VERSION 5.8 ;
BUSBITCHARS "[]" ;
DIVIDERCHAR "/" ;
UNITS
    DATABASE MICRONS 1000 ;
END UNITS

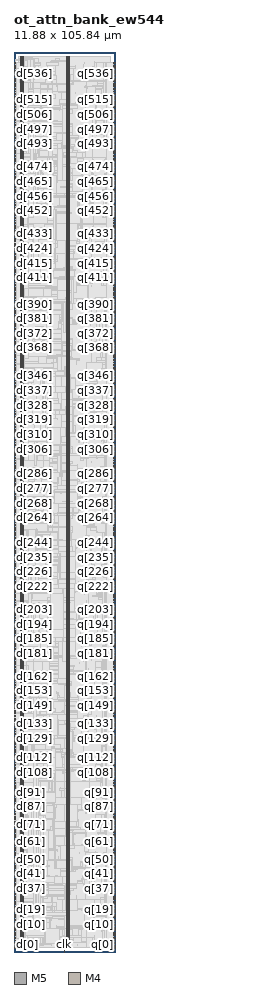
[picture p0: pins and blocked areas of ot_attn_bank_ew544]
MACRO ot_attn_bank_ew544
  FOREIGN ot_attn_bank_ew544 0 0 ;
  CLASS BLOCK ;
  SIZE 11.88 BY 105.84 ;
  PIN clk
    DIRECTION INPUT ;
    USE SIGNAL ;
    PORT
      LAYER M5 ;
        RECT  5.904 0 5.928 0.192 ;
    END
  END clk
  PIN d[0]
    DIRECTION INPUT ;
    USE SIGNAL ;
    PORT
      LAYER M4 ;
        RECT  0 0.384 0.192 0.408 ;
    END
  END d[0]
  PIN d[100]
    DIRECTION INPUT ;
    USE SIGNAL ;
    PORT
      LAYER M4 ;
        RECT  0 19.584 0.192 19.608 ;
    END
  END d[100]
  PIN d[101]
    DIRECTION INPUT ;
    USE SIGNAL ;
    PORT
      LAYER M4 ;
        RECT  0 19.776 0.192 19.8 ;
    END
  END d[101]
  PIN d[102]
    DIRECTION INPUT ;
    USE SIGNAL ;
    PORT
      LAYER M4 ;
        RECT  0 19.968 0.192 19.992 ;
    END
  END d[102]
  PIN d[103]
    DIRECTION INPUT ;
    USE SIGNAL ;
    PORT
      LAYER M4 ;
        RECT  0 20.16 0.192 20.184 ;
    END
  END d[103]
  PIN d[104]
    DIRECTION INPUT ;
    USE SIGNAL ;
    PORT
      LAYER M4 ;
        RECT  0 20.352 0.192 20.376 ;
    END
  END d[104]
  PIN d[105]
    DIRECTION INPUT ;
    USE SIGNAL ;
    PORT
      LAYER M4 ;
        RECT  0 20.544 0.192 20.568 ;
    END
  END d[105]
  PIN d[106]
    DIRECTION INPUT ;
    USE SIGNAL ;
    PORT
      LAYER M4 ;
        RECT  0 20.736 0.192 20.76 ;
    END
  END d[106]
  PIN d[107]
    DIRECTION INPUT ;
    USE SIGNAL ;
    PORT
      LAYER M4 ;
        RECT  0 20.928 0.192 20.952 ;
    END
  END d[107]
  PIN d[108]
    DIRECTION INPUT ;
    USE SIGNAL ;
    PORT
      LAYER M4 ;
        RECT  0 21.12 0.192 21.144 ;
    END
  END d[108]
  PIN d[109]
    DIRECTION INPUT ;
    USE SIGNAL ;
    PORT
      LAYER M4 ;
        RECT  0 21.312 0.192 21.336 ;
    END
  END d[109]
  PIN d[10]
    DIRECTION INPUT ;
    USE SIGNAL ;
    PORT
      LAYER M4 ;
        RECT  0 2.304 0.192 2.328 ;
    END
  END d[10]
  PIN d[110]
    DIRECTION INPUT ;
    USE SIGNAL ;
    PORT
      LAYER M4 ;
        RECT  0 21.504 0.192 21.528 ;
    END
  END d[110]
  PIN d[111]
    DIRECTION INPUT ;
    USE SIGNAL ;
    PORT
      LAYER M4 ;
        RECT  0 21.696 0.192 21.72 ;
    END
  END d[111]
  PIN d[112]
    DIRECTION INPUT ;
    USE SIGNAL ;
    PORT
      LAYER M4 ;
        RECT  0 21.888 0.192 21.912 ;
    END
  END d[112]
  PIN d[113]
    DIRECTION INPUT ;
    USE SIGNAL ;
    PORT
      LAYER M4 ;
        RECT  0 22.08 0.192 22.104 ;
    END
  END d[113]
  PIN d[114]
    DIRECTION INPUT ;
    USE SIGNAL ;
    PORT
      LAYER M4 ;
        RECT  0 22.272 0.192 22.296 ;
    END
  END d[114]
  PIN d[115]
    DIRECTION INPUT ;
    USE SIGNAL ;
    PORT
      LAYER M4 ;
        RECT  0 22.464 0.192 22.488 ;
    END
  END d[115]
  PIN d[116]
    DIRECTION INPUT ;
    USE SIGNAL ;
    PORT
      LAYER M4 ;
        RECT  0 22.656 0.192 22.68 ;
    END
  END d[116]
  PIN d[117]
    DIRECTION INPUT ;
    USE SIGNAL ;
    PORT
      LAYER M4 ;
        RECT  0 22.848 0.192 22.872 ;
    END
  END d[117]
  PIN d[118]
    DIRECTION INPUT ;
    USE SIGNAL ;
    PORT
      LAYER M4 ;
        RECT  0 23.04 0.192 23.064 ;
    END
  END d[118]
  PIN d[119]
    DIRECTION INPUT ;
    USE SIGNAL ;
    PORT
      LAYER M4 ;
        RECT  0 23.232 0.192 23.256 ;
    END
  END d[119]
  PIN d[11]
    DIRECTION INPUT ;
    USE SIGNAL ;
    PORT
      LAYER M4 ;
        RECT  0 2.496 0.192 2.52 ;
    END
  END d[11]
  PIN d[120]
    DIRECTION INPUT ;
    USE SIGNAL ;
    PORT
      LAYER M4 ;
        RECT  0 23.424 0.192 23.448 ;
    END
  END d[120]
  PIN d[121]
    DIRECTION INPUT ;
    USE SIGNAL ;
    PORT
      LAYER M4 ;
        RECT  0 23.616 0.192 23.64 ;
    END
  END d[121]
  PIN d[122]
    DIRECTION INPUT ;
    USE SIGNAL ;
    PORT
      LAYER M4 ;
        RECT  0 23.808 0.192 23.832 ;
    END
  END d[122]
  PIN d[123]
    DIRECTION INPUT ;
    USE SIGNAL ;
    PORT
      LAYER M4 ;
        RECT  0 24 0.192 24.024 ;
    END
  END d[123]
  PIN d[124]
    DIRECTION INPUT ;
    USE SIGNAL ;
    PORT
      LAYER M4 ;
        RECT  0 24.192 0.192 24.216 ;
    END
  END d[124]
  PIN d[125]
    DIRECTION INPUT ;
    USE SIGNAL ;
    PORT
      LAYER M4 ;
        RECT  0 24.384 0.192 24.408 ;
    END
  END d[125]
  PIN d[126]
    DIRECTION INPUT ;
    USE SIGNAL ;
    PORT
      LAYER M4 ;
        RECT  0 24.576 0.192 24.6 ;
    END
  END d[126]
  PIN d[127]
    DIRECTION INPUT ;
    USE SIGNAL ;
    PORT
      LAYER M4 ;
        RECT  0 24.768 0.192 24.792 ;
    END
  END d[127]
  PIN d[128]
    DIRECTION INPUT ;
    USE SIGNAL ;
    PORT
      LAYER M4 ;
        RECT  0 24.96 0.192 24.984 ;
    END
  END d[128]
  PIN d[129]
    DIRECTION INPUT ;
    USE SIGNAL ;
    PORT
      LAYER M4 ;
        RECT  0 25.152 0.192 25.176 ;
    END
  END d[129]
  PIN d[12]
    DIRECTION INPUT ;
    USE SIGNAL ;
    PORT
      LAYER M4 ;
        RECT  0 2.688 0.192 2.712 ;
    END
  END d[12]
  PIN d[130]
    DIRECTION INPUT ;
    USE SIGNAL ;
    PORT
      LAYER M4 ;
        RECT  0 25.344 0.192 25.368 ;
    END
  END d[130]
  PIN d[131]
    DIRECTION INPUT ;
    USE SIGNAL ;
    PORT
      LAYER M4 ;
        RECT  0 25.536 0.192 25.56 ;
    END
  END d[131]
  PIN d[132]
    DIRECTION INPUT ;
    USE SIGNAL ;
    PORT
      LAYER M4 ;
        RECT  0 25.728 0.192 25.752 ;
    END
  END d[132]
  PIN d[133]
    DIRECTION INPUT ;
    USE SIGNAL ;
    PORT
      LAYER M4 ;
        RECT  0 25.92 0.192 25.944 ;
    END
  END d[133]
  PIN d[134]
    DIRECTION INPUT ;
    USE SIGNAL ;
    PORT
      LAYER M4 ;
        RECT  0 26.112 0.192 26.136 ;
    END
  END d[134]
  PIN d[135]
    DIRECTION INPUT ;
    USE SIGNAL ;
    PORT
      LAYER M4 ;
        RECT  0 26.304 0.192 26.328 ;
    END
  END d[135]
  PIN d[136]
    DIRECTION INPUT ;
    USE SIGNAL ;
    PORT
      LAYER M4 ;
        RECT  0 26.496 0.192 26.52 ;
    END
  END d[136]
  PIN d[137]
    DIRECTION INPUT ;
    USE SIGNAL ;
    PORT
      LAYER M4 ;
        RECT  0 26.688 0.192 26.712 ;
    END
  END d[137]
  PIN d[138]
    DIRECTION INPUT ;
    USE SIGNAL ;
    PORT
      LAYER M4 ;
        RECT  0 26.88 0.192 26.904 ;
    END
  END d[138]
  PIN d[139]
    DIRECTION INPUT ;
    USE SIGNAL ;
    PORT
      LAYER M4 ;
        RECT  0 27.072 0.192 27.096 ;
    END
  END d[139]
  PIN d[13]
    DIRECTION INPUT ;
    USE SIGNAL ;
    PORT
      LAYER M4 ;
        RECT  0 2.88 0.192 2.904 ;
    END
  END d[13]
  PIN d[140]
    DIRECTION INPUT ;
    USE SIGNAL ;
    PORT
      LAYER M4 ;
        RECT  0 27.264 0.192 27.288 ;
    END
  END d[140]
  PIN d[141]
    DIRECTION INPUT ;
    USE SIGNAL ;
    PORT
      LAYER M4 ;
        RECT  0 27.456 0.192 27.48 ;
    END
  END d[141]
  PIN d[142]
    DIRECTION INPUT ;
    USE SIGNAL ;
    PORT
      LAYER M4 ;
        RECT  0 27.648 0.192 27.672 ;
    END
  END d[142]
  PIN d[143]
    DIRECTION INPUT ;
    USE SIGNAL ;
    PORT
      LAYER M4 ;
        RECT  0 27.84 0.192 27.864 ;
    END
  END d[143]
  PIN d[144]
    DIRECTION INPUT ;
    USE SIGNAL ;
    PORT
      LAYER M4 ;
        RECT  0 28.032 0.192 28.056 ;
    END
  END d[144]
  PIN d[145]
    DIRECTION INPUT ;
    USE SIGNAL ;
    PORT
      LAYER M4 ;
        RECT  0 28.224 0.192 28.248 ;
    END
  END d[145]
  PIN d[146]
    DIRECTION INPUT ;
    USE SIGNAL ;
    PORT
      LAYER M4 ;
        RECT  0 28.416 0.192 28.44 ;
    END
  END d[146]
  PIN d[147]
    DIRECTION INPUT ;
    USE SIGNAL ;
    PORT
      LAYER M4 ;
        RECT  0 28.608 0.192 28.632 ;
    END
  END d[147]
  PIN d[148]
    DIRECTION INPUT ;
    USE SIGNAL ;
    PORT
      LAYER M4 ;
        RECT  0 28.8 0.192 28.824 ;
    END
  END d[148]
  PIN d[149]
    DIRECTION INPUT ;
    USE SIGNAL ;
    PORT
      LAYER M4 ;
        RECT  0 28.992 0.192 29.016 ;
    END
  END d[149]
  PIN d[14]
    DIRECTION INPUT ;
    USE SIGNAL ;
    PORT
      LAYER M4 ;
        RECT  0 3.072 0.192 3.096 ;
    END
  END d[14]
  PIN d[150]
    DIRECTION INPUT ;
    USE SIGNAL ;
    PORT
      LAYER M4 ;
        RECT  0 29.184 0.192 29.208 ;
    END
  END d[150]
  PIN d[151]
    DIRECTION INPUT ;
    USE SIGNAL ;
    PORT
      LAYER M4 ;
        RECT  0 29.376 0.192 29.4 ;
    END
  END d[151]
  PIN d[152]
    DIRECTION INPUT ;
    USE SIGNAL ;
    PORT
      LAYER M4 ;
        RECT  0 29.568 0.192 29.592 ;
    END
  END d[152]
  PIN d[153]
    DIRECTION INPUT ;
    USE SIGNAL ;
    PORT
      LAYER M4 ;
        RECT  0 29.76 0.192 29.784 ;
    END
  END d[153]
  PIN d[154]
    DIRECTION INPUT ;
    USE SIGNAL ;
    PORT
      LAYER M4 ;
        RECT  0 29.952 0.192 29.976 ;
    END
  END d[154]
  PIN d[155]
    DIRECTION INPUT ;
    USE SIGNAL ;
    PORT
      LAYER M4 ;
        RECT  0 30.144 0.192 30.168 ;
    END
  END d[155]
  PIN d[156]
    DIRECTION INPUT ;
    USE SIGNAL ;
    PORT
      LAYER M4 ;
        RECT  0 30.336 0.192 30.36 ;
    END
  END d[156]
  PIN d[157]
    DIRECTION INPUT ;
    USE SIGNAL ;
    PORT
      LAYER M4 ;
        RECT  0 30.528 0.192 30.552 ;
    END
  END d[157]
  PIN d[158]
    DIRECTION INPUT ;
    USE SIGNAL ;
    PORT
      LAYER M4 ;
        RECT  0 30.72 0.192 30.744 ;
    END
  END d[158]
  PIN d[159]
    DIRECTION INPUT ;
    USE SIGNAL ;
    PORT
      LAYER M4 ;
        RECT  0 30.912 0.192 30.936 ;
    END
  END d[159]
  PIN d[15]
    DIRECTION INPUT ;
    USE SIGNAL ;
    PORT
      LAYER M4 ;
        RECT  0 3.264 0.192 3.288 ;
    END
  END d[15]
  PIN d[160]
    DIRECTION INPUT ;
    USE SIGNAL ;
    PORT
      LAYER M4 ;
        RECT  0 31.104 0.192 31.128 ;
    END
  END d[160]
  PIN d[161]
    DIRECTION INPUT ;
    USE SIGNAL ;
    PORT
      LAYER M4 ;
        RECT  0 31.296 0.192 31.32 ;
    END
  END d[161]
  PIN d[162]
    DIRECTION INPUT ;
    USE SIGNAL ;
    PORT
      LAYER M4 ;
        RECT  0 31.488 0.192 31.512 ;
    END
  END d[162]
  PIN d[163]
    DIRECTION INPUT ;
    USE SIGNAL ;
    PORT
      LAYER M4 ;
        RECT  0 31.68 0.192 31.704 ;
    END
  END d[163]
  PIN d[164]
    DIRECTION INPUT ;
    USE SIGNAL ;
    PORT
      LAYER M4 ;
        RECT  0 31.872 0.192 31.896 ;
    END
  END d[164]
  PIN d[165]
    DIRECTION INPUT ;
    USE SIGNAL ;
    PORT
      LAYER M4 ;
        RECT  0 32.064 0.192 32.088 ;
    END
  END d[165]
  PIN d[166]
    DIRECTION INPUT ;
    USE SIGNAL ;
    PORT
      LAYER M4 ;
        RECT  0 32.256 0.192 32.28 ;
    END
  END d[166]
  PIN d[167]
    DIRECTION INPUT ;
    USE SIGNAL ;
    PORT
      LAYER M4 ;
        RECT  0 32.448 0.192 32.472 ;
    END
  END d[167]
  PIN d[168]
    DIRECTION INPUT ;
    USE SIGNAL ;
    PORT
      LAYER M4 ;
        RECT  0 32.64 0.192 32.664 ;
    END
  END d[168]
  PIN d[169]
    DIRECTION INPUT ;
    USE SIGNAL ;
    PORT
      LAYER M4 ;
        RECT  0 32.832 0.192 32.856 ;
    END
  END d[169]
  PIN d[16]
    DIRECTION INPUT ;
    USE SIGNAL ;
    PORT
      LAYER M4 ;
        RECT  0 3.456 0.192 3.48 ;
    END
  END d[16]
  PIN d[170]
    DIRECTION INPUT ;
    USE SIGNAL ;
    PORT
      LAYER M4 ;
        RECT  0 33.024 0.192 33.048 ;
    END
  END d[170]
  PIN d[171]
    DIRECTION INPUT ;
    USE SIGNAL ;
    PORT
      LAYER M4 ;
        RECT  0 33.216 0.192 33.24 ;
    END
  END d[171]
  PIN d[172]
    DIRECTION INPUT ;
    USE SIGNAL ;
    PORT
      LAYER M4 ;
        RECT  0 33.408 0.192 33.432 ;
    END
  END d[172]
  PIN d[173]
    DIRECTION INPUT ;
    USE SIGNAL ;
    PORT
      LAYER M4 ;
        RECT  0 33.6 0.192 33.624 ;
    END
  END d[173]
  PIN d[174]
    DIRECTION INPUT ;
    USE SIGNAL ;
    PORT
      LAYER M4 ;
        RECT  0 33.792 0.192 33.816 ;
    END
  END d[174]
  PIN d[175]
    DIRECTION INPUT ;
    USE SIGNAL ;
    PORT
      LAYER M4 ;
        RECT  0 33.984 0.192 34.008 ;
    END
  END d[175]
  PIN d[176]
    DIRECTION INPUT ;
    USE SIGNAL ;
    PORT
      LAYER M4 ;
        RECT  0 34.176 0.192 34.2 ;
    END
  END d[176]
  PIN d[177]
    DIRECTION INPUT ;
    USE SIGNAL ;
    PORT
      LAYER M4 ;
        RECT  0 34.368 0.192 34.392 ;
    END
  END d[177]
  PIN d[178]
    DIRECTION INPUT ;
    USE SIGNAL ;
    PORT
      LAYER M4 ;
        RECT  0 34.56 0.192 34.584 ;
    END
  END d[178]
  PIN d[179]
    DIRECTION INPUT ;
    USE SIGNAL ;
    PORT
      LAYER M4 ;
        RECT  0 34.752 0.192 34.776 ;
    END
  END d[179]
  PIN d[17]
    DIRECTION INPUT ;
    USE SIGNAL ;
    PORT
      LAYER M4 ;
        RECT  0 3.648 0.192 3.672 ;
    END
  END d[17]
  PIN d[180]
    DIRECTION INPUT ;
    USE SIGNAL ;
    PORT
      LAYER M4 ;
        RECT  0 34.944 0.192 34.968 ;
    END
  END d[180]
  PIN d[181]
    DIRECTION INPUT ;
    USE SIGNAL ;
    PORT
      LAYER M4 ;
        RECT  0 35.136 0.192 35.16 ;
    END
  END d[181]
  PIN d[182]
    DIRECTION INPUT ;
    USE SIGNAL ;
    PORT
      LAYER M4 ;
        RECT  0 35.328 0.192 35.352 ;
    END
  END d[182]
  PIN d[183]
    DIRECTION INPUT ;
    USE SIGNAL ;
    PORT
      LAYER M4 ;
        RECT  0 35.52 0.192 35.544 ;
    END
  END d[183]
  PIN d[184]
    DIRECTION INPUT ;
    USE SIGNAL ;
    PORT
      LAYER M4 ;
        RECT  0 35.712 0.192 35.736 ;
    END
  END d[184]
  PIN d[185]
    DIRECTION INPUT ;
    USE SIGNAL ;
    PORT
      LAYER M4 ;
        RECT  0 35.904 0.192 35.928 ;
    END
  END d[185]
  PIN d[186]
    DIRECTION INPUT ;
    USE SIGNAL ;
    PORT
      LAYER M4 ;
        RECT  0 36.096 0.192 36.12 ;
    END
  END d[186]
  PIN d[187]
    DIRECTION INPUT ;
    USE SIGNAL ;
    PORT
      LAYER M4 ;
        RECT  0 36.288 0.192 36.312 ;
    END
  END d[187]
  PIN d[188]
    DIRECTION INPUT ;
    USE SIGNAL ;
    PORT
      LAYER M4 ;
        RECT  0 36.48 0.192 36.504 ;
    END
  END d[188]
  PIN d[189]
    DIRECTION INPUT ;
    USE SIGNAL ;
    PORT
      LAYER M4 ;
        RECT  0 36.672 0.192 36.696 ;
    END
  END d[189]
  PIN d[18]
    DIRECTION INPUT ;
    USE SIGNAL ;
    PORT
      LAYER M4 ;
        RECT  0 3.84 0.192 3.864 ;
    END
  END d[18]
  PIN d[190]
    DIRECTION INPUT ;
    USE SIGNAL ;
    PORT
      LAYER M4 ;
        RECT  0 36.864 0.192 36.888 ;
    END
  END d[190]
  PIN d[191]
    DIRECTION INPUT ;
    USE SIGNAL ;
    PORT
      LAYER M4 ;
        RECT  0 37.056 0.192 37.08 ;
    END
  END d[191]
  PIN d[192]
    DIRECTION INPUT ;
    USE SIGNAL ;
    PORT
      LAYER M4 ;
        RECT  0 37.248 0.192 37.272 ;
    END
  END d[192]
  PIN d[193]
    DIRECTION INPUT ;
    USE SIGNAL ;
    PORT
      LAYER M4 ;
        RECT  0 37.44 0.192 37.464 ;
    END
  END d[193]
  PIN d[194]
    DIRECTION INPUT ;
    USE SIGNAL ;
    PORT
      LAYER M4 ;
        RECT  0 37.632 0.192 37.656 ;
    END
  END d[194]
  PIN d[195]
    DIRECTION INPUT ;
    USE SIGNAL ;
    PORT
      LAYER M4 ;
        RECT  0 37.824 0.192 37.848 ;
    END
  END d[195]
  PIN d[196]
    DIRECTION INPUT ;
    USE SIGNAL ;
    PORT
      LAYER M4 ;
        RECT  0 38.016 0.192 38.04 ;
    END
  END d[196]
  PIN d[197]
    DIRECTION INPUT ;
    USE SIGNAL ;
    PORT
      LAYER M4 ;
        RECT  0 38.208 0.192 38.232 ;
    END
  END d[197]
  PIN d[198]
    DIRECTION INPUT ;
    USE SIGNAL ;
    PORT
      LAYER M4 ;
        RECT  0 38.4 0.192 38.424 ;
    END
  END d[198]
  PIN d[199]
    DIRECTION INPUT ;
    USE SIGNAL ;
    PORT
      LAYER M4 ;
        RECT  0 38.592 0.192 38.616 ;
    END
  END d[199]
  PIN d[19]
    DIRECTION INPUT ;
    USE SIGNAL ;
    PORT
      LAYER M4 ;
        RECT  0 4.032 0.192 4.056 ;
    END
  END d[19]
  PIN d[1]
    DIRECTION INPUT ;
    USE SIGNAL ;
    PORT
      LAYER M4 ;
        RECT  0 0.576 0.192 0.6 ;
    END
  END d[1]
  PIN d[200]
    DIRECTION INPUT ;
    USE SIGNAL ;
    PORT
      LAYER M4 ;
        RECT  0 38.784 0.192 38.808 ;
    END
  END d[200]
  PIN d[201]
    DIRECTION INPUT ;
    USE SIGNAL ;
    PORT
      LAYER M4 ;
        RECT  0 38.976 0.192 39 ;
    END
  END d[201]
  PIN d[202]
    DIRECTION INPUT ;
    USE SIGNAL ;
    PORT
      LAYER M4 ;
        RECT  0 39.168 0.192 39.192 ;
    END
  END d[202]
  PIN d[203]
    DIRECTION INPUT ;
    USE SIGNAL ;
    PORT
      LAYER M4 ;
        RECT  0 39.36 0.192 39.384 ;
    END
  END d[203]
  PIN d[204]
    DIRECTION INPUT ;
    USE SIGNAL ;
    PORT
      LAYER M4 ;
        RECT  0 39.552 0.192 39.576 ;
    END
  END d[204]
  PIN d[205]
    DIRECTION INPUT ;
    USE SIGNAL ;
    PORT
      LAYER M4 ;
        RECT  0 39.744 0.192 39.768 ;
    END
  END d[205]
  PIN d[206]
    DIRECTION INPUT ;
    USE SIGNAL ;
    PORT
      LAYER M4 ;
        RECT  0 39.936 0.192 39.96 ;
    END
  END d[206]
  PIN d[207]
    DIRECTION INPUT ;
    USE SIGNAL ;
    PORT
      LAYER M4 ;
        RECT  0 40.128 0.192 40.152 ;
    END
  END d[207]
  PIN d[208]
    DIRECTION INPUT ;
    USE SIGNAL ;
    PORT
      LAYER M4 ;
        RECT  0 40.32 0.192 40.344 ;
    END
  END d[208]
  PIN d[209]
    DIRECTION INPUT ;
    USE SIGNAL ;
    PORT
      LAYER M4 ;
        RECT  0 40.512 0.192 40.536 ;
    END
  END d[209]
  PIN d[20]
    DIRECTION INPUT ;
    USE SIGNAL ;
    PORT
      LAYER M4 ;
        RECT  0 4.224 0.192 4.248 ;
    END
  END d[20]
  PIN d[210]
    DIRECTION INPUT ;
    USE SIGNAL ;
    PORT
      LAYER M4 ;
        RECT  0 40.704 0.192 40.728 ;
    END
  END d[210]
  PIN d[211]
    DIRECTION INPUT ;
    USE SIGNAL ;
    PORT
      LAYER M4 ;
        RECT  0 40.896 0.192 40.92 ;
    END
  END d[211]
  PIN d[212]
    DIRECTION INPUT ;
    USE SIGNAL ;
    PORT
      LAYER M4 ;
        RECT  0 41.088 0.192 41.112 ;
    END
  END d[212]
  PIN d[213]
    DIRECTION INPUT ;
    USE SIGNAL ;
    PORT
      LAYER M4 ;
        RECT  0 41.28 0.192 41.304 ;
    END
  END d[213]
  PIN d[214]
    DIRECTION INPUT ;
    USE SIGNAL ;
    PORT
      LAYER M4 ;
        RECT  0 41.472 0.192 41.496 ;
    END
  END d[214]
  PIN d[215]
    DIRECTION INPUT ;
    USE SIGNAL ;
    PORT
      LAYER M4 ;
        RECT  0 41.664 0.192 41.688 ;
    END
  END d[215]
  PIN d[216]
    DIRECTION INPUT ;
    USE SIGNAL ;
    PORT
      LAYER M4 ;
        RECT  0 41.856 0.192 41.88 ;
    END
  END d[216]
  PIN d[217]
    DIRECTION INPUT ;
    USE SIGNAL ;
    PORT
      LAYER M4 ;
        RECT  0 42.048 0.192 42.072 ;
    END
  END d[217]
  PIN d[218]
    DIRECTION INPUT ;
    USE SIGNAL ;
    PORT
      LAYER M4 ;
        RECT  0 42.24 0.192 42.264 ;
    END
  END d[218]
  PIN d[219]
    DIRECTION INPUT ;
    USE SIGNAL ;
    PORT
      LAYER M4 ;
        RECT  0 42.432 0.192 42.456 ;
    END
  END d[219]
  PIN d[21]
    DIRECTION INPUT ;
    USE SIGNAL ;
    PORT
      LAYER M4 ;
        RECT  0 4.416 0.192 4.44 ;
    END
  END d[21]
  PIN d[220]
    DIRECTION INPUT ;
    USE SIGNAL ;
    PORT
      LAYER M4 ;
        RECT  0 42.624 0.192 42.648 ;
    END
  END d[220]
  PIN d[221]
    DIRECTION INPUT ;
    USE SIGNAL ;
    PORT
      LAYER M4 ;
        RECT  0 42.816 0.192 42.84 ;
    END
  END d[221]
  PIN d[222]
    DIRECTION INPUT ;
    USE SIGNAL ;
    PORT
      LAYER M4 ;
        RECT  0 43.008 0.192 43.032 ;
    END
  END d[222]
  PIN d[223]
    DIRECTION INPUT ;
    USE SIGNAL ;
    PORT
      LAYER M4 ;
        RECT  0 43.2 0.192 43.224 ;
    END
  END d[223]
  PIN d[224]
    DIRECTION INPUT ;
    USE SIGNAL ;
    PORT
      LAYER M4 ;
        RECT  0 43.392 0.192 43.416 ;
    END
  END d[224]
  PIN d[225]
    DIRECTION INPUT ;
    USE SIGNAL ;
    PORT
      LAYER M4 ;
        RECT  0 43.584 0.192 43.608 ;
    END
  END d[225]
  PIN d[226]
    DIRECTION INPUT ;
    USE SIGNAL ;
    PORT
      LAYER M4 ;
        RECT  0 43.776 0.192 43.8 ;
    END
  END d[226]
  PIN d[227]
    DIRECTION INPUT ;
    USE SIGNAL ;
    PORT
      LAYER M4 ;
        RECT  0 43.968 0.192 43.992 ;
    END
  END d[227]
  PIN d[228]
    DIRECTION INPUT ;
    USE SIGNAL ;
    PORT
      LAYER M4 ;
        RECT  0 44.16 0.192 44.184 ;
    END
  END d[228]
  PIN d[229]
    DIRECTION INPUT ;
    USE SIGNAL ;
    PORT
      LAYER M4 ;
        RECT  0 44.352 0.192 44.376 ;
    END
  END d[229]
  PIN d[22]
    DIRECTION INPUT ;
    USE SIGNAL ;
    PORT
      LAYER M4 ;
        RECT  0 4.608 0.192 4.632 ;
    END
  END d[22]
  PIN d[230]
    DIRECTION INPUT ;
    USE SIGNAL ;
    PORT
      LAYER M4 ;
        RECT  0 44.544 0.192 44.568 ;
    END
  END d[230]
  PIN d[231]
    DIRECTION INPUT ;
    USE SIGNAL ;
    PORT
      LAYER M4 ;
        RECT  0 44.736 0.192 44.76 ;
    END
  END d[231]
  PIN d[232]
    DIRECTION INPUT ;
    USE SIGNAL ;
    PORT
      LAYER M4 ;
        RECT  0 44.928 0.192 44.952 ;
    END
  END d[232]
  PIN d[233]
    DIRECTION INPUT ;
    USE SIGNAL ;
    PORT
      LAYER M4 ;
        RECT  0 45.12 0.192 45.144 ;
    END
  END d[233]
  PIN d[234]
    DIRECTION INPUT ;
    USE SIGNAL ;
    PORT
      LAYER M4 ;
        RECT  0 45.312 0.192 45.336 ;
    END
  END d[234]
  PIN d[235]
    DIRECTION INPUT ;
    USE SIGNAL ;
    PORT
      LAYER M4 ;
        RECT  0 45.504 0.192 45.528 ;
    END
  END d[235]
  PIN d[236]
    DIRECTION INPUT ;
    USE SIGNAL ;
    PORT
      LAYER M4 ;
        RECT  0 45.696 0.192 45.72 ;
    END
  END d[236]
  PIN d[237]
    DIRECTION INPUT ;
    USE SIGNAL ;
    PORT
      LAYER M4 ;
        RECT  0 45.888 0.192 45.912 ;
    END
  END d[237]
  PIN d[238]
    DIRECTION INPUT ;
    USE SIGNAL ;
    PORT
      LAYER M4 ;
        RECT  0 46.08 0.192 46.104 ;
    END
  END d[238]
  PIN d[239]
    DIRECTION INPUT ;
    USE SIGNAL ;
    PORT
      LAYER M4 ;
        RECT  0 46.272 0.192 46.296 ;
    END
  END d[239]
  PIN d[23]
    DIRECTION INPUT ;
    USE SIGNAL ;
    PORT
      LAYER M4 ;
        RECT  0 4.8 0.192 4.824 ;
    END
  END d[23]
  PIN d[240]
    DIRECTION INPUT ;
    USE SIGNAL ;
    PORT
      LAYER M4 ;
        RECT  0 46.464 0.192 46.488 ;
    END
  END d[240]
  PIN d[241]
    DIRECTION INPUT ;
    USE SIGNAL ;
    PORT
      LAYER M4 ;
        RECT  0 46.656 0.192 46.68 ;
    END
  END d[241]
  PIN d[242]
    DIRECTION INPUT ;
    USE SIGNAL ;
    PORT
      LAYER M4 ;
        RECT  0 46.848 0.192 46.872 ;
    END
  END d[242]
  PIN d[243]
    DIRECTION INPUT ;
    USE SIGNAL ;
    PORT
      LAYER M4 ;
        RECT  0 47.04 0.192 47.064 ;
    END
  END d[243]
  PIN d[244]
    DIRECTION INPUT ;
    USE SIGNAL ;
    PORT
      LAYER M4 ;
        RECT  0 47.232 0.192 47.256 ;
    END
  END d[244]
  PIN d[245]
    DIRECTION INPUT ;
    USE SIGNAL ;
    PORT
      LAYER M4 ;
        RECT  0 47.424 0.192 47.448 ;
    END
  END d[245]
  PIN d[246]
    DIRECTION INPUT ;
    USE SIGNAL ;
    PORT
      LAYER M4 ;
        RECT  0 47.616 0.192 47.64 ;
    END
  END d[246]
  PIN d[247]
    DIRECTION INPUT ;
    USE SIGNAL ;
    PORT
      LAYER M4 ;
        RECT  0 47.808 0.192 47.832 ;
    END
  END d[247]
  PIN d[248]
    DIRECTION INPUT ;
    USE SIGNAL ;
    PORT
      LAYER M4 ;
        RECT  0 48 0.192 48.024 ;
    END
  END d[248]
  PIN d[249]
    DIRECTION INPUT ;
    USE SIGNAL ;
    PORT
      LAYER M4 ;
        RECT  0 48.192 0.192 48.216 ;
    END
  END d[249]
  PIN d[24]
    DIRECTION INPUT ;
    USE SIGNAL ;
    PORT
      LAYER M4 ;
        RECT  0 4.992 0.192 5.016 ;
    END
  END d[24]
  PIN d[250]
    DIRECTION INPUT ;
    USE SIGNAL ;
    PORT
      LAYER M4 ;
        RECT  0 48.384 0.192 48.408 ;
    END
  END d[250]
  PIN d[251]
    DIRECTION INPUT ;
    USE SIGNAL ;
    PORT
      LAYER M4 ;
        RECT  0 48.576 0.192 48.6 ;
    END
  END d[251]
  PIN d[252]
    DIRECTION INPUT ;
    USE SIGNAL ;
    PORT
      LAYER M4 ;
        RECT  0 48.768 0.192 48.792 ;
    END
  END d[252]
  PIN d[253]
    DIRECTION INPUT ;
    USE SIGNAL ;
    PORT
      LAYER M4 ;
        RECT  0 48.96 0.192 48.984 ;
    END
  END d[253]
  PIN d[254]
    DIRECTION INPUT ;
    USE SIGNAL ;
    PORT
      LAYER M4 ;
        RECT  0 49.152 0.192 49.176 ;
    END
  END d[254]
  PIN d[255]
    DIRECTION INPUT ;
    USE SIGNAL ;
    PORT
      LAYER M4 ;
        RECT  0 49.344 0.192 49.368 ;
    END
  END d[255]
  PIN d[256]
    DIRECTION INPUT ;
    USE SIGNAL ;
    PORT
      LAYER M4 ;
        RECT  0 49.536 0.192 49.56 ;
    END
  END d[256]
  PIN d[257]
    DIRECTION INPUT ;
    USE SIGNAL ;
    PORT
      LAYER M4 ;
        RECT  0 49.728 0.192 49.752 ;
    END
  END d[257]
  PIN d[258]
    DIRECTION INPUT ;
    USE SIGNAL ;
    PORT
      LAYER M4 ;
        RECT  0 49.92 0.192 49.944 ;
    END
  END d[258]
  PIN d[259]
    DIRECTION INPUT ;
    USE SIGNAL ;
    PORT
      LAYER M4 ;
        RECT  0 50.112 0.192 50.136 ;
    END
  END d[259]
  PIN d[25]
    DIRECTION INPUT ;
    USE SIGNAL ;
    PORT
      LAYER M4 ;
        RECT  0 5.184 0.192 5.208 ;
    END
  END d[25]
  PIN d[260]
    DIRECTION INPUT ;
    USE SIGNAL ;
    PORT
      LAYER M4 ;
        RECT  0 50.304 0.192 50.328 ;
    END
  END d[260]
  PIN d[261]
    DIRECTION INPUT ;
    USE SIGNAL ;
    PORT
      LAYER M4 ;
        RECT  0 50.496 0.192 50.52 ;
    END
  END d[261]
  PIN d[262]
    DIRECTION INPUT ;
    USE SIGNAL ;
    PORT
      LAYER M4 ;
        RECT  0 50.688 0.192 50.712 ;
    END
  END d[262]
  PIN d[263]
    DIRECTION INPUT ;
    USE SIGNAL ;
    PORT
      LAYER M4 ;
        RECT  0 50.88 0.192 50.904 ;
    END
  END d[263]
  PIN d[264]
    DIRECTION INPUT ;
    USE SIGNAL ;
    PORT
      LAYER M4 ;
        RECT  0 51.072 0.192 51.096 ;
    END
  END d[264]
  PIN d[265]
    DIRECTION INPUT ;
    USE SIGNAL ;
    PORT
      LAYER M4 ;
        RECT  0 51.264 0.192 51.288 ;
    END
  END d[265]
  PIN d[266]
    DIRECTION INPUT ;
    USE SIGNAL ;
    PORT
      LAYER M4 ;
        RECT  0 51.456 0.192 51.48 ;
    END
  END d[266]
  PIN d[267]
    DIRECTION INPUT ;
    USE SIGNAL ;
    PORT
      LAYER M4 ;
        RECT  0 51.648 0.192 51.672 ;
    END
  END d[267]
  PIN d[268]
    DIRECTION INPUT ;
    USE SIGNAL ;
    PORT
      LAYER M4 ;
        RECT  0 51.84 0.192 51.864 ;
    END
  END d[268]
  PIN d[269]
    DIRECTION INPUT ;
    USE SIGNAL ;
    PORT
      LAYER M4 ;
        RECT  0 52.032 0.192 52.056 ;
    END
  END d[269]
  PIN d[26]
    DIRECTION INPUT ;
    USE SIGNAL ;
    PORT
      LAYER M4 ;
        RECT  0 5.376 0.192 5.4 ;
    END
  END d[26]
  PIN d[270]
    DIRECTION INPUT ;
    USE SIGNAL ;
    PORT
      LAYER M4 ;
        RECT  0 52.224 0.192 52.248 ;
    END
  END d[270]
  PIN d[271]
    DIRECTION INPUT ;
    USE SIGNAL ;
    PORT
      LAYER M4 ;
        RECT  0 52.416 0.192 52.44 ;
    END
  END d[271]
  PIN d[272]
    DIRECTION INPUT ;
    USE SIGNAL ;
    PORT
      LAYER M4 ;
        RECT  0 52.608 0.192 52.632 ;
    END
  END d[272]
  PIN d[273]
    DIRECTION INPUT ;
    USE SIGNAL ;
    PORT
      LAYER M4 ;
        RECT  0 52.8 0.192 52.824 ;
    END
  END d[273]
  PIN d[274]
    DIRECTION INPUT ;
    USE SIGNAL ;
    PORT
      LAYER M4 ;
        RECT  0 52.992 0.192 53.016 ;
    END
  END d[274]
  PIN d[275]
    DIRECTION INPUT ;
    USE SIGNAL ;
    PORT
      LAYER M4 ;
        RECT  0 53.184 0.192 53.208 ;
    END
  END d[275]
  PIN d[276]
    DIRECTION INPUT ;
    USE SIGNAL ;
    PORT
      LAYER M4 ;
        RECT  0 53.376 0.192 53.4 ;
    END
  END d[276]
  PIN d[277]
    DIRECTION INPUT ;
    USE SIGNAL ;
    PORT
      LAYER M4 ;
        RECT  0 53.568 0.192 53.592 ;
    END
  END d[277]
  PIN d[278]
    DIRECTION INPUT ;
    USE SIGNAL ;
    PORT
      LAYER M4 ;
        RECT  0 53.76 0.192 53.784 ;
    END
  END d[278]
  PIN d[279]
    DIRECTION INPUT ;
    USE SIGNAL ;
    PORT
      LAYER M4 ;
        RECT  0 53.952 0.192 53.976 ;
    END
  END d[279]
  PIN d[27]
    DIRECTION INPUT ;
    USE SIGNAL ;
    PORT
      LAYER M4 ;
        RECT  0 5.568 0.192 5.592 ;
    END
  END d[27]
  PIN d[280]
    DIRECTION INPUT ;
    USE SIGNAL ;
    PORT
      LAYER M4 ;
        RECT  0 54.144 0.192 54.168 ;
    END
  END d[280]
  PIN d[281]
    DIRECTION INPUT ;
    USE SIGNAL ;
    PORT
      LAYER M4 ;
        RECT  0 54.336 0.192 54.36 ;
    END
  END d[281]
  PIN d[282]
    DIRECTION INPUT ;
    USE SIGNAL ;
    PORT
      LAYER M4 ;
        RECT  0 54.528 0.192 54.552 ;
    END
  END d[282]
  PIN d[283]
    DIRECTION INPUT ;
    USE SIGNAL ;
    PORT
      LAYER M4 ;
        RECT  0 54.72 0.192 54.744 ;
    END
  END d[283]
  PIN d[284]
    DIRECTION INPUT ;
    USE SIGNAL ;
    PORT
      LAYER M4 ;
        RECT  0 54.912 0.192 54.936 ;
    END
  END d[284]
  PIN d[285]
    DIRECTION INPUT ;
    USE SIGNAL ;
    PORT
      LAYER M4 ;
        RECT  0 55.104 0.192 55.128 ;
    END
  END d[285]
  PIN d[286]
    DIRECTION INPUT ;
    USE SIGNAL ;
    PORT
      LAYER M4 ;
        RECT  0 55.296 0.192 55.32 ;
    END
  END d[286]
  PIN d[287]
    DIRECTION INPUT ;
    USE SIGNAL ;
    PORT
      LAYER M4 ;
        RECT  0 55.488 0.192 55.512 ;
    END
  END d[287]
  PIN d[288]
    DIRECTION INPUT ;
    USE SIGNAL ;
    PORT
      LAYER M4 ;
        RECT  0 55.68 0.192 55.704 ;
    END
  END d[288]
  PIN d[289]
    DIRECTION INPUT ;
    USE SIGNAL ;
    PORT
      LAYER M4 ;
        RECT  0 55.872 0.192 55.896 ;
    END
  END d[289]
  PIN d[28]
    DIRECTION INPUT ;
    USE SIGNAL ;
    PORT
      LAYER M4 ;
        RECT  0 5.76 0.192 5.784 ;
    END
  END d[28]
  PIN d[290]
    DIRECTION INPUT ;
    USE SIGNAL ;
    PORT
      LAYER M4 ;
        RECT  0 56.064 0.192 56.088 ;
    END
  END d[290]
  PIN d[291]
    DIRECTION INPUT ;
    USE SIGNAL ;
    PORT
      LAYER M4 ;
        RECT  0 56.256 0.192 56.28 ;
    END
  END d[291]
  PIN d[292]
    DIRECTION INPUT ;
    USE SIGNAL ;
    PORT
      LAYER M4 ;
        RECT  0 56.448 0.192 56.472 ;
    END
  END d[292]
  PIN d[293]
    DIRECTION INPUT ;
    USE SIGNAL ;
    PORT
      LAYER M4 ;
        RECT  0 56.64 0.192 56.664 ;
    END
  END d[293]
  PIN d[294]
    DIRECTION INPUT ;
    USE SIGNAL ;
    PORT
      LAYER M4 ;
        RECT  0 56.832 0.192 56.856 ;
    END
  END d[294]
  PIN d[295]
    DIRECTION INPUT ;
    USE SIGNAL ;
    PORT
      LAYER M4 ;
        RECT  0 57.024 0.192 57.048 ;
    END
  END d[295]
  PIN d[296]
    DIRECTION INPUT ;
    USE SIGNAL ;
    PORT
      LAYER M4 ;
        RECT  0 57.216 0.192 57.24 ;
    END
  END d[296]
  PIN d[297]
    DIRECTION INPUT ;
    USE SIGNAL ;
    PORT
      LAYER M4 ;
        RECT  0 57.408 0.192 57.432 ;
    END
  END d[297]
  PIN d[298]
    DIRECTION INPUT ;
    USE SIGNAL ;
    PORT
      LAYER M4 ;
        RECT  0 57.6 0.192 57.624 ;
    END
  END d[298]
  PIN d[299]
    DIRECTION INPUT ;
    USE SIGNAL ;
    PORT
      LAYER M4 ;
        RECT  0 57.792 0.192 57.816 ;
    END
  END d[299]
  PIN d[29]
    DIRECTION INPUT ;
    USE SIGNAL ;
    PORT
      LAYER M4 ;
        RECT  0 5.952 0.192 5.976 ;
    END
  END d[29]
  PIN d[2]
    DIRECTION INPUT ;
    USE SIGNAL ;
    PORT
      LAYER M4 ;
        RECT  0 0.768 0.192 0.792 ;
    END
  END d[2]
  PIN d[300]
    DIRECTION INPUT ;
    USE SIGNAL ;
    PORT
      LAYER M4 ;
        RECT  0 57.984 0.192 58.008 ;
    END
  END d[300]
  PIN d[301]
    DIRECTION INPUT ;
    USE SIGNAL ;
    PORT
      LAYER M4 ;
        RECT  0 58.176 0.192 58.2 ;
    END
  END d[301]
  PIN d[302]
    DIRECTION INPUT ;
    USE SIGNAL ;
    PORT
      LAYER M4 ;
        RECT  0 58.368 0.192 58.392 ;
    END
  END d[302]
  PIN d[303]
    DIRECTION INPUT ;
    USE SIGNAL ;
    PORT
      LAYER M4 ;
        RECT  0 58.56 0.192 58.584 ;
    END
  END d[303]
  PIN d[304]
    DIRECTION INPUT ;
    USE SIGNAL ;
    PORT
      LAYER M4 ;
        RECT  0 58.752 0.192 58.776 ;
    END
  END d[304]
  PIN d[305]
    DIRECTION INPUT ;
    USE SIGNAL ;
    PORT
      LAYER M4 ;
        RECT  0 58.944 0.192 58.968 ;
    END
  END d[305]
  PIN d[306]
    DIRECTION INPUT ;
    USE SIGNAL ;
    PORT
      LAYER M4 ;
        RECT  0 59.136 0.192 59.16 ;
    END
  END d[306]
  PIN d[307]
    DIRECTION INPUT ;
    USE SIGNAL ;
    PORT
      LAYER M4 ;
        RECT  0 59.328 0.192 59.352 ;
    END
  END d[307]
  PIN d[308]
    DIRECTION INPUT ;
    USE SIGNAL ;
    PORT
      LAYER M4 ;
        RECT  0 59.52 0.192 59.544 ;
    END
  END d[308]
  PIN d[309]
    DIRECTION INPUT ;
    USE SIGNAL ;
    PORT
      LAYER M4 ;
        RECT  0 59.712 0.192 59.736 ;
    END
  END d[309]
  PIN d[30]
    DIRECTION INPUT ;
    USE SIGNAL ;
    PORT
      LAYER M4 ;
        RECT  0 6.144 0.192 6.168 ;
    END
  END d[30]
  PIN d[310]
    DIRECTION INPUT ;
    USE SIGNAL ;
    PORT
      LAYER M4 ;
        RECT  0 59.904 0.192 59.928 ;
    END
  END d[310]
  PIN d[311]
    DIRECTION INPUT ;
    USE SIGNAL ;
    PORT
      LAYER M4 ;
        RECT  0 60.096 0.192 60.12 ;
    END
  END d[311]
  PIN d[312]
    DIRECTION INPUT ;
    USE SIGNAL ;
    PORT
      LAYER M4 ;
        RECT  0 60.288 0.192 60.312 ;
    END
  END d[312]
  PIN d[313]
    DIRECTION INPUT ;
    USE SIGNAL ;
    PORT
      LAYER M4 ;
        RECT  0 60.48 0.192 60.504 ;
    END
  END d[313]
  PIN d[314]
    DIRECTION INPUT ;
    USE SIGNAL ;
    PORT
      LAYER M4 ;
        RECT  0 60.672 0.192 60.696 ;
    END
  END d[314]
  PIN d[315]
    DIRECTION INPUT ;
    USE SIGNAL ;
    PORT
      LAYER M4 ;
        RECT  0 60.864 0.192 60.888 ;
    END
  END d[315]
  PIN d[316]
    DIRECTION INPUT ;
    USE SIGNAL ;
    PORT
      LAYER M4 ;
        RECT  0 61.056 0.192 61.08 ;
    END
  END d[316]
  PIN d[317]
    DIRECTION INPUT ;
    USE SIGNAL ;
    PORT
      LAYER M4 ;
        RECT  0 61.248 0.192 61.272 ;
    END
  END d[317]
  PIN d[318]
    DIRECTION INPUT ;
    USE SIGNAL ;
    PORT
      LAYER M4 ;
        RECT  0 61.44 0.192 61.464 ;
    END
  END d[318]
  PIN d[319]
    DIRECTION INPUT ;
    USE SIGNAL ;
    PORT
      LAYER M4 ;
        RECT  0 61.632 0.192 61.656 ;
    END
  END d[319]
  PIN d[31]
    DIRECTION INPUT ;
    USE SIGNAL ;
    PORT
      LAYER M4 ;
        RECT  0 6.336 0.192 6.36 ;
    END
  END d[31]
  PIN d[320]
    DIRECTION INPUT ;
    USE SIGNAL ;
    PORT
      LAYER M4 ;
        RECT  0 61.824 0.192 61.848 ;
    END
  END d[320]
  PIN d[321]
    DIRECTION INPUT ;
    USE SIGNAL ;
    PORT
      LAYER M4 ;
        RECT  0 62.016 0.192 62.04 ;
    END
  END d[321]
  PIN d[322]
    DIRECTION INPUT ;
    USE SIGNAL ;
    PORT
      LAYER M4 ;
        RECT  0 62.208 0.192 62.232 ;
    END
  END d[322]
  PIN d[323]
    DIRECTION INPUT ;
    USE SIGNAL ;
    PORT
      LAYER M4 ;
        RECT  0 62.4 0.192 62.424 ;
    END
  END d[323]
  PIN d[324]
    DIRECTION INPUT ;
    USE SIGNAL ;
    PORT
      LAYER M4 ;
        RECT  0 62.592 0.192 62.616 ;
    END
  END d[324]
  PIN d[325]
    DIRECTION INPUT ;
    USE SIGNAL ;
    PORT
      LAYER M4 ;
        RECT  0 62.784 0.192 62.808 ;
    END
  END d[325]
  PIN d[326]
    DIRECTION INPUT ;
    USE SIGNAL ;
    PORT
      LAYER M4 ;
        RECT  0 62.976 0.192 63 ;
    END
  END d[326]
  PIN d[327]
    DIRECTION INPUT ;
    USE SIGNAL ;
    PORT
      LAYER M4 ;
        RECT  0 63.168 0.192 63.192 ;
    END
  END d[327]
  PIN d[328]
    DIRECTION INPUT ;
    USE SIGNAL ;
    PORT
      LAYER M4 ;
        RECT  0 63.36 0.192 63.384 ;
    END
  END d[328]
  PIN d[329]
    DIRECTION INPUT ;
    USE SIGNAL ;
    PORT
      LAYER M4 ;
        RECT  0 63.552 0.192 63.576 ;
    END
  END d[329]
  PIN d[32]
    DIRECTION INPUT ;
    USE SIGNAL ;
    PORT
      LAYER M4 ;
        RECT  0 6.528 0.192 6.552 ;
    END
  END d[32]
  PIN d[330]
    DIRECTION INPUT ;
    USE SIGNAL ;
    PORT
      LAYER M4 ;
        RECT  0 63.744 0.192 63.768 ;
    END
  END d[330]
  PIN d[331]
    DIRECTION INPUT ;
    USE SIGNAL ;
    PORT
      LAYER M4 ;
        RECT  0 63.936 0.192 63.96 ;
    END
  END d[331]
  PIN d[332]
    DIRECTION INPUT ;
    USE SIGNAL ;
    PORT
      LAYER M4 ;
        RECT  0 64.128 0.192 64.152 ;
    END
  END d[332]
  PIN d[333]
    DIRECTION INPUT ;
    USE SIGNAL ;
    PORT
      LAYER M4 ;
        RECT  0 64.32 0.192 64.344 ;
    END
  END d[333]
  PIN d[334]
    DIRECTION INPUT ;
    USE SIGNAL ;
    PORT
      LAYER M4 ;
        RECT  0 64.512 0.192 64.536 ;
    END
  END d[334]
  PIN d[335]
    DIRECTION INPUT ;
    USE SIGNAL ;
    PORT
      LAYER M4 ;
        RECT  0 64.704 0.192 64.728 ;
    END
  END d[335]
  PIN d[336]
    DIRECTION INPUT ;
    USE SIGNAL ;
    PORT
      LAYER M4 ;
        RECT  0 64.896 0.192 64.92 ;
    END
  END d[336]
  PIN d[337]
    DIRECTION INPUT ;
    USE SIGNAL ;
    PORT
      LAYER M4 ;
        RECT  0 65.088 0.192 65.112 ;
    END
  END d[337]
  PIN d[338]
    DIRECTION INPUT ;
    USE SIGNAL ;
    PORT
      LAYER M4 ;
        RECT  0 65.28 0.192 65.304 ;
    END
  END d[338]
  PIN d[339]
    DIRECTION INPUT ;
    USE SIGNAL ;
    PORT
      LAYER M4 ;
        RECT  0 65.472 0.192 65.496 ;
    END
  END d[339]
  PIN d[33]
    DIRECTION INPUT ;
    USE SIGNAL ;
    PORT
      LAYER M4 ;
        RECT  0 6.72 0.192 6.744 ;
    END
  END d[33]
  PIN d[340]
    DIRECTION INPUT ;
    USE SIGNAL ;
    PORT
      LAYER M4 ;
        RECT  0 65.664 0.192 65.688 ;
    END
  END d[340]
  PIN d[341]
    DIRECTION INPUT ;
    USE SIGNAL ;
    PORT
      LAYER M4 ;
        RECT  0 65.856 0.192 65.88 ;
    END
  END d[341]
  PIN d[342]
    DIRECTION INPUT ;
    USE SIGNAL ;
    PORT
      LAYER M4 ;
        RECT  0 66.048 0.192 66.072 ;
    END
  END d[342]
  PIN d[343]
    DIRECTION INPUT ;
    USE SIGNAL ;
    PORT
      LAYER M4 ;
        RECT  0 66.24 0.192 66.264 ;
    END
  END d[343]
  PIN d[344]
    DIRECTION INPUT ;
    USE SIGNAL ;
    PORT
      LAYER M4 ;
        RECT  0 66.432 0.192 66.456 ;
    END
  END d[344]
  PIN d[345]
    DIRECTION INPUT ;
    USE SIGNAL ;
    PORT
      LAYER M4 ;
        RECT  0 66.624 0.192 66.648 ;
    END
  END d[345]
  PIN d[346]
    DIRECTION INPUT ;
    USE SIGNAL ;
    PORT
      LAYER M4 ;
        RECT  0 66.816 0.192 66.84 ;
    END
  END d[346]
  PIN d[347]
    DIRECTION INPUT ;
    USE SIGNAL ;
    PORT
      LAYER M4 ;
        RECT  0 67.008 0.192 67.032 ;
    END
  END d[347]
  PIN d[348]
    DIRECTION INPUT ;
    USE SIGNAL ;
    PORT
      LAYER M4 ;
        RECT  0 67.2 0.192 67.224 ;
    END
  END d[348]
  PIN d[349]
    DIRECTION INPUT ;
    USE SIGNAL ;
    PORT
      LAYER M4 ;
        RECT  0 67.392 0.192 67.416 ;
    END
  END d[349]
  PIN d[34]
    DIRECTION INPUT ;
    USE SIGNAL ;
    PORT
      LAYER M4 ;
        RECT  0 6.912 0.192 6.936 ;
    END
  END d[34]
  PIN d[350]
    DIRECTION INPUT ;
    USE SIGNAL ;
    PORT
      LAYER M4 ;
        RECT  0 67.584 0.192 67.608 ;
    END
  END d[350]
  PIN d[351]
    DIRECTION INPUT ;
    USE SIGNAL ;
    PORT
      LAYER M4 ;
        RECT  0 67.776 0.192 67.8 ;
    END
  END d[351]
  PIN d[352]
    DIRECTION INPUT ;
    USE SIGNAL ;
    PORT
      LAYER M4 ;
        RECT  0 67.968 0.192 67.992 ;
    END
  END d[352]
  PIN d[353]
    DIRECTION INPUT ;
    USE SIGNAL ;
    PORT
      LAYER M4 ;
        RECT  0 68.16 0.192 68.184 ;
    END
  END d[353]
  PIN d[354]
    DIRECTION INPUT ;
    USE SIGNAL ;
    PORT
      LAYER M4 ;
        RECT  0 68.352 0.192 68.376 ;
    END
  END d[354]
  PIN d[355]
    DIRECTION INPUT ;
    USE SIGNAL ;
    PORT
      LAYER M4 ;
        RECT  0 68.544 0.192 68.568 ;
    END
  END d[355]
  PIN d[356]
    DIRECTION INPUT ;
    USE SIGNAL ;
    PORT
      LAYER M4 ;
        RECT  0 68.736 0.192 68.76 ;
    END
  END d[356]
  PIN d[357]
    DIRECTION INPUT ;
    USE SIGNAL ;
    PORT
      LAYER M4 ;
        RECT  0 68.928 0.192 68.952 ;
    END
  END d[357]
  PIN d[358]
    DIRECTION INPUT ;
    USE SIGNAL ;
    PORT
      LAYER M4 ;
        RECT  0 69.12 0.192 69.144 ;
    END
  END d[358]
  PIN d[359]
    DIRECTION INPUT ;
    USE SIGNAL ;
    PORT
      LAYER M4 ;
        RECT  0 69.312 0.192 69.336 ;
    END
  END d[359]
  PIN d[35]
    DIRECTION INPUT ;
    USE SIGNAL ;
    PORT
      LAYER M4 ;
        RECT  0 7.104 0.192 7.128 ;
    END
  END d[35]
  PIN d[360]
    DIRECTION INPUT ;
    USE SIGNAL ;
    PORT
      LAYER M4 ;
        RECT  0 69.504 0.192 69.528 ;
    END
  END d[360]
  PIN d[361]
    DIRECTION INPUT ;
    USE SIGNAL ;
    PORT
      LAYER M4 ;
        RECT  0 69.696 0.192 69.72 ;
    END
  END d[361]
  PIN d[362]
    DIRECTION INPUT ;
    USE SIGNAL ;
    PORT
      LAYER M4 ;
        RECT  0 69.888 0.192 69.912 ;
    END
  END d[362]
  PIN d[363]
    DIRECTION INPUT ;
    USE SIGNAL ;
    PORT
      LAYER M4 ;
        RECT  0 70.08 0.192 70.104 ;
    END
  END d[363]
  PIN d[364]
    DIRECTION INPUT ;
    USE SIGNAL ;
    PORT
      LAYER M4 ;
        RECT  0 70.272 0.192 70.296 ;
    END
  END d[364]
  PIN d[365]
    DIRECTION INPUT ;
    USE SIGNAL ;
    PORT
      LAYER M4 ;
        RECT  0 70.464 0.192 70.488 ;
    END
  END d[365]
  PIN d[366]
    DIRECTION INPUT ;
    USE SIGNAL ;
    PORT
      LAYER M4 ;
        RECT  0 70.656 0.192 70.68 ;
    END
  END d[366]
  PIN d[367]
    DIRECTION INPUT ;
    USE SIGNAL ;
    PORT
      LAYER M4 ;
        RECT  0 70.848 0.192 70.872 ;
    END
  END d[367]
  PIN d[368]
    DIRECTION INPUT ;
    USE SIGNAL ;
    PORT
      LAYER M4 ;
        RECT  0 71.04 0.192 71.064 ;
    END
  END d[368]
  PIN d[369]
    DIRECTION INPUT ;
    USE SIGNAL ;
    PORT
      LAYER M4 ;
        RECT  0 71.232 0.192 71.256 ;
    END
  END d[369]
  PIN d[36]
    DIRECTION INPUT ;
    USE SIGNAL ;
    PORT
      LAYER M4 ;
        RECT  0 7.296 0.192 7.32 ;
    END
  END d[36]
  PIN d[370]
    DIRECTION INPUT ;
    USE SIGNAL ;
    PORT
      LAYER M4 ;
        RECT  0 71.424 0.192 71.448 ;
    END
  END d[370]
  PIN d[371]
    DIRECTION INPUT ;
    USE SIGNAL ;
    PORT
      LAYER M4 ;
        RECT  0 71.616 0.192 71.64 ;
    END
  END d[371]
  PIN d[372]
    DIRECTION INPUT ;
    USE SIGNAL ;
    PORT
      LAYER M4 ;
        RECT  0 71.808 0.192 71.832 ;
    END
  END d[372]
  PIN d[373]
    DIRECTION INPUT ;
    USE SIGNAL ;
    PORT
      LAYER M4 ;
        RECT  0 72 0.192 72.024 ;
    END
  END d[373]
  PIN d[374]
    DIRECTION INPUT ;
    USE SIGNAL ;
    PORT
      LAYER M4 ;
        RECT  0 72.192 0.192 72.216 ;
    END
  END d[374]
  PIN d[375]
    DIRECTION INPUT ;
    USE SIGNAL ;
    PORT
      LAYER M4 ;
        RECT  0 72.384 0.192 72.408 ;
    END
  END d[375]
  PIN d[376]
    DIRECTION INPUT ;
    USE SIGNAL ;
    PORT
      LAYER M4 ;
        RECT  0 72.576 0.192 72.6 ;
    END
  END d[376]
  PIN d[377]
    DIRECTION INPUT ;
    USE SIGNAL ;
    PORT
      LAYER M4 ;
        RECT  0 72.768 0.192 72.792 ;
    END
  END d[377]
  PIN d[378]
    DIRECTION INPUT ;
    USE SIGNAL ;
    PORT
      LAYER M4 ;
        RECT  0 72.96 0.192 72.984 ;
    END
  END d[378]
  PIN d[379]
    DIRECTION INPUT ;
    USE SIGNAL ;
    PORT
      LAYER M4 ;
        RECT  0 73.152 0.192 73.176 ;
    END
  END d[379]
  PIN d[37]
    DIRECTION INPUT ;
    USE SIGNAL ;
    PORT
      LAYER M4 ;
        RECT  0 7.488 0.192 7.512 ;
    END
  END d[37]
  PIN d[380]
    DIRECTION INPUT ;
    USE SIGNAL ;
    PORT
      LAYER M4 ;
        RECT  0 73.344 0.192 73.368 ;
    END
  END d[380]
  PIN d[381]
    DIRECTION INPUT ;
    USE SIGNAL ;
    PORT
      LAYER M4 ;
        RECT  0 73.536 0.192 73.56 ;
    END
  END d[381]
  PIN d[382]
    DIRECTION INPUT ;
    USE SIGNAL ;
    PORT
      LAYER M4 ;
        RECT  0 73.728 0.192 73.752 ;
    END
  END d[382]
  PIN d[383]
    DIRECTION INPUT ;
    USE SIGNAL ;
    PORT
      LAYER M4 ;
        RECT  0 73.92 0.192 73.944 ;
    END
  END d[383]
  PIN d[384]
    DIRECTION INPUT ;
    USE SIGNAL ;
    PORT
      LAYER M4 ;
        RECT  0 74.112 0.192 74.136 ;
    END
  END d[384]
  PIN d[385]
    DIRECTION INPUT ;
    USE SIGNAL ;
    PORT
      LAYER M4 ;
        RECT  0 74.304 0.192 74.328 ;
    END
  END d[385]
  PIN d[386]
    DIRECTION INPUT ;
    USE SIGNAL ;
    PORT
      LAYER M4 ;
        RECT  0 74.496 0.192 74.52 ;
    END
  END d[386]
  PIN d[387]
    DIRECTION INPUT ;
    USE SIGNAL ;
    PORT
      LAYER M4 ;
        RECT  0 74.688 0.192 74.712 ;
    END
  END d[387]
  PIN d[388]
    DIRECTION INPUT ;
    USE SIGNAL ;
    PORT
      LAYER M4 ;
        RECT  0 74.88 0.192 74.904 ;
    END
  END d[388]
  PIN d[389]
    DIRECTION INPUT ;
    USE SIGNAL ;
    PORT
      LAYER M4 ;
        RECT  0 75.072 0.192 75.096 ;
    END
  END d[389]
  PIN d[38]
    DIRECTION INPUT ;
    USE SIGNAL ;
    PORT
      LAYER M4 ;
        RECT  0 7.68 0.192 7.704 ;
    END
  END d[38]
  PIN d[390]
    DIRECTION INPUT ;
    USE SIGNAL ;
    PORT
      LAYER M4 ;
        RECT  0 75.264 0.192 75.288 ;
    END
  END d[390]
  PIN d[391]
    DIRECTION INPUT ;
    USE SIGNAL ;
    PORT
      LAYER M4 ;
        RECT  0 75.456 0.192 75.48 ;
    END
  END d[391]
  PIN d[392]
    DIRECTION INPUT ;
    USE SIGNAL ;
    PORT
      LAYER M4 ;
        RECT  0 75.648 0.192 75.672 ;
    END
  END d[392]
  PIN d[393]
    DIRECTION INPUT ;
    USE SIGNAL ;
    PORT
      LAYER M4 ;
        RECT  0 75.84 0.192 75.864 ;
    END
  END d[393]
  PIN d[394]
    DIRECTION INPUT ;
    USE SIGNAL ;
    PORT
      LAYER M4 ;
        RECT  0 76.032 0.192 76.056 ;
    END
  END d[394]
  PIN d[395]
    DIRECTION INPUT ;
    USE SIGNAL ;
    PORT
      LAYER M4 ;
        RECT  0 76.224 0.192 76.248 ;
    END
  END d[395]
  PIN d[396]
    DIRECTION INPUT ;
    USE SIGNAL ;
    PORT
      LAYER M4 ;
        RECT  0 76.416 0.192 76.44 ;
    END
  END d[396]
  PIN d[397]
    DIRECTION INPUT ;
    USE SIGNAL ;
    PORT
      LAYER M4 ;
        RECT  0 76.608 0.192 76.632 ;
    END
  END d[397]
  PIN d[398]
    DIRECTION INPUT ;
    USE SIGNAL ;
    PORT
      LAYER M4 ;
        RECT  0 76.8 0.192 76.824 ;
    END
  END d[398]
  PIN d[399]
    DIRECTION INPUT ;
    USE SIGNAL ;
    PORT
      LAYER M4 ;
        RECT  0 76.992 0.192 77.016 ;
    END
  END d[399]
  PIN d[39]
    DIRECTION INPUT ;
    USE SIGNAL ;
    PORT
      LAYER M4 ;
        RECT  0 7.872 0.192 7.896 ;
    END
  END d[39]
  PIN d[3]
    DIRECTION INPUT ;
    USE SIGNAL ;
    PORT
      LAYER M4 ;
        RECT  0 0.96 0.192 0.984 ;
    END
  END d[3]
  PIN d[400]
    DIRECTION INPUT ;
    USE SIGNAL ;
    PORT
      LAYER M4 ;
        RECT  0 77.184 0.192 77.208 ;
    END
  END d[400]
  PIN d[401]
    DIRECTION INPUT ;
    USE SIGNAL ;
    PORT
      LAYER M4 ;
        RECT  0 77.376 0.192 77.4 ;
    END
  END d[401]
  PIN d[402]
    DIRECTION INPUT ;
    USE SIGNAL ;
    PORT
      LAYER M4 ;
        RECT  0 77.568 0.192 77.592 ;
    END
  END d[402]
  PIN d[403]
    DIRECTION INPUT ;
    USE SIGNAL ;
    PORT
      LAYER M4 ;
        RECT  0 77.76 0.192 77.784 ;
    END
  END d[403]
  PIN d[404]
    DIRECTION INPUT ;
    USE SIGNAL ;
    PORT
      LAYER M4 ;
        RECT  0 77.952 0.192 77.976 ;
    END
  END d[404]
  PIN d[405]
    DIRECTION INPUT ;
    USE SIGNAL ;
    PORT
      LAYER M4 ;
        RECT  0 78.144 0.192 78.168 ;
    END
  END d[405]
  PIN d[406]
    DIRECTION INPUT ;
    USE SIGNAL ;
    PORT
      LAYER M4 ;
        RECT  0 78.336 0.192 78.36 ;
    END
  END d[406]
  PIN d[407]
    DIRECTION INPUT ;
    USE SIGNAL ;
    PORT
      LAYER M4 ;
        RECT  0 78.528 0.192 78.552 ;
    END
  END d[407]
  PIN d[408]
    DIRECTION INPUT ;
    USE SIGNAL ;
    PORT
      LAYER M4 ;
        RECT  0 78.72 0.192 78.744 ;
    END
  END d[408]
  PIN d[409]
    DIRECTION INPUT ;
    USE SIGNAL ;
    PORT
      LAYER M4 ;
        RECT  0 78.912 0.192 78.936 ;
    END
  END d[409]
  PIN d[40]
    DIRECTION INPUT ;
    USE SIGNAL ;
    PORT
      LAYER M4 ;
        RECT  0 8.064 0.192 8.088 ;
    END
  END d[40]
  PIN d[410]
    DIRECTION INPUT ;
    USE SIGNAL ;
    PORT
      LAYER M4 ;
        RECT  0 79.104 0.192 79.128 ;
    END
  END d[410]
  PIN d[411]
    DIRECTION INPUT ;
    USE SIGNAL ;
    PORT
      LAYER M4 ;
        RECT  0 79.296 0.192 79.32 ;
    END
  END d[411]
  PIN d[412]
    DIRECTION INPUT ;
    USE SIGNAL ;
    PORT
      LAYER M4 ;
        RECT  0 79.488 0.192 79.512 ;
    END
  END d[412]
  PIN d[413]
    DIRECTION INPUT ;
    USE SIGNAL ;
    PORT
      LAYER M4 ;
        RECT  0 79.68 0.192 79.704 ;
    END
  END d[413]
  PIN d[414]
    DIRECTION INPUT ;
    USE SIGNAL ;
    PORT
      LAYER M4 ;
        RECT  0 79.872 0.192 79.896 ;
    END
  END d[414]
  PIN d[415]
    DIRECTION INPUT ;
    USE SIGNAL ;
    PORT
      LAYER M4 ;
        RECT  0 80.064 0.192 80.088 ;
    END
  END d[415]
  PIN d[416]
    DIRECTION INPUT ;
    USE SIGNAL ;
    PORT
      LAYER M4 ;
        RECT  0 80.256 0.192 80.28 ;
    END
  END d[416]
  PIN d[417]
    DIRECTION INPUT ;
    USE SIGNAL ;
    PORT
      LAYER M4 ;
        RECT  0 80.448 0.192 80.472 ;
    END
  END d[417]
  PIN d[418]
    DIRECTION INPUT ;
    USE SIGNAL ;
    PORT
      LAYER M4 ;
        RECT  0 80.64 0.192 80.664 ;
    END
  END d[418]
  PIN d[419]
    DIRECTION INPUT ;
    USE SIGNAL ;
    PORT
      LAYER M4 ;
        RECT  0 80.832 0.192 80.856 ;
    END
  END d[419]
  PIN d[41]
    DIRECTION INPUT ;
    USE SIGNAL ;
    PORT
      LAYER M4 ;
        RECT  0 8.256 0.192 8.28 ;
    END
  END d[41]
  PIN d[420]
    DIRECTION INPUT ;
    USE SIGNAL ;
    PORT
      LAYER M4 ;
        RECT  0 81.024 0.192 81.048 ;
    END
  END d[420]
  PIN d[421]
    DIRECTION INPUT ;
    USE SIGNAL ;
    PORT
      LAYER M4 ;
        RECT  0 81.216 0.192 81.24 ;
    END
  END d[421]
  PIN d[422]
    DIRECTION INPUT ;
    USE SIGNAL ;
    PORT
      LAYER M4 ;
        RECT  0 81.408 0.192 81.432 ;
    END
  END d[422]
  PIN d[423]
    DIRECTION INPUT ;
    USE SIGNAL ;
    PORT
      LAYER M4 ;
        RECT  0 81.6 0.192 81.624 ;
    END
  END d[423]
  PIN d[424]
    DIRECTION INPUT ;
    USE SIGNAL ;
    PORT
      LAYER M4 ;
        RECT  0 81.792 0.192 81.816 ;
    END
  END d[424]
  PIN d[425]
    DIRECTION INPUT ;
    USE SIGNAL ;
    PORT
      LAYER M4 ;
        RECT  0 81.984 0.192 82.008 ;
    END
  END d[425]
  PIN d[426]
    DIRECTION INPUT ;
    USE SIGNAL ;
    PORT
      LAYER M4 ;
        RECT  0 82.176 0.192 82.2 ;
    END
  END d[426]
  PIN d[427]
    DIRECTION INPUT ;
    USE SIGNAL ;
    PORT
      LAYER M4 ;
        RECT  0 82.368 0.192 82.392 ;
    END
  END d[427]
  PIN d[428]
    DIRECTION INPUT ;
    USE SIGNAL ;
    PORT
      LAYER M4 ;
        RECT  0 82.56 0.192 82.584 ;
    END
  END d[428]
  PIN d[429]
    DIRECTION INPUT ;
    USE SIGNAL ;
    PORT
      LAYER M4 ;
        RECT  0 82.752 0.192 82.776 ;
    END
  END d[429]
  PIN d[42]
    DIRECTION INPUT ;
    USE SIGNAL ;
    PORT
      LAYER M4 ;
        RECT  0 8.448 0.192 8.472 ;
    END
  END d[42]
  PIN d[430]
    DIRECTION INPUT ;
    USE SIGNAL ;
    PORT
      LAYER M4 ;
        RECT  0 82.944 0.192 82.968 ;
    END
  END d[430]
  PIN d[431]
    DIRECTION INPUT ;
    USE SIGNAL ;
    PORT
      LAYER M4 ;
        RECT  0 83.136 0.192 83.16 ;
    END
  END d[431]
  PIN d[432]
    DIRECTION INPUT ;
    USE SIGNAL ;
    PORT
      LAYER M4 ;
        RECT  0 83.328 0.192 83.352 ;
    END
  END d[432]
  PIN d[433]
    DIRECTION INPUT ;
    USE SIGNAL ;
    PORT
      LAYER M4 ;
        RECT  0 83.52 0.192 83.544 ;
    END
  END d[433]
  PIN d[434]
    DIRECTION INPUT ;
    USE SIGNAL ;
    PORT
      LAYER M4 ;
        RECT  0 83.712 0.192 83.736 ;
    END
  END d[434]
  PIN d[435]
    DIRECTION INPUT ;
    USE SIGNAL ;
    PORT
      LAYER M4 ;
        RECT  0 83.904 0.192 83.928 ;
    END
  END d[435]
  PIN d[436]
    DIRECTION INPUT ;
    USE SIGNAL ;
    PORT
      LAYER M4 ;
        RECT  0 84.096 0.192 84.12 ;
    END
  END d[436]
  PIN d[437]
    DIRECTION INPUT ;
    USE SIGNAL ;
    PORT
      LAYER M4 ;
        RECT  0 84.288 0.192 84.312 ;
    END
  END d[437]
  PIN d[438]
    DIRECTION INPUT ;
    USE SIGNAL ;
    PORT
      LAYER M4 ;
        RECT  0 84.48 0.192 84.504 ;
    END
  END d[438]
  PIN d[439]
    DIRECTION INPUT ;
    USE SIGNAL ;
    PORT
      LAYER M4 ;
        RECT  0 84.672 0.192 84.696 ;
    END
  END d[439]
  PIN d[43]
    DIRECTION INPUT ;
    USE SIGNAL ;
    PORT
      LAYER M4 ;
        RECT  0 8.64 0.192 8.664 ;
    END
  END d[43]
  PIN d[440]
    DIRECTION INPUT ;
    USE SIGNAL ;
    PORT
      LAYER M4 ;
        RECT  0 84.864 0.192 84.888 ;
    END
  END d[440]
  PIN d[441]
    DIRECTION INPUT ;
    USE SIGNAL ;
    PORT
      LAYER M4 ;
        RECT  0 85.056 0.192 85.08 ;
    END
  END d[441]
  PIN d[442]
    DIRECTION INPUT ;
    USE SIGNAL ;
    PORT
      LAYER M4 ;
        RECT  0 85.248 0.192 85.272 ;
    END
  END d[442]
  PIN d[443]
    DIRECTION INPUT ;
    USE SIGNAL ;
    PORT
      LAYER M4 ;
        RECT  0 85.44 0.192 85.464 ;
    END
  END d[443]
  PIN d[444]
    DIRECTION INPUT ;
    USE SIGNAL ;
    PORT
      LAYER M4 ;
        RECT  0 85.632 0.192 85.656 ;
    END
  END d[444]
  PIN d[445]
    DIRECTION INPUT ;
    USE SIGNAL ;
    PORT
      LAYER M4 ;
        RECT  0 85.824 0.192 85.848 ;
    END
  END d[445]
  PIN d[446]
    DIRECTION INPUT ;
    USE SIGNAL ;
    PORT
      LAYER M4 ;
        RECT  0 86.016 0.192 86.04 ;
    END
  END d[446]
  PIN d[447]
    DIRECTION INPUT ;
    USE SIGNAL ;
    PORT
      LAYER M4 ;
        RECT  0 86.208 0.192 86.232 ;
    END
  END d[447]
  PIN d[448]
    DIRECTION INPUT ;
    USE SIGNAL ;
    PORT
      LAYER M4 ;
        RECT  0 86.4 0.192 86.424 ;
    END
  END d[448]
  PIN d[449]
    DIRECTION INPUT ;
    USE SIGNAL ;
    PORT
      LAYER M4 ;
        RECT  0 86.592 0.192 86.616 ;
    END
  END d[449]
  PIN d[44]
    DIRECTION INPUT ;
    USE SIGNAL ;
    PORT
      LAYER M4 ;
        RECT  0 8.832 0.192 8.856 ;
    END
  END d[44]
  PIN d[450]
    DIRECTION INPUT ;
    USE SIGNAL ;
    PORT
      LAYER M4 ;
        RECT  0 86.784 0.192 86.808 ;
    END
  END d[450]
  PIN d[451]
    DIRECTION INPUT ;
    USE SIGNAL ;
    PORT
      LAYER M4 ;
        RECT  0 86.976 0.192 87 ;
    END
  END d[451]
  PIN d[452]
    DIRECTION INPUT ;
    USE SIGNAL ;
    PORT
      LAYER M4 ;
        RECT  0 87.168 0.192 87.192 ;
    END
  END d[452]
  PIN d[453]
    DIRECTION INPUT ;
    USE SIGNAL ;
    PORT
      LAYER M4 ;
        RECT  0 87.36 0.192 87.384 ;
    END
  END d[453]
  PIN d[454]
    DIRECTION INPUT ;
    USE SIGNAL ;
    PORT
      LAYER M4 ;
        RECT  0 87.552 0.192 87.576 ;
    END
  END d[454]
  PIN d[455]
    DIRECTION INPUT ;
    USE SIGNAL ;
    PORT
      LAYER M4 ;
        RECT  0 87.744 0.192 87.768 ;
    END
  END d[455]
  PIN d[456]
    DIRECTION INPUT ;
    USE SIGNAL ;
    PORT
      LAYER M4 ;
        RECT  0 87.936 0.192 87.96 ;
    END
  END d[456]
  PIN d[457]
    DIRECTION INPUT ;
    USE SIGNAL ;
    PORT
      LAYER M4 ;
        RECT  0 88.128 0.192 88.152 ;
    END
  END d[457]
  PIN d[458]
    DIRECTION INPUT ;
    USE SIGNAL ;
    PORT
      LAYER M4 ;
        RECT  0 88.32 0.192 88.344 ;
    END
  END d[458]
  PIN d[459]
    DIRECTION INPUT ;
    USE SIGNAL ;
    PORT
      LAYER M4 ;
        RECT  0 88.512 0.192 88.536 ;
    END
  END d[459]
  PIN d[45]
    DIRECTION INPUT ;
    USE SIGNAL ;
    PORT
      LAYER M4 ;
        RECT  0 9.024 0.192 9.048 ;
    END
  END d[45]
  PIN d[460]
    DIRECTION INPUT ;
    USE SIGNAL ;
    PORT
      LAYER M4 ;
        RECT  0 88.704 0.192 88.728 ;
    END
  END d[460]
  PIN d[461]
    DIRECTION INPUT ;
    USE SIGNAL ;
    PORT
      LAYER M4 ;
        RECT  0 88.896 0.192 88.92 ;
    END
  END d[461]
  PIN d[462]
    DIRECTION INPUT ;
    USE SIGNAL ;
    PORT
      LAYER M4 ;
        RECT  0 89.088 0.192 89.112 ;
    END
  END d[462]
  PIN d[463]
    DIRECTION INPUT ;
    USE SIGNAL ;
    PORT
      LAYER M4 ;
        RECT  0 89.28 0.192 89.304 ;
    END
  END d[463]
  PIN d[464]
    DIRECTION INPUT ;
    USE SIGNAL ;
    PORT
      LAYER M4 ;
        RECT  0 89.472 0.192 89.496 ;
    END
  END d[464]
  PIN d[465]
    DIRECTION INPUT ;
    USE SIGNAL ;
    PORT
      LAYER M4 ;
        RECT  0 89.664 0.192 89.688 ;
    END
  END d[465]
  PIN d[466]
    DIRECTION INPUT ;
    USE SIGNAL ;
    PORT
      LAYER M4 ;
        RECT  0 89.856 0.192 89.88 ;
    END
  END d[466]
  PIN d[467]
    DIRECTION INPUT ;
    USE SIGNAL ;
    PORT
      LAYER M4 ;
        RECT  0 90.048 0.192 90.072 ;
    END
  END d[467]
  PIN d[468]
    DIRECTION INPUT ;
    USE SIGNAL ;
    PORT
      LAYER M4 ;
        RECT  0 90.24 0.192 90.264 ;
    END
  END d[468]
  PIN d[469]
    DIRECTION INPUT ;
    USE SIGNAL ;
    PORT
      LAYER M4 ;
        RECT  0 90.432 0.192 90.456 ;
    END
  END d[469]
  PIN d[46]
    DIRECTION INPUT ;
    USE SIGNAL ;
    PORT
      LAYER M4 ;
        RECT  0 9.216 0.192 9.24 ;
    END
  END d[46]
  PIN d[470]
    DIRECTION INPUT ;
    USE SIGNAL ;
    PORT
      LAYER M4 ;
        RECT  0 90.624 0.192 90.648 ;
    END
  END d[470]
  PIN d[471]
    DIRECTION INPUT ;
    USE SIGNAL ;
    PORT
      LAYER M4 ;
        RECT  0 90.816 0.192 90.84 ;
    END
  END d[471]
  PIN d[472]
    DIRECTION INPUT ;
    USE SIGNAL ;
    PORT
      LAYER M4 ;
        RECT  0 91.008 0.192 91.032 ;
    END
  END d[472]
  PIN d[473]
    DIRECTION INPUT ;
    USE SIGNAL ;
    PORT
      LAYER M4 ;
        RECT  0 91.2 0.192 91.224 ;
    END
  END d[473]
  PIN d[474]
    DIRECTION INPUT ;
    USE SIGNAL ;
    PORT
      LAYER M4 ;
        RECT  0 91.392 0.192 91.416 ;
    END
  END d[474]
  PIN d[475]
    DIRECTION INPUT ;
    USE SIGNAL ;
    PORT
      LAYER M4 ;
        RECT  0 91.584 0.192 91.608 ;
    END
  END d[475]
  PIN d[476]
    DIRECTION INPUT ;
    USE SIGNAL ;
    PORT
      LAYER M4 ;
        RECT  0 91.776 0.192 91.8 ;
    END
  END d[476]
  PIN d[477]
    DIRECTION INPUT ;
    USE SIGNAL ;
    PORT
      LAYER M4 ;
        RECT  0 91.968 0.192 91.992 ;
    END
  END d[477]
  PIN d[478]
    DIRECTION INPUT ;
    USE SIGNAL ;
    PORT
      LAYER M4 ;
        RECT  0 92.16 0.192 92.184 ;
    END
  END d[478]
  PIN d[479]
    DIRECTION INPUT ;
    USE SIGNAL ;
    PORT
      LAYER M4 ;
        RECT  0 92.352 0.192 92.376 ;
    END
  END d[479]
  PIN d[47]
    DIRECTION INPUT ;
    USE SIGNAL ;
    PORT
      LAYER M4 ;
        RECT  0 9.408 0.192 9.432 ;
    END
  END d[47]
  PIN d[480]
    DIRECTION INPUT ;
    USE SIGNAL ;
    PORT
      LAYER M4 ;
        RECT  0 92.544 0.192 92.568 ;
    END
  END d[480]
  PIN d[481]
    DIRECTION INPUT ;
    USE SIGNAL ;
    PORT
      LAYER M4 ;
        RECT  0 92.736 0.192 92.76 ;
    END
  END d[481]
  PIN d[482]
    DIRECTION INPUT ;
    USE SIGNAL ;
    PORT
      LAYER M4 ;
        RECT  0 92.928 0.192 92.952 ;
    END
  END d[482]
  PIN d[483]
    DIRECTION INPUT ;
    USE SIGNAL ;
    PORT
      LAYER M4 ;
        RECT  0 93.12 0.192 93.144 ;
    END
  END d[483]
  PIN d[484]
    DIRECTION INPUT ;
    USE SIGNAL ;
    PORT
      LAYER M4 ;
        RECT  0 93.312 0.192 93.336 ;
    END
  END d[484]
  PIN d[485]
    DIRECTION INPUT ;
    USE SIGNAL ;
    PORT
      LAYER M4 ;
        RECT  0 93.504 0.192 93.528 ;
    END
  END d[485]
  PIN d[486]
    DIRECTION INPUT ;
    USE SIGNAL ;
    PORT
      LAYER M4 ;
        RECT  0 93.696 0.192 93.72 ;
    END
  END d[486]
  PIN d[487]
    DIRECTION INPUT ;
    USE SIGNAL ;
    PORT
      LAYER M4 ;
        RECT  0 93.888 0.192 93.912 ;
    END
  END d[487]
  PIN d[488]
    DIRECTION INPUT ;
    USE SIGNAL ;
    PORT
      LAYER M4 ;
        RECT  0 94.08 0.192 94.104 ;
    END
  END d[488]
  PIN d[489]
    DIRECTION INPUT ;
    USE SIGNAL ;
    PORT
      LAYER M4 ;
        RECT  0 94.272 0.192 94.296 ;
    END
  END d[489]
  PIN d[48]
    DIRECTION INPUT ;
    USE SIGNAL ;
    PORT
      LAYER M4 ;
        RECT  0 9.6 0.192 9.624 ;
    END
  END d[48]
  PIN d[490]
    DIRECTION INPUT ;
    USE SIGNAL ;
    PORT
      LAYER M4 ;
        RECT  0 94.464 0.192 94.488 ;
    END
  END d[490]
  PIN d[491]
    DIRECTION INPUT ;
    USE SIGNAL ;
    PORT
      LAYER M4 ;
        RECT  0 94.656 0.192 94.68 ;
    END
  END d[491]
  PIN d[492]
    DIRECTION INPUT ;
    USE SIGNAL ;
    PORT
      LAYER M4 ;
        RECT  0 94.848 0.192 94.872 ;
    END
  END d[492]
  PIN d[493]
    DIRECTION INPUT ;
    USE SIGNAL ;
    PORT
      LAYER M4 ;
        RECT  0 95.04 0.192 95.064 ;
    END
  END d[493]
  PIN d[494]
    DIRECTION INPUT ;
    USE SIGNAL ;
    PORT
      LAYER M4 ;
        RECT  0 95.232 0.192 95.256 ;
    END
  END d[494]
  PIN d[495]
    DIRECTION INPUT ;
    USE SIGNAL ;
    PORT
      LAYER M4 ;
        RECT  0 95.424 0.192 95.448 ;
    END
  END d[495]
  PIN d[496]
    DIRECTION INPUT ;
    USE SIGNAL ;
    PORT
      LAYER M4 ;
        RECT  0 95.616 0.192 95.64 ;
    END
  END d[496]
  PIN d[497]
    DIRECTION INPUT ;
    USE SIGNAL ;
    PORT
      LAYER M4 ;
        RECT  0 95.808 0.192 95.832 ;
    END
  END d[497]
  PIN d[498]
    DIRECTION INPUT ;
    USE SIGNAL ;
    PORT
      LAYER M4 ;
        RECT  0 96 0.192 96.024 ;
    END
  END d[498]
  PIN d[499]
    DIRECTION INPUT ;
    USE SIGNAL ;
    PORT
      LAYER M4 ;
        RECT  0 96.192 0.192 96.216 ;
    END
  END d[499]
  PIN d[49]
    DIRECTION INPUT ;
    USE SIGNAL ;
    PORT
      LAYER M4 ;
        RECT  0 9.792 0.192 9.816 ;
    END
  END d[49]
  PIN d[4]
    DIRECTION INPUT ;
    USE SIGNAL ;
    PORT
      LAYER M4 ;
        RECT  0 1.152 0.192 1.176 ;
    END
  END d[4]
  PIN d[500]
    DIRECTION INPUT ;
    USE SIGNAL ;
    PORT
      LAYER M4 ;
        RECT  0 96.384 0.192 96.408 ;
    END
  END d[500]
  PIN d[501]
    DIRECTION INPUT ;
    USE SIGNAL ;
    PORT
      LAYER M4 ;
        RECT  0 96.576 0.192 96.6 ;
    END
  END d[501]
  PIN d[502]
    DIRECTION INPUT ;
    USE SIGNAL ;
    PORT
      LAYER M4 ;
        RECT  0 96.768 0.192 96.792 ;
    END
  END d[502]
  PIN d[503]
    DIRECTION INPUT ;
    USE SIGNAL ;
    PORT
      LAYER M4 ;
        RECT  0 96.96 0.192 96.984 ;
    END
  END d[503]
  PIN d[504]
    DIRECTION INPUT ;
    USE SIGNAL ;
    PORT
      LAYER M4 ;
        RECT  0 97.152 0.192 97.176 ;
    END
  END d[504]
  PIN d[505]
    DIRECTION INPUT ;
    USE SIGNAL ;
    PORT
      LAYER M4 ;
        RECT  0 97.344 0.192 97.368 ;
    END
  END d[505]
  PIN d[506]
    DIRECTION INPUT ;
    USE SIGNAL ;
    PORT
      LAYER M4 ;
        RECT  0 97.536 0.192 97.56 ;
    END
  END d[506]
  PIN d[507]
    DIRECTION INPUT ;
    USE SIGNAL ;
    PORT
      LAYER M4 ;
        RECT  0 97.728 0.192 97.752 ;
    END
  END d[507]
  PIN d[508]
    DIRECTION INPUT ;
    USE SIGNAL ;
    PORT
      LAYER M4 ;
        RECT  0 97.92 0.192 97.944 ;
    END
  END d[508]
  PIN d[509]
    DIRECTION INPUT ;
    USE SIGNAL ;
    PORT
      LAYER M4 ;
        RECT  0 98.112 0.192 98.136 ;
    END
  END d[509]
  PIN d[50]
    DIRECTION INPUT ;
    USE SIGNAL ;
    PORT
      LAYER M4 ;
        RECT  0 9.984 0.192 10.008 ;
    END
  END d[50]
  PIN d[510]
    DIRECTION INPUT ;
    USE SIGNAL ;
    PORT
      LAYER M4 ;
        RECT  0 98.304 0.192 98.328 ;
    END
  END d[510]
  PIN d[511]
    DIRECTION INPUT ;
    USE SIGNAL ;
    PORT
      LAYER M4 ;
        RECT  0 98.496 0.192 98.52 ;
    END
  END d[511]
  PIN d[512]
    DIRECTION INPUT ;
    USE SIGNAL ;
    PORT
      LAYER M4 ;
        RECT  0 98.688 0.192 98.712 ;
    END
  END d[512]
  PIN d[513]
    DIRECTION INPUT ;
    USE SIGNAL ;
    PORT
      LAYER M4 ;
        RECT  0 98.88 0.192 98.904 ;
    END
  END d[513]
  PIN d[514]
    DIRECTION INPUT ;
    USE SIGNAL ;
    PORT
      LAYER M4 ;
        RECT  0 99.072 0.192 99.096 ;
    END
  END d[514]
  PIN d[515]
    DIRECTION INPUT ;
    USE SIGNAL ;
    PORT
      LAYER M4 ;
        RECT  0 99.264 0.192 99.288 ;
    END
  END d[515]
  PIN d[516]
    DIRECTION INPUT ;
    USE SIGNAL ;
    PORT
      LAYER M4 ;
        RECT  0 99.456 0.192 99.48 ;
    END
  END d[516]
  PIN d[517]
    DIRECTION INPUT ;
    USE SIGNAL ;
    PORT
      LAYER M4 ;
        RECT  0 99.648 0.192 99.672 ;
    END
  END d[517]
  PIN d[518]
    DIRECTION INPUT ;
    USE SIGNAL ;
    PORT
      LAYER M4 ;
        RECT  0 99.84 0.192 99.864 ;
    END
  END d[518]
  PIN d[519]
    DIRECTION INPUT ;
    USE SIGNAL ;
    PORT
      LAYER M4 ;
        RECT  0 100.032 0.192 100.056 ;
    END
  END d[519]
  PIN d[51]
    DIRECTION INPUT ;
    USE SIGNAL ;
    PORT
      LAYER M4 ;
        RECT  0 10.176 0.192 10.2 ;
    END
  END d[51]
  PIN d[520]
    DIRECTION INPUT ;
    USE SIGNAL ;
    PORT
      LAYER M4 ;
        RECT  0 100.224 0.192 100.248 ;
    END
  END d[520]
  PIN d[521]
    DIRECTION INPUT ;
    USE SIGNAL ;
    PORT
      LAYER M4 ;
        RECT  0 100.416 0.192 100.44 ;
    END
  END d[521]
  PIN d[522]
    DIRECTION INPUT ;
    USE SIGNAL ;
    PORT
      LAYER M4 ;
        RECT  0 100.608 0.192 100.632 ;
    END
  END d[522]
  PIN d[523]
    DIRECTION INPUT ;
    USE SIGNAL ;
    PORT
      LAYER M4 ;
        RECT  0 100.8 0.192 100.824 ;
    END
  END d[523]
  PIN d[524]
    DIRECTION INPUT ;
    USE SIGNAL ;
    PORT
      LAYER M4 ;
        RECT  0 100.992 0.192 101.016 ;
    END
  END d[524]
  PIN d[525]
    DIRECTION INPUT ;
    USE SIGNAL ;
    PORT
      LAYER M4 ;
        RECT  0 101.184 0.192 101.208 ;
    END
  END d[525]
  PIN d[526]
    DIRECTION INPUT ;
    USE SIGNAL ;
    PORT
      LAYER M4 ;
        RECT  0 101.376 0.192 101.4 ;
    END
  END d[526]
  PIN d[527]
    DIRECTION INPUT ;
    USE SIGNAL ;
    PORT
      LAYER M4 ;
        RECT  0 101.568 0.192 101.592 ;
    END
  END d[527]
  PIN d[528]
    DIRECTION INPUT ;
    USE SIGNAL ;
    PORT
      LAYER M4 ;
        RECT  0 101.76 0.192 101.784 ;
    END
  END d[528]
  PIN d[529]
    DIRECTION INPUT ;
    USE SIGNAL ;
    PORT
      LAYER M4 ;
        RECT  0 101.952 0.192 101.976 ;
    END
  END d[529]
  PIN d[52]
    DIRECTION INPUT ;
    USE SIGNAL ;
    PORT
      LAYER M4 ;
        RECT  0 10.368 0.192 10.392 ;
    END
  END d[52]
  PIN d[530]
    DIRECTION INPUT ;
    USE SIGNAL ;
    PORT
      LAYER M4 ;
        RECT  0 102.144 0.192 102.168 ;
    END
  END d[530]
  PIN d[531]
    DIRECTION INPUT ;
    USE SIGNAL ;
    PORT
      LAYER M4 ;
        RECT  0 102.336 0.192 102.36 ;
    END
  END d[531]
  PIN d[532]
    DIRECTION INPUT ;
    USE SIGNAL ;
    PORT
      LAYER M4 ;
        RECT  0 102.528 0.192 102.552 ;
    END
  END d[532]
  PIN d[533]
    DIRECTION INPUT ;
    USE SIGNAL ;
    PORT
      LAYER M4 ;
        RECT  0 102.72 0.192 102.744 ;
    END
  END d[533]
  PIN d[534]
    DIRECTION INPUT ;
    USE SIGNAL ;
    PORT
      LAYER M4 ;
        RECT  0 102.912 0.192 102.936 ;
    END
  END d[534]
  PIN d[535]
    DIRECTION INPUT ;
    USE SIGNAL ;
    PORT
      LAYER M4 ;
        RECT  0 103.104 0.192 103.128 ;
    END
  END d[535]
  PIN d[536]
    DIRECTION INPUT ;
    USE SIGNAL ;
    PORT
      LAYER M4 ;
        RECT  0 103.296 0.192 103.32 ;
    END
  END d[536]
  PIN d[537]
    DIRECTION INPUT ;
    USE SIGNAL ;
    PORT
      LAYER M4 ;
        RECT  0 103.488 0.192 103.512 ;
    END
  END d[537]
  PIN d[538]
    DIRECTION INPUT ;
    USE SIGNAL ;
    PORT
      LAYER M4 ;
        RECT  0 103.68 0.192 103.704 ;
    END
  END d[538]
  PIN d[539]
    DIRECTION INPUT ;
    USE SIGNAL ;
    PORT
      LAYER M4 ;
        RECT  0 103.872 0.192 103.896 ;
    END
  END d[539]
  PIN d[53]
    DIRECTION INPUT ;
    USE SIGNAL ;
    PORT
      LAYER M4 ;
        RECT  0 10.56 0.192 10.584 ;
    END
  END d[53]
  PIN d[540]
    DIRECTION INPUT ;
    USE SIGNAL ;
    PORT
      LAYER M4 ;
        RECT  0 104.064 0.192 104.088 ;
    END
  END d[540]
  PIN d[541]
    DIRECTION INPUT ;
    USE SIGNAL ;
    PORT
      LAYER M4 ;
        RECT  0 104.256 0.192 104.28 ;
    END
  END d[541]
  PIN d[542]
    DIRECTION INPUT ;
    USE SIGNAL ;
    PORT
      LAYER M4 ;
        RECT  0 104.448 0.192 104.472 ;
    END
  END d[542]
  PIN d[543]
    DIRECTION INPUT ;
    USE SIGNAL ;
    PORT
      LAYER M4 ;
        RECT  0 104.64 0.192 104.664 ;
    END
  END d[543]
  PIN d[54]
    DIRECTION INPUT ;
    USE SIGNAL ;
    PORT
      LAYER M4 ;
        RECT  0 10.752 0.192 10.776 ;
    END
  END d[54]
  PIN d[55]
    DIRECTION INPUT ;
    USE SIGNAL ;
    PORT
      LAYER M4 ;
        RECT  0 10.944 0.192 10.968 ;
    END
  END d[55]
  PIN d[56]
    DIRECTION INPUT ;
    USE SIGNAL ;
    PORT
      LAYER M4 ;
        RECT  0 11.136 0.192 11.16 ;
    END
  END d[56]
  PIN d[57]
    DIRECTION INPUT ;
    USE SIGNAL ;
    PORT
      LAYER M4 ;
        RECT  0 11.328 0.192 11.352 ;
    END
  END d[57]
  PIN d[58]
    DIRECTION INPUT ;
    USE SIGNAL ;
    PORT
      LAYER M4 ;
        RECT  0 11.52 0.192 11.544 ;
    END
  END d[58]
  PIN d[59]
    DIRECTION INPUT ;
    USE SIGNAL ;
    PORT
      LAYER M4 ;
        RECT  0 11.712 0.192 11.736 ;
    END
  END d[59]
  PIN d[5]
    DIRECTION INPUT ;
    USE SIGNAL ;
    PORT
      LAYER M4 ;
        RECT  0 1.344 0.192 1.368 ;
    END
  END d[5]
  PIN d[60]
    DIRECTION INPUT ;
    USE SIGNAL ;
    PORT
      LAYER M4 ;
        RECT  0 11.904 0.192 11.928 ;
    END
  END d[60]
  PIN d[61]
    DIRECTION INPUT ;
    USE SIGNAL ;
    PORT
      LAYER M4 ;
        RECT  0 12.096 0.192 12.12 ;
    END
  END d[61]
  PIN d[62]
    DIRECTION INPUT ;
    USE SIGNAL ;
    PORT
      LAYER M4 ;
        RECT  0 12.288 0.192 12.312 ;
    END
  END d[62]
  PIN d[63]
    DIRECTION INPUT ;
    USE SIGNAL ;
    PORT
      LAYER M4 ;
        RECT  0 12.48 0.192 12.504 ;
    END
  END d[63]
  PIN d[64]
    DIRECTION INPUT ;
    USE SIGNAL ;
    PORT
      LAYER M4 ;
        RECT  0 12.672 0.192 12.696 ;
    END
  END d[64]
  PIN d[65]
    DIRECTION INPUT ;
    USE SIGNAL ;
    PORT
      LAYER M4 ;
        RECT  0 12.864 0.192 12.888 ;
    END
  END d[65]
  PIN d[66]
    DIRECTION INPUT ;
    USE SIGNAL ;
    PORT
      LAYER M4 ;
        RECT  0 13.056 0.192 13.08 ;
    END
  END d[66]
  PIN d[67]
    DIRECTION INPUT ;
    USE SIGNAL ;
    PORT
      LAYER M4 ;
        RECT  0 13.248 0.192 13.272 ;
    END
  END d[67]
  PIN d[68]
    DIRECTION INPUT ;
    USE SIGNAL ;
    PORT
      LAYER M4 ;
        RECT  0 13.44 0.192 13.464 ;
    END
  END d[68]
  PIN d[69]
    DIRECTION INPUT ;
    USE SIGNAL ;
    PORT
      LAYER M4 ;
        RECT  0 13.632 0.192 13.656 ;
    END
  END d[69]
  PIN d[6]
    DIRECTION INPUT ;
    USE SIGNAL ;
    PORT
      LAYER M4 ;
        RECT  0 1.536 0.192 1.56 ;
    END
  END d[6]
  PIN d[70]
    DIRECTION INPUT ;
    USE SIGNAL ;
    PORT
      LAYER M4 ;
        RECT  0 13.824 0.192 13.848 ;
    END
  END d[70]
  PIN d[71]
    DIRECTION INPUT ;
    USE SIGNAL ;
    PORT
      LAYER M4 ;
        RECT  0 14.016 0.192 14.04 ;
    END
  END d[71]
  PIN d[72]
    DIRECTION INPUT ;
    USE SIGNAL ;
    PORT
      LAYER M4 ;
        RECT  0 14.208 0.192 14.232 ;
    END
  END d[72]
  PIN d[73]
    DIRECTION INPUT ;
    USE SIGNAL ;
    PORT
      LAYER M4 ;
        RECT  0 14.4 0.192 14.424 ;
    END
  END d[73]
  PIN d[74]
    DIRECTION INPUT ;
    USE SIGNAL ;
    PORT
      LAYER M4 ;
        RECT  0 14.592 0.192 14.616 ;
    END
  END d[74]
  PIN d[75]
    DIRECTION INPUT ;
    USE SIGNAL ;
    PORT
      LAYER M4 ;
        RECT  0 14.784 0.192 14.808 ;
    END
  END d[75]
  PIN d[76]
    DIRECTION INPUT ;
    USE SIGNAL ;
    PORT
      LAYER M4 ;
        RECT  0 14.976 0.192 15 ;
    END
  END d[76]
  PIN d[77]
    DIRECTION INPUT ;
    USE SIGNAL ;
    PORT
      LAYER M4 ;
        RECT  0 15.168 0.192 15.192 ;
    END
  END d[77]
  PIN d[78]
    DIRECTION INPUT ;
    USE SIGNAL ;
    PORT
      LAYER M4 ;
        RECT  0 15.36 0.192 15.384 ;
    END
  END d[78]
  PIN d[79]
    DIRECTION INPUT ;
    USE SIGNAL ;
    PORT
      LAYER M4 ;
        RECT  0 15.552 0.192 15.576 ;
    END
  END d[79]
  PIN d[7]
    DIRECTION INPUT ;
    USE SIGNAL ;
    PORT
      LAYER M4 ;
        RECT  0 1.728 0.192 1.752 ;
    END
  END d[7]
  PIN d[80]
    DIRECTION INPUT ;
    USE SIGNAL ;
    PORT
      LAYER M4 ;
        RECT  0 15.744 0.192 15.768 ;
    END
  END d[80]
  PIN d[81]
    DIRECTION INPUT ;
    USE SIGNAL ;
    PORT
      LAYER M4 ;
        RECT  0 15.936 0.192 15.96 ;
    END
  END d[81]
  PIN d[82]
    DIRECTION INPUT ;
    USE SIGNAL ;
    PORT
      LAYER M4 ;
        RECT  0 16.128 0.192 16.152 ;
    END
  END d[82]
  PIN d[83]
    DIRECTION INPUT ;
    USE SIGNAL ;
    PORT
      LAYER M4 ;
        RECT  0 16.32 0.192 16.344 ;
    END
  END d[83]
  PIN d[84]
    DIRECTION INPUT ;
    USE SIGNAL ;
    PORT
      LAYER M4 ;
        RECT  0 16.512 0.192 16.536 ;
    END
  END d[84]
  PIN d[85]
    DIRECTION INPUT ;
    USE SIGNAL ;
    PORT
      LAYER M4 ;
        RECT  0 16.704 0.192 16.728 ;
    END
  END d[85]
  PIN d[86]
    DIRECTION INPUT ;
    USE SIGNAL ;
    PORT
      LAYER M4 ;
        RECT  0 16.896 0.192 16.92 ;
    END
  END d[86]
  PIN d[87]
    DIRECTION INPUT ;
    USE SIGNAL ;
    PORT
      LAYER M4 ;
        RECT  0 17.088 0.192 17.112 ;
    END
  END d[87]
  PIN d[88]
    DIRECTION INPUT ;
    USE SIGNAL ;
    PORT
      LAYER M4 ;
        RECT  0 17.28 0.192 17.304 ;
    END
  END d[88]
  PIN d[89]
    DIRECTION INPUT ;
    USE SIGNAL ;
    PORT
      LAYER M4 ;
        RECT  0 17.472 0.192 17.496 ;
    END
  END d[89]
  PIN d[8]
    DIRECTION INPUT ;
    USE SIGNAL ;
    PORT
      LAYER M4 ;
        RECT  0 1.92 0.192 1.944 ;
    END
  END d[8]
  PIN d[90]
    DIRECTION INPUT ;
    USE SIGNAL ;
    PORT
      LAYER M4 ;
        RECT  0 17.664 0.192 17.688 ;
    END
  END d[90]
  PIN d[91]
    DIRECTION INPUT ;
    USE SIGNAL ;
    PORT
      LAYER M4 ;
        RECT  0 17.856 0.192 17.88 ;
    END
  END d[91]
  PIN d[92]
    DIRECTION INPUT ;
    USE SIGNAL ;
    PORT
      LAYER M4 ;
        RECT  0 18.048 0.192 18.072 ;
    END
  END d[92]
  PIN d[93]
    DIRECTION INPUT ;
    USE SIGNAL ;
    PORT
      LAYER M4 ;
        RECT  0 18.24 0.192 18.264 ;
    END
  END d[93]
  PIN d[94]
    DIRECTION INPUT ;
    USE SIGNAL ;
    PORT
      LAYER M4 ;
        RECT  0 18.432 0.192 18.456 ;
    END
  END d[94]
  PIN d[95]
    DIRECTION INPUT ;
    USE SIGNAL ;
    PORT
      LAYER M4 ;
        RECT  0 18.624 0.192 18.648 ;
    END
  END d[95]
  PIN d[96]
    DIRECTION INPUT ;
    USE SIGNAL ;
    PORT
      LAYER M4 ;
        RECT  0 18.816 0.192 18.84 ;
    END
  END d[96]
  PIN d[97]
    DIRECTION INPUT ;
    USE SIGNAL ;
    PORT
      LAYER M4 ;
        RECT  0 19.008 0.192 19.032 ;
    END
  END d[97]
  PIN d[98]
    DIRECTION INPUT ;
    USE SIGNAL ;
    PORT
      LAYER M4 ;
        RECT  0 19.2 0.192 19.224 ;
    END
  END d[98]
  PIN d[99]
    DIRECTION INPUT ;
    USE SIGNAL ;
    PORT
      LAYER M4 ;
        RECT  0 19.392 0.192 19.416 ;
    END
  END d[99]
  PIN d[9]
    DIRECTION INPUT ;
    USE SIGNAL ;
    PORT
      LAYER M4 ;
        RECT  0 2.112 0.192 2.136 ;
    END
  END d[9]
  PIN q[0]
    DIRECTION OUTPUT ;
    USE SIGNAL ;
    PORT
      LAYER M4 ;
        RECT  11.688 0.384 11.88 0.408 ;
    END
  END q[0]
  PIN q[100]
    DIRECTION OUTPUT ;
    USE SIGNAL ;
    PORT
      LAYER M4 ;
        RECT  11.688 19.584 11.88 19.608 ;
    END
  END q[100]
  PIN q[101]
    DIRECTION OUTPUT ;
    USE SIGNAL ;
    PORT
      LAYER M4 ;
        RECT  11.688 19.776 11.88 19.8 ;
    END
  END q[101]
  PIN q[102]
    DIRECTION OUTPUT ;
    USE SIGNAL ;
    PORT
      LAYER M4 ;
        RECT  11.688 19.968 11.88 19.992 ;
    END
  END q[102]
  PIN q[103]
    DIRECTION OUTPUT ;
    USE SIGNAL ;
    PORT
      LAYER M4 ;
        RECT  11.688 20.16 11.88 20.184 ;
    END
  END q[103]
  PIN q[104]
    DIRECTION OUTPUT ;
    USE SIGNAL ;
    PORT
      LAYER M4 ;
        RECT  11.688 20.352 11.88 20.376 ;
    END
  END q[104]
  PIN q[105]
    DIRECTION OUTPUT ;
    USE SIGNAL ;
    PORT
      LAYER M4 ;
        RECT  11.688 20.544 11.88 20.568 ;
    END
  END q[105]
  PIN q[106]
    DIRECTION OUTPUT ;
    USE SIGNAL ;
    PORT
      LAYER M4 ;
        RECT  11.688 20.736 11.88 20.76 ;
    END
  END q[106]
  PIN q[107]
    DIRECTION OUTPUT ;
    USE SIGNAL ;
    PORT
      LAYER M4 ;
        RECT  11.688 20.928 11.88 20.952 ;
    END
  END q[107]
  PIN q[108]
    DIRECTION OUTPUT ;
    USE SIGNAL ;
    PORT
      LAYER M4 ;
        RECT  11.688 21.12 11.88 21.144 ;
    END
  END q[108]
  PIN q[109]
    DIRECTION OUTPUT ;
    USE SIGNAL ;
    PORT
      LAYER M4 ;
        RECT  11.688 21.312 11.88 21.336 ;
    END
  END q[109]
  PIN q[10]
    DIRECTION OUTPUT ;
    USE SIGNAL ;
    PORT
      LAYER M4 ;
        RECT  11.688 2.304 11.88 2.328 ;
    END
  END q[10]
  PIN q[110]
    DIRECTION OUTPUT ;
    USE SIGNAL ;
    PORT
      LAYER M4 ;
        RECT  11.688 21.504 11.88 21.528 ;
    END
  END q[110]
  PIN q[111]
    DIRECTION OUTPUT ;
    USE SIGNAL ;
    PORT
      LAYER M4 ;
        RECT  11.688 21.696 11.88 21.72 ;
    END
  END q[111]
  PIN q[112]
    DIRECTION OUTPUT ;
    USE SIGNAL ;
    PORT
      LAYER M4 ;
        RECT  11.688 21.888 11.88 21.912 ;
    END
  END q[112]
  PIN q[113]
    DIRECTION OUTPUT ;
    USE SIGNAL ;
    PORT
      LAYER M4 ;
        RECT  11.688 22.08 11.88 22.104 ;
    END
  END q[113]
  PIN q[114]
    DIRECTION OUTPUT ;
    USE SIGNAL ;
    PORT
      LAYER M4 ;
        RECT  11.688 22.272 11.88 22.296 ;
    END
  END q[114]
  PIN q[115]
    DIRECTION OUTPUT ;
    USE SIGNAL ;
    PORT
      LAYER M4 ;
        RECT  11.688 22.464 11.88 22.488 ;
    END
  END q[115]
  PIN q[116]
    DIRECTION OUTPUT ;
    USE SIGNAL ;
    PORT
      LAYER M4 ;
        RECT  11.688 22.656 11.88 22.68 ;
    END
  END q[116]
  PIN q[117]
    DIRECTION OUTPUT ;
    USE SIGNAL ;
    PORT
      LAYER M4 ;
        RECT  11.688 22.848 11.88 22.872 ;
    END
  END q[117]
  PIN q[118]
    DIRECTION OUTPUT ;
    USE SIGNAL ;
    PORT
      LAYER M4 ;
        RECT  11.688 23.04 11.88 23.064 ;
    END
  END q[118]
  PIN q[119]
    DIRECTION OUTPUT ;
    USE SIGNAL ;
    PORT
      LAYER M4 ;
        RECT  11.688 23.232 11.88 23.256 ;
    END
  END q[119]
  PIN q[11]
    DIRECTION OUTPUT ;
    USE SIGNAL ;
    PORT
      LAYER M4 ;
        RECT  11.688 2.496 11.88 2.52 ;
    END
  END q[11]
  PIN q[120]
    DIRECTION OUTPUT ;
    USE SIGNAL ;
    PORT
      LAYER M4 ;
        RECT  11.688 23.424 11.88 23.448 ;
    END
  END q[120]
  PIN q[121]
    DIRECTION OUTPUT ;
    USE SIGNAL ;
    PORT
      LAYER M4 ;
        RECT  11.688 23.616 11.88 23.64 ;
    END
  END q[121]
  PIN q[122]
    DIRECTION OUTPUT ;
    USE SIGNAL ;
    PORT
      LAYER M4 ;
        RECT  11.688 23.808 11.88 23.832 ;
    END
  END q[122]
  PIN q[123]
    DIRECTION OUTPUT ;
    USE SIGNAL ;
    PORT
      LAYER M4 ;
        RECT  11.688 24 11.88 24.024 ;
    END
  END q[123]
  PIN q[124]
    DIRECTION OUTPUT ;
    USE SIGNAL ;
    PORT
      LAYER M4 ;
        RECT  11.688 24.192 11.88 24.216 ;
    END
  END q[124]
  PIN q[125]
    DIRECTION OUTPUT ;
    USE SIGNAL ;
    PORT
      LAYER M4 ;
        RECT  11.688 24.384 11.88 24.408 ;
    END
  END q[125]
  PIN q[126]
    DIRECTION OUTPUT ;
    USE SIGNAL ;
    PORT
      LAYER M4 ;
        RECT  11.688 24.576 11.88 24.6 ;
    END
  END q[126]
  PIN q[127]
    DIRECTION OUTPUT ;
    USE SIGNAL ;
    PORT
      LAYER M4 ;
        RECT  11.688 24.768 11.88 24.792 ;
    END
  END q[127]
  PIN q[128]
    DIRECTION OUTPUT ;
    USE SIGNAL ;
    PORT
      LAYER M4 ;
        RECT  11.688 24.96 11.88 24.984 ;
    END
  END q[128]
  PIN q[129]
    DIRECTION OUTPUT ;
    USE SIGNAL ;
    PORT
      LAYER M4 ;
        RECT  11.688 25.152 11.88 25.176 ;
    END
  END q[129]
  PIN q[12]
    DIRECTION OUTPUT ;
    USE SIGNAL ;
    PORT
      LAYER M4 ;
        RECT  11.688 2.688 11.88 2.712 ;
    END
  END q[12]
  PIN q[130]
    DIRECTION OUTPUT ;
    USE SIGNAL ;
    PORT
      LAYER M4 ;
        RECT  11.688 25.344 11.88 25.368 ;
    END
  END q[130]
  PIN q[131]
    DIRECTION OUTPUT ;
    USE SIGNAL ;
    PORT
      LAYER M4 ;
        RECT  11.688 25.536 11.88 25.56 ;
    END
  END q[131]
  PIN q[132]
    DIRECTION OUTPUT ;
    USE SIGNAL ;
    PORT
      LAYER M4 ;
        RECT  11.688 25.728 11.88 25.752 ;
    END
  END q[132]
  PIN q[133]
    DIRECTION OUTPUT ;
    USE SIGNAL ;
    PORT
      LAYER M4 ;
        RECT  11.688 25.92 11.88 25.944 ;
    END
  END q[133]
  PIN q[134]
    DIRECTION OUTPUT ;
    USE SIGNAL ;
    PORT
      LAYER M4 ;
        RECT  11.688 26.112 11.88 26.136 ;
    END
  END q[134]
  PIN q[135]
    DIRECTION OUTPUT ;
    USE SIGNAL ;
    PORT
      LAYER M4 ;
        RECT  11.688 26.304 11.88 26.328 ;
    END
  END q[135]
  PIN q[136]
    DIRECTION OUTPUT ;
    USE SIGNAL ;
    PORT
      LAYER M4 ;
        RECT  11.688 26.496 11.88 26.52 ;
    END
  END q[136]
  PIN q[137]
    DIRECTION OUTPUT ;
    USE SIGNAL ;
    PORT
      LAYER M4 ;
        RECT  11.688 26.688 11.88 26.712 ;
    END
  END q[137]
  PIN q[138]
    DIRECTION OUTPUT ;
    USE SIGNAL ;
    PORT
      LAYER M4 ;
        RECT  11.688 26.88 11.88 26.904 ;
    END
  END q[138]
  PIN q[139]
    DIRECTION OUTPUT ;
    USE SIGNAL ;
    PORT
      LAYER M4 ;
        RECT  11.688 27.072 11.88 27.096 ;
    END
  END q[139]
  PIN q[13]
    DIRECTION OUTPUT ;
    USE SIGNAL ;
    PORT
      LAYER M4 ;
        RECT  11.688 2.88 11.88 2.904 ;
    END
  END q[13]
  PIN q[140]
    DIRECTION OUTPUT ;
    USE SIGNAL ;
    PORT
      LAYER M4 ;
        RECT  11.688 27.264 11.88 27.288 ;
    END
  END q[140]
  PIN q[141]
    DIRECTION OUTPUT ;
    USE SIGNAL ;
    PORT
      LAYER M4 ;
        RECT  11.688 27.456 11.88 27.48 ;
    END
  END q[141]
  PIN q[142]
    DIRECTION OUTPUT ;
    USE SIGNAL ;
    PORT
      LAYER M4 ;
        RECT  11.688 27.648 11.88 27.672 ;
    END
  END q[142]
  PIN q[143]
    DIRECTION OUTPUT ;
    USE SIGNAL ;
    PORT
      LAYER M4 ;
        RECT  11.688 27.84 11.88 27.864 ;
    END
  END q[143]
  PIN q[144]
    DIRECTION OUTPUT ;
    USE SIGNAL ;
    PORT
      LAYER M4 ;
        RECT  11.688 28.032 11.88 28.056 ;
    END
  END q[144]
  PIN q[145]
    DIRECTION OUTPUT ;
    USE SIGNAL ;
    PORT
      LAYER M4 ;
        RECT  11.688 28.224 11.88 28.248 ;
    END
  END q[145]
  PIN q[146]
    DIRECTION OUTPUT ;
    USE SIGNAL ;
    PORT
      LAYER M4 ;
        RECT  11.688 28.416 11.88 28.44 ;
    END
  END q[146]
  PIN q[147]
    DIRECTION OUTPUT ;
    USE SIGNAL ;
    PORT
      LAYER M4 ;
        RECT  11.688 28.608 11.88 28.632 ;
    END
  END q[147]
  PIN q[148]
    DIRECTION OUTPUT ;
    USE SIGNAL ;
    PORT
      LAYER M4 ;
        RECT  11.688 28.8 11.88 28.824 ;
    END
  END q[148]
  PIN q[149]
    DIRECTION OUTPUT ;
    USE SIGNAL ;
    PORT
      LAYER M4 ;
        RECT  11.688 28.992 11.88 29.016 ;
    END
  END q[149]
  PIN q[14]
    DIRECTION OUTPUT ;
    USE SIGNAL ;
    PORT
      LAYER M4 ;
        RECT  11.688 3.072 11.88 3.096 ;
    END
  END q[14]
  PIN q[150]
    DIRECTION OUTPUT ;
    USE SIGNAL ;
    PORT
      LAYER M4 ;
        RECT  11.688 29.184 11.88 29.208 ;
    END
  END q[150]
  PIN q[151]
    DIRECTION OUTPUT ;
    USE SIGNAL ;
    PORT
      LAYER M4 ;
        RECT  11.688 29.376 11.88 29.4 ;
    END
  END q[151]
  PIN q[152]
    DIRECTION OUTPUT ;
    USE SIGNAL ;
    PORT
      LAYER M4 ;
        RECT  11.688 29.568 11.88 29.592 ;
    END
  END q[152]
  PIN q[153]
    DIRECTION OUTPUT ;
    USE SIGNAL ;
    PORT
      LAYER M4 ;
        RECT  11.688 29.76 11.88 29.784 ;
    END
  END q[153]
  PIN q[154]
    DIRECTION OUTPUT ;
    USE SIGNAL ;
    PORT
      LAYER M4 ;
        RECT  11.688 29.952 11.88 29.976 ;
    END
  END q[154]
  PIN q[155]
    DIRECTION OUTPUT ;
    USE SIGNAL ;
    PORT
      LAYER M4 ;
        RECT  11.688 30.144 11.88 30.168 ;
    END
  END q[155]
  PIN q[156]
    DIRECTION OUTPUT ;
    USE SIGNAL ;
    PORT
      LAYER M4 ;
        RECT  11.688 30.336 11.88 30.36 ;
    END
  END q[156]
  PIN q[157]
    DIRECTION OUTPUT ;
    USE SIGNAL ;
    PORT
      LAYER M4 ;
        RECT  11.688 30.528 11.88 30.552 ;
    END
  END q[157]
  PIN q[158]
    DIRECTION OUTPUT ;
    USE SIGNAL ;
    PORT
      LAYER M4 ;
        RECT  11.688 30.72 11.88 30.744 ;
    END
  END q[158]
  PIN q[159]
    DIRECTION OUTPUT ;
    USE SIGNAL ;
    PORT
      LAYER M4 ;
        RECT  11.688 30.912 11.88 30.936 ;
    END
  END q[159]
  PIN q[15]
    DIRECTION OUTPUT ;
    USE SIGNAL ;
    PORT
      LAYER M4 ;
        RECT  11.688 3.264 11.88 3.288 ;
    END
  END q[15]
  PIN q[160]
    DIRECTION OUTPUT ;
    USE SIGNAL ;
    PORT
      LAYER M4 ;
        RECT  11.688 31.104 11.88 31.128 ;
    END
  END q[160]
  PIN q[161]
    DIRECTION OUTPUT ;
    USE SIGNAL ;
    PORT
      LAYER M4 ;
        RECT  11.688 31.296 11.88 31.32 ;
    END
  END q[161]
  PIN q[162]
    DIRECTION OUTPUT ;
    USE SIGNAL ;
    PORT
      LAYER M4 ;
        RECT  11.688 31.488 11.88 31.512 ;
    END
  END q[162]
  PIN q[163]
    DIRECTION OUTPUT ;
    USE SIGNAL ;
    PORT
      LAYER M4 ;
        RECT  11.688 31.68 11.88 31.704 ;
    END
  END q[163]
  PIN q[164]
    DIRECTION OUTPUT ;
    USE SIGNAL ;
    PORT
      LAYER M4 ;
        RECT  11.688 31.872 11.88 31.896 ;
    END
  END q[164]
  PIN q[165]
    DIRECTION OUTPUT ;
    USE SIGNAL ;
    PORT
      LAYER M4 ;
        RECT  11.688 32.064 11.88 32.088 ;
    END
  END q[165]
  PIN q[166]
    DIRECTION OUTPUT ;
    USE SIGNAL ;
    PORT
      LAYER M4 ;
        RECT  11.688 32.256 11.88 32.28 ;
    END
  END q[166]
  PIN q[167]
    DIRECTION OUTPUT ;
    USE SIGNAL ;
    PORT
      LAYER M4 ;
        RECT  11.688 32.448 11.88 32.472 ;
    END
  END q[167]
  PIN q[168]
    DIRECTION OUTPUT ;
    USE SIGNAL ;
    PORT
      LAYER M4 ;
        RECT  11.688 32.64 11.88 32.664 ;
    END
  END q[168]
  PIN q[169]
    DIRECTION OUTPUT ;
    USE SIGNAL ;
    PORT
      LAYER M4 ;
        RECT  11.688 32.832 11.88 32.856 ;
    END
  END q[169]
  PIN q[16]
    DIRECTION OUTPUT ;
    USE SIGNAL ;
    PORT
      LAYER M4 ;
        RECT  11.688 3.456 11.88 3.48 ;
    END
  END q[16]
  PIN q[170]
    DIRECTION OUTPUT ;
    USE SIGNAL ;
    PORT
      LAYER M4 ;
        RECT  11.688 33.024 11.88 33.048 ;
    END
  END q[170]
  PIN q[171]
    DIRECTION OUTPUT ;
    USE SIGNAL ;
    PORT
      LAYER M4 ;
        RECT  11.688 33.216 11.88 33.24 ;
    END
  END q[171]
  PIN q[172]
    DIRECTION OUTPUT ;
    USE SIGNAL ;
    PORT
      LAYER M4 ;
        RECT  11.688 33.408 11.88 33.432 ;
    END
  END q[172]
  PIN q[173]
    DIRECTION OUTPUT ;
    USE SIGNAL ;
    PORT
      LAYER M4 ;
        RECT  11.688 33.6 11.88 33.624 ;
    END
  END q[173]
  PIN q[174]
    DIRECTION OUTPUT ;
    USE SIGNAL ;
    PORT
      LAYER M4 ;
        RECT  11.688 33.792 11.88 33.816 ;
    END
  END q[174]
  PIN q[175]
    DIRECTION OUTPUT ;
    USE SIGNAL ;
    PORT
      LAYER M4 ;
        RECT  11.688 33.984 11.88 34.008 ;
    END
  END q[175]
  PIN q[176]
    DIRECTION OUTPUT ;
    USE SIGNAL ;
    PORT
      LAYER M4 ;
        RECT  11.688 34.176 11.88 34.2 ;
    END
  END q[176]
  PIN q[177]
    DIRECTION OUTPUT ;
    USE SIGNAL ;
    PORT
      LAYER M4 ;
        RECT  11.688 34.368 11.88 34.392 ;
    END
  END q[177]
  PIN q[178]
    DIRECTION OUTPUT ;
    USE SIGNAL ;
    PORT
      LAYER M4 ;
        RECT  11.688 34.56 11.88 34.584 ;
    END
  END q[178]
  PIN q[179]
    DIRECTION OUTPUT ;
    USE SIGNAL ;
    PORT
      LAYER M4 ;
        RECT  11.688 34.752 11.88 34.776 ;
    END
  END q[179]
  PIN q[17]
    DIRECTION OUTPUT ;
    USE SIGNAL ;
    PORT
      LAYER M4 ;
        RECT  11.688 3.648 11.88 3.672 ;
    END
  END q[17]
  PIN q[180]
    DIRECTION OUTPUT ;
    USE SIGNAL ;
    PORT
      LAYER M4 ;
        RECT  11.688 34.944 11.88 34.968 ;
    END
  END q[180]
  PIN q[181]
    DIRECTION OUTPUT ;
    USE SIGNAL ;
    PORT
      LAYER M4 ;
        RECT  11.688 35.136 11.88 35.16 ;
    END
  END q[181]
  PIN q[182]
    DIRECTION OUTPUT ;
    USE SIGNAL ;
    PORT
      LAYER M4 ;
        RECT  11.688 35.328 11.88 35.352 ;
    END
  END q[182]
  PIN q[183]
    DIRECTION OUTPUT ;
    USE SIGNAL ;
    PORT
      LAYER M4 ;
        RECT  11.688 35.52 11.88 35.544 ;
    END
  END q[183]
  PIN q[184]
    DIRECTION OUTPUT ;
    USE SIGNAL ;
    PORT
      LAYER M4 ;
        RECT  11.688 35.712 11.88 35.736 ;
    END
  END q[184]
  PIN q[185]
    DIRECTION OUTPUT ;
    USE SIGNAL ;
    PORT
      LAYER M4 ;
        RECT  11.688 35.904 11.88 35.928 ;
    END
  END q[185]
  PIN q[186]
    DIRECTION OUTPUT ;
    USE SIGNAL ;
    PORT
      LAYER M4 ;
        RECT  11.688 36.096 11.88 36.12 ;
    END
  END q[186]
  PIN q[187]
    DIRECTION OUTPUT ;
    USE SIGNAL ;
    PORT
      LAYER M4 ;
        RECT  11.688 36.288 11.88 36.312 ;
    END
  END q[187]
  PIN q[188]
    DIRECTION OUTPUT ;
    USE SIGNAL ;
    PORT
      LAYER M4 ;
        RECT  11.688 36.48 11.88 36.504 ;
    END
  END q[188]
  PIN q[189]
    DIRECTION OUTPUT ;
    USE SIGNAL ;
    PORT
      LAYER M4 ;
        RECT  11.688 36.672 11.88 36.696 ;
    END
  END q[189]
  PIN q[18]
    DIRECTION OUTPUT ;
    USE SIGNAL ;
    PORT
      LAYER M4 ;
        RECT  11.688 3.84 11.88 3.864 ;
    END
  END q[18]
  PIN q[190]
    DIRECTION OUTPUT ;
    USE SIGNAL ;
    PORT
      LAYER M4 ;
        RECT  11.688 36.864 11.88 36.888 ;
    END
  END q[190]
  PIN q[191]
    DIRECTION OUTPUT ;
    USE SIGNAL ;
    PORT
      LAYER M4 ;
        RECT  11.688 37.056 11.88 37.08 ;
    END
  END q[191]
  PIN q[192]
    DIRECTION OUTPUT ;
    USE SIGNAL ;
    PORT
      LAYER M4 ;
        RECT  11.688 37.248 11.88 37.272 ;
    END
  END q[192]
  PIN q[193]
    DIRECTION OUTPUT ;
    USE SIGNAL ;
    PORT
      LAYER M4 ;
        RECT  11.688 37.44 11.88 37.464 ;
    END
  END q[193]
  PIN q[194]
    DIRECTION OUTPUT ;
    USE SIGNAL ;
    PORT
      LAYER M4 ;
        RECT  11.688 37.632 11.88 37.656 ;
    END
  END q[194]
  PIN q[195]
    DIRECTION OUTPUT ;
    USE SIGNAL ;
    PORT
      LAYER M4 ;
        RECT  11.688 37.824 11.88 37.848 ;
    END
  END q[195]
  PIN q[196]
    DIRECTION OUTPUT ;
    USE SIGNAL ;
    PORT
      LAYER M4 ;
        RECT  11.688 38.016 11.88 38.04 ;
    END
  END q[196]
  PIN q[197]
    DIRECTION OUTPUT ;
    USE SIGNAL ;
    PORT
      LAYER M4 ;
        RECT  11.688 38.208 11.88 38.232 ;
    END
  END q[197]
  PIN q[198]
    DIRECTION OUTPUT ;
    USE SIGNAL ;
    PORT
      LAYER M4 ;
        RECT  11.688 38.4 11.88 38.424 ;
    END
  END q[198]
  PIN q[199]
    DIRECTION OUTPUT ;
    USE SIGNAL ;
    PORT
      LAYER M4 ;
        RECT  11.688 38.592 11.88 38.616 ;
    END
  END q[199]
  PIN q[19]
    DIRECTION OUTPUT ;
    USE SIGNAL ;
    PORT
      LAYER M4 ;
        RECT  11.688 4.032 11.88 4.056 ;
    END
  END q[19]
  PIN q[1]
    DIRECTION OUTPUT ;
    USE SIGNAL ;
    PORT
      LAYER M4 ;
        RECT  11.688 0.576 11.88 0.6 ;
    END
  END q[1]
  PIN q[200]
    DIRECTION OUTPUT ;
    USE SIGNAL ;
    PORT
      LAYER M4 ;
        RECT  11.688 38.784 11.88 38.808 ;
    END
  END q[200]
  PIN q[201]
    DIRECTION OUTPUT ;
    USE SIGNAL ;
    PORT
      LAYER M4 ;
        RECT  11.688 38.976 11.88 39 ;
    END
  END q[201]
  PIN q[202]
    DIRECTION OUTPUT ;
    USE SIGNAL ;
    PORT
      LAYER M4 ;
        RECT  11.688 39.168 11.88 39.192 ;
    END
  END q[202]
  PIN q[203]
    DIRECTION OUTPUT ;
    USE SIGNAL ;
    PORT
      LAYER M4 ;
        RECT  11.688 39.36 11.88 39.384 ;
    END
  END q[203]
  PIN q[204]
    DIRECTION OUTPUT ;
    USE SIGNAL ;
    PORT
      LAYER M4 ;
        RECT  11.688 39.552 11.88 39.576 ;
    END
  END q[204]
  PIN q[205]
    DIRECTION OUTPUT ;
    USE SIGNAL ;
    PORT
      LAYER M4 ;
        RECT  11.688 39.744 11.88 39.768 ;
    END
  END q[205]
  PIN q[206]
    DIRECTION OUTPUT ;
    USE SIGNAL ;
    PORT
      LAYER M4 ;
        RECT  11.688 39.936 11.88 39.96 ;
    END
  END q[206]
  PIN q[207]
    DIRECTION OUTPUT ;
    USE SIGNAL ;
    PORT
      LAYER M4 ;
        RECT  11.688 40.128 11.88 40.152 ;
    END
  END q[207]
  PIN q[208]
    DIRECTION OUTPUT ;
    USE SIGNAL ;
    PORT
      LAYER M4 ;
        RECT  11.688 40.32 11.88 40.344 ;
    END
  END q[208]
  PIN q[209]
    DIRECTION OUTPUT ;
    USE SIGNAL ;
    PORT
      LAYER M4 ;
        RECT  11.688 40.512 11.88 40.536 ;
    END
  END q[209]
  PIN q[20]
    DIRECTION OUTPUT ;
    USE SIGNAL ;
    PORT
      LAYER M4 ;
        RECT  11.688 4.224 11.88 4.248 ;
    END
  END q[20]
  PIN q[210]
    DIRECTION OUTPUT ;
    USE SIGNAL ;
    PORT
      LAYER M4 ;
        RECT  11.688 40.704 11.88 40.728 ;
    END
  END q[210]
  PIN q[211]
    DIRECTION OUTPUT ;
    USE SIGNAL ;
    PORT
      LAYER M4 ;
        RECT  11.688 40.896 11.88 40.92 ;
    END
  END q[211]
  PIN q[212]
    DIRECTION OUTPUT ;
    USE SIGNAL ;
    PORT
      LAYER M4 ;
        RECT  11.688 41.088 11.88 41.112 ;
    END
  END q[212]
  PIN q[213]
    DIRECTION OUTPUT ;
    USE SIGNAL ;
    PORT
      LAYER M4 ;
        RECT  11.688 41.28 11.88 41.304 ;
    END
  END q[213]
  PIN q[214]
    DIRECTION OUTPUT ;
    USE SIGNAL ;
    PORT
      LAYER M4 ;
        RECT  11.688 41.472 11.88 41.496 ;
    END
  END q[214]
  PIN q[215]
    DIRECTION OUTPUT ;
    USE SIGNAL ;
    PORT
      LAYER M4 ;
        RECT  11.688 41.664 11.88 41.688 ;
    END
  END q[215]
  PIN q[216]
    DIRECTION OUTPUT ;
    USE SIGNAL ;
    PORT
      LAYER M4 ;
        RECT  11.688 41.856 11.88 41.88 ;
    END
  END q[216]
  PIN q[217]
    DIRECTION OUTPUT ;
    USE SIGNAL ;
    PORT
      LAYER M4 ;
        RECT  11.688 42.048 11.88 42.072 ;
    END
  END q[217]
  PIN q[218]
    DIRECTION OUTPUT ;
    USE SIGNAL ;
    PORT
      LAYER M4 ;
        RECT  11.688 42.24 11.88 42.264 ;
    END
  END q[218]
  PIN q[219]
    DIRECTION OUTPUT ;
    USE SIGNAL ;
    PORT
      LAYER M4 ;
        RECT  11.688 42.432 11.88 42.456 ;
    END
  END q[219]
  PIN q[21]
    DIRECTION OUTPUT ;
    USE SIGNAL ;
    PORT
      LAYER M4 ;
        RECT  11.688 4.416 11.88 4.44 ;
    END
  END q[21]
  PIN q[220]
    DIRECTION OUTPUT ;
    USE SIGNAL ;
    PORT
      LAYER M4 ;
        RECT  11.688 42.624 11.88 42.648 ;
    END
  END q[220]
  PIN q[221]
    DIRECTION OUTPUT ;
    USE SIGNAL ;
    PORT
      LAYER M4 ;
        RECT  11.688 42.816 11.88 42.84 ;
    END
  END q[221]
  PIN q[222]
    DIRECTION OUTPUT ;
    USE SIGNAL ;
    PORT
      LAYER M4 ;
        RECT  11.688 43.008 11.88 43.032 ;
    END
  END q[222]
  PIN q[223]
    DIRECTION OUTPUT ;
    USE SIGNAL ;
    PORT
      LAYER M4 ;
        RECT  11.688 43.2 11.88 43.224 ;
    END
  END q[223]
  PIN q[224]
    DIRECTION OUTPUT ;
    USE SIGNAL ;
    PORT
      LAYER M4 ;
        RECT  11.688 43.392 11.88 43.416 ;
    END
  END q[224]
  PIN q[225]
    DIRECTION OUTPUT ;
    USE SIGNAL ;
    PORT
      LAYER M4 ;
        RECT  11.688 43.584 11.88 43.608 ;
    END
  END q[225]
  PIN q[226]
    DIRECTION OUTPUT ;
    USE SIGNAL ;
    PORT
      LAYER M4 ;
        RECT  11.688 43.776 11.88 43.8 ;
    END
  END q[226]
  PIN q[227]
    DIRECTION OUTPUT ;
    USE SIGNAL ;
    PORT
      LAYER M4 ;
        RECT  11.688 43.968 11.88 43.992 ;
    END
  END q[227]
  PIN q[228]
    DIRECTION OUTPUT ;
    USE SIGNAL ;
    PORT
      LAYER M4 ;
        RECT  11.688 44.16 11.88 44.184 ;
    END
  END q[228]
  PIN q[229]
    DIRECTION OUTPUT ;
    USE SIGNAL ;
    PORT
      LAYER M4 ;
        RECT  11.688 44.352 11.88 44.376 ;
    END
  END q[229]
  PIN q[22]
    DIRECTION OUTPUT ;
    USE SIGNAL ;
    PORT
      LAYER M4 ;
        RECT  11.688 4.608 11.88 4.632 ;
    END
  END q[22]
  PIN q[230]
    DIRECTION OUTPUT ;
    USE SIGNAL ;
    PORT
      LAYER M4 ;
        RECT  11.688 44.544 11.88 44.568 ;
    END
  END q[230]
  PIN q[231]
    DIRECTION OUTPUT ;
    USE SIGNAL ;
    PORT
      LAYER M4 ;
        RECT  11.688 44.736 11.88 44.76 ;
    END
  END q[231]
  PIN q[232]
    DIRECTION OUTPUT ;
    USE SIGNAL ;
    PORT
      LAYER M4 ;
        RECT  11.688 44.928 11.88 44.952 ;
    END
  END q[232]
  PIN q[233]
    DIRECTION OUTPUT ;
    USE SIGNAL ;
    PORT
      LAYER M4 ;
        RECT  11.688 45.12 11.88 45.144 ;
    END
  END q[233]
  PIN q[234]
    DIRECTION OUTPUT ;
    USE SIGNAL ;
    PORT
      LAYER M4 ;
        RECT  11.688 45.312 11.88 45.336 ;
    END
  END q[234]
  PIN q[235]
    DIRECTION OUTPUT ;
    USE SIGNAL ;
    PORT
      LAYER M4 ;
        RECT  11.688 45.504 11.88 45.528 ;
    END
  END q[235]
  PIN q[236]
    DIRECTION OUTPUT ;
    USE SIGNAL ;
    PORT
      LAYER M4 ;
        RECT  11.688 45.696 11.88 45.72 ;
    END
  END q[236]
  PIN q[237]
    DIRECTION OUTPUT ;
    USE SIGNAL ;
    PORT
      LAYER M4 ;
        RECT  11.688 45.888 11.88 45.912 ;
    END
  END q[237]
  PIN q[238]
    DIRECTION OUTPUT ;
    USE SIGNAL ;
    PORT
      LAYER M4 ;
        RECT  11.688 46.08 11.88 46.104 ;
    END
  END q[238]
  PIN q[239]
    DIRECTION OUTPUT ;
    USE SIGNAL ;
    PORT
      LAYER M4 ;
        RECT  11.688 46.272 11.88 46.296 ;
    END
  END q[239]
  PIN q[23]
    DIRECTION OUTPUT ;
    USE SIGNAL ;
    PORT
      LAYER M4 ;
        RECT  11.688 4.8 11.88 4.824 ;
    END
  END q[23]
  PIN q[240]
    DIRECTION OUTPUT ;
    USE SIGNAL ;
    PORT
      LAYER M4 ;
        RECT  11.688 46.464 11.88 46.488 ;
    END
  END q[240]
  PIN q[241]
    DIRECTION OUTPUT ;
    USE SIGNAL ;
    PORT
      LAYER M4 ;
        RECT  11.688 46.656 11.88 46.68 ;
    END
  END q[241]
  PIN q[242]
    DIRECTION OUTPUT ;
    USE SIGNAL ;
    PORT
      LAYER M4 ;
        RECT  11.688 46.848 11.88 46.872 ;
    END
  END q[242]
  PIN q[243]
    DIRECTION OUTPUT ;
    USE SIGNAL ;
    PORT
      LAYER M4 ;
        RECT  11.688 47.04 11.88 47.064 ;
    END
  END q[243]
  PIN q[244]
    DIRECTION OUTPUT ;
    USE SIGNAL ;
    PORT
      LAYER M4 ;
        RECT  11.688 47.232 11.88 47.256 ;
    END
  END q[244]
  PIN q[245]
    DIRECTION OUTPUT ;
    USE SIGNAL ;
    PORT
      LAYER M4 ;
        RECT  11.688 47.424 11.88 47.448 ;
    END
  END q[245]
  PIN q[246]
    DIRECTION OUTPUT ;
    USE SIGNAL ;
    PORT
      LAYER M4 ;
        RECT  11.688 47.616 11.88 47.64 ;
    END
  END q[246]
  PIN q[247]
    DIRECTION OUTPUT ;
    USE SIGNAL ;
    PORT
      LAYER M4 ;
        RECT  11.688 47.808 11.88 47.832 ;
    END
  END q[247]
  PIN q[248]
    DIRECTION OUTPUT ;
    USE SIGNAL ;
    PORT
      LAYER M4 ;
        RECT  11.688 48 11.88 48.024 ;
    END
  END q[248]
  PIN q[249]
    DIRECTION OUTPUT ;
    USE SIGNAL ;
    PORT
      LAYER M4 ;
        RECT  11.688 48.192 11.88 48.216 ;
    END
  END q[249]
  PIN q[24]
    DIRECTION OUTPUT ;
    USE SIGNAL ;
    PORT
      LAYER M4 ;
        RECT  11.688 4.992 11.88 5.016 ;
    END
  END q[24]
  PIN q[250]
    DIRECTION OUTPUT ;
    USE SIGNAL ;
    PORT
      LAYER M4 ;
        RECT  11.688 48.384 11.88 48.408 ;
    END
  END q[250]
  PIN q[251]
    DIRECTION OUTPUT ;
    USE SIGNAL ;
    PORT
      LAYER M4 ;
        RECT  11.688 48.576 11.88 48.6 ;
    END
  END q[251]
  PIN q[252]
    DIRECTION OUTPUT ;
    USE SIGNAL ;
    PORT
      LAYER M4 ;
        RECT  11.688 48.768 11.88 48.792 ;
    END
  END q[252]
  PIN q[253]
    DIRECTION OUTPUT ;
    USE SIGNAL ;
    PORT
      LAYER M4 ;
        RECT  11.688 48.96 11.88 48.984 ;
    END
  END q[253]
  PIN q[254]
    DIRECTION OUTPUT ;
    USE SIGNAL ;
    PORT
      LAYER M4 ;
        RECT  11.688 49.152 11.88 49.176 ;
    END
  END q[254]
  PIN q[255]
    DIRECTION OUTPUT ;
    USE SIGNAL ;
    PORT
      LAYER M4 ;
        RECT  11.688 49.344 11.88 49.368 ;
    END
  END q[255]
  PIN q[256]
    DIRECTION OUTPUT ;
    USE SIGNAL ;
    PORT
      LAYER M4 ;
        RECT  11.688 49.536 11.88 49.56 ;
    END
  END q[256]
  PIN q[257]
    DIRECTION OUTPUT ;
    USE SIGNAL ;
    PORT
      LAYER M4 ;
        RECT  11.688 49.728 11.88 49.752 ;
    END
  END q[257]
  PIN q[258]
    DIRECTION OUTPUT ;
    USE SIGNAL ;
    PORT
      LAYER M4 ;
        RECT  11.688 49.92 11.88 49.944 ;
    END
  END q[258]
  PIN q[259]
    DIRECTION OUTPUT ;
    USE SIGNAL ;
    PORT
      LAYER M4 ;
        RECT  11.688 50.112 11.88 50.136 ;
    END
  END q[259]
  PIN q[25]
    DIRECTION OUTPUT ;
    USE SIGNAL ;
    PORT
      LAYER M4 ;
        RECT  11.688 5.184 11.88 5.208 ;
    END
  END q[25]
  PIN q[260]
    DIRECTION OUTPUT ;
    USE SIGNAL ;
    PORT
      LAYER M4 ;
        RECT  11.688 50.304 11.88 50.328 ;
    END
  END q[260]
  PIN q[261]
    DIRECTION OUTPUT ;
    USE SIGNAL ;
    PORT
      LAYER M4 ;
        RECT  11.688 50.496 11.88 50.52 ;
    END
  END q[261]
  PIN q[262]
    DIRECTION OUTPUT ;
    USE SIGNAL ;
    PORT
      LAYER M4 ;
        RECT  11.688 50.688 11.88 50.712 ;
    END
  END q[262]
  PIN q[263]
    DIRECTION OUTPUT ;
    USE SIGNAL ;
    PORT
      LAYER M4 ;
        RECT  11.688 50.88 11.88 50.904 ;
    END
  END q[263]
  PIN q[264]
    DIRECTION OUTPUT ;
    USE SIGNAL ;
    PORT
      LAYER M4 ;
        RECT  11.688 51.072 11.88 51.096 ;
    END
  END q[264]
  PIN q[265]
    DIRECTION OUTPUT ;
    USE SIGNAL ;
    PORT
      LAYER M4 ;
        RECT  11.688 51.264 11.88 51.288 ;
    END
  END q[265]
  PIN q[266]
    DIRECTION OUTPUT ;
    USE SIGNAL ;
    PORT
      LAYER M4 ;
        RECT  11.688 51.456 11.88 51.48 ;
    END
  END q[266]
  PIN q[267]
    DIRECTION OUTPUT ;
    USE SIGNAL ;
    PORT
      LAYER M4 ;
        RECT  11.688 51.648 11.88 51.672 ;
    END
  END q[267]
  PIN q[268]
    DIRECTION OUTPUT ;
    USE SIGNAL ;
    PORT
      LAYER M4 ;
        RECT  11.688 51.84 11.88 51.864 ;
    END
  END q[268]
  PIN q[269]
    DIRECTION OUTPUT ;
    USE SIGNAL ;
    PORT
      LAYER M4 ;
        RECT  11.688 52.032 11.88 52.056 ;
    END
  END q[269]
  PIN q[26]
    DIRECTION OUTPUT ;
    USE SIGNAL ;
    PORT
      LAYER M4 ;
        RECT  11.688 5.376 11.88 5.4 ;
    END
  END q[26]
  PIN q[270]
    DIRECTION OUTPUT ;
    USE SIGNAL ;
    PORT
      LAYER M4 ;
        RECT  11.688 52.224 11.88 52.248 ;
    END
  END q[270]
  PIN q[271]
    DIRECTION OUTPUT ;
    USE SIGNAL ;
    PORT
      LAYER M4 ;
        RECT  11.688 52.416 11.88 52.44 ;
    END
  END q[271]
  PIN q[272]
    DIRECTION OUTPUT ;
    USE SIGNAL ;
    PORT
      LAYER M4 ;
        RECT  11.688 52.608 11.88 52.632 ;
    END
  END q[272]
  PIN q[273]
    DIRECTION OUTPUT ;
    USE SIGNAL ;
    PORT
      LAYER M4 ;
        RECT  11.688 52.8 11.88 52.824 ;
    END
  END q[273]
  PIN q[274]
    DIRECTION OUTPUT ;
    USE SIGNAL ;
    PORT
      LAYER M4 ;
        RECT  11.688 52.992 11.88 53.016 ;
    END
  END q[274]
  PIN q[275]
    DIRECTION OUTPUT ;
    USE SIGNAL ;
    PORT
      LAYER M4 ;
        RECT  11.688 53.184 11.88 53.208 ;
    END
  END q[275]
  PIN q[276]
    DIRECTION OUTPUT ;
    USE SIGNAL ;
    PORT
      LAYER M4 ;
        RECT  11.688 53.376 11.88 53.4 ;
    END
  END q[276]
  PIN q[277]
    DIRECTION OUTPUT ;
    USE SIGNAL ;
    PORT
      LAYER M4 ;
        RECT  11.688 53.568 11.88 53.592 ;
    END
  END q[277]
  PIN q[278]
    DIRECTION OUTPUT ;
    USE SIGNAL ;
    PORT
      LAYER M4 ;
        RECT  11.688 53.76 11.88 53.784 ;
    END
  END q[278]
  PIN q[279]
    DIRECTION OUTPUT ;
    USE SIGNAL ;
    PORT
      LAYER M4 ;
        RECT  11.688 53.952 11.88 53.976 ;
    END
  END q[279]
  PIN q[27]
    DIRECTION OUTPUT ;
    USE SIGNAL ;
    PORT
      LAYER M4 ;
        RECT  11.688 5.568 11.88 5.592 ;
    END
  END q[27]
  PIN q[280]
    DIRECTION OUTPUT ;
    USE SIGNAL ;
    PORT
      LAYER M4 ;
        RECT  11.688 54.144 11.88 54.168 ;
    END
  END q[280]
  PIN q[281]
    DIRECTION OUTPUT ;
    USE SIGNAL ;
    PORT
      LAYER M4 ;
        RECT  11.688 54.336 11.88 54.36 ;
    END
  END q[281]
  PIN q[282]
    DIRECTION OUTPUT ;
    USE SIGNAL ;
    PORT
      LAYER M4 ;
        RECT  11.688 54.528 11.88 54.552 ;
    END
  END q[282]
  PIN q[283]
    DIRECTION OUTPUT ;
    USE SIGNAL ;
    PORT
      LAYER M4 ;
        RECT  11.688 54.72 11.88 54.744 ;
    END
  END q[283]
  PIN q[284]
    DIRECTION OUTPUT ;
    USE SIGNAL ;
    PORT
      LAYER M4 ;
        RECT  11.688 54.912 11.88 54.936 ;
    END
  END q[284]
  PIN q[285]
    DIRECTION OUTPUT ;
    USE SIGNAL ;
    PORT
      LAYER M4 ;
        RECT  11.688 55.104 11.88 55.128 ;
    END
  END q[285]
  PIN q[286]
    DIRECTION OUTPUT ;
    USE SIGNAL ;
    PORT
      LAYER M4 ;
        RECT  11.688 55.296 11.88 55.32 ;
    END
  END q[286]
  PIN q[287]
    DIRECTION OUTPUT ;
    USE SIGNAL ;
    PORT
      LAYER M4 ;
        RECT  11.688 55.488 11.88 55.512 ;
    END
  END q[287]
  PIN q[288]
    DIRECTION OUTPUT ;
    USE SIGNAL ;
    PORT
      LAYER M4 ;
        RECT  11.688 55.68 11.88 55.704 ;
    END
  END q[288]
  PIN q[289]
    DIRECTION OUTPUT ;
    USE SIGNAL ;
    PORT
      LAYER M4 ;
        RECT  11.688 55.872 11.88 55.896 ;
    END
  END q[289]
  PIN q[28]
    DIRECTION OUTPUT ;
    USE SIGNAL ;
    PORT
      LAYER M4 ;
        RECT  11.688 5.76 11.88 5.784 ;
    END
  END q[28]
  PIN q[290]
    DIRECTION OUTPUT ;
    USE SIGNAL ;
    PORT
      LAYER M4 ;
        RECT  11.688 56.064 11.88 56.088 ;
    END
  END q[290]
  PIN q[291]
    DIRECTION OUTPUT ;
    USE SIGNAL ;
    PORT
      LAYER M4 ;
        RECT  11.688 56.256 11.88 56.28 ;
    END
  END q[291]
  PIN q[292]
    DIRECTION OUTPUT ;
    USE SIGNAL ;
    PORT
      LAYER M4 ;
        RECT  11.688 56.448 11.88 56.472 ;
    END
  END q[292]
  PIN q[293]
    DIRECTION OUTPUT ;
    USE SIGNAL ;
    PORT
      LAYER M4 ;
        RECT  11.688 56.64 11.88 56.664 ;
    END
  END q[293]
  PIN q[294]
    DIRECTION OUTPUT ;
    USE SIGNAL ;
    PORT
      LAYER M4 ;
        RECT  11.688 56.832 11.88 56.856 ;
    END
  END q[294]
  PIN q[295]
    DIRECTION OUTPUT ;
    USE SIGNAL ;
    PORT
      LAYER M4 ;
        RECT  11.688 57.024 11.88 57.048 ;
    END
  END q[295]
  PIN q[296]
    DIRECTION OUTPUT ;
    USE SIGNAL ;
    PORT
      LAYER M4 ;
        RECT  11.688 57.216 11.88 57.24 ;
    END
  END q[296]
  PIN q[297]
    DIRECTION OUTPUT ;
    USE SIGNAL ;
    PORT
      LAYER M4 ;
        RECT  11.688 57.408 11.88 57.432 ;
    END
  END q[297]
  PIN q[298]
    DIRECTION OUTPUT ;
    USE SIGNAL ;
    PORT
      LAYER M4 ;
        RECT  11.688 57.6 11.88 57.624 ;
    END
  END q[298]
  PIN q[299]
    DIRECTION OUTPUT ;
    USE SIGNAL ;
    PORT
      LAYER M4 ;
        RECT  11.688 57.792 11.88 57.816 ;
    END
  END q[299]
  PIN q[29]
    DIRECTION OUTPUT ;
    USE SIGNAL ;
    PORT
      LAYER M4 ;
        RECT  11.688 5.952 11.88 5.976 ;
    END
  END q[29]
  PIN q[2]
    DIRECTION OUTPUT ;
    USE SIGNAL ;
    PORT
      LAYER M4 ;
        RECT  11.688 0.768 11.88 0.792 ;
    END
  END q[2]
  PIN q[300]
    DIRECTION OUTPUT ;
    USE SIGNAL ;
    PORT
      LAYER M4 ;
        RECT  11.688 57.984 11.88 58.008 ;
    END
  END q[300]
  PIN q[301]
    DIRECTION OUTPUT ;
    USE SIGNAL ;
    PORT
      LAYER M4 ;
        RECT  11.688 58.176 11.88 58.2 ;
    END
  END q[301]
  PIN q[302]
    DIRECTION OUTPUT ;
    USE SIGNAL ;
    PORT
      LAYER M4 ;
        RECT  11.688 58.368 11.88 58.392 ;
    END
  END q[302]
  PIN q[303]
    DIRECTION OUTPUT ;
    USE SIGNAL ;
    PORT
      LAYER M4 ;
        RECT  11.688 58.56 11.88 58.584 ;
    END
  END q[303]
  PIN q[304]
    DIRECTION OUTPUT ;
    USE SIGNAL ;
    PORT
      LAYER M4 ;
        RECT  11.688 58.752 11.88 58.776 ;
    END
  END q[304]
  PIN q[305]
    DIRECTION OUTPUT ;
    USE SIGNAL ;
    PORT
      LAYER M4 ;
        RECT  11.688 58.944 11.88 58.968 ;
    END
  END q[305]
  PIN q[306]
    DIRECTION OUTPUT ;
    USE SIGNAL ;
    PORT
      LAYER M4 ;
        RECT  11.688 59.136 11.88 59.16 ;
    END
  END q[306]
  PIN q[307]
    DIRECTION OUTPUT ;
    USE SIGNAL ;
    PORT
      LAYER M4 ;
        RECT  11.688 59.328 11.88 59.352 ;
    END
  END q[307]
  PIN q[308]
    DIRECTION OUTPUT ;
    USE SIGNAL ;
    PORT
      LAYER M4 ;
        RECT  11.688 59.52 11.88 59.544 ;
    END
  END q[308]
  PIN q[309]
    DIRECTION OUTPUT ;
    USE SIGNAL ;
    PORT
      LAYER M4 ;
        RECT  11.688 59.712 11.88 59.736 ;
    END
  END q[309]
  PIN q[30]
    DIRECTION OUTPUT ;
    USE SIGNAL ;
    PORT
      LAYER M4 ;
        RECT  11.688 6.144 11.88 6.168 ;
    END
  END q[30]
  PIN q[310]
    DIRECTION OUTPUT ;
    USE SIGNAL ;
    PORT
      LAYER M4 ;
        RECT  11.688 59.904 11.88 59.928 ;
    END
  END q[310]
  PIN q[311]
    DIRECTION OUTPUT ;
    USE SIGNAL ;
    PORT
      LAYER M4 ;
        RECT  11.688 60.096 11.88 60.12 ;
    END
  END q[311]
  PIN q[312]
    DIRECTION OUTPUT ;
    USE SIGNAL ;
    PORT
      LAYER M4 ;
        RECT  11.688 60.288 11.88 60.312 ;
    END
  END q[312]
  PIN q[313]
    DIRECTION OUTPUT ;
    USE SIGNAL ;
    PORT
      LAYER M4 ;
        RECT  11.688 60.48 11.88 60.504 ;
    END
  END q[313]
  PIN q[314]
    DIRECTION OUTPUT ;
    USE SIGNAL ;
    PORT
      LAYER M4 ;
        RECT  11.688 60.672 11.88 60.696 ;
    END
  END q[314]
  PIN q[315]
    DIRECTION OUTPUT ;
    USE SIGNAL ;
    PORT
      LAYER M4 ;
        RECT  11.688 60.864 11.88 60.888 ;
    END
  END q[315]
  PIN q[316]
    DIRECTION OUTPUT ;
    USE SIGNAL ;
    PORT
      LAYER M4 ;
        RECT  11.688 61.056 11.88 61.08 ;
    END
  END q[316]
  PIN q[317]
    DIRECTION OUTPUT ;
    USE SIGNAL ;
    PORT
      LAYER M4 ;
        RECT  11.688 61.248 11.88 61.272 ;
    END
  END q[317]
  PIN q[318]
    DIRECTION OUTPUT ;
    USE SIGNAL ;
    PORT
      LAYER M4 ;
        RECT  11.688 61.44 11.88 61.464 ;
    END
  END q[318]
  PIN q[319]
    DIRECTION OUTPUT ;
    USE SIGNAL ;
    PORT
      LAYER M4 ;
        RECT  11.688 61.632 11.88 61.656 ;
    END
  END q[319]
  PIN q[31]
    DIRECTION OUTPUT ;
    USE SIGNAL ;
    PORT
      LAYER M4 ;
        RECT  11.688 6.336 11.88 6.36 ;
    END
  END q[31]
  PIN q[320]
    DIRECTION OUTPUT ;
    USE SIGNAL ;
    PORT
      LAYER M4 ;
        RECT  11.688 61.824 11.88 61.848 ;
    END
  END q[320]
  PIN q[321]
    DIRECTION OUTPUT ;
    USE SIGNAL ;
    PORT
      LAYER M4 ;
        RECT  11.688 62.016 11.88 62.04 ;
    END
  END q[321]
  PIN q[322]
    DIRECTION OUTPUT ;
    USE SIGNAL ;
    PORT
      LAYER M4 ;
        RECT  11.688 62.208 11.88 62.232 ;
    END
  END q[322]
  PIN q[323]
    DIRECTION OUTPUT ;
    USE SIGNAL ;
    PORT
      LAYER M4 ;
        RECT  11.688 62.4 11.88 62.424 ;
    END
  END q[323]
  PIN q[324]
    DIRECTION OUTPUT ;
    USE SIGNAL ;
    PORT
      LAYER M4 ;
        RECT  11.688 62.592 11.88 62.616 ;
    END
  END q[324]
  PIN q[325]
    DIRECTION OUTPUT ;
    USE SIGNAL ;
    PORT
      LAYER M4 ;
        RECT  11.688 62.784 11.88 62.808 ;
    END
  END q[325]
  PIN q[326]
    DIRECTION OUTPUT ;
    USE SIGNAL ;
    PORT
      LAYER M4 ;
        RECT  11.688 62.976 11.88 63 ;
    END
  END q[326]
  PIN q[327]
    DIRECTION OUTPUT ;
    USE SIGNAL ;
    PORT
      LAYER M4 ;
        RECT  11.688 63.168 11.88 63.192 ;
    END
  END q[327]
  PIN q[328]
    DIRECTION OUTPUT ;
    USE SIGNAL ;
    PORT
      LAYER M4 ;
        RECT  11.688 63.36 11.88 63.384 ;
    END
  END q[328]
  PIN q[329]
    DIRECTION OUTPUT ;
    USE SIGNAL ;
    PORT
      LAYER M4 ;
        RECT  11.688 63.552 11.88 63.576 ;
    END
  END q[329]
  PIN q[32]
    DIRECTION OUTPUT ;
    USE SIGNAL ;
    PORT
      LAYER M4 ;
        RECT  11.688 6.528 11.88 6.552 ;
    END
  END q[32]
  PIN q[330]
    DIRECTION OUTPUT ;
    USE SIGNAL ;
    PORT
      LAYER M4 ;
        RECT  11.688 63.744 11.88 63.768 ;
    END
  END q[330]
  PIN q[331]
    DIRECTION OUTPUT ;
    USE SIGNAL ;
    PORT
      LAYER M4 ;
        RECT  11.688 63.936 11.88 63.96 ;
    END
  END q[331]
  PIN q[332]
    DIRECTION OUTPUT ;
    USE SIGNAL ;
    PORT
      LAYER M4 ;
        RECT  11.688 64.128 11.88 64.152 ;
    END
  END q[332]
  PIN q[333]
    DIRECTION OUTPUT ;
    USE SIGNAL ;
    PORT
      LAYER M4 ;
        RECT  11.688 64.32 11.88 64.344 ;
    END
  END q[333]
  PIN q[334]
    DIRECTION OUTPUT ;
    USE SIGNAL ;
    PORT
      LAYER M4 ;
        RECT  11.688 64.512 11.88 64.536 ;
    END
  END q[334]
  PIN q[335]
    DIRECTION OUTPUT ;
    USE SIGNAL ;
    PORT
      LAYER M4 ;
        RECT  11.688 64.704 11.88 64.728 ;
    END
  END q[335]
  PIN q[336]
    DIRECTION OUTPUT ;
    USE SIGNAL ;
    PORT
      LAYER M4 ;
        RECT  11.688 64.896 11.88 64.92 ;
    END
  END q[336]
  PIN q[337]
    DIRECTION OUTPUT ;
    USE SIGNAL ;
    PORT
      LAYER M4 ;
        RECT  11.688 65.088 11.88 65.112 ;
    END
  END q[337]
  PIN q[338]
    DIRECTION OUTPUT ;
    USE SIGNAL ;
    PORT
      LAYER M4 ;
        RECT  11.688 65.28 11.88 65.304 ;
    END
  END q[338]
  PIN q[339]
    DIRECTION OUTPUT ;
    USE SIGNAL ;
    PORT
      LAYER M4 ;
        RECT  11.688 65.472 11.88 65.496 ;
    END
  END q[339]
  PIN q[33]
    DIRECTION OUTPUT ;
    USE SIGNAL ;
    PORT
      LAYER M4 ;
        RECT  11.688 6.72 11.88 6.744 ;
    END
  END q[33]
  PIN q[340]
    DIRECTION OUTPUT ;
    USE SIGNAL ;
    PORT
      LAYER M4 ;
        RECT  11.688 65.664 11.88 65.688 ;
    END
  END q[340]
  PIN q[341]
    DIRECTION OUTPUT ;
    USE SIGNAL ;
    PORT
      LAYER M4 ;
        RECT  11.688 65.856 11.88 65.88 ;
    END
  END q[341]
  PIN q[342]
    DIRECTION OUTPUT ;
    USE SIGNAL ;
    PORT
      LAYER M4 ;
        RECT  11.688 66.048 11.88 66.072 ;
    END
  END q[342]
  PIN q[343]
    DIRECTION OUTPUT ;
    USE SIGNAL ;
    PORT
      LAYER M4 ;
        RECT  11.688 66.24 11.88 66.264 ;
    END
  END q[343]
  PIN q[344]
    DIRECTION OUTPUT ;
    USE SIGNAL ;
    PORT
      LAYER M4 ;
        RECT  11.688 66.432 11.88 66.456 ;
    END
  END q[344]
  PIN q[345]
    DIRECTION OUTPUT ;
    USE SIGNAL ;
    PORT
      LAYER M4 ;
        RECT  11.688 66.624 11.88 66.648 ;
    END
  END q[345]
  PIN q[346]
    DIRECTION OUTPUT ;
    USE SIGNAL ;
    PORT
      LAYER M4 ;
        RECT  11.688 66.816 11.88 66.84 ;
    END
  END q[346]
  PIN q[347]
    DIRECTION OUTPUT ;
    USE SIGNAL ;
    PORT
      LAYER M4 ;
        RECT  11.688 67.008 11.88 67.032 ;
    END
  END q[347]
  PIN q[348]
    DIRECTION OUTPUT ;
    USE SIGNAL ;
    PORT
      LAYER M4 ;
        RECT  11.688 67.2 11.88 67.224 ;
    END
  END q[348]
  PIN q[349]
    DIRECTION OUTPUT ;
    USE SIGNAL ;
    PORT
      LAYER M4 ;
        RECT  11.688 67.392 11.88 67.416 ;
    END
  END q[349]
  PIN q[34]
    DIRECTION OUTPUT ;
    USE SIGNAL ;
    PORT
      LAYER M4 ;
        RECT  11.688 6.912 11.88 6.936 ;
    END
  END q[34]
  PIN q[350]
    DIRECTION OUTPUT ;
    USE SIGNAL ;
    PORT
      LAYER M4 ;
        RECT  11.688 67.584 11.88 67.608 ;
    END
  END q[350]
  PIN q[351]
    DIRECTION OUTPUT ;
    USE SIGNAL ;
    PORT
      LAYER M4 ;
        RECT  11.688 67.776 11.88 67.8 ;
    END
  END q[351]
  PIN q[352]
    DIRECTION OUTPUT ;
    USE SIGNAL ;
    PORT
      LAYER M4 ;
        RECT  11.688 67.968 11.88 67.992 ;
    END
  END q[352]
  PIN q[353]
    DIRECTION OUTPUT ;
    USE SIGNAL ;
    PORT
      LAYER M4 ;
        RECT  11.688 68.16 11.88 68.184 ;
    END
  END q[353]
  PIN q[354]
    DIRECTION OUTPUT ;
    USE SIGNAL ;
    PORT
      LAYER M4 ;
        RECT  11.688 68.352 11.88 68.376 ;
    END
  END q[354]
  PIN q[355]
    DIRECTION OUTPUT ;
    USE SIGNAL ;
    PORT
      LAYER M4 ;
        RECT  11.688 68.544 11.88 68.568 ;
    END
  END q[355]
  PIN q[356]
    DIRECTION OUTPUT ;
    USE SIGNAL ;
    PORT
      LAYER M4 ;
        RECT  11.688 68.736 11.88 68.76 ;
    END
  END q[356]
  PIN q[357]
    DIRECTION OUTPUT ;
    USE SIGNAL ;
    PORT
      LAYER M4 ;
        RECT  11.688 68.928 11.88 68.952 ;
    END
  END q[357]
  PIN q[358]
    DIRECTION OUTPUT ;
    USE SIGNAL ;
    PORT
      LAYER M4 ;
        RECT  11.688 69.12 11.88 69.144 ;
    END
  END q[358]
  PIN q[359]
    DIRECTION OUTPUT ;
    USE SIGNAL ;
    PORT
      LAYER M4 ;
        RECT  11.688 69.312 11.88 69.336 ;
    END
  END q[359]
  PIN q[35]
    DIRECTION OUTPUT ;
    USE SIGNAL ;
    PORT
      LAYER M4 ;
        RECT  11.688 7.104 11.88 7.128 ;
    END
  END q[35]
  PIN q[360]
    DIRECTION OUTPUT ;
    USE SIGNAL ;
    PORT
      LAYER M4 ;
        RECT  11.688 69.504 11.88 69.528 ;
    END
  END q[360]
  PIN q[361]
    DIRECTION OUTPUT ;
    USE SIGNAL ;
    PORT
      LAYER M4 ;
        RECT  11.688 69.696 11.88 69.72 ;
    END
  END q[361]
  PIN q[362]
    DIRECTION OUTPUT ;
    USE SIGNAL ;
    PORT
      LAYER M4 ;
        RECT  11.688 69.888 11.88 69.912 ;
    END
  END q[362]
  PIN q[363]
    DIRECTION OUTPUT ;
    USE SIGNAL ;
    PORT
      LAYER M4 ;
        RECT  11.688 70.08 11.88 70.104 ;
    END
  END q[363]
  PIN q[364]
    DIRECTION OUTPUT ;
    USE SIGNAL ;
    PORT
      LAYER M4 ;
        RECT  11.688 70.272 11.88 70.296 ;
    END
  END q[364]
  PIN q[365]
    DIRECTION OUTPUT ;
    USE SIGNAL ;
    PORT
      LAYER M4 ;
        RECT  11.688 70.464 11.88 70.488 ;
    END
  END q[365]
  PIN q[366]
    DIRECTION OUTPUT ;
    USE SIGNAL ;
    PORT
      LAYER M4 ;
        RECT  11.688 70.656 11.88 70.68 ;
    END
  END q[366]
  PIN q[367]
    DIRECTION OUTPUT ;
    USE SIGNAL ;
    PORT
      LAYER M4 ;
        RECT  11.688 70.848 11.88 70.872 ;
    END
  END q[367]
  PIN q[368]
    DIRECTION OUTPUT ;
    USE SIGNAL ;
    PORT
      LAYER M4 ;
        RECT  11.688 71.04 11.88 71.064 ;
    END
  END q[368]
  PIN q[369]
    DIRECTION OUTPUT ;
    USE SIGNAL ;
    PORT
      LAYER M4 ;
        RECT  11.688 71.232 11.88 71.256 ;
    END
  END q[369]
  PIN q[36]
    DIRECTION OUTPUT ;
    USE SIGNAL ;
    PORT
      LAYER M4 ;
        RECT  11.688 7.296 11.88 7.32 ;
    END
  END q[36]
  PIN q[370]
    DIRECTION OUTPUT ;
    USE SIGNAL ;
    PORT
      LAYER M4 ;
        RECT  11.688 71.424 11.88 71.448 ;
    END
  END q[370]
  PIN q[371]
    DIRECTION OUTPUT ;
    USE SIGNAL ;
    PORT
      LAYER M4 ;
        RECT  11.688 71.616 11.88 71.64 ;
    END
  END q[371]
  PIN q[372]
    DIRECTION OUTPUT ;
    USE SIGNAL ;
    PORT
      LAYER M4 ;
        RECT  11.688 71.808 11.88 71.832 ;
    END
  END q[372]
  PIN q[373]
    DIRECTION OUTPUT ;
    USE SIGNAL ;
    PORT
      LAYER M4 ;
        RECT  11.688 72 11.88 72.024 ;
    END
  END q[373]
  PIN q[374]
    DIRECTION OUTPUT ;
    USE SIGNAL ;
    PORT
      LAYER M4 ;
        RECT  11.688 72.192 11.88 72.216 ;
    END
  END q[374]
  PIN q[375]
    DIRECTION OUTPUT ;
    USE SIGNAL ;
    PORT
      LAYER M4 ;
        RECT  11.688 72.384 11.88 72.408 ;
    END
  END q[375]
  PIN q[376]
    DIRECTION OUTPUT ;
    USE SIGNAL ;
    PORT
      LAYER M4 ;
        RECT  11.688 72.576 11.88 72.6 ;
    END
  END q[376]
  PIN q[377]
    DIRECTION OUTPUT ;
    USE SIGNAL ;
    PORT
      LAYER M4 ;
        RECT  11.688 72.768 11.88 72.792 ;
    END
  END q[377]
  PIN q[378]
    DIRECTION OUTPUT ;
    USE SIGNAL ;
    PORT
      LAYER M4 ;
        RECT  11.688 72.96 11.88 72.984 ;
    END
  END q[378]
  PIN q[379]
    DIRECTION OUTPUT ;
    USE SIGNAL ;
    PORT
      LAYER M4 ;
        RECT  11.688 73.152 11.88 73.176 ;
    END
  END q[379]
  PIN q[37]
    DIRECTION OUTPUT ;
    USE SIGNAL ;
    PORT
      LAYER M4 ;
        RECT  11.688 7.488 11.88 7.512 ;
    END
  END q[37]
  PIN q[380]
    DIRECTION OUTPUT ;
    USE SIGNAL ;
    PORT
      LAYER M4 ;
        RECT  11.688 73.344 11.88 73.368 ;
    END
  END q[380]
  PIN q[381]
    DIRECTION OUTPUT ;
    USE SIGNAL ;
    PORT
      LAYER M4 ;
        RECT  11.688 73.536 11.88 73.56 ;
    END
  END q[381]
  PIN q[382]
    DIRECTION OUTPUT ;
    USE SIGNAL ;
    PORT
      LAYER M4 ;
        RECT  11.688 73.728 11.88 73.752 ;
    END
  END q[382]
  PIN q[383]
    DIRECTION OUTPUT ;
    USE SIGNAL ;
    PORT
      LAYER M4 ;
        RECT  11.688 73.92 11.88 73.944 ;
    END
  END q[383]
  PIN q[384]
    DIRECTION OUTPUT ;
    USE SIGNAL ;
    PORT
      LAYER M4 ;
        RECT  11.688 74.112 11.88 74.136 ;
    END
  END q[384]
  PIN q[385]
    DIRECTION OUTPUT ;
    USE SIGNAL ;
    PORT
      LAYER M4 ;
        RECT  11.688 74.304 11.88 74.328 ;
    END
  END q[385]
  PIN q[386]
    DIRECTION OUTPUT ;
    USE SIGNAL ;
    PORT
      LAYER M4 ;
        RECT  11.688 74.496 11.88 74.52 ;
    END
  END q[386]
  PIN q[387]
    DIRECTION OUTPUT ;
    USE SIGNAL ;
    PORT
      LAYER M4 ;
        RECT  11.688 74.688 11.88 74.712 ;
    END
  END q[387]
  PIN q[388]
    DIRECTION OUTPUT ;
    USE SIGNAL ;
    PORT
      LAYER M4 ;
        RECT  11.688 74.88 11.88 74.904 ;
    END
  END q[388]
  PIN q[389]
    DIRECTION OUTPUT ;
    USE SIGNAL ;
    PORT
      LAYER M4 ;
        RECT  11.688 75.072 11.88 75.096 ;
    END
  END q[389]
  PIN q[38]
    DIRECTION OUTPUT ;
    USE SIGNAL ;
    PORT
      LAYER M4 ;
        RECT  11.688 7.68 11.88 7.704 ;
    END
  END q[38]
  PIN q[390]
    DIRECTION OUTPUT ;
    USE SIGNAL ;
    PORT
      LAYER M4 ;
        RECT  11.688 75.264 11.88 75.288 ;
    END
  END q[390]
  PIN q[391]
    DIRECTION OUTPUT ;
    USE SIGNAL ;
    PORT
      LAYER M4 ;
        RECT  11.688 75.456 11.88 75.48 ;
    END
  END q[391]
  PIN q[392]
    DIRECTION OUTPUT ;
    USE SIGNAL ;
    PORT
      LAYER M4 ;
        RECT  11.688 75.648 11.88 75.672 ;
    END
  END q[392]
  PIN q[393]
    DIRECTION OUTPUT ;
    USE SIGNAL ;
    PORT
      LAYER M4 ;
        RECT  11.688 75.84 11.88 75.864 ;
    END
  END q[393]
  PIN q[394]
    DIRECTION OUTPUT ;
    USE SIGNAL ;
    PORT
      LAYER M4 ;
        RECT  11.688 76.032 11.88 76.056 ;
    END
  END q[394]
  PIN q[395]
    DIRECTION OUTPUT ;
    USE SIGNAL ;
    PORT
      LAYER M4 ;
        RECT  11.688 76.224 11.88 76.248 ;
    END
  END q[395]
  PIN q[396]
    DIRECTION OUTPUT ;
    USE SIGNAL ;
    PORT
      LAYER M4 ;
        RECT  11.688 76.416 11.88 76.44 ;
    END
  END q[396]
  PIN q[397]
    DIRECTION OUTPUT ;
    USE SIGNAL ;
    PORT
      LAYER M4 ;
        RECT  11.688 76.608 11.88 76.632 ;
    END
  END q[397]
  PIN q[398]
    DIRECTION OUTPUT ;
    USE SIGNAL ;
    PORT
      LAYER M4 ;
        RECT  11.688 76.8 11.88 76.824 ;
    END
  END q[398]
  PIN q[399]
    DIRECTION OUTPUT ;
    USE SIGNAL ;
    PORT
      LAYER M4 ;
        RECT  11.688 76.992 11.88 77.016 ;
    END
  END q[399]
  PIN q[39]
    DIRECTION OUTPUT ;
    USE SIGNAL ;
    PORT
      LAYER M4 ;
        RECT  11.688 7.872 11.88 7.896 ;
    END
  END q[39]
  PIN q[3]
    DIRECTION OUTPUT ;
    USE SIGNAL ;
    PORT
      LAYER M4 ;
        RECT  11.688 0.96 11.88 0.984 ;
    END
  END q[3]
  PIN q[400]
    DIRECTION OUTPUT ;
    USE SIGNAL ;
    PORT
      LAYER M4 ;
        RECT  11.688 77.184 11.88 77.208 ;
    END
  END q[400]
  PIN q[401]
    DIRECTION OUTPUT ;
    USE SIGNAL ;
    PORT
      LAYER M4 ;
        RECT  11.688 77.376 11.88 77.4 ;
    END
  END q[401]
  PIN q[402]
    DIRECTION OUTPUT ;
    USE SIGNAL ;
    PORT
      LAYER M4 ;
        RECT  11.688 77.568 11.88 77.592 ;
    END
  END q[402]
  PIN q[403]
    DIRECTION OUTPUT ;
    USE SIGNAL ;
    PORT
      LAYER M4 ;
        RECT  11.688 77.76 11.88 77.784 ;
    END
  END q[403]
  PIN q[404]
    DIRECTION OUTPUT ;
    USE SIGNAL ;
    PORT
      LAYER M4 ;
        RECT  11.688 77.952 11.88 77.976 ;
    END
  END q[404]
  PIN q[405]
    DIRECTION OUTPUT ;
    USE SIGNAL ;
    PORT
      LAYER M4 ;
        RECT  11.688 78.144 11.88 78.168 ;
    END
  END q[405]
  PIN q[406]
    DIRECTION OUTPUT ;
    USE SIGNAL ;
    PORT
      LAYER M4 ;
        RECT  11.688 78.336 11.88 78.36 ;
    END
  END q[406]
  PIN q[407]
    DIRECTION OUTPUT ;
    USE SIGNAL ;
    PORT
      LAYER M4 ;
        RECT  11.688 78.528 11.88 78.552 ;
    END
  END q[407]
  PIN q[408]
    DIRECTION OUTPUT ;
    USE SIGNAL ;
    PORT
      LAYER M4 ;
        RECT  11.688 78.72 11.88 78.744 ;
    END
  END q[408]
  PIN q[409]
    DIRECTION OUTPUT ;
    USE SIGNAL ;
    PORT
      LAYER M4 ;
        RECT  11.688 78.912 11.88 78.936 ;
    END
  END q[409]
  PIN q[40]
    DIRECTION OUTPUT ;
    USE SIGNAL ;
    PORT
      LAYER M4 ;
        RECT  11.688 8.064 11.88 8.088 ;
    END
  END q[40]
  PIN q[410]
    DIRECTION OUTPUT ;
    USE SIGNAL ;
    PORT
      LAYER M4 ;
        RECT  11.688 79.104 11.88 79.128 ;
    END
  END q[410]
  PIN q[411]
    DIRECTION OUTPUT ;
    USE SIGNAL ;
    PORT
      LAYER M4 ;
        RECT  11.688 79.296 11.88 79.32 ;
    END
  END q[411]
  PIN q[412]
    DIRECTION OUTPUT ;
    USE SIGNAL ;
    PORT
      LAYER M4 ;
        RECT  11.688 79.488 11.88 79.512 ;
    END
  END q[412]
  PIN q[413]
    DIRECTION OUTPUT ;
    USE SIGNAL ;
    PORT
      LAYER M4 ;
        RECT  11.688 79.68 11.88 79.704 ;
    END
  END q[413]
  PIN q[414]
    DIRECTION OUTPUT ;
    USE SIGNAL ;
    PORT
      LAYER M4 ;
        RECT  11.688 79.872 11.88 79.896 ;
    END
  END q[414]
  PIN q[415]
    DIRECTION OUTPUT ;
    USE SIGNAL ;
    PORT
      LAYER M4 ;
        RECT  11.688 80.064 11.88 80.088 ;
    END
  END q[415]
  PIN q[416]
    DIRECTION OUTPUT ;
    USE SIGNAL ;
    PORT
      LAYER M4 ;
        RECT  11.688 80.256 11.88 80.28 ;
    END
  END q[416]
  PIN q[417]
    DIRECTION OUTPUT ;
    USE SIGNAL ;
    PORT
      LAYER M4 ;
        RECT  11.688 80.448 11.88 80.472 ;
    END
  END q[417]
  PIN q[418]
    DIRECTION OUTPUT ;
    USE SIGNAL ;
    PORT
      LAYER M4 ;
        RECT  11.688 80.64 11.88 80.664 ;
    END
  END q[418]
  PIN q[419]
    DIRECTION OUTPUT ;
    USE SIGNAL ;
    PORT
      LAYER M4 ;
        RECT  11.688 80.832 11.88 80.856 ;
    END
  END q[419]
  PIN q[41]
    DIRECTION OUTPUT ;
    USE SIGNAL ;
    PORT
      LAYER M4 ;
        RECT  11.688 8.256 11.88 8.28 ;
    END
  END q[41]
  PIN q[420]
    DIRECTION OUTPUT ;
    USE SIGNAL ;
    PORT
      LAYER M4 ;
        RECT  11.688 81.024 11.88 81.048 ;
    END
  END q[420]
  PIN q[421]
    DIRECTION OUTPUT ;
    USE SIGNAL ;
    PORT
      LAYER M4 ;
        RECT  11.688 81.216 11.88 81.24 ;
    END
  END q[421]
  PIN q[422]
    DIRECTION OUTPUT ;
    USE SIGNAL ;
    PORT
      LAYER M4 ;
        RECT  11.688 81.408 11.88 81.432 ;
    END
  END q[422]
  PIN q[423]
    DIRECTION OUTPUT ;
    USE SIGNAL ;
    PORT
      LAYER M4 ;
        RECT  11.688 81.6 11.88 81.624 ;
    END
  END q[423]
  PIN q[424]
    DIRECTION OUTPUT ;
    USE SIGNAL ;
    PORT
      LAYER M4 ;
        RECT  11.688 81.792 11.88 81.816 ;
    END
  END q[424]
  PIN q[425]
    DIRECTION OUTPUT ;
    USE SIGNAL ;
    PORT
      LAYER M4 ;
        RECT  11.688 81.984 11.88 82.008 ;
    END
  END q[425]
  PIN q[426]
    DIRECTION OUTPUT ;
    USE SIGNAL ;
    PORT
      LAYER M4 ;
        RECT  11.688 82.176 11.88 82.2 ;
    END
  END q[426]
  PIN q[427]
    DIRECTION OUTPUT ;
    USE SIGNAL ;
    PORT
      LAYER M4 ;
        RECT  11.688 82.368 11.88 82.392 ;
    END
  END q[427]
  PIN q[428]
    DIRECTION OUTPUT ;
    USE SIGNAL ;
    PORT
      LAYER M4 ;
        RECT  11.688 82.56 11.88 82.584 ;
    END
  END q[428]
  PIN q[429]
    DIRECTION OUTPUT ;
    USE SIGNAL ;
    PORT
      LAYER M4 ;
        RECT  11.688 82.752 11.88 82.776 ;
    END
  END q[429]
  PIN q[42]
    DIRECTION OUTPUT ;
    USE SIGNAL ;
    PORT
      LAYER M4 ;
        RECT  11.688 8.448 11.88 8.472 ;
    END
  END q[42]
  PIN q[430]
    DIRECTION OUTPUT ;
    USE SIGNAL ;
    PORT
      LAYER M4 ;
        RECT  11.688 82.944 11.88 82.968 ;
    END
  END q[430]
  PIN q[431]
    DIRECTION OUTPUT ;
    USE SIGNAL ;
    PORT
      LAYER M4 ;
        RECT  11.688 83.136 11.88 83.16 ;
    END
  END q[431]
  PIN q[432]
    DIRECTION OUTPUT ;
    USE SIGNAL ;
    PORT
      LAYER M4 ;
        RECT  11.688 83.328 11.88 83.352 ;
    END
  END q[432]
  PIN q[433]
    DIRECTION OUTPUT ;
    USE SIGNAL ;
    PORT
      LAYER M4 ;
        RECT  11.688 83.52 11.88 83.544 ;
    END
  END q[433]
  PIN q[434]
    DIRECTION OUTPUT ;
    USE SIGNAL ;
    PORT
      LAYER M4 ;
        RECT  11.688 83.712 11.88 83.736 ;
    END
  END q[434]
  PIN q[435]
    DIRECTION OUTPUT ;
    USE SIGNAL ;
    PORT
      LAYER M4 ;
        RECT  11.688 83.904 11.88 83.928 ;
    END
  END q[435]
  PIN q[436]
    DIRECTION OUTPUT ;
    USE SIGNAL ;
    PORT
      LAYER M4 ;
        RECT  11.688 84.096 11.88 84.12 ;
    END
  END q[436]
  PIN q[437]
    DIRECTION OUTPUT ;
    USE SIGNAL ;
    PORT
      LAYER M4 ;
        RECT  11.688 84.288 11.88 84.312 ;
    END
  END q[437]
  PIN q[438]
    DIRECTION OUTPUT ;
    USE SIGNAL ;
    PORT
      LAYER M4 ;
        RECT  11.688 84.48 11.88 84.504 ;
    END
  END q[438]
  PIN q[439]
    DIRECTION OUTPUT ;
    USE SIGNAL ;
    PORT
      LAYER M4 ;
        RECT  11.688 84.672 11.88 84.696 ;
    END
  END q[439]
  PIN q[43]
    DIRECTION OUTPUT ;
    USE SIGNAL ;
    PORT
      LAYER M4 ;
        RECT  11.688 8.64 11.88 8.664 ;
    END
  END q[43]
  PIN q[440]
    DIRECTION OUTPUT ;
    USE SIGNAL ;
    PORT
      LAYER M4 ;
        RECT  11.688 84.864 11.88 84.888 ;
    END
  END q[440]
  PIN q[441]
    DIRECTION OUTPUT ;
    USE SIGNAL ;
    PORT
      LAYER M4 ;
        RECT  11.688 85.056 11.88 85.08 ;
    END
  END q[441]
  PIN q[442]
    DIRECTION OUTPUT ;
    USE SIGNAL ;
    PORT
      LAYER M4 ;
        RECT  11.688 85.248 11.88 85.272 ;
    END
  END q[442]
  PIN q[443]
    DIRECTION OUTPUT ;
    USE SIGNAL ;
    PORT
      LAYER M4 ;
        RECT  11.688 85.44 11.88 85.464 ;
    END
  END q[443]
  PIN q[444]
    DIRECTION OUTPUT ;
    USE SIGNAL ;
    PORT
      LAYER M4 ;
        RECT  11.688 85.632 11.88 85.656 ;
    END
  END q[444]
  PIN q[445]
    DIRECTION OUTPUT ;
    USE SIGNAL ;
    PORT
      LAYER M4 ;
        RECT  11.688 85.824 11.88 85.848 ;
    END
  END q[445]
  PIN q[446]
    DIRECTION OUTPUT ;
    USE SIGNAL ;
    PORT
      LAYER M4 ;
        RECT  11.688 86.016 11.88 86.04 ;
    END
  END q[446]
  PIN q[447]
    DIRECTION OUTPUT ;
    USE SIGNAL ;
    PORT
      LAYER M4 ;
        RECT  11.688 86.208 11.88 86.232 ;
    END
  END q[447]
  PIN q[448]
    DIRECTION OUTPUT ;
    USE SIGNAL ;
    PORT
      LAYER M4 ;
        RECT  11.688 86.4 11.88 86.424 ;
    END
  END q[448]
  PIN q[449]
    DIRECTION OUTPUT ;
    USE SIGNAL ;
    PORT
      LAYER M4 ;
        RECT  11.688 86.592 11.88 86.616 ;
    END
  END q[449]
  PIN q[44]
    DIRECTION OUTPUT ;
    USE SIGNAL ;
    PORT
      LAYER M4 ;
        RECT  11.688 8.832 11.88 8.856 ;
    END
  END q[44]
  PIN q[450]
    DIRECTION OUTPUT ;
    USE SIGNAL ;
    PORT
      LAYER M4 ;
        RECT  11.688 86.784 11.88 86.808 ;
    END
  END q[450]
  PIN q[451]
    DIRECTION OUTPUT ;
    USE SIGNAL ;
    PORT
      LAYER M4 ;
        RECT  11.688 86.976 11.88 87 ;
    END
  END q[451]
  PIN q[452]
    DIRECTION OUTPUT ;
    USE SIGNAL ;
    PORT
      LAYER M4 ;
        RECT  11.688 87.168 11.88 87.192 ;
    END
  END q[452]
  PIN q[453]
    DIRECTION OUTPUT ;
    USE SIGNAL ;
    PORT
      LAYER M4 ;
        RECT  11.688 87.36 11.88 87.384 ;
    END
  END q[453]
  PIN q[454]
    DIRECTION OUTPUT ;
    USE SIGNAL ;
    PORT
      LAYER M4 ;
        RECT  11.688 87.552 11.88 87.576 ;
    END
  END q[454]
  PIN q[455]
    DIRECTION OUTPUT ;
    USE SIGNAL ;
    PORT
      LAYER M4 ;
        RECT  11.688 87.744 11.88 87.768 ;
    END
  END q[455]
  PIN q[456]
    DIRECTION OUTPUT ;
    USE SIGNAL ;
    PORT
      LAYER M4 ;
        RECT  11.688 87.936 11.88 87.96 ;
    END
  END q[456]
  PIN q[457]
    DIRECTION OUTPUT ;
    USE SIGNAL ;
    PORT
      LAYER M4 ;
        RECT  11.688 88.128 11.88 88.152 ;
    END
  END q[457]
  PIN q[458]
    DIRECTION OUTPUT ;
    USE SIGNAL ;
    PORT
      LAYER M4 ;
        RECT  11.688 88.32 11.88 88.344 ;
    END
  END q[458]
  PIN q[459]
    DIRECTION OUTPUT ;
    USE SIGNAL ;
    PORT
      LAYER M4 ;
        RECT  11.688 88.512 11.88 88.536 ;
    END
  END q[459]
  PIN q[45]
    DIRECTION OUTPUT ;
    USE SIGNAL ;
    PORT
      LAYER M4 ;
        RECT  11.688 9.024 11.88 9.048 ;
    END
  END q[45]
  PIN q[460]
    DIRECTION OUTPUT ;
    USE SIGNAL ;
    PORT
      LAYER M4 ;
        RECT  11.688 88.704 11.88 88.728 ;
    END
  END q[460]
  PIN q[461]
    DIRECTION OUTPUT ;
    USE SIGNAL ;
    PORT
      LAYER M4 ;
        RECT  11.688 88.896 11.88 88.92 ;
    END
  END q[461]
  PIN q[462]
    DIRECTION OUTPUT ;
    USE SIGNAL ;
    PORT
      LAYER M4 ;
        RECT  11.688 89.088 11.88 89.112 ;
    END
  END q[462]
  PIN q[463]
    DIRECTION OUTPUT ;
    USE SIGNAL ;
    PORT
      LAYER M4 ;
        RECT  11.688 89.28 11.88 89.304 ;
    END
  END q[463]
  PIN q[464]
    DIRECTION OUTPUT ;
    USE SIGNAL ;
    PORT
      LAYER M4 ;
        RECT  11.688 89.472 11.88 89.496 ;
    END
  END q[464]
  PIN q[465]
    DIRECTION OUTPUT ;
    USE SIGNAL ;
    PORT
      LAYER M4 ;
        RECT  11.688 89.664 11.88 89.688 ;
    END
  END q[465]
  PIN q[466]
    DIRECTION OUTPUT ;
    USE SIGNAL ;
    PORT
      LAYER M4 ;
        RECT  11.688 89.856 11.88 89.88 ;
    END
  END q[466]
  PIN q[467]
    DIRECTION OUTPUT ;
    USE SIGNAL ;
    PORT
      LAYER M4 ;
        RECT  11.688 90.048 11.88 90.072 ;
    END
  END q[467]
  PIN q[468]
    DIRECTION OUTPUT ;
    USE SIGNAL ;
    PORT
      LAYER M4 ;
        RECT  11.688 90.24 11.88 90.264 ;
    END
  END q[468]
  PIN q[469]
    DIRECTION OUTPUT ;
    USE SIGNAL ;
    PORT
      LAYER M4 ;
        RECT  11.688 90.432 11.88 90.456 ;
    END
  END q[469]
  PIN q[46]
    DIRECTION OUTPUT ;
    USE SIGNAL ;
    PORT
      LAYER M4 ;
        RECT  11.688 9.216 11.88 9.24 ;
    END
  END q[46]
  PIN q[470]
    DIRECTION OUTPUT ;
    USE SIGNAL ;
    PORT
      LAYER M4 ;
        RECT  11.688 90.624 11.88 90.648 ;
    END
  END q[470]
  PIN q[471]
    DIRECTION OUTPUT ;
    USE SIGNAL ;
    PORT
      LAYER M4 ;
        RECT  11.688 90.816 11.88 90.84 ;
    END
  END q[471]
  PIN q[472]
    DIRECTION OUTPUT ;
    USE SIGNAL ;
    PORT
      LAYER M4 ;
        RECT  11.688 91.008 11.88 91.032 ;
    END
  END q[472]
  PIN q[473]
    DIRECTION OUTPUT ;
    USE SIGNAL ;
    PORT
      LAYER M4 ;
        RECT  11.688 91.2 11.88 91.224 ;
    END
  END q[473]
  PIN q[474]
    DIRECTION OUTPUT ;
    USE SIGNAL ;
    PORT
      LAYER M4 ;
        RECT  11.688 91.392 11.88 91.416 ;
    END
  END q[474]
  PIN q[475]
    DIRECTION OUTPUT ;
    USE SIGNAL ;
    PORT
      LAYER M4 ;
        RECT  11.688 91.584 11.88 91.608 ;
    END
  END q[475]
  PIN q[476]
    DIRECTION OUTPUT ;
    USE SIGNAL ;
    PORT
      LAYER M4 ;
        RECT  11.688 91.776 11.88 91.8 ;
    END
  END q[476]
  PIN q[477]
    DIRECTION OUTPUT ;
    USE SIGNAL ;
    PORT
      LAYER M4 ;
        RECT  11.688 91.968 11.88 91.992 ;
    END
  END q[477]
  PIN q[478]
    DIRECTION OUTPUT ;
    USE SIGNAL ;
    PORT
      LAYER M4 ;
        RECT  11.688 92.16 11.88 92.184 ;
    END
  END q[478]
  PIN q[479]
    DIRECTION OUTPUT ;
    USE SIGNAL ;
    PORT
      LAYER M4 ;
        RECT  11.688 92.352 11.88 92.376 ;
    END
  END q[479]
  PIN q[47]
    DIRECTION OUTPUT ;
    USE SIGNAL ;
    PORT
      LAYER M4 ;
        RECT  11.688 9.408 11.88 9.432 ;
    END
  END q[47]
  PIN q[480]
    DIRECTION OUTPUT ;
    USE SIGNAL ;
    PORT
      LAYER M4 ;
        RECT  11.688 92.544 11.88 92.568 ;
    END
  END q[480]
  PIN q[481]
    DIRECTION OUTPUT ;
    USE SIGNAL ;
    PORT
      LAYER M4 ;
        RECT  11.688 92.736 11.88 92.76 ;
    END
  END q[481]
  PIN q[482]
    DIRECTION OUTPUT ;
    USE SIGNAL ;
    PORT
      LAYER M4 ;
        RECT  11.688 92.928 11.88 92.952 ;
    END
  END q[482]
  PIN q[483]
    DIRECTION OUTPUT ;
    USE SIGNAL ;
    PORT
      LAYER M4 ;
        RECT  11.688 93.12 11.88 93.144 ;
    END
  END q[483]
  PIN q[484]
    DIRECTION OUTPUT ;
    USE SIGNAL ;
    PORT
      LAYER M4 ;
        RECT  11.688 93.312 11.88 93.336 ;
    END
  END q[484]
  PIN q[485]
    DIRECTION OUTPUT ;
    USE SIGNAL ;
    PORT
      LAYER M4 ;
        RECT  11.688 93.504 11.88 93.528 ;
    END
  END q[485]
  PIN q[486]
    DIRECTION OUTPUT ;
    USE SIGNAL ;
    PORT
      LAYER M4 ;
        RECT  11.688 93.696 11.88 93.72 ;
    END
  END q[486]
  PIN q[487]
    DIRECTION OUTPUT ;
    USE SIGNAL ;
    PORT
      LAYER M4 ;
        RECT  11.688 93.888 11.88 93.912 ;
    END
  END q[487]
  PIN q[488]
    DIRECTION OUTPUT ;
    USE SIGNAL ;
    PORT
      LAYER M4 ;
        RECT  11.688 94.08 11.88 94.104 ;
    END
  END q[488]
  PIN q[489]
    DIRECTION OUTPUT ;
    USE SIGNAL ;
    PORT
      LAYER M4 ;
        RECT  11.688 94.272 11.88 94.296 ;
    END
  END q[489]
  PIN q[48]
    DIRECTION OUTPUT ;
    USE SIGNAL ;
    PORT
      LAYER M4 ;
        RECT  11.688 9.6 11.88 9.624 ;
    END
  END q[48]
  PIN q[490]
    DIRECTION OUTPUT ;
    USE SIGNAL ;
    PORT
      LAYER M4 ;
        RECT  11.688 94.464 11.88 94.488 ;
    END
  END q[490]
  PIN q[491]
    DIRECTION OUTPUT ;
    USE SIGNAL ;
    PORT
      LAYER M4 ;
        RECT  11.688 94.656 11.88 94.68 ;
    END
  END q[491]
  PIN q[492]
    DIRECTION OUTPUT ;
    USE SIGNAL ;
    PORT
      LAYER M4 ;
        RECT  11.688 94.848 11.88 94.872 ;
    END
  END q[492]
  PIN q[493]
    DIRECTION OUTPUT ;
    USE SIGNAL ;
    PORT
      LAYER M4 ;
        RECT  11.688 95.04 11.88 95.064 ;
    END
  END q[493]
  PIN q[494]
    DIRECTION OUTPUT ;
    USE SIGNAL ;
    PORT
      LAYER M4 ;
        RECT  11.688 95.232 11.88 95.256 ;
    END
  END q[494]
  PIN q[495]
    DIRECTION OUTPUT ;
    USE SIGNAL ;
    PORT
      LAYER M4 ;
        RECT  11.688 95.424 11.88 95.448 ;
    END
  END q[495]
  PIN q[496]
    DIRECTION OUTPUT ;
    USE SIGNAL ;
    PORT
      LAYER M4 ;
        RECT  11.688 95.616 11.88 95.64 ;
    END
  END q[496]
  PIN q[497]
    DIRECTION OUTPUT ;
    USE SIGNAL ;
    PORT
      LAYER M4 ;
        RECT  11.688 95.808 11.88 95.832 ;
    END
  END q[497]
  PIN q[498]
    DIRECTION OUTPUT ;
    USE SIGNAL ;
    PORT
      LAYER M4 ;
        RECT  11.688 96 11.88 96.024 ;
    END
  END q[498]
  PIN q[499]
    DIRECTION OUTPUT ;
    USE SIGNAL ;
    PORT
      LAYER M4 ;
        RECT  11.688 96.192 11.88 96.216 ;
    END
  END q[499]
  PIN q[49]
    DIRECTION OUTPUT ;
    USE SIGNAL ;
    PORT
      LAYER M4 ;
        RECT  11.688 9.792 11.88 9.816 ;
    END
  END q[49]
  PIN q[4]
    DIRECTION OUTPUT ;
    USE SIGNAL ;
    PORT
      LAYER M4 ;
        RECT  11.688 1.152 11.88 1.176 ;
    END
  END q[4]
  PIN q[500]
    DIRECTION OUTPUT ;
    USE SIGNAL ;
    PORT
      LAYER M4 ;
        RECT  11.688 96.384 11.88 96.408 ;
    END
  END q[500]
  PIN q[501]
    DIRECTION OUTPUT ;
    USE SIGNAL ;
    PORT
      LAYER M4 ;
        RECT  11.688 96.576 11.88 96.6 ;
    END
  END q[501]
  PIN q[502]
    DIRECTION OUTPUT ;
    USE SIGNAL ;
    PORT
      LAYER M4 ;
        RECT  11.688 96.768 11.88 96.792 ;
    END
  END q[502]
  PIN q[503]
    DIRECTION OUTPUT ;
    USE SIGNAL ;
    PORT
      LAYER M4 ;
        RECT  11.688 96.96 11.88 96.984 ;
    END
  END q[503]
  PIN q[504]
    DIRECTION OUTPUT ;
    USE SIGNAL ;
    PORT
      LAYER M4 ;
        RECT  11.688 97.152 11.88 97.176 ;
    END
  END q[504]
  PIN q[505]
    DIRECTION OUTPUT ;
    USE SIGNAL ;
    PORT
      LAYER M4 ;
        RECT  11.688 97.344 11.88 97.368 ;
    END
  END q[505]
  PIN q[506]
    DIRECTION OUTPUT ;
    USE SIGNAL ;
    PORT
      LAYER M4 ;
        RECT  11.688 97.536 11.88 97.56 ;
    END
  END q[506]
  PIN q[507]
    DIRECTION OUTPUT ;
    USE SIGNAL ;
    PORT
      LAYER M4 ;
        RECT  11.688 97.728 11.88 97.752 ;
    END
  END q[507]
  PIN q[508]
    DIRECTION OUTPUT ;
    USE SIGNAL ;
    PORT
      LAYER M4 ;
        RECT  11.688 97.92 11.88 97.944 ;
    END
  END q[508]
  PIN q[509]
    DIRECTION OUTPUT ;
    USE SIGNAL ;
    PORT
      LAYER M4 ;
        RECT  11.688 98.112 11.88 98.136 ;
    END
  END q[509]
  PIN q[50]
    DIRECTION OUTPUT ;
    USE SIGNAL ;
    PORT
      LAYER M4 ;
        RECT  11.688 9.984 11.88 10.008 ;
    END
  END q[50]
  PIN q[510]
    DIRECTION OUTPUT ;
    USE SIGNAL ;
    PORT
      LAYER M4 ;
        RECT  11.688 98.304 11.88 98.328 ;
    END
  END q[510]
  PIN q[511]
    DIRECTION OUTPUT ;
    USE SIGNAL ;
    PORT
      LAYER M4 ;
        RECT  11.688 98.496 11.88 98.52 ;
    END
  END q[511]
  PIN q[512]
    DIRECTION OUTPUT ;
    USE SIGNAL ;
    PORT
      LAYER M4 ;
        RECT  11.688 98.688 11.88 98.712 ;
    END
  END q[512]
  PIN q[513]
    DIRECTION OUTPUT ;
    USE SIGNAL ;
    PORT
      LAYER M4 ;
        RECT  11.688 98.88 11.88 98.904 ;
    END
  END q[513]
  PIN q[514]
    DIRECTION OUTPUT ;
    USE SIGNAL ;
    PORT
      LAYER M4 ;
        RECT  11.688 99.072 11.88 99.096 ;
    END
  END q[514]
  PIN q[515]
    DIRECTION OUTPUT ;
    USE SIGNAL ;
    PORT
      LAYER M4 ;
        RECT  11.688 99.264 11.88 99.288 ;
    END
  END q[515]
  PIN q[516]
    DIRECTION OUTPUT ;
    USE SIGNAL ;
    PORT
      LAYER M4 ;
        RECT  11.688 99.456 11.88 99.48 ;
    END
  END q[516]
  PIN q[517]
    DIRECTION OUTPUT ;
    USE SIGNAL ;
    PORT
      LAYER M4 ;
        RECT  11.688 99.648 11.88 99.672 ;
    END
  END q[517]
  PIN q[518]
    DIRECTION OUTPUT ;
    USE SIGNAL ;
    PORT
      LAYER M4 ;
        RECT  11.688 99.84 11.88 99.864 ;
    END
  END q[518]
  PIN q[519]
    DIRECTION OUTPUT ;
    USE SIGNAL ;
    PORT
      LAYER M4 ;
        RECT  11.688 100.032 11.88 100.056 ;
    END
  END q[519]
  PIN q[51]
    DIRECTION OUTPUT ;
    USE SIGNAL ;
    PORT
      LAYER M4 ;
        RECT  11.688 10.176 11.88 10.2 ;
    END
  END q[51]
  PIN q[520]
    DIRECTION OUTPUT ;
    USE SIGNAL ;
    PORT
      LAYER M4 ;
        RECT  11.688 100.224 11.88 100.248 ;
    END
  END q[520]
  PIN q[521]
    DIRECTION OUTPUT ;
    USE SIGNAL ;
    PORT
      LAYER M4 ;
        RECT  11.688 100.416 11.88 100.44 ;
    END
  END q[521]
  PIN q[522]
    DIRECTION OUTPUT ;
    USE SIGNAL ;
    PORT
      LAYER M4 ;
        RECT  11.688 100.608 11.88 100.632 ;
    END
  END q[522]
  PIN q[523]
    DIRECTION OUTPUT ;
    USE SIGNAL ;
    PORT
      LAYER M4 ;
        RECT  11.688 100.8 11.88 100.824 ;
    END
  END q[523]
  PIN q[524]
    DIRECTION OUTPUT ;
    USE SIGNAL ;
    PORT
      LAYER M4 ;
        RECT  11.688 100.992 11.88 101.016 ;
    END
  END q[524]
  PIN q[525]
    DIRECTION OUTPUT ;
    USE SIGNAL ;
    PORT
      LAYER M4 ;
        RECT  11.688 101.184 11.88 101.208 ;
    END
  END q[525]
  PIN q[526]
    DIRECTION OUTPUT ;
    USE SIGNAL ;
    PORT
      LAYER M4 ;
        RECT  11.688 101.376 11.88 101.4 ;
    END
  END q[526]
  PIN q[527]
    DIRECTION OUTPUT ;
    USE SIGNAL ;
    PORT
      LAYER M4 ;
        RECT  11.688 101.568 11.88 101.592 ;
    END
  END q[527]
  PIN q[528]
    DIRECTION OUTPUT ;
    USE SIGNAL ;
    PORT
      LAYER M4 ;
        RECT  11.688 101.76 11.88 101.784 ;
    END
  END q[528]
  PIN q[529]
    DIRECTION OUTPUT ;
    USE SIGNAL ;
    PORT
      LAYER M4 ;
        RECT  11.688 101.952 11.88 101.976 ;
    END
  END q[529]
  PIN q[52]
    DIRECTION OUTPUT ;
    USE SIGNAL ;
    PORT
      LAYER M4 ;
        RECT  11.688 10.368 11.88 10.392 ;
    END
  END q[52]
  PIN q[530]
    DIRECTION OUTPUT ;
    USE SIGNAL ;
    PORT
      LAYER M4 ;
        RECT  11.688 102.144 11.88 102.168 ;
    END
  END q[530]
  PIN q[531]
    DIRECTION OUTPUT ;
    USE SIGNAL ;
    PORT
      LAYER M4 ;
        RECT  11.688 102.336 11.88 102.36 ;
    END
  END q[531]
  PIN q[532]
    DIRECTION OUTPUT ;
    USE SIGNAL ;
    PORT
      LAYER M4 ;
        RECT  11.688 102.528 11.88 102.552 ;
    END
  END q[532]
  PIN q[533]
    DIRECTION OUTPUT ;
    USE SIGNAL ;
    PORT
      LAYER M4 ;
        RECT  11.688 102.72 11.88 102.744 ;
    END
  END q[533]
  PIN q[534]
    DIRECTION OUTPUT ;
    USE SIGNAL ;
    PORT
      LAYER M4 ;
        RECT  11.688 102.912 11.88 102.936 ;
    END
  END q[534]
  PIN q[535]
    DIRECTION OUTPUT ;
    USE SIGNAL ;
    PORT
      LAYER M4 ;
        RECT  11.688 103.104 11.88 103.128 ;
    END
  END q[535]
  PIN q[536]
    DIRECTION OUTPUT ;
    USE SIGNAL ;
    PORT
      LAYER M4 ;
        RECT  11.688 103.296 11.88 103.32 ;
    END
  END q[536]
  PIN q[537]
    DIRECTION OUTPUT ;
    USE SIGNAL ;
    PORT
      LAYER M4 ;
        RECT  11.688 103.488 11.88 103.512 ;
    END
  END q[537]
  PIN q[538]
    DIRECTION OUTPUT ;
    USE SIGNAL ;
    PORT
      LAYER M4 ;
        RECT  11.688 103.68 11.88 103.704 ;
    END
  END q[538]
  PIN q[539]
    DIRECTION OUTPUT ;
    USE SIGNAL ;
    PORT
      LAYER M4 ;
        RECT  11.688 103.872 11.88 103.896 ;
    END
  END q[539]
  PIN q[53]
    DIRECTION OUTPUT ;
    USE SIGNAL ;
    PORT
      LAYER M4 ;
        RECT  11.688 10.56 11.88 10.584 ;
    END
  END q[53]
  PIN q[540]
    DIRECTION OUTPUT ;
    USE SIGNAL ;
    PORT
      LAYER M4 ;
        RECT  11.688 104.064 11.88 104.088 ;
    END
  END q[540]
  PIN q[541]
    DIRECTION OUTPUT ;
    USE SIGNAL ;
    PORT
      LAYER M4 ;
        RECT  11.688 104.256 11.88 104.28 ;
    END
  END q[541]
  PIN q[542]
    DIRECTION OUTPUT ;
    USE SIGNAL ;
    PORT
      LAYER M4 ;
        RECT  11.688 104.448 11.88 104.472 ;
    END
  END q[542]
  PIN q[543]
    DIRECTION OUTPUT ;
    USE SIGNAL ;
    PORT
      LAYER M4 ;
        RECT  11.688 104.64 11.88 104.664 ;
    END
  END q[543]
  PIN q[54]
    DIRECTION OUTPUT ;
    USE SIGNAL ;
    PORT
      LAYER M4 ;
        RECT  11.688 10.752 11.88 10.776 ;
    END
  END q[54]
  PIN q[55]
    DIRECTION OUTPUT ;
    USE SIGNAL ;
    PORT
      LAYER M4 ;
        RECT  11.688 10.944 11.88 10.968 ;
    END
  END q[55]
  PIN q[56]
    DIRECTION OUTPUT ;
    USE SIGNAL ;
    PORT
      LAYER M4 ;
        RECT  11.688 11.136 11.88 11.16 ;
    END
  END q[56]
  PIN q[57]
    DIRECTION OUTPUT ;
    USE SIGNAL ;
    PORT
      LAYER M4 ;
        RECT  11.688 11.328 11.88 11.352 ;
    END
  END q[57]
  PIN q[58]
    DIRECTION OUTPUT ;
    USE SIGNAL ;
    PORT
      LAYER M4 ;
        RECT  11.688 11.52 11.88 11.544 ;
    END
  END q[58]
  PIN q[59]
    DIRECTION OUTPUT ;
    USE SIGNAL ;
    PORT
      LAYER M4 ;
        RECT  11.688 11.712 11.88 11.736 ;
    END
  END q[59]
  PIN q[5]
    DIRECTION OUTPUT ;
    USE SIGNAL ;
    PORT
      LAYER M4 ;
        RECT  11.688 1.344 11.88 1.368 ;
    END
  END q[5]
  PIN q[60]
    DIRECTION OUTPUT ;
    USE SIGNAL ;
    PORT
      LAYER M4 ;
        RECT  11.688 11.904 11.88 11.928 ;
    END
  END q[60]
  PIN q[61]
    DIRECTION OUTPUT ;
    USE SIGNAL ;
    PORT
      LAYER M4 ;
        RECT  11.688 12.096 11.88 12.12 ;
    END
  END q[61]
  PIN q[62]
    DIRECTION OUTPUT ;
    USE SIGNAL ;
    PORT
      LAYER M4 ;
        RECT  11.688 12.288 11.88 12.312 ;
    END
  END q[62]
  PIN q[63]
    DIRECTION OUTPUT ;
    USE SIGNAL ;
    PORT
      LAYER M4 ;
        RECT  11.688 12.48 11.88 12.504 ;
    END
  END q[63]
  PIN q[64]
    DIRECTION OUTPUT ;
    USE SIGNAL ;
    PORT
      LAYER M4 ;
        RECT  11.688 12.672 11.88 12.696 ;
    END
  END q[64]
  PIN q[65]
    DIRECTION OUTPUT ;
    USE SIGNAL ;
    PORT
      LAYER M4 ;
        RECT  11.688 12.864 11.88 12.888 ;
    END
  END q[65]
  PIN q[66]
    DIRECTION OUTPUT ;
    USE SIGNAL ;
    PORT
      LAYER M4 ;
        RECT  11.688 13.056 11.88 13.08 ;
    END
  END q[66]
  PIN q[67]
    DIRECTION OUTPUT ;
    USE SIGNAL ;
    PORT
      LAYER M4 ;
        RECT  11.688 13.248 11.88 13.272 ;
    END
  END q[67]
  PIN q[68]
    DIRECTION OUTPUT ;
    USE SIGNAL ;
    PORT
      LAYER M4 ;
        RECT  11.688 13.44 11.88 13.464 ;
    END
  END q[68]
  PIN q[69]
    DIRECTION OUTPUT ;
    USE SIGNAL ;
    PORT
      LAYER M4 ;
        RECT  11.688 13.632 11.88 13.656 ;
    END
  END q[69]
  PIN q[6]
    DIRECTION OUTPUT ;
    USE SIGNAL ;
    PORT
      LAYER M4 ;
        RECT  11.688 1.536 11.88 1.56 ;
    END
  END q[6]
  PIN q[70]
    DIRECTION OUTPUT ;
    USE SIGNAL ;
    PORT
      LAYER M4 ;
        RECT  11.688 13.824 11.88 13.848 ;
    END
  END q[70]
  PIN q[71]
    DIRECTION OUTPUT ;
    USE SIGNAL ;
    PORT
      LAYER M4 ;
        RECT  11.688 14.016 11.88 14.04 ;
    END
  END q[71]
  PIN q[72]
    DIRECTION OUTPUT ;
    USE SIGNAL ;
    PORT
      LAYER M4 ;
        RECT  11.688 14.208 11.88 14.232 ;
    END
  END q[72]
  PIN q[73]
    DIRECTION OUTPUT ;
    USE SIGNAL ;
    PORT
      LAYER M4 ;
        RECT  11.688 14.4 11.88 14.424 ;
    END
  END q[73]
  PIN q[74]
    DIRECTION OUTPUT ;
    USE SIGNAL ;
    PORT
      LAYER M4 ;
        RECT  11.688 14.592 11.88 14.616 ;
    END
  END q[74]
  PIN q[75]
    DIRECTION OUTPUT ;
    USE SIGNAL ;
    PORT
      LAYER M4 ;
        RECT  11.688 14.784 11.88 14.808 ;
    END
  END q[75]
  PIN q[76]
    DIRECTION OUTPUT ;
    USE SIGNAL ;
    PORT
      LAYER M4 ;
        RECT  11.688 14.976 11.88 15 ;
    END
  END q[76]
  PIN q[77]
    DIRECTION OUTPUT ;
    USE SIGNAL ;
    PORT
      LAYER M4 ;
        RECT  11.688 15.168 11.88 15.192 ;
    END
  END q[77]
  PIN q[78]
    DIRECTION OUTPUT ;
    USE SIGNAL ;
    PORT
      LAYER M4 ;
        RECT  11.688 15.36 11.88 15.384 ;
    END
  END q[78]
  PIN q[79]
    DIRECTION OUTPUT ;
    USE SIGNAL ;
    PORT
      LAYER M4 ;
        RECT  11.688 15.552 11.88 15.576 ;
    END
  END q[79]
  PIN q[7]
    DIRECTION OUTPUT ;
    USE SIGNAL ;
    PORT
      LAYER M4 ;
        RECT  11.688 1.728 11.88 1.752 ;
    END
  END q[7]
  PIN q[80]
    DIRECTION OUTPUT ;
    USE SIGNAL ;
    PORT
      LAYER M4 ;
        RECT  11.688 15.744 11.88 15.768 ;
    END
  END q[80]
  PIN q[81]
    DIRECTION OUTPUT ;
    USE SIGNAL ;
    PORT
      LAYER M4 ;
        RECT  11.688 15.936 11.88 15.96 ;
    END
  END q[81]
  PIN q[82]
    DIRECTION OUTPUT ;
    USE SIGNAL ;
    PORT
      LAYER M4 ;
        RECT  11.688 16.128 11.88 16.152 ;
    END
  END q[82]
  PIN q[83]
    DIRECTION OUTPUT ;
    USE SIGNAL ;
    PORT
      LAYER M4 ;
        RECT  11.688 16.32 11.88 16.344 ;
    END
  END q[83]
  PIN q[84]
    DIRECTION OUTPUT ;
    USE SIGNAL ;
    PORT
      LAYER M4 ;
        RECT  11.688 16.512 11.88 16.536 ;
    END
  END q[84]
  PIN q[85]
    DIRECTION OUTPUT ;
    USE SIGNAL ;
    PORT
      LAYER M4 ;
        RECT  11.688 16.704 11.88 16.728 ;
    END
  END q[85]
  PIN q[86]
    DIRECTION OUTPUT ;
    USE SIGNAL ;
    PORT
      LAYER M4 ;
        RECT  11.688 16.896 11.88 16.92 ;
    END
  END q[86]
  PIN q[87]
    DIRECTION OUTPUT ;
    USE SIGNAL ;
    PORT
      LAYER M4 ;
        RECT  11.688 17.088 11.88 17.112 ;
    END
  END q[87]
  PIN q[88]
    DIRECTION OUTPUT ;
    USE SIGNAL ;
    PORT
      LAYER M4 ;
        RECT  11.688 17.28 11.88 17.304 ;
    END
  END q[88]
  PIN q[89]
    DIRECTION OUTPUT ;
    USE SIGNAL ;
    PORT
      LAYER M4 ;
        RECT  11.688 17.472 11.88 17.496 ;
    END
  END q[89]
  PIN q[8]
    DIRECTION OUTPUT ;
    USE SIGNAL ;
    PORT
      LAYER M4 ;
        RECT  11.688 1.92 11.88 1.944 ;
    END
  END q[8]
  PIN q[90]
    DIRECTION OUTPUT ;
    USE SIGNAL ;
    PORT
      LAYER M4 ;
        RECT  11.688 17.664 11.88 17.688 ;
    END
  END q[90]
  PIN q[91]
    DIRECTION OUTPUT ;
    USE SIGNAL ;
    PORT
      LAYER M4 ;
        RECT  11.688 17.856 11.88 17.88 ;
    END
  END q[91]
  PIN q[92]
    DIRECTION OUTPUT ;
    USE SIGNAL ;
    PORT
      LAYER M4 ;
        RECT  11.688 18.048 11.88 18.072 ;
    END
  END q[92]
  PIN q[93]
    DIRECTION OUTPUT ;
    USE SIGNAL ;
    PORT
      LAYER M4 ;
        RECT  11.688 18.24 11.88 18.264 ;
    END
  END q[93]
  PIN q[94]
    DIRECTION OUTPUT ;
    USE SIGNAL ;
    PORT
      LAYER M4 ;
        RECT  11.688 18.432 11.88 18.456 ;
    END
  END q[94]
  PIN q[95]
    DIRECTION OUTPUT ;
    USE SIGNAL ;
    PORT
      LAYER M4 ;
        RECT  11.688 18.624 11.88 18.648 ;
    END
  END q[95]
  PIN q[96]
    DIRECTION OUTPUT ;
    USE SIGNAL ;
    PORT
      LAYER M4 ;
        RECT  11.688 18.816 11.88 18.84 ;
    END
  END q[96]
  PIN q[97]
    DIRECTION OUTPUT ;
    USE SIGNAL ;
    PORT
      LAYER M4 ;
        RECT  11.688 19.008 11.88 19.032 ;
    END
  END q[97]
  PIN q[98]
    DIRECTION OUTPUT ;
    USE SIGNAL ;
    PORT
      LAYER M4 ;
        RECT  11.688 19.2 11.88 19.224 ;
    END
  END q[98]
  PIN q[99]
    DIRECTION OUTPUT ;
    USE SIGNAL ;
    PORT
      LAYER M4 ;
        RECT  11.688 19.392 11.88 19.416 ;
    END
  END q[99]
  PIN q[9]
    DIRECTION OUTPUT ;
    USE SIGNAL ;
    PORT
      LAYER M4 ;
        RECT  11.688 2.112 11.88 2.136 ;
    END
  END q[9]
  PIN VDD
    DIRECTION INOUT ;
    USE POWER ;
    PORT
      LAYER M5 ;
        RECT  6.372 0.531 6.492 105.309 ;
        RECT  0.972 0.531 1.092 105.309 ;
    END
  END VDD
  PIN VSS
    DIRECTION INOUT ;
    USE GROUND ;
    PORT
      LAYER M5 ;
        RECT  6.18 0.517 6.3 105.323 ;
        RECT  0.78 0.517 0.9 105.323 ;
    END
  END VSS
  OBS
    LAYER RVTN ;
     RECT  0.54 0.54 11.34 0.675 ;
     RECT  0.54 0.945 11.34 1.215 ;
     RECT  0.54 1.485 11.34 1.755 ;
     RECT  0.54 2.025 11.34 2.295 ;
     RECT  0.54 2.565 11.34 2.835 ;
     RECT  0.54 3.105 11.34 3.375 ;
     RECT  0.54 3.645 11.34 3.915 ;
     RECT  0.54 4.185 11.34 4.455 ;
     RECT  0.54 4.725 11.34 4.995 ;
     RECT  0.54 5.265 11.34 5.535 ;
     RECT  0.54 5.805 11.34 6.075 ;
     RECT  0.54 6.345 11.34 6.615 ;
     RECT  0.54 6.885 11.34 7.155 ;
     RECT  0.54 7.425 11.34 7.695 ;
     RECT  0.54 7.965 11.34 8.235 ;
     RECT  0.54 8.505 11.34 8.775 ;
     RECT  0.54 9.045 11.34 9.315 ;
     RECT  0.54 9.585 11.34 9.855 ;
     RECT  0.54 10.125 11.34 10.395 ;
     RECT  0.54 10.665 11.34 10.935 ;
     RECT  0.54 11.205 11.34 11.475 ;
     RECT  0.54 11.745 11.34 12.015 ;
     RECT  0.54 12.285 11.34 12.555 ;
     RECT  0.54 12.825 11.34 13.095 ;
     RECT  0.54 13.365 11.34 13.635 ;
     RECT  0.54 13.905 11.34 14.175 ;
     RECT  0.54 14.445 11.34 14.715 ;
     RECT  0.54 14.985 11.34 15.255 ;
     RECT  0.54 15.525 11.34 15.795 ;
     RECT  0.54 16.065 11.34 16.335 ;
     RECT  0.54 16.605 11.34 16.875 ;
     RECT  0.54 17.145 11.34 17.415 ;
     RECT  0.54 17.685 11.34 17.955 ;
     RECT  0.54 18.225 11.34 18.495 ;
     RECT  0.54 18.765 11.34 19.035 ;
     RECT  0.54 19.305 11.34 19.575 ;
     RECT  0.54 19.845 11.34 20.115 ;
     RECT  0.54 20.385 11.34 20.655 ;
     RECT  0.54 20.925 11.34 21.195 ;
     RECT  0.54 21.465 11.34 21.735 ;
     RECT  0.54 22.005 11.34 22.275 ;
     RECT  0.54 22.545 11.34 22.815 ;
     RECT  0.54 23.085 11.34 23.355 ;
     RECT  0.54 23.625 11.34 23.895 ;
     RECT  0.54 24.165 11.34 24.435 ;
     RECT  0.54 24.705 11.34 24.975 ;
     RECT  0.54 25.245 11.34 25.515 ;
     RECT  0.54 25.785 11.34 26.055 ;
     RECT  0.54 26.325 11.34 26.595 ;
     RECT  0.54 26.865 11.34 27.135 ;
     RECT  0.54 27.405 11.34 27.675 ;
     RECT  0.54 27.945 11.34 28.215 ;
     RECT  0.54 28.485 11.34 28.755 ;
     RECT  0.54 29.025 11.34 29.295 ;
     RECT  0.54 29.565 11.34 29.835 ;
     RECT  0.54 30.105 11.34 30.375 ;
     RECT  0.54 30.645 11.34 30.915 ;
     RECT  0.54 31.185 11.34 31.455 ;
     RECT  0.54 31.725 11.34 31.995 ;
     RECT  0.54 32.265 11.34 32.535 ;
     RECT  0.54 32.805 11.34 33.075 ;
     RECT  0.54 33.345 11.34 33.615 ;
     RECT  0.54 33.885 11.34 34.155 ;
     RECT  0.54 34.425 11.34 34.695 ;
     RECT  0.54 34.965 11.34 35.235 ;
     RECT  0.54 35.505 11.34 35.775 ;
     RECT  0.54 36.045 11.34 36.315 ;
     RECT  0.54 36.585 11.34 36.855 ;
     RECT  0.54 37.125 11.34 37.395 ;
     RECT  0.54 37.665 11.34 37.935 ;
     RECT  0.54 38.205 11.34 38.475 ;
     RECT  0.54 38.745 11.34 39.015 ;
     RECT  0.54 39.285 11.34 39.555 ;
     RECT  0.54 39.825 11.34 40.095 ;
     RECT  0.54 40.365 11.34 40.635 ;
     RECT  0.54 40.905 11.34 41.175 ;
     RECT  0.54 41.445 11.34 41.715 ;
     RECT  0.54 41.985 11.34 42.255 ;
     RECT  0.54 42.525 11.34 42.795 ;
     RECT  0.54 43.065 11.34 43.335 ;
     RECT  0.54 43.605 11.34 43.875 ;
     RECT  0.54 44.145 11.34 44.415 ;
     RECT  0.54 44.685 11.34 44.955 ;
     RECT  0.54 45.225 11.34 45.495 ;
     RECT  0.54 45.765 11.34 46.035 ;
     RECT  0.54 46.305 11.34 46.575 ;
     RECT  0.54 46.845 11.34 47.115 ;
     RECT  0.54 47.385 11.34 47.655 ;
     RECT  0.54 47.925 11.34 48.195 ;
     RECT  0.54 48.465 11.34 48.735 ;
     RECT  0.54 49.005 11.34 49.275 ;
     RECT  0.54 49.545 11.34 49.815 ;
     RECT  0.54 50.085 11.34 50.355 ;
     RECT  0.54 50.625 11.34 50.895 ;
     RECT  0.54 51.165 11.34 51.435 ;
     RECT  0.54 51.705 11.34 51.975 ;
     RECT  0.54 52.245 11.34 52.515 ;
     RECT  0.54 52.785 11.34 53.055 ;
     RECT  0.54 53.325 11.34 53.595 ;
     RECT  0.54 53.865 11.34 54.135 ;
     RECT  0.54 54.405 11.34 54.675 ;
     RECT  0.54 54.945 11.34 55.215 ;
     RECT  0.54 55.485 11.34 55.755 ;
     RECT  0.54 56.025 11.34 56.295 ;
     RECT  0.54 56.565 11.34 56.835 ;
     RECT  0.54 57.105 11.34 57.375 ;
     RECT  0.54 57.645 11.34 57.915 ;
     RECT  0.54 58.185 11.34 58.455 ;
     RECT  0.54 58.725 11.34 58.995 ;
     RECT  0.54 59.265 11.34 59.535 ;
     RECT  0.54 59.805 11.34 60.075 ;
     RECT  0.54 60.345 11.34 60.615 ;
     RECT  0.54 60.885 11.34 61.155 ;
     RECT  0.54 61.425 11.34 61.695 ;
     RECT  0.54 61.965 11.34 62.235 ;
     RECT  0.54 62.505 11.34 62.775 ;
     RECT  0.54 63.045 11.34 63.315 ;
     RECT  0.54 63.585 11.34 63.855 ;
     RECT  0.54 64.125 11.34 64.395 ;
     RECT  0.54 64.665 11.34 64.935 ;
     RECT  0.54 65.205 11.34 65.475 ;
     RECT  0.54 65.745 11.34 66.015 ;
     RECT  0.54 66.285 11.34 66.555 ;
     RECT  0.54 66.825 11.34 67.095 ;
     RECT  0.54 67.365 11.34 67.635 ;
     RECT  0.54 67.905 11.34 68.175 ;
     RECT  0.54 68.445 11.34 68.715 ;
     RECT  0.54 68.985 11.34 69.255 ;
     RECT  0.54 69.525 11.34 69.795 ;
     RECT  0.54 70.065 11.34 70.335 ;
     RECT  0.54 70.605 11.34 70.875 ;
     RECT  0.54 71.145 11.34 71.415 ;
     RECT  0.54 71.685 11.34 71.955 ;
     RECT  0.54 72.225 11.34 72.495 ;
     RECT  0.54 72.765 11.34 73.035 ;
     RECT  0.54 73.305 11.34 73.575 ;
     RECT  0.54 73.845 11.34 74.115 ;
     RECT  0.54 74.385 11.34 74.655 ;
     RECT  0.54 74.925 11.34 75.195 ;
     RECT  0.54 75.465 11.34 75.735 ;
     RECT  0.54 76.005 11.34 76.275 ;
     RECT  0.54 76.545 11.34 76.815 ;
     RECT  0.54 77.085 11.34 77.355 ;
     RECT  0.54 77.625 11.34 77.895 ;
     RECT  0.54 78.165 11.34 78.435 ;
     RECT  0.54 78.705 11.34 78.975 ;
     RECT  0.54 79.245 11.34 79.515 ;
     RECT  0.54 79.785 11.34 80.055 ;
     RECT  0.54 80.325 11.34 80.595 ;
     RECT  0.54 80.865 11.34 81.135 ;
     RECT  0.54 81.405 11.34 81.675 ;
     RECT  0.54 81.945 11.34 82.215 ;
     RECT  0.54 82.485 11.34 82.755 ;
     RECT  0.54 83.025 11.34 83.295 ;
     RECT  0.54 83.565 11.34 83.835 ;
     RECT  0.54 84.105 11.34 84.375 ;
     RECT  0.54 84.645 11.34 84.915 ;
     RECT  0.54 85.185 11.34 85.455 ;
     RECT  0.54 85.725 11.34 85.995 ;
     RECT  0.54 86.265 11.34 86.535 ;
     RECT  0.54 86.805 11.34 87.075 ;
     RECT  0.54 87.345 11.34 87.615 ;
     RECT  0.54 87.885 11.34 88.155 ;
     RECT  0.54 88.425 11.34 88.695 ;
     RECT  0.54 88.965 11.34 89.235 ;
     RECT  0.54 89.505 11.34 89.775 ;
     RECT  0.54 90.045 11.34 90.315 ;
     RECT  0.54 90.585 11.34 90.855 ;
     RECT  0.54 91.125 11.34 91.395 ;
     RECT  0.54 91.665 11.34 91.935 ;
     RECT  0.54 92.205 11.34 92.475 ;
     RECT  0.54 92.745 11.34 93.015 ;
     RECT  0.54 93.285 11.34 93.555 ;
     RECT  0.54 93.825 11.34 94.095 ;
     RECT  0.54 94.365 11.34 94.635 ;
     RECT  0.54 94.905 11.34 95.175 ;
     RECT  0.54 95.445 11.34 95.715 ;
     RECT  0.54 95.985 11.34 96.255 ;
     RECT  0.54 96.525 11.34 96.795 ;
     RECT  0.54 97.065 11.34 97.335 ;
     RECT  0.54 97.605 11.34 97.875 ;
     RECT  0.54 98.145 11.34 98.415 ;
     RECT  0.54 98.685 11.34 98.955 ;
     RECT  0.54 99.225 11.34 99.495 ;
     RECT  0.54 99.765 11.34 100.035 ;
     RECT  0.54 100.305 11.34 100.575 ;
     RECT  0.54 100.845 11.34 101.115 ;
     RECT  0.54 101.385 11.34 101.655 ;
     RECT  0.54 101.925 11.34 102.195 ;
     RECT  0.54 102.465 11.34 102.735 ;
     RECT  0.54 103.005 11.34 103.275 ;
     RECT  0.54 103.545 11.34 103.815 ;
     RECT  0.54 104.085 11.34 104.355 ;
     RECT  0.54 104.625 11.34 104.895 ;
     RECT  0.54 105.165 11.34 105.3 ;
    LAYER RVTP ;
     RECT  0.54 0.675 11.34 0.945 ;
     RECT  0.54 1.215 11.34 1.485 ;
     RECT  0.54 1.755 11.34 2.025 ;
     RECT  0.54 2.295 11.34 2.565 ;
     RECT  0.54 2.835 11.34 3.105 ;
     RECT  0.54 3.375 11.34 3.645 ;
     RECT  0.54 3.915 11.34 4.185 ;
     RECT  0.54 4.455 11.34 4.725 ;
     RECT  0.54 4.995 11.34 5.265 ;
     RECT  0.54 5.535 11.34 5.805 ;
     RECT  0.54 6.075 11.34 6.345 ;
     RECT  0.54 6.615 11.34 6.885 ;
     RECT  0.54 7.155 11.34 7.425 ;
     RECT  0.54 7.695 11.34 7.965 ;
     RECT  0.54 8.235 11.34 8.505 ;
     RECT  0.54 8.775 11.34 9.045 ;
     RECT  0.54 9.315 11.34 9.585 ;
     RECT  0.54 9.855 11.34 10.125 ;
     RECT  0.54 10.395 11.34 10.665 ;
     RECT  0.54 10.935 11.34 11.205 ;
     RECT  0.54 11.475 11.34 11.745 ;
     RECT  0.54 12.015 11.34 12.285 ;
     RECT  0.54 12.555 11.34 12.825 ;
     RECT  0.54 13.095 11.34 13.365 ;
     RECT  0.54 13.635 11.34 13.905 ;
     RECT  0.54 14.175 11.34 14.445 ;
     RECT  0.54 14.715 11.34 14.985 ;
     RECT  0.54 15.255 11.34 15.525 ;
     RECT  0.54 15.795 11.34 16.065 ;
     RECT  0.54 16.335 11.34 16.605 ;
     RECT  0.54 16.875 11.34 17.145 ;
     RECT  0.54 17.415 11.34 17.685 ;
     RECT  0.54 17.955 11.34 18.225 ;
     RECT  0.54 18.495 11.34 18.765 ;
     RECT  0.54 19.035 11.34 19.305 ;
     RECT  0.54 19.575 11.34 19.845 ;
     RECT  0.54 20.115 11.34 20.385 ;
     RECT  0.54 20.655 11.34 20.925 ;
     RECT  0.54 21.195 11.34 21.465 ;
     RECT  0.54 21.735 11.34 22.005 ;
     RECT  0.54 22.275 11.34 22.545 ;
     RECT  0.54 22.815 11.34 23.085 ;
     RECT  0.54 23.355 11.34 23.625 ;
     RECT  0.54 23.895 11.34 24.165 ;
     RECT  0.54 24.435 11.34 24.705 ;
     RECT  0.54 24.975 11.34 25.245 ;
     RECT  0.54 25.515 11.34 25.785 ;
     RECT  0.54 26.055 11.34 26.325 ;
     RECT  0.54 26.595 11.34 26.865 ;
     RECT  0.54 27.135 11.34 27.405 ;
     RECT  0.54 27.675 11.34 27.945 ;
     RECT  0.54 28.215 11.34 28.485 ;
     RECT  0.54 28.755 11.34 29.025 ;
     RECT  0.54 29.295 11.34 29.565 ;
     RECT  0.54 29.835 11.34 30.105 ;
     RECT  0.54 30.375 11.34 30.645 ;
     RECT  0.54 30.915 11.34 31.185 ;
     RECT  0.54 31.455 11.34 31.725 ;
     RECT  0.54 31.995 11.34 32.265 ;
     RECT  0.54 32.535 11.34 32.805 ;
     RECT  0.54 33.075 11.34 33.345 ;
     RECT  0.54 33.615 11.34 33.885 ;
     RECT  0.54 34.155 11.34 34.425 ;
     RECT  0.54 34.695 11.34 34.965 ;
     RECT  0.54 35.235 11.34 35.505 ;
     RECT  0.54 35.775 11.34 36.045 ;
     RECT  0.54 36.315 11.34 36.585 ;
     RECT  0.54 36.855 11.34 37.125 ;
     RECT  0.54 37.395 11.34 37.665 ;
     RECT  0.54 37.935 11.34 38.205 ;
     RECT  0.54 38.475 11.34 38.745 ;
     RECT  0.54 39.015 11.34 39.285 ;
     RECT  0.54 39.555 11.34 39.825 ;
     RECT  0.54 40.095 11.34 40.365 ;
     RECT  0.54 40.635 11.34 40.905 ;
     RECT  0.54 41.175 11.34 41.445 ;
     RECT  0.54 41.715 11.34 41.985 ;
     RECT  0.54 42.255 11.34 42.525 ;
     RECT  0.54 42.795 11.34 43.065 ;
     RECT  0.54 43.335 11.34 43.605 ;
     RECT  0.54 43.875 11.34 44.145 ;
     RECT  0.54 44.415 11.34 44.685 ;
     RECT  0.54 44.955 11.34 45.225 ;
     RECT  0.54 45.495 11.34 45.765 ;
     RECT  0.54 46.035 11.34 46.305 ;
     RECT  0.54 46.575 11.34 46.845 ;
     RECT  0.54 47.115 11.34 47.385 ;
     RECT  0.54 47.655 11.34 47.925 ;
     RECT  0.54 48.195 11.34 48.465 ;
     RECT  0.54 48.735 11.34 49.005 ;
     RECT  0.54 49.275 11.34 49.545 ;
     RECT  0.54 49.815 11.34 50.085 ;
     RECT  0.54 50.355 11.34 50.625 ;
     RECT  0.54 50.895 11.34 51.165 ;
     RECT  0.54 51.435 11.34 51.705 ;
     RECT  0.54 51.975 11.34 52.245 ;
     RECT  0.54 52.515 11.34 52.785 ;
     RECT  0.54 53.055 11.34 53.325 ;
     RECT  0.54 53.595 11.34 53.865 ;
     RECT  0.54 54.135 11.34 54.405 ;
     RECT  0.54 54.675 11.34 54.945 ;
     RECT  0.54 55.215 11.34 55.485 ;
     RECT  0.54 55.755 11.34 56.025 ;
     RECT  0.54 56.295 11.34 56.565 ;
     RECT  0.54 56.835 11.34 57.105 ;
     RECT  0.54 57.375 11.34 57.645 ;
     RECT  0.54 57.915 11.34 58.185 ;
     RECT  0.54 58.455 11.34 58.725 ;
     RECT  0.54 58.995 11.34 59.265 ;
     RECT  0.54 59.535 11.34 59.805 ;
     RECT  0.54 60.075 11.34 60.345 ;
     RECT  0.54 60.615 11.34 60.885 ;
     RECT  0.54 61.155 11.34 61.425 ;
     RECT  0.54 61.695 11.34 61.965 ;
     RECT  0.54 62.235 11.34 62.505 ;
     RECT  0.54 62.775 11.34 63.045 ;
     RECT  0.54 63.315 11.34 63.585 ;
     RECT  0.54 63.855 11.34 64.125 ;
     RECT  0.54 64.395 11.34 64.665 ;
     RECT  0.54 64.935 11.34 65.205 ;
     RECT  0.54 65.475 11.34 65.745 ;
     RECT  0.54 66.015 11.34 66.285 ;
     RECT  0.54 66.555 11.34 66.825 ;
     RECT  0.54 67.095 11.34 67.365 ;
     RECT  0.54 67.635 11.34 67.905 ;
     RECT  0.54 68.175 11.34 68.445 ;
     RECT  0.54 68.715 11.34 68.985 ;
     RECT  0.54 69.255 11.34 69.525 ;
     RECT  0.54 69.795 11.34 70.065 ;
     RECT  0.54 70.335 11.34 70.605 ;
     RECT  0.54 70.875 11.34 71.145 ;
     RECT  0.54 71.415 11.34 71.685 ;
     RECT  0.54 71.955 11.34 72.225 ;
     RECT  0.54 72.495 11.34 72.765 ;
     RECT  0.54 73.035 11.34 73.305 ;
     RECT  0.54 73.575 11.34 73.845 ;
     RECT  0.54 74.115 11.34 74.385 ;
     RECT  0.54 74.655 11.34 74.925 ;
     RECT  0.54 75.195 11.34 75.465 ;
     RECT  0.54 75.735 11.34 76.005 ;
     RECT  0.54 76.275 11.34 76.545 ;
     RECT  0.54 76.815 11.34 77.085 ;
     RECT  0.54 77.355 11.34 77.625 ;
     RECT  0.54 77.895 11.34 78.165 ;
     RECT  0.54 78.435 11.34 78.705 ;
     RECT  0.54 78.975 11.34 79.245 ;
     RECT  0.54 79.515 11.34 79.785 ;
     RECT  0.54 80.055 11.34 80.325 ;
     RECT  0.54 80.595 11.34 80.865 ;
     RECT  0.54 81.135 11.34 81.405 ;
     RECT  0.54 81.675 11.34 81.945 ;
     RECT  0.54 82.215 11.34 82.485 ;
     RECT  0.54 82.755 11.34 83.025 ;
     RECT  0.54 83.295 11.34 83.565 ;
     RECT  0.54 83.835 11.34 84.105 ;
     RECT  0.54 84.375 11.34 84.645 ;
     RECT  0.54 84.915 11.34 85.185 ;
     RECT  0.54 85.455 11.34 85.725 ;
     RECT  0.54 85.995 11.34 86.265 ;
     RECT  0.54 86.535 11.34 86.805 ;
     RECT  0.54 87.075 11.34 87.345 ;
     RECT  0.54 87.615 11.34 87.885 ;
     RECT  0.54 88.155 11.34 88.425 ;
     RECT  0.54 88.695 11.34 88.965 ;
     RECT  0.54 89.235 11.34 89.505 ;
     RECT  0.54 89.775 11.34 90.045 ;
     RECT  0.54 90.315 11.34 90.585 ;
     RECT  0.54 90.855 11.34 91.125 ;
     RECT  0.54 91.395 11.34 91.665 ;
     RECT  0.54 91.935 11.34 92.205 ;
     RECT  0.54 92.475 11.34 92.745 ;
     RECT  0.54 93.015 11.34 93.285 ;
     RECT  0.54 93.555 11.34 93.825 ;
     RECT  0.54 94.095 11.34 94.365 ;
     RECT  0.54 94.635 11.34 94.905 ;
     RECT  0.54 95.175 11.34 95.445 ;
     RECT  0.54 95.715 11.34 95.985 ;
     RECT  0.54 96.255 11.34 96.525 ;
     RECT  0.54 96.795 11.34 97.065 ;
     RECT  0.54 97.335 11.34 97.605 ;
     RECT  0.54 97.875 11.34 98.145 ;
     RECT  0.54 98.415 11.34 98.685 ;
     RECT  0.54 98.955 11.34 99.225 ;
     RECT  0.54 99.495 11.34 99.765 ;
     RECT  0.54 100.035 11.34 100.305 ;
     RECT  0.54 100.575 11.34 100.845 ;
     RECT  0.54 101.115 11.34 101.385 ;
     RECT  0.54 101.655 11.34 101.925 ;
     RECT  0.54 102.195 11.34 102.465 ;
     RECT  0.54 102.735 11.34 103.005 ;
     RECT  0.54 103.275 11.34 103.545 ;
     RECT  0.54 103.815 11.34 104.085 ;
     RECT  0.54 104.355 11.34 104.625 ;
     RECT  0.54 104.895 11.34 105.165 ;
    LAYER M1 ;
     RECT  0.54 0.531 11.34 105.309 ;
    LAYER M2 ;
     RECT  0.211 0.612 0.247 0.63 ;
     RECT  0.211 1.422 0.247 1.548 ;
     RECT  0.211 2.502 0.247 2.79 ;
     RECT  0.211 3.852 0.247 6.138 ;
     RECT  0.211 7.092 0.247 7.11 ;
     RECT  0.211 7.902 0.247 7.92 ;
     RECT  0.211 12.222 0.247 13.05 ;
     RECT  0.211 13.842 0.247 14.508 ;
     RECT  0.211 15.732 0.247 17.37 ;
     RECT  0.211 24.372 0.247 28.314 ;
     RECT  0.211 29.232 0.247 29.25 ;
     RECT  0.211 30.042 0.247 31.95 ;
     RECT  0.211 32.742 0.247 33.57 ;
     RECT  0.211 34.362 0.247 42.318 ;
     RECT  0.211 43.542 0.247 45.72 ;
     RECT  0.211 46.512 0.247 48.69 ;
     RECT  0.211 49.482 0.247 50.31 ;
     RECT  0.211 51.102 0.247 51.66 ;
     RECT  0.211 52.452 0.247 53.046 ;
     RECT  0.211 53.802 0.247 56.592 ;
     RECT  0.211 57.582 0.247 60.3 ;
     RECT  0.211 61.092 0.247 61.65 ;
     RECT  0.211 62.442 0.247 64.08 ;
     RECT  0.211 76.482 0.247 79.74 ;
     RECT  0.211 80.532 0.247 80.55 ;
     RECT  0.211 85.122 0.247 88.488 ;
     RECT  0.211 89.712 0.247 91.62 ;
     RECT  0.211 96.462 0.247 98.1 ;
     RECT  0.211 98.892 0.247 99.45 ;
     RECT  0.211 81.882 0.283 82.17 ;
     RECT  0.247 96.462 0.319 99.45 ;
     RECT  0.211 100.242 0.319 102.69 ;
     RECT  0.247 0.612 0.355 1.548 ;
     RECT  0.247 2.502 0.355 6.138 ;
     RECT  0.247 7.092 0.355 7.92 ;
     RECT  0.211 8.982 0.463 9 ;
     RECT  0.211 9.9 0.463 11.43 ;
     RECT  0.247 30.042 0.463 33.57 ;
     RECT  0.247 34.362 0.463 42.48 ;
     RECT  0.247 52.452 0.463 56.628 ;
     RECT  0.247 57.582 0.463 64.08 ;
     RECT  0.211 70.272 0.463 75.42 ;
     RECT  0.247 76.482 0.463 80.55 ;
     RECT  0.319 96.462 0.463 102.69 ;
     RECT  0.211 103.482 0.463 103.5 ;
     RECT  0.463 8.982 0.499 11.43 ;
     RECT  0.247 12.222 0.499 14.508 ;
     RECT  0.247 89.712 0.499 91.89 ;
     RECT  0.211 92.682 0.499 95.67 ;
     RECT  0.355 0.612 0.54 6.138 ;
     RECT  0.355 6.93 0.54 7.92 ;
     RECT  0.499 8.982 0.54 14.508 ;
     RECT  0.247 15.462 0.54 17.37 ;
     RECT  0.211 18.162 0.54 23.31 ;
     RECT  0.247 24.372 0.54 29.25 ;
     RECT  0.463 30.042 0.54 42.48 ;
     RECT  0.247 43.542 0.54 51.66 ;
     RECT  0.463 52.452 0.54 64.08 ;
     RECT  0.211 64.872 0.54 65.16 ;
     RECT  0.211 65.952 0.54 68.67 ;
     RECT  0.211 69.462 0.54 69.48 ;
     RECT  0.463 70.272 0.54 80.55 ;
     RECT  0.283 81.45 0.54 82.17 ;
     RECT  0.211 82.962 0.54 83.628 ;
     RECT  0.247 84.582 0.54 88.488 ;
     RECT  0.499 89.712 0.54 95.67 ;
     RECT  0.463 96.462 0.54 103.5 ;
     RECT  0.211 104.562 0.54 104.58 ;
     RECT  0.54 0.531 11.34 105.309 ;
     RECT  11.34 19.206 11.687 19.224 ;
     RECT  11.34 30.816 11.687 30.834 ;
     RECT  11.34 8.046 11.759 8.064 ;
    LAYER M3 ;
     RECT  0.216 0.379 0.234 0.523 ;
     RECT  0.216 0.523 0.885 0.571 ;
     RECT  0.216 0.571 1.098 0.607 ;
     RECT  1.836 0.571 2.97 0.607 ;
     RECT  0.216 0.607 2.97 0.751 ;
     RECT  10.836 0.379 10.854 0.763 ;
     RECT  6.195 0.523 6.285 0.793 ;
     RECT  7.416 0.751 7.434 0.869 ;
     RECT  0.216 0.751 3.474 0.877 ;
     RECT  0.216 0.877 3.582 0.913 ;
     RECT  4.392 0.751 4.41 0.913 ;
     RECT  10.368 0.763 10.854 0.955 ;
     RECT  8.496 0.571 8.514 0.985 ;
     RECT  0.216 0.913 4.41 1.021 ;
     RECT  8.496 0.985 9.162 1.021 ;
     RECT  6.195 0.793 6.477 1.111 ;
     RECT  0.216 1.021 4.482 1.139 ;
     RECT  8.496 1.021 9.522 1.139 ;
     RECT  8.496 1.139 9.486 1.219 ;
     RECT  10.368 0.955 11.034 1.219 ;
     RECT  10.26 1.219 11.034 1.373 ;
     RECT  6.156 1.111 6.477 1.381 ;
     RECT  10.476 1.373 11.034 1.409 ;
     RECT  5.256 1.381 5.274 1.483 ;
     RECT  6.156 1.381 7.038 1.483 ;
     RECT  5.256 1.483 7.038 1.651 ;
     RECT  7.884 1.219 9.486 1.651 ;
     RECT  5.256 1.651 9.486 1.679 ;
     RECT  5.328 1.679 9.486 1.709 ;
     RECT  5.328 1.709 8.55 1.715 ;
     RECT  5.688 1.715 8.55 1.751 ;
     RECT  5.688 1.751 7.938 1.949 ;
     RECT  9.468 1.709 9.486 1.985 ;
     RECT  0.216 1.139 4.338 2.065 ;
     RECT  0.216 2.065 4.374 2.141 ;
     RECT  10.476 1.409 10.854 2.371 ;
     RECT  10.26 2.371 10.854 2.525 ;
     RECT  5.688 1.949 6.858 2.641 ;
     RECT  7.632 1.949 7.938 2.641 ;
     RECT  7.632 2.641 8.082 2.731 ;
     RECT  10.656 2.525 10.854 2.759 ;
     RECT  4.968 2.641 6.858 2.911 ;
     RECT  7.632 2.731 8.478 2.911 ;
     RECT  4.968 2.911 8.622 3.029 ;
     RECT  5.976 3.029 8.622 3.037 ;
     RECT  4.968 3.029 4.986 3.065 ;
     RECT  5.976 3.037 8.694 3.065 ;
     RECT  8.244 3.065 8.694 3.137 ;
     RECT  0.216 2.141 4.158 3.499 ;
     RECT  10.836 2.759 10.854 3.643 ;
     RECT  0.216 3.499 4.23 3.721 ;
     RECT  5.976 3.065 6.477 3.811 ;
     RECT  10.836 3.643 10.926 3.811 ;
     RECT  8.244 3.137 8.298 3.839 ;
     RECT  10.8 3.811 10.926 3.869 ;
     RECT  0.216 3.721 4.374 3.919 ;
     RECT  5.292 3.811 6.477 3.919 ;
     RECT  9.468 3.883 9.486 3.955 ;
     RECT  10.836 3.869 10.926 3.991 ;
     RECT  10.836 3.991 10.998 4.027 ;
     RECT  0.216 3.919 6.477 4.145 ;
     RECT  9.324 3.955 9.486 4.219 ;
     RECT  9.324 4.219 9.882 4.261 ;
     RECT  8.244 3.839 8.262 4.621 ;
     RECT  10.836 4.027 11.214 4.649 ;
     RECT  9.324 4.261 10.026 4.765 ;
     RECT  10.836 4.649 11.034 4.765 ;
     RECT  5.004 4.145 6.477 4.877 ;
     RECT  9.324 4.765 11.034 4.877 ;
     RECT  8.136 4.621 8.262 4.891 ;
     RECT  10.08 4.877 11.034 4.919 ;
     RECT  8.136 4.891 8.766 4.927 ;
     RECT  10.08 4.919 10.89 5.027 ;
     RECT  7.884 4.927 8.766 5.099 ;
     RECT  7.884 5.099 8.478 5.131 ;
     RECT  0.216 4.145 3.834 5.179 ;
     RECT  7.488 5.131 8.478 5.189 ;
     RECT  0.216 5.179 3.87 5.197 ;
     RECT  10.188 5.027 10.89 5.213 ;
     RECT  7.488 5.189 7.506 5.225 ;
     RECT  8.388 5.189 8.478 5.297 ;
     RECT  0.216 5.197 4.014 5.305 ;
     RECT  4.788 4.891 4.95 5.305 ;
     RECT  8.46 5.297 8.478 5.369 ;
     RECT  10.188 5.213 10.854 5.639 ;
     RECT  0.216 5.305 4.95 5.765 ;
     RECT  5.94 4.877 6.477 5.773 ;
     RECT  7.236 5.707 7.254 5.773 ;
     RECT  5.94 5.773 7.254 5.909 ;
     RECT  7.236 5.909 7.254 5.971 ;
     RECT  7.236 5.971 7.398 5.999 ;
     RECT  10.224 5.639 10.854 6.365 ;
     RECT  5.94 5.909 6.477 6.421 ;
     RECT  5.148 6.187 5.166 6.523 ;
     RECT  5.904 6.421 6.477 6.523 ;
     RECT  10.8 6.365 10.854 6.557 ;
     RECT  0.216 5.765 4.374 6.619 ;
     RECT  5.148 6.523 6.477 6.619 ;
     RECT  7.38 5.999 7.398 6.647 ;
     RECT  0.216 6.619 6.477 6.781 ;
     RECT  10.8 6.557 10.818 7.099 ;
     RECT  0.216 6.781 6.642 7.231 ;
     RECT  10.764 7.099 10.818 7.291 ;
     RECT  10.656 7.291 10.818 7.321 ;
     RECT  10.584 7.321 10.926 7.393 ;
     RECT  0.216 7.231 7.002 7.501 ;
     RECT  10.116 7.393 10.926 7.517 ;
     RECT  8.892 7.339 8.91 7.579 ;
     RECT  10.116 7.517 10.314 7.619 ;
     RECT  8.316 7.579 8.91 7.663 ;
     RECT  8.172 7.663 8.91 7.889 ;
     RECT  10.26 7.619 10.314 7.889 ;
     RECT  0.216 7.501 7.362 7.901 ;
     RECT  10.296 7.889 10.314 7.961 ;
     RECT  11.736 8.011 11.754 8.041 ;
     RECT  7.236 7.901 7.362 8.069 ;
     RECT  11.664 8.041 11.754 8.069 ;
     RECT  11.664 8.069 11.682 8.093 ;
     RECT  0.216 7.901 6.477 8.159 ;
     RECT  7.416 8.131 7.434 8.311 ;
     RECT  8.892 7.889 8.91 8.311 ;
     RECT  10.8 8.251 10.818 8.339 ;
     RECT  7.416 8.311 8.118 8.465 ;
     RECT  7.884 8.465 8.118 8.609 ;
     RECT  8.892 8.311 9.234 8.635 ;
     RECT  0.216 8.159 5.058 8.879 ;
     RECT  4.932 8.879 5.058 8.969 ;
     RECT  8.1 8.609 8.118 8.969 ;
     RECT  0.216 8.879 4.194 9.041 ;
     RECT  5.832 8.159 6.477 9.085 ;
     RECT  8.892 8.635 9.666 9.121 ;
     RECT  8.244 9.121 9.666 9.211 ;
     RECT  10.836 8.437 10.854 9.211 ;
     RECT  10.836 9.211 10.926 9.245 ;
     RECT  8.244 9.211 9.702 9.419 ;
     RECT  9.36 9.419 9.702 9.437 ;
     RECT  5.544 9.085 6.477 9.481 ;
     RECT  10.836 9.245 10.854 9.589 ;
     RECT  10.656 9.589 10.854 9.629 ;
     RECT  5.544 9.481 7.182 9.661 ;
     RECT  9.36 9.437 9.378 9.779 ;
     RECT  5.544 9.661 7.434 9.787 ;
     RECT  8.244 9.419 8.406 9.821 ;
     RECT  5.076 9.787 7.434 9.931 ;
     RECT  0.216 9.041 3.978 10.021 ;
     RECT  5.076 9.931 8.046 10.049 ;
     RECT  10.8 9.629 10.854 10.049 ;
     RECT  7.416 10.049 8.046 10.085 ;
     RECT  0.216 10.021 4.122 10.121 ;
     RECT  7.776 10.085 8.046 10.555 ;
     RECT  7.776 10.555 8.442 10.589 ;
     RECT  10.836 10.049 10.854 10.589 ;
     RECT  5.076 10.049 6.477 10.705 ;
     RECT  8.424 10.589 8.442 10.741 ;
     RECT  10.908 10.741 10.926 10.781 ;
     RECT  5.004 10.705 6.477 10.829 ;
     RECT  5.22 10.829 6.477 10.843 ;
     RECT  5.22 10.843 6.894 10.859 ;
     RECT  9.576 10.939 9.594 11.101 ;
     RECT  6.195 10.859 6.894 11.165 ;
     RECT  5.22 10.859 5.238 11.273 ;
     RECT  8.424 10.741 8.586 11.407 ;
     RECT  9.576 11.101 9.666 11.407 ;
     RECT  0.216 10.121 3.978 11.443 ;
     RECT  10.836 11.407 10.854 11.551 ;
     RECT  10.548 11.551 10.854 11.641 ;
     RECT  7.668 11.551 7.686 11.669 ;
     RECT  8.424 11.407 9.774 11.669 ;
     RECT  10.548 11.641 10.926 11.669 ;
     RECT  9.54 11.669 9.558 11.813 ;
     RECT  8.424 11.669 8.73 11.821 ;
     RECT  10.908 11.669 10.926 11.821 ;
     RECT  10.908 11.821 11.214 11.933 ;
     RECT  0.216 11.443 4.014 11.947 ;
     RECT  5.112 11.785 5.13 11.947 ;
     RECT  0.216 11.947 5.13 12.047 ;
     RECT  6.195 11.165 6.477 12.181 ;
     RECT  10.908 11.933 11.106 12.451 ;
     RECT  5.292 12.361 5.31 12.475 ;
     RECT  6.195 12.181 7.074 12.475 ;
     RECT  8.316 11.821 8.73 12.475 ;
     RECT  5.292 12.475 7.074 12.557 ;
     RECT  0.216 12.047 4.554 12.587 ;
     RECT  7.992 12.475 8.73 12.587 ;
     RECT  10.836 12.451 11.106 12.667 ;
     RECT  8.46 12.587 8.73 12.749 ;
     RECT  10.836 12.667 11.214 12.749 ;
     RECT  10.836 12.749 10.998 12.757 ;
     RECT  6.156 12.557 7.074 12.785 ;
     RECT  10.728 12.757 10.998 12.785 ;
     RECT  10.728 12.785 10.926 12.929 ;
     RECT  5.292 12.557 5.382 13.003 ;
     RECT  0.216 12.587 3.906 13.055 ;
     RECT  8.46 12.749 8.478 13.085 ;
     RECT  0.252 13.055 3.906 13.405 ;
     RECT  4.824 13.003 5.382 13.405 ;
     RECT  6.156 12.785 7.002 13.405 ;
     RECT  10.728 12.929 10.89 13.441 ;
     RECT  10.188 13.441 10.89 13.711 ;
     RECT  0.252 13.405 7.002 13.801 ;
     RECT  0.252 13.801 7.29 13.819 ;
     RECT  0.216 13.819 7.29 13.865 ;
     RECT  9.9 13.711 10.89 13.909 ;
     RECT  6.12 13.865 7.29 13.945 ;
     RECT  6.12 13.945 7.722 13.981 ;
     RECT  9.792 13.909 10.89 14.011 ;
     RECT  6.12 13.981 8.37 14.099 ;
     RECT  9.792 14.011 10.926 14.099 ;
     RECT  0.216 13.865 5.166 14.369 ;
     RECT  6.195 14.099 8.37 14.369 ;
     RECT  4.356 14.369 4.698 14.573 ;
     RECT  6.195 14.369 7.83 14.639 ;
     RECT  6.195 14.639 7.542 14.747 ;
     RECT  4.356 14.573 4.518 14.813 ;
     RECT  10.224 14.099 10.854 14.881 ;
     RECT  0.216 14.369 3.546 15.151 ;
     RECT  9.9 14.881 10.854 15.151 ;
     RECT  9.648 15.151 10.854 15.259 ;
     RECT  6.195 14.747 6.477 15.331 ;
     RECT  5.832 15.331 6.477 15.389 ;
     RECT  9.576 15.259 10.854 15.389 ;
     RECT  7.38 14.747 7.542 15.557 ;
     RECT  0.216 15.151 3.762 15.565 ;
     RECT  4.5 14.813 4.518 15.565 ;
     RECT  5.976 15.389 6.477 15.601 ;
     RECT  10.836 15.389 10.854 15.601 ;
     RECT  0.216 15.565 4.518 15.691 ;
     RECT  5.976 15.601 7.11 15.719 ;
     RECT  10.836 15.601 10.89 15.965 ;
     RECT  5.976 15.719 6.477 15.989 ;
     RECT  9.576 15.389 9.594 16.123 ;
     RECT  9.576 16.123 9.63 16.169 ;
     RECT  0.216 15.691 4.914 16.439 ;
     RECT  8.46 16.231 8.478 16.501 ;
     RECT  9.216 16.375 9.234 16.501 ;
     RECT  8.46 16.501 9.234 16.565 ;
     RECT  7.524 16.501 7.542 16.681 ;
     RECT  10.908 16.231 11.142 16.699 ;
     RECT  6.195 15.989 6.477 16.795 ;
     RECT  7.524 16.681 8.154 16.795 ;
     RECT  10.764 16.699 11.142 16.891 ;
     RECT  4.608 16.439 4.914 16.951 ;
     RECT  9.144 16.565 9.234 17.035 ;
     RECT  9.144 17.035 9.378 17.069 ;
     RECT  10.764 16.891 11.214 17.069 ;
     RECT  10.764 17.069 11.142 17.117 ;
     RECT  4.608 16.951 4.95 17.311 ;
     RECT  6.195 16.795 8.154 17.311 ;
     RECT  0.216 16.439 3.834 17.455 ;
     RECT  4.608 17.311 8.154 17.455 ;
     RECT  0.216 17.455 8.154 17.717 ;
     RECT  0.216 17.717 6.477 17.915 ;
     RECT  9.216 17.069 9.234 17.959 ;
     RECT  9.144 17.959 9.378 18.031 ;
     RECT  10.764 17.117 10.854 18.031 ;
     RECT  10.404 18.031 10.854 18.043 ;
     RECT  7.488 17.717 8.154 18.059 ;
     RECT  10.404 18.043 10.926 18.139 ;
     RECT  8.064 18.059 8.154 18.149 ;
     RECT  9.072 18.031 9.378 18.149 ;
     RECT  10.116 18.139 10.926 18.149 ;
     RECT  8.136 18.149 8.154 18.185 ;
     RECT  9.144 18.149 9.378 18.221 ;
     RECT  10.116 18.149 10.854 18.269 ;
     RECT  8.28 18.301 8.298 18.419 ;
     RECT  0.216 17.915 4.842 18.527 ;
     RECT  10.116 18.269 10.386 18.571 ;
     RECT  5.58 17.915 6.477 18.967 ;
     RECT  9.648 18.571 10.386 19.111 ;
     RECT  0.216 18.527 4.446 19.181 ;
     RECT  9.648 19.111 10.854 19.201 ;
     RECT  5.364 18.967 6.477 19.229 ;
     RECT  11.664 18.619 11.682 19.229 ;
     RECT  5.436 19.229 5.454 19.337 ;
     RECT  9.504 19.201 10.854 19.337 ;
     RECT  6.195 19.229 6.477 19.381 ;
     RECT  6.195 19.381 6.642 19.499 ;
     RECT  10.224 19.337 10.854 20.147 ;
     RECT  0.216 19.181 4.23 20.155 ;
     RECT  8.028 20.155 8.046 20.191 ;
     RECT  10.224 20.147 10.602 20.191 ;
     RECT  8.028 20.191 8.406 20.309 ;
     RECT  0.216 20.155 4.338 20.417 ;
     RECT  4.32 20.417 4.338 20.425 ;
     RECT  9.684 20.191 10.602 20.453 ;
     RECT  4.32 20.425 4.698 20.461 ;
     RECT  8.748 20.443 8.766 20.461 ;
     RECT  8.748 20.461 8.91 20.489 ;
     RECT  4.32 20.461 4.842 20.579 ;
     RECT  8.892 20.489 8.91 20.579 ;
     RECT  6.195 19.499 6.477 20.965 ;
     RECT  9.684 20.453 9.702 21.001 ;
     RECT  5.688 20.965 6.477 21.115 ;
     RECT  10.836 20.923 10.854 21.115 ;
     RECT  4.32 20.579 4.734 21.119 ;
     RECT  0.216 20.417 3.546 21.271 ;
     RECT  5.688 21.115 6.678 21.271 ;
     RECT  10.836 21.115 10.998 21.271 ;
     RECT  9.324 21.001 9.702 21.299 ;
     RECT  9.468 21.299 9.702 21.307 ;
     RECT  10.764 21.271 10.998 21.307 ;
     RECT  5.688 21.271 7.038 21.355 ;
     RECT  7.992 21.271 8.01 21.355 ;
     RECT  5.688 21.355 7.182 21.361 ;
     RECT  7.992 21.355 8.694 21.361 ;
     RECT  9.468 21.307 10.998 21.389 ;
     RECT  0.216 21.271 3.834 21.425 ;
     RECT  4.644 21.119 4.734 21.469 ;
     RECT  5.688 21.361 8.694 21.469 ;
     RECT  4.644 21.469 8.694 21.659 ;
     RECT  5.688 21.659 8.694 21.695 ;
     RECT  9.648 21.389 10.998 21.803 ;
     RECT  5.76 21.695 8.694 22.037 ;
     RECT  9.648 21.803 9.666 22.109 ;
     RECT  0.216 21.425 3.438 22.171 ;
     RECT  10.764 21.803 10.998 22.301 ;
     RECT  10.764 22.301 10.926 22.493 ;
     RECT  0.216 22.171 3.978 22.621 ;
     RECT  10.764 22.493 10.854 22.783 ;
     RECT  10.26 22.783 10.854 22.877 ;
     RECT  5.76 22.037 8.586 22.891 ;
     RECT  5.616 22.891 8.586 23.009 ;
     RECT  9.36 23.053 9.378 23.189 ;
     RECT  0.216 22.621 4.698 23.275 ;
     RECT  5.616 23.009 8.298 23.279 ;
     RECT  0.216 23.275 4.734 23.315 ;
     RECT  8.136 23.279 8.154 23.357 ;
     RECT  0.468 23.315 4.734 23.431 ;
     RECT  5.616 23.279 6.93 23.431 ;
     RECT  0.468 23.431 6.93 23.549 ;
     RECT  10.548 22.877 10.854 23.611 ;
     RECT  6.195 23.549 6.93 23.657 ;
     RECT  10.332 23.611 10.854 23.791 ;
     RECT  0.468 23.549 5.454 23.819 ;
     RECT  10.332 23.791 10.89 24.187 ;
     RECT  10.26 24.187 10.89 24.269 ;
     RECT  4.464 23.819 5.454 24.359 ;
     RECT  0.468 23.819 3.654 24.367 ;
     RECT  10.836 24.269 10.89 24.571 ;
     RECT  9.36 24.511 9.378 24.629 ;
     RECT  10.836 24.571 10.926 24.629 ;
     RECT  6.195 23.657 6.477 24.781 ;
     RECT  9.468 24.745 9.486 24.781 ;
     RECT  9.468 24.781 9.666 24.845 ;
     RECT  6.195 24.781 7.074 24.871 ;
     RECT  9.648 24.845 9.666 24.899 ;
     RECT  5.904 24.871 7.074 24.971 ;
     RECT  7.992 24.781 8.586 24.971 ;
     RECT  0.216 24.367 3.654 25.015 ;
     RECT  4.464 24.359 4.806 25.015 ;
     RECT  6.195 24.971 7.074 25.051 ;
     RECT  8.568 24.971 8.586 25.079 ;
     RECT  0.216 25.015 4.806 25.141 ;
     RECT  6.195 25.051 7.11 25.141 ;
     RECT  10.836 24.629 10.854 25.141 ;
     RECT  6.195 25.141 7.326 25.181 ;
     RECT  6.195 25.181 7.11 25.205 ;
     RECT  10.8 25.141 10.854 25.313 ;
     RECT  8.712 25.483 8.73 25.517 ;
     RECT  9.9 25.531 9.918 25.619 ;
     RECT  0.216 25.141 4.914 25.675 ;
     RECT  7.884 25.861 7.902 26.087 ;
     RECT  10.836 25.313 10.854 26.107 ;
     RECT  0.216 25.675 5.13 26.131 ;
     RECT  6.195 25.205 6.93 26.131 ;
     RECT  9.648 25.681 9.666 26.221 ;
     RECT  6.195 26.131 7.074 26.401 ;
     RECT  9.468 26.221 9.666 26.401 ;
     RECT  10.764 26.107 10.854 26.401 ;
     RECT  0.216 26.131 5.166 26.519 ;
     RECT  9.468 26.401 10.854 26.519 ;
     RECT  0.216 26.519 4.878 26.555 ;
     RECT  8.676 26.635 8.694 26.671 ;
     RECT  0.216 26.555 4.698 26.789 ;
     RECT  8.604 26.671 9.09 26.789 ;
     RECT  0.216 26.789 4.41 26.825 ;
     RECT  10.26 26.519 10.854 26.909 ;
     RECT  8.604 26.789 8.982 27.067 ;
     RECT  0.216 26.825 3.87 27.095 ;
     RECT  11.196 27.067 11.214 27.101 ;
     RECT  6.195 26.401 7.326 27.103 ;
     RECT  8.208 27.067 8.982 27.103 ;
     RECT  10.26 26.909 10.35 27.337 ;
     RECT  6.195 27.103 8.982 27.437 ;
     RECT  5.148 27.307 5.274 27.481 ;
     RECT  10.224 27.337 10.35 27.485 ;
     RECT  6.195 27.437 8.802 27.509 ;
     RECT  5.148 27.481 5.454 27.835 ;
     RECT  10.404 27.643 10.674 27.835 ;
     RECT  0.216 27.095 3.474 27.841 ;
     RECT  8.208 27.509 8.802 27.869 ;
     RECT  9.648 27.751 9.666 27.869 ;
     RECT  10.404 27.835 11.214 27.869 ;
     RECT  8.604 27.869 8.802 27.917 ;
     RECT  4.536 27.835 5.454 27.931 ;
     RECT  6.195 27.509 7.434 27.931 ;
     RECT  10.404 27.869 10.926 28.061 ;
     RECT  4.536 27.931 7.434 28.139 ;
     RECT  8.784 27.917 8.802 28.139 ;
     RECT  5.616 28.139 7.434 28.247 ;
     RECT  0.216 27.841 3.798 28.255 ;
     RECT  4.536 28.139 4.878 28.255 ;
     RECT  5.688 28.247 7.434 28.255 ;
     RECT  5.688 28.255 7.506 28.409 ;
     RECT  0.216 28.255 4.878 28.679 ;
     RECT  0.216 28.679 4.698 28.715 ;
     RECT  6.195 28.409 7.506 28.831 ;
     RECT  6.195 28.831 8.19 28.949 ;
     RECT  10.404 28.061 10.854 28.987 ;
     RECT  6.195 28.949 7.902 29.057 ;
     RECT  10.224 28.987 10.854 29.371 ;
     RECT  10.224 29.371 10.998 29.405 ;
     RECT  8.964 29.371 8.982 29.467 ;
     RECT  8.964 29.467 9.126 29.489 ;
     RECT  10.764 29.405 10.998 29.563 ;
     RECT  4.464 28.715 4.698 29.569 ;
     RECT  10.764 29.563 11.214 29.597 ;
     RECT  0.216 28.715 3.258 29.605 ;
     RECT  4.14 29.569 4.698 29.605 ;
     RECT  0.216 29.605 5.274 29.641 ;
     RECT  6.195 29.057 7.578 29.641 ;
     RECT  0.216 29.641 7.578 29.669 ;
     RECT  10.764 29.597 10.998 29.789 ;
     RECT  0.216 29.669 4.23 29.831 ;
     RECT  9.072 29.489 9.126 29.837 ;
     RECT  0.216 29.831 4.158 29.867 ;
     RECT  5.112 29.669 7.578 29.903 ;
     RECT  5.112 29.903 6.642 29.939 ;
     RECT  10.764 29.789 10.926 29.981 ;
     RECT  9.144 29.911 9.162 30.029 ;
     RECT  7.452 29.903 7.578 30.181 ;
     RECT  5.112 29.939 5.382 30.209 ;
     RECT  9.36 30.145 9.666 30.221 ;
     RECT  7.452 30.181 7.65 30.235 ;
     RECT  7.452 30.235 7.758 30.299 ;
     RECT  10.764 29.981 10.854 30.331 ;
     RECT  5.112 30.209 5.274 30.451 ;
     RECT  4.968 30.451 5.274 30.569 ;
     RECT  6.195 29.939 6.642 30.569 ;
     RECT  4.968 30.569 4.986 30.641 ;
     RECT  9.36 30.221 9.378 30.641 ;
     RECT  0.216 29.867 3.942 30.685 ;
     RECT  11.664 30.715 11.682 30.839 ;
     RECT  7.344 30.847 7.362 30.947 ;
     RECT  10.656 30.331 10.854 31.081 ;
     RECT  10.368 31.081 10.854 31.133 ;
     RECT  8.604 31.081 8.622 31.253 ;
     RECT  10.44 31.133 10.854 31.261 ;
     RECT  8.208 31.261 8.37 31.325 ;
     RECT  10.44 31.261 11.034 31.325 ;
     RECT  6.195 30.569 6.534 31.387 ;
     RECT  6.195 31.387 6.786 31.495 ;
     RECT  0.216 30.685 4.41 31.531 ;
     RECT  5.22 31.495 6.786 31.531 ;
     RECT  9.432 31.531 9.45 31.649 ;
     RECT  10.44 31.325 10.818 31.721 ;
     RECT  0.216 31.531 6.786 31.757 ;
     RECT  8.352 31.325 8.37 31.919 ;
     RECT  9.648 31.927 9.666 32.059 ;
     RECT  9.648 32.059 9.846 32.099 ;
     RECT  10.8 31.721 10.818 32.161 ;
     RECT  10.8 32.161 10.854 32.285 ;
     RECT  0.216 31.757 6.57 32.611 ;
     RECT  10.8 32.285 10.818 32.611 ;
     RECT  0.216 32.611 7.254 32.729 ;
     RECT  10.26 32.611 10.818 32.729 ;
     RECT  9.036 32.845 9.054 32.881 ;
     RECT  10.26 32.729 10.458 32.881 ;
     RECT  8.784 32.881 10.458 33.005 ;
     RECT  8.784 33.005 8.802 33.007 ;
     RECT  8.712 33.007 8.802 33.053 ;
     RECT  11.196 33.007 11.214 33.053 ;
     RECT  0.216 32.729 6.966 33.107 ;
     RECT  4.14 33.107 6.966 33.179 ;
     RECT  8.784 33.053 8.802 33.305 ;
     RECT  9.612 33.005 10.458 33.449 ;
     RECT  9.648 33.449 10.458 33.511 ;
     RECT  4.212 33.179 6.966 33.547 ;
     RECT  4.212 33.547 7.074 33.683 ;
     RECT  9.648 33.511 10.494 33.821 ;
     RECT  4.212 33.683 6.477 33.961 ;
     RECT  10.476 33.821 10.494 33.961 ;
     RECT  7.704 33.961 7.722 34.079 ;
     RECT  0.216 33.107 3.33 34.159 ;
     RECT  4.14 33.961 6.477 34.159 ;
     RECT  9.648 33.821 9.666 34.205 ;
     RECT  0.216 34.159 6.477 34.465 ;
     RECT  8.208 34.219 8.226 34.465 ;
     RECT  9.108 34.321 9.126 34.465 ;
     RECT  8.208 34.465 9.126 34.529 ;
     RECT  10.476 33.961 10.854 34.589 ;
     RECT  8.208 34.529 8.406 34.727 ;
     RECT  0.216 34.465 7.398 34.799 ;
     RECT  0.216 34.799 7.146 34.925 ;
     RECT  10.656 34.589 10.854 34.939 ;
     RECT  8.208 34.727 8.334 35.131 ;
     RECT  4.608 34.925 7.146 35.159 ;
     RECT  10.656 34.939 11.034 35.159 ;
     RECT  4.608 35.159 7.038 35.195 ;
     RECT  10.656 35.159 10.854 35.311 ;
     RECT  7.956 35.131 8.334 35.357 ;
     RECT  10.368 35.311 10.854 35.357 ;
     RECT  7.956 35.357 7.974 35.429 ;
     RECT  6.195 35.195 7.038 35.609 ;
     RECT  0.216 34.925 3.798 35.735 ;
     RECT  4.608 35.195 5.238 35.851 ;
     RECT  3.96 35.851 5.238 35.969 ;
     RECT  3.96 35.969 3.978 36.005 ;
     RECT  10.404 35.357 10.854 36.077 ;
     RECT  10.8 36.077 10.854 36.121 ;
     RECT  4.896 35.969 5.238 36.319 ;
     RECT  7.884 35.941 7.902 36.427 ;
     RECT  8.928 36.085 9.09 36.427 ;
     RECT  7.884 36.427 9.09 36.461 ;
     RECT  0.216 35.735 3.114 36.481 ;
     RECT  6.195 35.609 6.858 36.481 ;
     RECT  7.884 36.461 8.37 36.481 ;
     RECT  4.896 36.319 5.274 36.859 ;
     RECT  6.195 36.481 8.37 36.859 ;
     RECT  9.216 36.859 9.702 37.021 ;
     RECT  10.8 36.121 11.214 37.049 ;
     RECT  4.896 36.859 8.37 37.085 ;
     RECT  9.216 37.021 9.846 37.193 ;
     RECT  7.776 37.085 8.37 37.201 ;
     RECT  4.896 37.085 6.477 37.291 ;
     RECT  4.824 37.291 6.477 37.319 ;
     RECT  7.776 37.201 8.514 37.319 ;
     RECT  9.36 37.193 9.846 37.499 ;
     RECT  0.216 36.481 3.654 37.561 ;
     RECT  4.824 37.319 5.31 37.589 ;
     RECT  9.648 37.499 9.846 37.589 ;
     RECT  4.824 37.589 4.95 37.625 ;
     RECT  6.084 37.319 6.477 37.625 ;
     RECT  7.776 37.319 7.794 37.625 ;
     RECT  9.828 37.589 9.846 37.831 ;
     RECT  10.8 37.049 10.854 37.831 ;
     RECT  9.828 37.831 10.854 37.853 ;
     RECT  10.188 37.853 10.854 38.003 ;
     RECT  10.368 38.003 10.854 38.045 ;
     RECT  0.216 37.561 3.834 38.059 ;
     RECT  0.216 38.059 4.338 38.129 ;
     RECT  10.44 38.045 10.854 38.201 ;
     RECT  10.656 38.201 10.854 38.237 ;
     RECT  10.728 38.237 10.854 38.371 ;
     RECT  6.156 37.625 6.477 38.399 ;
     RECT  7.308 38.491 7.326 38.551 ;
     RECT  9.216 38.587 9.234 38.641 ;
     RECT  9.216 38.641 9.306 38.821 ;
     RECT  10.728 38.371 10.926 38.911 ;
     RECT  9.216 38.821 9.594 38.939 ;
     RECT  10.728 38.911 11.034 39.055 ;
     RECT  6.195 38.399 6.477 39.091 ;
     RECT  7.308 38.551 7.506 39.091 ;
     RECT  8.28 38.641 8.298 39.091 ;
     RECT  6.195 39.091 8.298 39.149 ;
     RECT  0.216 38.129 4.158 39.163 ;
     RECT  0.216 39.163 4.842 39.209 ;
     RECT  9.216 38.939 9.342 39.209 ;
     RECT  7.56 39.149 8.298 39.245 ;
     RECT  0.216 39.209 4.158 39.479 ;
     RECT  9.324 39.209 9.342 39.479 ;
     RECT  10.44 39.055 11.034 39.547 ;
     RECT  0.216 39.479 3.834 39.623 ;
     RECT  8.46 39.403 8.478 39.629 ;
     RECT  4.968 39.559 5.382 39.721 ;
     RECT  6.195 39.149 6.534 39.721 ;
     RECT  7.56 39.245 7.686 39.749 ;
     RECT  9.612 39.739 9.63 39.785 ;
     RECT  4.968 39.721 6.534 39.901 ;
     RECT  7.56 39.749 7.614 39.901 ;
     RECT  10.44 39.547 11.214 39.901 ;
     RECT  4.968 39.901 7.614 39.979 ;
     RECT  4.716 39.979 7.614 40.091 ;
     RECT  9.9 39.901 11.214 40.157 ;
     RECT  7.596 40.091 7.614 40.289 ;
     RECT  4.716 40.091 6.786 40.325 ;
     RECT  9.9 40.157 9.918 40.361 ;
     RECT  10.836 40.157 11.214 40.541 ;
     RECT  0.216 39.623 3.762 40.555 ;
     RECT  5.112 40.325 6.786 40.559 ;
     RECT  10.836 40.541 10.854 40.891 ;
     RECT  8.352 40.945 8.37 40.981 ;
     RECT  8.352 40.981 8.514 41.021 ;
     RECT  5.112 40.559 5.238 41.071 ;
     RECT  6.156 40.559 6.786 41.251 ;
     RECT  4.968 41.071 5.238 41.279 ;
     RECT  6.156 41.251 6.822 41.369 ;
     RECT  8.496 41.021 8.514 41.369 ;
     RECT  0.216 40.555 4.23 41.371 ;
     RECT  4.968 41.279 4.986 41.371 ;
     RECT  6.195 41.369 6.822 41.377 ;
     RECT  10.368 40.891 10.854 41.449 ;
     RECT  9.972 41.449 10.854 41.659 ;
     RECT  9.972 41.659 10.89 41.791 ;
     RECT  9.288 41.791 10.89 41.909 ;
     RECT  9.756 41.909 10.89 42.043 ;
     RECT  6.195 41.377 6.894 42.061 ;
     RECT  0.216 41.371 4.986 42.139 ;
     RECT  8.244 42.025 8.334 42.139 ;
     RECT  8.244 42.139 8.766 42.179 ;
     RECT  9.756 42.043 11.214 42.179 ;
     RECT  6.195 42.061 7.074 42.215 ;
     RECT  0.216 42.139 5.31 42.331 ;
     RECT  6.195 42.215 6.477 42.331 ;
     RECT  7.236 42.295 7.254 42.427 ;
     RECT  7.236 42.427 7.434 42.457 ;
     RECT  9.756 42.179 10.818 42.461 ;
     RECT  0.216 42.331 6.477 42.485 ;
     RECT  8.424 42.179 8.442 42.521 ;
     RECT  7.236 42.457 7.47 42.601 ;
     RECT  9.756 42.461 9.81 42.691 ;
     RECT  9.576 42.691 9.81 42.791 ;
     RECT  9.792 42.791 9.81 42.845 ;
     RECT  5.94 42.485 6.477 43.069 ;
     RECT  7.236 42.601 7.614 43.069 ;
     RECT  10.728 42.461 10.818 43.141 ;
     RECT  0.216 42.485 5.202 43.169 ;
     RECT  10.728 43.141 10.998 43.195 ;
     RECT  5.94 43.069 7.614 43.259 ;
     RECT  8.928 43.141 9.054 43.259 ;
     RECT  10.656 43.195 10.998 43.259 ;
     RECT  5.94 43.259 6.477 43.295 ;
     RECT  10.728 43.259 10.998 43.295 ;
     RECT  10.836 43.295 10.998 43.303 ;
     RECT  7.416 43.259 7.614 43.331 ;
     RECT  7.596 43.331 7.614 43.529 ;
     RECT  6.156 43.295 6.477 43.709 ;
     RECT  10.836 43.303 11.214 43.805 ;
     RECT  9.252 43.681 9.27 43.807 ;
     RECT  9.252 43.807 9.45 43.843 ;
     RECT  0.216 43.169 5.13 43.951 ;
     RECT  6.195 43.709 6.477 44.041 ;
     RECT  10.836 43.805 10.854 44.041 ;
     RECT  9.252 43.843 9.594 44.069 ;
     RECT  0.216 43.951 5.418 44.105 ;
     RECT  10.476 44.041 10.854 44.113 ;
     RECT  6.195 44.041 6.858 44.339 ;
     RECT  9.036 44.221 9.054 44.339 ;
     RECT  0.216 44.105 2.718 44.447 ;
     RECT  10.008 44.113 10.854 44.573 ;
     RECT  3.492 44.105 5.418 44.609 ;
     RECT  3.492 44.609 5.058 44.645 ;
     RECT  6.195 44.339 6.477 44.725 ;
     RECT  10.368 44.573 10.854 44.731 ;
     RECT  10.368 44.731 10.926 44.789 ;
     RECT  3.492 44.645 3.51 45.185 ;
     RECT  5.904 44.725 6.477 45.301 ;
     RECT  10.368 44.789 10.89 45.307 ;
     RECT  0.216 44.447 2.502 45.341 ;
     RECT  9.432 45.301 9.45 45.391 ;
     RECT  4.392 44.645 5.058 45.499 ;
     RECT  9.288 45.391 9.45 45.527 ;
     RECT  4.392 45.499 5.166 45.535 ;
     RECT  5.904 45.301 6.678 45.535 ;
     RECT  3.672 45.535 6.678 45.547 ;
     RECT  3.672 45.547 7.146 45.571 ;
     RECT  10.26 45.307 10.89 45.599 ;
     RECT  9.108 45.535 9.126 45.689 ;
     RECT  10.656 45.599 10.89 45.883 ;
     RECT  3.672 45.571 7.29 45.959 ;
     RECT  3.672 45.959 6.858 45.995 ;
     RECT  0.216 45.341 2.43 46.075 ;
     RECT  6.195 45.995 6.858 46.103 ;
     RECT  0.216 46.075 2.898 46.111 ;
     RECT  3.672 45.995 5.202 46.111 ;
     RECT  8.424 46.111 8.586 46.157 ;
     RECT  8.568 46.157 8.586 46.229 ;
     RECT  9.9 45.841 9.918 46.309 ;
     RECT  0.216 46.111 5.202 46.373 ;
     RECT  9.36 46.309 9.918 46.409 ;
     RECT  10.656 45.883 10.926 46.459 ;
     RECT  4.716 46.373 5.202 46.499 ;
     RECT  10.08 46.459 11.106 46.499 ;
     RECT  10.08 46.499 10.854 46.541 ;
     RECT  5.4 46.795 5.454 47.011 ;
     RECT  6.195 46.103 6.477 47.011 ;
     RECT  8.964 47.119 8.982 47.191 ;
     RECT  0.216 46.373 3.906 47.281 ;
     RECT  5.4 47.011 6.477 47.281 ;
     RECT  7.236 47.191 7.254 47.281 ;
     RECT  5.148 47.281 7.254 47.309 ;
     RECT  8.964 47.191 9.126 47.345 ;
     RECT  0.216 47.281 4.05 47.389 ;
     RECT  5.148 47.309 6.534 47.389 ;
     RECT  0.216 47.389 6.534 47.417 ;
     RECT  10.26 46.541 10.854 47.453 ;
     RECT  7.344 47.425 7.398 47.731 ;
     RECT  0.216 47.417 6.477 47.759 ;
     RECT  0.216 47.759 4.23 47.849 ;
     RECT  7.344 47.731 7.974 47.849 ;
     RECT  8.568 47.851 8.586 47.885 ;
     RECT  10.368 47.453 10.854 48.187 ;
     RECT  10.368 48.187 11.214 48.199 ;
     RECT  9.936 48.199 11.214 48.227 ;
     RECT  5.148 47.759 6.477 48.379 ;
     RECT  9.936 48.227 10.854 48.389 ;
     RECT  7.344 47.849 7.65 48.461 ;
     RECT  5.148 48.379 6.57 48.541 ;
     RECT  5.148 48.541 6.75 48.659 ;
     RECT  7.632 48.461 7.65 48.659 ;
     RECT  5.148 48.659 5.454 48.775 ;
     RECT  8.388 48.775 8.406 48.811 ;
     RECT  8.388 48.811 8.91 48.929 ;
     RECT  0.216 47.849 4.194 49.081 ;
     RECT  10.44 48.389 10.854 49.279 ;
     RECT  0.216 49.081 4.266 49.351 ;
     RECT  5.076 48.775 5.454 49.351 ;
     RECT  6.195 48.659 6.75 49.351 ;
     RECT  9.72 49.279 10.854 49.373 ;
     RECT  0.216 49.351 5.454 49.469 ;
     RECT  9.72 49.373 9.81 49.505 ;
     RECT  6.195 49.351 6.858 49.549 ;
     RECT  9.72 49.505 9.738 49.621 ;
     RECT  9 49.621 9.738 49.891 ;
     RECT  8.676 49.891 9.738 50.009 ;
     RECT  5.688 49.549 6.858 50.081 ;
     RECT  9.324 50.009 9.738 50.081 ;
     RECT  5.688 50.081 6.477 50.279 ;
     RECT  8.208 50.203 8.226 50.279 ;
     RECT  10.8 49.373 10.854 50.287 ;
     RECT  0.216 49.469 4.554 50.395 ;
     RECT  10.764 50.287 10.854 50.431 ;
     RECT  10.332 50.431 11.034 50.525 ;
     RECT  0.216 50.395 5.058 50.549 ;
     RECT  10.332 50.525 10.854 50.549 ;
     RECT  9.324 50.081 9.486 50.585 ;
     RECT  0.216 50.549 4.734 50.819 ;
     RECT  7.704 50.701 7.722 50.855 ;
     RECT  9.468 50.585 9.486 50.891 ;
     RECT  5.868 50.279 6.477 51.019 ;
     RECT  0.216 50.819 3.726 51.089 ;
     RECT  5.868 51.019 6.858 51.355 ;
     RECT  7.596 51.241 7.614 51.355 ;
     RECT  8.532 51.241 8.55 51.359 ;
     RECT  3.708 51.089 3.726 51.395 ;
     RECT  4.464 50.819 4.734 51.395 ;
     RECT  10.44 50.549 10.854 51.451 ;
     RECT  10.368 51.451 10.854 51.475 ;
     RECT  10.188 51.475 10.854 51.533 ;
     RECT  4.464 51.395 4.626 51.601 ;
     RECT  3.96 51.601 4.626 51.629 ;
     RECT  5.868 51.355 7.614 51.665 ;
     RECT  10.368 51.533 10.854 51.677 ;
     RECT  3.96 51.629 4.446 51.701 ;
     RECT  5.868 51.665 6.822 51.773 ;
     RECT  10.836 51.677 10.854 51.835 ;
     RECT  10.836 51.835 10.926 51.899 ;
     RECT  7.596 51.665 7.614 51.907 ;
     RECT  0.216 51.089 2.898 51.979 ;
     RECT  7.596 51.907 8.118 52.079 ;
     RECT  7.596 52.079 7.866 52.169 ;
     RECT  10.836 51.899 10.89 52.253 ;
     RECT  0.216 51.979 2.97 52.321 ;
     RECT  3.96 51.701 4.41 52.321 ;
     RECT  10.8 52.411 10.818 52.445 ;
     RECT  5.868 51.773 6.477 52.591 ;
     RECT  9.432 52.411 9.45 52.591 ;
     RECT  9.108 52.591 9.45 52.603 ;
     RECT  9.108 52.603 9.954 52.745 ;
     RECT  9.576 52.745 9.954 52.789 ;
     RECT  0.216 52.321 4.41 52.825 ;
     RECT  5.256 52.591 6.477 52.825 ;
     RECT  9.576 52.789 10.674 52.829 ;
     RECT  0.216 52.825 6.477 52.861 ;
     RECT  7.596 52.169 7.758 52.861 ;
     RECT  9.576 52.829 10.386 53.015 ;
     RECT  10.224 53.015 10.386 53.021 ;
     RECT  0.216 52.861 7.758 53.365 ;
     RECT  0.216 53.365 7.866 53.401 ;
     RECT  0.216 53.401 8.082 53.555 ;
     RECT  10.368 53.021 10.386 53.597 ;
     RECT  0.216 53.555 6.858 54.095 ;
     RECT  8.964 53.941 8.982 54.095 ;
     RECT  7.848 53.555 8.082 54.125 ;
     RECT  7.992 54.125 8.082 54.301 ;
     RECT  0.216 54.095 5.166 54.329 ;
     RECT  7.992 54.301 8.226 54.473 ;
     RECT  0.216 54.329 2.358 54.509 ;
     RECT  10.8 53.755 10.926 54.557 ;
     RECT  6.048 54.095 6.858 54.599 ;
     RECT  6.195 54.599 6.858 54.635 ;
     RECT  9.684 54.211 9.702 55.111 ;
     RECT  10.8 54.557 10.89 55.111 ;
     RECT  3.276 54.329 5.166 55.147 ;
     RECT  3.276 55.147 5.202 55.175 ;
     RECT  9.684 55.111 10.89 55.175 ;
     RECT  7.992 54.473 8.19 55.211 ;
     RECT  0.216 54.509 2.214 55.291 ;
     RECT  6.195 54.635 6.642 55.381 ;
     RECT  6.195 55.381 6.858 55.387 ;
     RECT  6.195 55.387 7.65 55.553 ;
     RECT  3.276 55.175 4.374 55.561 ;
     RECT  0.216 55.291 2.466 55.675 ;
     RECT  3.204 55.561 4.374 55.675 ;
     RECT  7.452 55.553 7.65 55.679 ;
     RECT  5.112 55.175 5.202 55.859 ;
     RECT  10.116 55.175 10.89 55.867 ;
     RECT  6.195 55.553 6.477 55.915 ;
     RECT  10.116 55.867 10.926 55.949 ;
     RECT  0.216 55.675 4.374 55.985 ;
     RECT  10.116 55.949 10.89 56.059 ;
     RECT  3.528 55.985 4.374 56.101 ;
     RECT  7.488 55.679 7.65 56.227 ;
     RECT  10.008 56.059 10.89 56.291 ;
     RECT  9.216 56.335 9.234 56.381 ;
     RECT  7.488 56.227 8.082 56.497 ;
     RECT  10.008 56.291 10.242 56.635 ;
     RECT  3.528 56.101 4.554 56.641 ;
     RECT  5.4 55.915 6.477 56.641 ;
     RECT  3.528 56.641 6.477 56.731 ;
     RECT  3.456 56.731 6.477 56.759 ;
     RECT  3.456 56.759 4.554 56.831 ;
     RECT  9.612 56.635 10.242 56.867 ;
     RECT  7.488 56.497 8.154 56.903 ;
     RECT  0.216 55.985 2.682 57.001 ;
     RECT  10.224 56.867 10.242 57.053 ;
     RECT  4.176 56.831 4.554 57.101 ;
     RECT  5.436 56.759 6.477 57.145 ;
     RECT  5.436 57.145 6.534 57.181 ;
     RECT  7.488 56.903 7.506 57.299 ;
     RECT  11.196 57.211 11.214 57.299 ;
     RECT  5.436 57.181 6.678 57.451 ;
     RECT  5.436 57.451 6.93 57.499 ;
     RECT  4.572 57.499 6.93 57.641 ;
     RECT  9.108 57.541 9.126 57.641 ;
     RECT  0.216 57.001 3.438 57.835 ;
     RECT  0.216 57.835 3.654 57.875 ;
     RECT  10.836 57.403 10.854 57.979 ;
     RECT  4.572 57.641 6.477 57.991 ;
     RECT  7.848 57.811 8.118 57.991 ;
     RECT  7.848 57.991 8.73 58.109 ;
     RECT  9.648 58.081 9.846 58.123 ;
     RECT  10.656 57.979 10.854 58.123 ;
     RECT  7.848 58.109 8.55 58.157 ;
     RECT  9.648 58.123 10.854 58.171 ;
     RECT  7.848 58.157 8.514 58.181 ;
     RECT  3.816 57.991 6.477 58.289 ;
     RECT  7.848 58.181 8.298 58.363 ;
     RECT  7.812 58.363 8.298 58.379 ;
     RECT  7.812 58.379 8.118 58.415 ;
     RECT  4.14 58.289 6.477 58.531 ;
     RECT  4.14 58.531 6.822 58.649 ;
     RECT  9.648 58.171 11.214 58.649 ;
     RECT  8.1 58.415 8.118 58.685 ;
     RECT  9.648 58.649 10.998 58.685 ;
     RECT  9.648 58.685 10.89 58.829 ;
     RECT  10.152 58.829 10.89 58.955 ;
     RECT  4.14 58.649 5.346 59.035 ;
     RECT  6.195 58.649 6.822 59.269 ;
     RECT  6.195 59.269 6.858 59.495 ;
     RECT  4.068 59.035 5.346 59.611 ;
     RECT  6.195 59.495 6.477 59.611 ;
     RECT  10.836 58.955 10.89 59.611 ;
     RECT  4.068 59.611 6.477 59.701 ;
     RECT  0.216 57.875 2.97 59.737 ;
     RECT  3.78 59.701 6.477 59.737 ;
     RECT  10.836 59.611 11.214 59.741 ;
     RECT  8.208 59.611 8.37 59.803 ;
     RECT  8.208 59.803 8.946 59.837 ;
     RECT  10.548 59.809 10.566 59.933 ;
     RECT  10.26 60.091 10.278 60.179 ;
     RECT  7.56 59.881 7.686 60.241 ;
     RECT  9.828 60.277 10.062 60.379 ;
     RECT  11.196 60.475 11.214 60.539 ;
     RECT  9.684 60.379 10.062 60.655 ;
     RECT  9.036 60.655 10.062 60.701 ;
     RECT  9.252 60.701 10.062 60.961 ;
     RECT  0.216 59.737 6.477 61.003 ;
     RECT  7.38 60.241 7.686 61.003 ;
     RECT  0.216 61.003 7.758 61.079 ;
     RECT  0.216 61.079 4.518 61.085 ;
     RECT  5.652 61.079 7.758 61.115 ;
     RECT  9.252 60.961 10.854 61.115 ;
     RECT  9.576 61.115 10.854 61.187 ;
     RECT  0.216 61.085 3.726 61.259 ;
     RECT  5.904 61.115 7.11 61.349 ;
     RECT  9.612 61.187 10.854 61.385 ;
     RECT  10.188 61.385 10.854 61.493 ;
     RECT  4.5 61.085 4.518 61.799 ;
     RECT  8.208 61.627 8.298 61.799 ;
     RECT  8.208 61.799 8.226 61.805 ;
     RECT  5.976 61.349 7.11 61.867 ;
     RECT  5.976 61.867 7.218 61.925 ;
     RECT  0.216 61.259 2.358 62.005 ;
     RECT  3.096 61.259 3.726 62.005 ;
     RECT  10.692 61.493 10.854 62.069 ;
     RECT  5.976 61.925 6.858 62.195 ;
     RECT  10.836 62.069 10.854 62.671 ;
     RECT  0.216 62.005 4.122 62.731 ;
     RECT  5.112 62.671 5.13 62.731 ;
     RECT  0.216 62.731 5.13 62.735 ;
     RECT  10.836 62.671 11.214 62.813 ;
     RECT  8.46 62.731 8.478 62.851 ;
     RECT  6.195 62.195 6.858 63.013 ;
     RECT  6.195 63.013 7.506 63.149 ;
     RECT  8.46 62.851 8.622 63.247 ;
     RECT  8.46 63.247 9.054 63.275 ;
     RECT  8.604 63.275 9.054 63.347 ;
     RECT  10.836 62.813 11.034 63.389 ;
     RECT  9.036 63.347 9.054 63.391 ;
     RECT  9.036 63.391 9.162 63.481 ;
     RECT  9.036 63.481 9.666 63.589 ;
     RECT  9.036 63.589 10.026 63.661 ;
     RECT  0.216 62.735 4.914 63.739 ;
     RECT  0.216 63.739 5.346 63.823 ;
     RECT  9.036 63.661 10.098 63.823 ;
     RECT  10.836 63.389 10.854 63.823 ;
     RECT  6.195 63.149 6.966 63.931 ;
     RECT  9.036 63.823 10.854 64.075 ;
     RECT  6.195 63.931 7.074 64.201 ;
     RECT  8.712 64.075 10.854 64.291 ;
     RECT  8.712 64.291 11.142 64.349 ;
     RECT  6.195 64.201 7.29 64.399 ;
     RECT  6.195 64.399 7.974 64.471 ;
     RECT  8.712 64.349 9.054 64.471 ;
     RECT  0.216 63.823 5.418 64.499 ;
     RECT  6.195 64.471 9.054 64.499 ;
     RECT  10.152 64.349 11.142 64.499 ;
     RECT  10.224 64.499 11.142 64.541 ;
     RECT  6.195 64.499 8.73 64.561 ;
     RECT  10.224 64.541 10.926 64.589 ;
     RECT  10.368 64.589 10.926 64.733 ;
     RECT  0.216 64.499 5.238 64.859 ;
     RECT  6.012 64.561 8.73 64.859 ;
     RECT  3.816 64.859 5.238 64.895 ;
     RECT  6.012 64.859 8.586 65.003 ;
     RECT  10.368 64.733 10.89 65.117 ;
     RECT  3.924 64.895 5.238 65.129 ;
     RECT  6.012 65.003 8.37 65.129 ;
     RECT  7.56 65.129 8.37 65.309 ;
     RECT  6.195 65.129 6.57 65.399 ;
     RECT  7.56 65.309 7.83 65.399 ;
     RECT  3.924 65.129 5.13 65.785 ;
     RECT  0.216 64.859 2.646 65.821 ;
     RECT  3.384 65.785 5.13 65.821 ;
     RECT  10.368 65.117 10.818 65.851 ;
     RECT  10.224 65.851 10.818 66.043 ;
     RECT  0.216 65.821 5.13 66.083 ;
     RECT  6.195 65.399 6.477 66.139 ;
     RECT  7.632 65.399 7.65 66.139 ;
     RECT  9.612 66.043 10.818 66.181 ;
     RECT  2.844 66.083 5.13 66.209 ;
     RECT  6.195 66.139 7.65 66.317 ;
     RECT  2.844 66.209 5.058 66.479 ;
     RECT  9.612 66.181 10.854 66.479 ;
     RECT  2.844 66.479 4.266 66.515 ;
     RECT  5.04 66.479 5.058 66.515 ;
     RECT  9.612 66.479 9.774 66.595 ;
     RECT  10.836 66.479 10.854 66.619 ;
     RECT  9.576 66.595 9.774 66.721 ;
     RECT  6.195 66.317 7.578 66.749 ;
     RECT  6.195 66.749 7.362 66.757 ;
     RECT  2.844 66.515 4.086 66.785 ;
     RECT  6.084 66.757 7.362 66.793 ;
     RECT  8.856 66.721 9.774 66.859 ;
     RECT  10.836 66.619 11.214 66.901 ;
     RECT  5.796 66.793 7.362 66.929 ;
     RECT  0.216 66.083 2.106 66.991 ;
     RECT  8.352 66.859 9.774 67.055 ;
     RECT  8.352 67.055 9.018 67.469 ;
     RECT  6.048 66.929 7.362 67.559 ;
     RECT  3.168 66.785 3.546 67.567 ;
     RECT  4.536 67.531 4.554 67.567 ;
     RECT  9 67.469 9.018 67.595 ;
     RECT  10.836 66.901 11.25 67.613 ;
     RECT  3.168 67.567 4.554 67.631 ;
     RECT  3.42 67.631 4.554 67.711 ;
     RECT  9.756 67.055 9.774 67.711 ;
     RECT  7.488 67.603 7.83 67.739 ;
     RECT  0.216 66.991 2.322 67.837 ;
     RECT  9.756 67.711 9.882 67.963 ;
     RECT  10.656 67.771 10.674 67.963 ;
     RECT  3.42 67.711 4.986 67.981 ;
     RECT  6.048 67.559 6.534 67.981 ;
     RECT  0.216 67.837 2.538 68.009 ;
     RECT  7.488 67.739 7.506 68.099 ;
     RECT  9.756 67.963 10.674 68.143 ;
     RECT  9.108 68.143 10.674 68.341 ;
     RECT  9.108 68.341 10.854 68.369 ;
     RECT  9.576 68.369 10.854 68.405 ;
     RECT  10.26 68.405 10.854 68.573 ;
     RECT  0.216 68.009 2.466 68.675 ;
     RECT  3.42 67.981 6.534 68.675 ;
     RECT  0.684 68.675 2.466 68.755 ;
     RECT  3.42 68.675 4.59 68.755 ;
     RECT  8.496 68.917 8.514 68.957 ;
     RECT  10.404 68.573 10.854 69.115 ;
     RECT  0.684 68.755 4.59 69.215 ;
     RECT  9.54 69.295 9.558 69.331 ;
     RECT  10.404 69.115 10.926 69.331 ;
     RECT  9.54 69.331 10.926 69.341 ;
     RECT  0.684 69.215 2.898 69.457 ;
     RECT  9.684 69.341 10.926 69.533 ;
     RECT  7.344 69.061 7.362 69.601 ;
     RECT  5.472 68.675 6.534 69.691 ;
     RECT  7.344 69.601 7.65 69.691 ;
     RECT  11.088 69.691 11.106 69.725 ;
     RECT  3.78 69.215 4.59 69.799 ;
     RECT  5.472 69.691 7.65 69.799 ;
     RECT  3.78 69.799 7.65 69.827 ;
     RECT  9.684 69.533 10.242 69.863 ;
     RECT  3.78 69.827 6.858 69.899 ;
     RECT  0.216 69.457 2.898 70.069 ;
     RECT  3.78 69.899 6.75 70.069 ;
     RECT  10.224 69.863 10.242 70.267 ;
     RECT  7.92 70.411 7.938 70.529 ;
     RECT  10.224 70.267 10.854 70.645 ;
     RECT  8.784 70.645 8.802 70.681 ;
     RECT  0.216 70.069 6.75 70.685 ;
     RECT  10.224 70.645 11.214 70.685 ;
     RECT  4.428 70.685 6.75 70.747 ;
     RECT  10.224 70.685 10.854 70.771 ;
     RECT  8.676 70.681 8.946 70.799 ;
     RECT  4.428 70.747 7.218 70.835 ;
     RECT  8.928 70.799 8.946 70.871 ;
     RECT  9.828 70.771 10.854 70.943 ;
     RECT  10.008 70.943 10.854 71.069 ;
     RECT  0.216 70.685 3.654 71.105 ;
     RECT  0.216 71.105 2.43 71.261 ;
     RECT  3.456 71.105 3.654 71.611 ;
     RECT  4.428 70.835 6.822 71.611 ;
     RECT  10.008 71.069 10.026 71.761 ;
     RECT  10.836 71.069 10.854 71.761 ;
     RECT  10.836 71.761 11.106 71.837 ;
     RECT  9.612 71.761 10.026 71.879 ;
     RECT  0.216 71.261 2.358 71.995 ;
     RECT  3.456 71.611 6.822 71.995 ;
     RECT  0.216 71.995 6.822 72.149 ;
     RECT  9.144 71.995 9.162 72.283 ;
     RECT  8.748 72.283 9.162 72.391 ;
     RECT  8.496 72.391 9.162 72.491 ;
     RECT  10.368 72.121 10.386 72.571 ;
     RECT  0.216 72.149 6.57 72.689 ;
     RECT  7.344 72.301 7.434 72.689 ;
     RECT  10.368 72.571 10.746 72.763 ;
     RECT  7.416 72.689 7.434 72.769 ;
     RECT  9.144 72.491 9.162 72.805 ;
     RECT  10.368 72.763 11.214 72.805 ;
     RECT  7.416 72.769 7.65 72.869 ;
     RECT  7.632 72.869 7.65 72.959 ;
     RECT  9.144 72.805 11.214 72.959 ;
     RECT  9.144 72.959 10.998 72.995 ;
     RECT  9.144 72.995 10.926 73.181 ;
     RECT  0.216 72.689 6.477 73.229 ;
     RECT  5.148 73.229 6.477 73.373 ;
     RECT  9.144 73.181 9.594 73.409 ;
     RECT  10.728 73.181 10.926 73.565 ;
     RECT  9 73.651 9.018 73.841 ;
     RECT  5.256 73.373 6.477 73.921 ;
     RECT  7.272 73.771 7.29 73.921 ;
     RECT  10.728 73.565 10.854 73.949 ;
     RECT  5.256 73.921 7.434 74.047 ;
     RECT  8.46 74.047 8.622 74.093 ;
     RECT  5.256 74.047 7.47 74.183 ;
     RECT  5.328 74.183 7.47 74.219 ;
     RECT  5.4 74.219 7.47 74.345 ;
     RECT  8.604 74.093 8.622 74.417 ;
     RECT  0.216 73.229 3.87 74.461 ;
     RECT  5.4 74.345 6.894 74.579 ;
     RECT  10.044 74.011 10.242 74.759 ;
     RECT  8.676 74.731 9.09 74.779 ;
     RECT  8.676 74.779 9.666 74.921 ;
     RECT  0.216 74.461 4.338 74.965 ;
     RECT  5.4 74.579 6.477 74.965 ;
     RECT  10.692 75.001 10.71 75.067 ;
     RECT  10.692 75.067 10.926 75.259 ;
     RECT  9.648 74.921 9.666 75.389 ;
     RECT  0.216 74.965 6.477 75.425 ;
     RECT  0.468 75.425 6.477 75.505 ;
     RECT  10.692 75.259 11.214 75.541 ;
     RECT  8.676 74.921 8.838 75.569 ;
     RECT  7.92 75.541 7.938 75.631 ;
     RECT  7.92 75.631 8.658 75.659 ;
     RECT  7.992 75.659 8.658 75.677 ;
     RECT  10.692 75.541 11.25 75.677 ;
     RECT  8.136 75.677 8.658 75.929 ;
     RECT  10.692 75.677 11.214 76.081 ;
     RECT  10.548 76.081 11.214 76.199 ;
     RECT  10.548 76.199 10.854 76.235 ;
     RECT  0.468 75.505 6.822 76.315 ;
     RECT  0.468 76.315 7.182 76.411 ;
     RECT  8.352 75.929 8.658 76.411 ;
     RECT  10.8 76.235 10.854 76.445 ;
     RECT  8.352 76.411 9.09 76.469 ;
     RECT  0.468 76.411 7.29 76.477 ;
     RECT  0.216 76.477 7.29 76.505 ;
     RECT  9.144 76.603 9.162 76.621 ;
     RECT  9.144 76.621 9.234 76.649 ;
     RECT  0.216 76.505 6.714 76.739 ;
     RECT  9.216 76.649 9.234 76.739 ;
     RECT  0.216 76.739 5.238 76.775 ;
     RECT  8.028 76.711 8.046 76.883 ;
     RECT  6.084 76.739 6.714 76.919 ;
     RECT  6.156 76.919 6.714 77.009 ;
     RECT  9.648 76.981 9.666 77.021 ;
     RECT  0.216 76.775 5.166 77.045 ;
     RECT  6.195 77.009 6.534 77.045 ;
     RECT  4.428 77.045 5.166 77.279 ;
     RECT  10.836 76.445 10.854 77.371 ;
     RECT  10.836 77.371 10.926 77.459 ;
     RECT  6.195 77.045 6.477 77.899 ;
     RECT  4.428 77.279 5.13 77.971 ;
     RECT  0.216 77.045 3.438 78.061 ;
     RECT  4.356 77.971 5.13 78.061 ;
     RECT  0.216 78.061 5.13 78.089 ;
     RECT  5.112 78.089 5.13 78.241 ;
     RECT  6.048 77.899 6.477 78.241 ;
     RECT  7.344 78.169 7.362 78.241 ;
     RECT  5.112 78.241 5.274 78.269 ;
     RECT  10.836 77.459 10.854 78.331 ;
     RECT  10.332 78.331 10.854 78.365 ;
     RECT  0.216 78.089 4.374 78.395 ;
     RECT  9.108 78.241 9.126 78.395 ;
     RECT  6.048 78.241 7.362 78.475 ;
     RECT  6.048 78.475 7.506 78.511 ;
     RECT  6.048 78.511 7.65 78.523 ;
     RECT  10.548 78.365 10.854 78.557 ;
     RECT  5.256 78.269 5.274 78.601 ;
     RECT  6.048 78.523 8.262 78.601 ;
     RECT  5.256 78.601 8.262 78.629 ;
     RECT  10.836 78.557 10.854 78.637 ;
     RECT  5.256 78.629 8.118 78.701 ;
     RECT  5.256 78.701 7.11 78.899 ;
     RECT  5.256 78.899 7.074 79.051 ;
     RECT  9.252 78.667 9.27 79.051 ;
     RECT  10.836 78.637 11.214 79.133 ;
     RECT  0.216 78.395 4.302 79.177 ;
     RECT  5.112 79.051 7.074 79.177 ;
     RECT  9.252 79.051 9.45 79.213 ;
     RECT  9.252 79.213 9.81 79.321 ;
     RECT  9.108 79.321 9.81 79.325 ;
     RECT  0.216 79.177 7.074 79.349 ;
     RECT  0.216 79.349 3.942 79.439 ;
     RECT  9.108 79.325 9.27 79.439 ;
     RECT  8.1 78.701 8.118 79.447 ;
     RECT  9.108 79.439 9.126 79.447 ;
     RECT  10.836 79.133 11.034 79.483 ;
     RECT  8.1 79.447 9.126 79.547 ;
     RECT  8.1 79.547 8.658 79.583 ;
     RECT  10.764 79.483 11.034 79.709 ;
     RECT  10.764 79.709 10.926 79.717 ;
     RECT  8.136 79.583 8.658 79.757 ;
     RECT  0.216 79.439 3.726 79.805 ;
     RECT  8.244 79.757 8.658 79.979 ;
     RECT  10.224 79.717 10.926 79.979 ;
     RECT  0.216 79.805 3.222 80.015 ;
     RECT  4.68 79.349 7.074 80.095 ;
     RECT  8.244 79.979 8.262 80.123 ;
     RECT  4.68 80.095 7.218 80.249 ;
     RECT  4.68 80.249 7.002 80.257 ;
     RECT  4.536 80.257 7.002 80.285 ;
     RECT  4.536 80.285 6.858 80.393 ;
     RECT  5.832 80.393 6.858 80.519 ;
     RECT  0.216 80.015 3.006 80.555 ;
     RECT  6.195 80.519 6.858 80.627 ;
     RECT  0.252 80.555 3.006 80.669 ;
     RECT  9.072 80.671 9.09 80.761 ;
     RECT  10.584 79.979 10.854 80.827 ;
     RECT  10.332 80.827 10.854 80.861 ;
     RECT  0.684 80.669 3.006 80.869 ;
     RECT  8.532 80.761 9.09 80.905 ;
     RECT  0.684 80.869 3.618 80.923 ;
     RECT  4.536 80.393 4.842 80.923 ;
     RECT  8.136 80.905 9.09 80.957 ;
     RECT  10.836 80.861 10.854 81.019 ;
     RECT  10.836 81.019 10.998 81.059 ;
     RECT  8.28 80.957 9.09 81.139 ;
     RECT  8.28 81.139 9.378 81.175 ;
     RECT  0.684 80.923 4.842 81.211 ;
     RECT  8.28 81.175 9.486 81.211 ;
     RECT  8.28 81.211 9.666 81.239 ;
     RECT  8.604 81.239 9.666 81.329 ;
     RECT  8.604 81.329 9.378 81.401 ;
     RECT  0.684 81.211 5.166 81.403 ;
     RECT  6.195 80.627 6.477 81.451 ;
     RECT  0.288 81.403 5.166 81.473 ;
     RECT  6.195 81.451 7.146 81.509 ;
     RECT  0.288 81.473 4.374 81.595 ;
     RECT  8.604 81.401 8.838 81.635 ;
     RECT  5.148 81.473 5.166 81.905 ;
     RECT  0.216 81.595 4.374 82.139 ;
     RECT  0.216 82.139 3.726 82.175 ;
     RECT  6.195 81.509 7.002 82.363 ;
     RECT  10.836 81.059 10.89 82.363 ;
     RECT  10.584 82.363 10.89 82.409 ;
     RECT  6.195 82.363 7.038 82.561 ;
     RECT  10.836 82.409 10.89 82.781 ;
     RECT  4.896 82.651 4.914 82.831 ;
     RECT  6.195 82.561 7.182 82.957 ;
     RECT  6.084 82.957 7.182 83.129 ;
     RECT  10.836 82.781 10.854 83.131 ;
     RECT  10.656 83.131 10.854 83.191 ;
     RECT  10.44 83.191 10.854 83.291 ;
     RECT  0.216 82.175 3.654 83.371 ;
     RECT  4.896 82.831 5.166 83.371 ;
     RECT  7.308 83.335 7.506 83.371 ;
     RECT  8.424 83.371 8.442 83.461 ;
     RECT  8.424 83.461 8.658 83.489 ;
     RECT  7.308 83.371 7.65 83.525 ;
     RECT  9.648 83.515 9.666 83.561 ;
     RECT  8.64 83.489 8.658 83.641 ;
     RECT  6.084 83.129 6.534 83.707 ;
     RECT  8.64 83.641 8.838 83.731 ;
     RECT  10.656 83.291 10.854 83.731 ;
     RECT  0.216 83.371 5.166 83.741 ;
     RECT  0.576 83.741 5.166 83.755 ;
     RECT  5.94 83.707 6.534 83.755 ;
     RECT  10.656 83.731 10.926 83.767 ;
     RECT  0.576 83.755 6.534 83.795 ;
     RECT  7.452 83.525 7.65 83.885 ;
     RECT  6.195 83.795 6.534 83.911 ;
     RECT  8.64 83.731 8.91 83.911 ;
     RECT  0.576 83.795 5.058 84.029 ;
     RECT  8.64 83.911 8.982 84.029 ;
     RECT  0.576 84.029 4.158 84.065 ;
     RECT  8.784 84.029 8.982 84.137 ;
     RECT  7.524 83.885 7.65 84.307 ;
     RECT  0.576 84.065 4.014 84.335 ;
     RECT  6.195 83.911 6.678 84.343 ;
     RECT  10.656 83.767 11.214 84.343 ;
     RECT  7.524 84.307 8.046 84.365 ;
     RECT  6.195 84.343 6.786 84.443 ;
     RECT  0.576 84.335 3.87 84.475 ;
     RECT  10.656 84.343 11.25 84.509 ;
     RECT  7.524 84.365 7.902 84.605 ;
     RECT  8.784 84.137 8.802 84.605 ;
     RECT  5.04 84.029 5.058 84.685 ;
     RECT  6.195 84.443 6.477 84.721 ;
     RECT  7.524 84.605 7.542 84.721 ;
     RECT  10.656 84.509 11.214 84.811 ;
     RECT  5.04 84.685 5.238 84.883 ;
     RECT  10.584 84.811 11.214 84.893 ;
     RECT  5.04 84.883 5.274 84.991 ;
     RECT  6.156 84.721 6.477 84.991 ;
     RECT  5.04 84.991 6.477 85.081 ;
     RECT  10.836 84.893 11.214 85.109 ;
     RECT  4.896 85.081 6.477 85.153 ;
     RECT  0.216 84.475 3.87 85.189 ;
     RECT  4.752 85.153 6.477 85.189 ;
     RECT  9.216 85.225 9.234 85.261 ;
     RECT  9.216 85.261 9.378 85.277 ;
     RECT  7.416 84.721 7.542 85.379 ;
     RECT  9.36 85.277 9.378 85.379 ;
     RECT  7.596 85.387 7.614 85.531 ;
     RECT  7.596 85.531 7.794 85.657 ;
     RECT  0.216 85.189 6.477 85.661 ;
     RECT  0.216 85.661 4.914 85.685 ;
     RECT  5.652 85.661 6.477 85.685 ;
     RECT  7.596 85.657 7.866 85.685 ;
     RECT  7.848 85.685 7.866 86.059 ;
     RECT  10.836 85.109 10.854 86.395 ;
     RECT  7.848 86.059 7.902 86.431 ;
     RECT  10.368 86.395 10.854 86.459 ;
     RECT  7.812 86.431 8.442 86.531 ;
     RECT  6.195 85.685 6.477 86.611 ;
     RECT  7.812 86.531 8.046 86.611 ;
     RECT  6.195 86.611 6.57 86.845 ;
     RECT  0.216 85.685 4.734 86.881 ;
     RECT  6.195 86.845 6.786 86.881 ;
     RECT  0.216 86.881 6.786 86.999 ;
     RECT  10.584 86.459 10.854 87.005 ;
     RECT  7.596 86.611 8.046 87.007 ;
     RECT  0.216 86.999 6.57 87.035 ;
     RECT  8.928 86.971 9.126 87.149 ;
     RECT  10.836 87.005 10.854 87.151 ;
     RECT  10.836 87.151 11.034 87.197 ;
     RECT  7.416 87.007 8.046 87.421 ;
     RECT  4.032 87.035 6.57 87.539 ;
     RECT  7.416 87.421 8.262 87.539 ;
     RECT  9.108 87.149 9.126 87.691 ;
     RECT  4.032 87.539 4.266 87.719 ;
     RECT  7.488 87.539 8.262 87.719 ;
     RECT  5.148 87.539 6.57 87.809 ;
     RECT  5.148 87.809 6.477 87.845 ;
     RECT  0.216 87.035 3.186 87.925 ;
     RECT  9.108 87.691 9.162 88.051 ;
     RECT  10.836 87.197 10.89 88.051 ;
     RECT  0.216 87.925 3.978 88.079 ;
     RECT  8.316 88.051 9.162 88.195 ;
     RECT  8.316 88.195 9.27 88.315 ;
     RECT  8.316 88.315 9.414 88.349 ;
     RECT  10.836 88.051 10.926 88.541 ;
     RECT  4.536 88.627 4.554 88.735 ;
     RECT  5.328 87.845 6.477 88.735 ;
     RECT  4.536 88.735 6.477 88.771 ;
     RECT  7.488 87.719 7.506 88.771 ;
     RECT  0.216 88.079 3.69 88.889 ;
     RECT  4.536 88.771 7.506 88.891 ;
     RECT  8.316 88.349 8.694 88.891 ;
     RECT  4.536 88.891 8.694 88.897 ;
     RECT  4.176 88.897 8.694 88.925 ;
     RECT  5.76 88.925 6.858 88.973 ;
     RECT  7.992 88.925 8.694 88.997 ;
     RECT  7.992 88.997 8.01 89.069 ;
     RECT  4.176 88.925 4.986 89.159 ;
     RECT  5.904 88.973 6.858 89.159 ;
     RECT  4.176 89.159 4.842 89.195 ;
     RECT  10.836 88.541 10.89 89.275 ;
     RECT  10.8 89.275 10.89 89.401 ;
     RECT  4.176 89.195 4.626 89.429 ;
     RECT  8.784 89.401 8.802 89.453 ;
     RECT  10.8 89.401 10.926 89.581 ;
     RECT  10.44 89.581 10.926 89.699 ;
     RECT  0.216 88.889 3.438 89.815 ;
     RECT  4.176 89.429 4.518 89.815 ;
     RECT  6.195 89.159 6.858 89.941 ;
     RECT  7.776 89.851 7.794 89.969 ;
     RECT  9.144 89.581 9.234 89.969 ;
     RECT  10.728 89.699 10.926 89.969 ;
     RECT  8.028 89.977 8.046 90.029 ;
     RECT  5.508 89.941 6.858 90.041 ;
     RECT  9.648 90.211 9.666 90.269 ;
     RECT  0.216 89.815 4.518 90.283 ;
     RECT  6.195 90.041 6.858 90.283 ;
     RECT  8.136 90.121 8.19 90.383 ;
     RECT  6.195 90.283 6.93 90.419 ;
     RECT  0.216 90.283 4.626 90.481 ;
     RECT  8.172 90.383 8.19 90.571 ;
     RECT  0.216 90.481 5.13 90.617 ;
     RECT  0.216 90.617 4.698 90.653 ;
     RECT  10.836 89.969 10.926 90.653 ;
     RECT  8.172 90.571 8.406 90.661 ;
     RECT  0.216 90.653 3.69 90.689 ;
     RECT  4.536 90.653 4.698 90.779 ;
     RECT  8.172 90.661 8.586 91.049 ;
     RECT  6.195 90.419 6.477 91.201 ;
     RECT  9.18 91.243 9.198 91.291 ;
     RECT  9.18 91.291 9.342 91.319 ;
     RECT  6.195 91.201 6.786 91.327 ;
     RECT  10.836 90.653 10.854 91.387 ;
     RECT  10.692 91.387 10.854 91.471 ;
     RECT  10.692 91.471 11.214 91.499 ;
     RECT  6.195 91.327 6.858 91.561 ;
     RECT  0.216 90.689 3.474 91.589 ;
     RECT  9.324 91.319 9.342 91.589 ;
     RECT  4.608 90.779 4.698 91.597 ;
     RECT  5.508 91.561 6.858 91.597 ;
     RECT  10.836 91.499 11.214 91.613 ;
     RECT  0.216 91.589 3.294 91.625 ;
     RECT  4.608 91.597 6.858 91.625 ;
     RECT  4.788 91.625 6.858 91.661 ;
     RECT  4.788 91.661 5.346 91.859 ;
     RECT  8.028 91.195 8.046 92.011 ;
     RECT  6.192 91.661 6.858 92.101 ;
     RECT  7.992 92.011 8.154 92.101 ;
     RECT  6.192 92.101 8.154 92.129 ;
     RECT  10.836 91.613 10.89 92.347 ;
     RECT  4.788 91.859 5.058 92.635 ;
     RECT  6.195 92.129 8.154 92.669 ;
     RECT  10.836 92.347 10.926 92.669 ;
     RECT  9 92.551 9.018 92.677 ;
     RECT  9.864 92.641 9.882 92.677 ;
     RECT  9 92.677 9.882 92.705 ;
     RECT  9.144 92.705 9.882 92.765 ;
     RECT  9.144 92.765 9.63 92.777 ;
     RECT  3.924 92.635 3.942 92.785 ;
     RECT  4.788 92.635 5.238 92.785 ;
     RECT  3.924 92.785 5.238 92.821 ;
     RECT  7.524 92.669 8.154 92.923 ;
     RECT  9.144 92.777 9.378 92.939 ;
     RECT  9.216 92.939 9.378 92.975 ;
     RECT  0.216 91.625 3.186 92.983 ;
     RECT  3.924 92.821 5.382 92.983 ;
     RECT  0.216 92.983 5.382 93.091 ;
     RECT  6.195 92.669 6.606 93.091 ;
     RECT  10.836 92.669 10.854 93.091 ;
     RECT  10.656 93.091 10.854 93.149 ;
     RECT  9.36 92.975 9.378 93.209 ;
     RECT  7.524 92.923 8.226 93.281 ;
     RECT  10.8 93.149 10.854 93.389 ;
     RECT  0.216 93.091 6.606 93.451 ;
     RECT  7.992 93.281 8.226 93.451 ;
     RECT  10.836 93.389 10.854 93.451 ;
     RECT  0.216 93.451 7.038 93.485 ;
     RECT  0.216 93.485 6.858 93.515 ;
     RECT  10.836 93.451 11.214 93.533 ;
     RECT  4.824 93.515 6.858 93.659 ;
     RECT  5.796 93.659 6.858 94.019 ;
     RECT  7.992 93.451 8.37 94.019 ;
     RECT  10.836 93.533 10.926 94.109 ;
     RECT  8.352 94.019 8.37 94.199 ;
     RECT  0.216 93.515 4.086 94.261 ;
     RECT  4.824 93.659 5.022 94.261 ;
     RECT  6.195 94.019 6.858 94.261 ;
     RECT  0.216 94.261 5.022 94.441 ;
     RECT  10.836 94.109 10.854 94.441 ;
     RECT  6.195 94.261 7.038 94.711 ;
     RECT  10.512 94.441 10.854 94.837 ;
     RECT  0.216 94.441 5.094 94.865 ;
     RECT  9.684 94.795 9.702 94.865 ;
     RECT  10.512 94.837 11.214 94.877 ;
     RECT  10.512 94.877 10.998 94.981 ;
     RECT  6.195 94.711 7.146 95.009 ;
     RECT  9.864 94.981 10.998 95.099 ;
     RECT  3.816 94.865 5.094 95.107 ;
     RECT  6.195 95.009 6.477 95.107 ;
     RECT  9.864 95.099 10.89 95.261 ;
     RECT  9.864 95.261 9.882 95.369 ;
     RECT  7.2 95.251 7.218 95.377 ;
     RECT  3.816 95.107 6.477 95.477 ;
     RECT  7.2 95.377 7.83 95.549 ;
     RECT  0.216 94.865 3.042 95.611 ;
     RECT  3.816 95.477 4.95 95.611 ;
     RECT  10.836 95.261 10.89 95.645 ;
     RECT  5.688 95.477 6.477 95.791 ;
     RECT  7.2 95.549 7.542 95.791 ;
     RECT  0.216 95.611 4.95 95.945 ;
     RECT  5.688 95.791 7.542 95.981 ;
     RECT  9.684 96.061 9.702 96.221 ;
     RECT  4.248 95.945 4.95 96.331 ;
     RECT  5.688 95.981 6.858 96.331 ;
     RECT  10.836 95.645 10.854 96.529 ;
     RECT  10.8 96.529 10.854 96.605 ;
     RECT  9.648 96.691 9.666 96.797 ;
     RECT  0.216 95.945 3.438 97.069 ;
     RECT  4.248 96.331 6.858 97.069 ;
     RECT  0.216 97.069 6.858 97.267 ;
     RECT  0.216 97.267 6.93 97.367 ;
     RECT  0.216 97.367 6.858 97.403 ;
     RECT  10.836 96.605 10.854 97.411 ;
     RECT  10.836 97.411 10.89 97.565 ;
     RECT  0.216 97.403 6.477 97.637 ;
     RECT  9.648 97.681 9.666 97.757 ;
     RECT  0.216 97.637 5.166 97.799 ;
     RECT  6.156 97.637 6.477 97.853 ;
     RECT  8.46 98.059 8.478 98.105 ;
     RECT  10.836 97.565 10.854 98.107 ;
     RECT  0.216 97.799 4.482 98.249 ;
     RECT  10.656 98.107 10.854 98.339 ;
     RECT  7.884 98.221 8.154 98.447 ;
     RECT  6.195 97.853 6.477 98.581 ;
     RECT  10.836 98.339 10.854 98.581 ;
     RECT  7.884 98.447 7.902 98.645 ;
     RECT  9.18 98.539 9.198 98.761 ;
     RECT  10.836 98.581 11.214 98.915 ;
     RECT  9.18 98.761 9.342 98.995 ;
     RECT  4.284 98.249 4.482 99.031 ;
     RECT  5.328 98.995 5.346 99.031 ;
     RECT  6.195 98.581 6.894 99.031 ;
     RECT  9.18 98.995 9.558 99.031 ;
     RECT  9.18 99.031 9.702 99.053 ;
     RECT  0.216 98.249 3.474 99.163 ;
     RECT  4.284 99.031 6.894 99.163 ;
     RECT  9.324 99.053 9.702 99.221 ;
     RECT  0.216 99.163 6.894 99.229 ;
     RECT  0.216 99.229 7.434 99.293 ;
     RECT  8.388 99.301 8.406 99.419 ;
     RECT  0.216 99.293 7.218 99.527 ;
     RECT  9.684 99.221 9.702 99.527 ;
     RECT  10.836 98.915 10.854 99.643 ;
     RECT  10.836 99.643 11.214 99.689 ;
     RECT  5.4 99.527 7.218 99.725 ;
     RECT  8.424 99.571 8.514 99.761 ;
     RECT  7.2 99.725 7.218 99.959 ;
     RECT  0.216 99.527 4.482 100.103 ;
     RECT  10.836 99.689 10.854 100.219 ;
     RECT  5.4 99.725 6.477 100.229 ;
     RECT  7.416 100.111 7.578 100.229 ;
     RECT  10.764 100.219 10.854 100.273 ;
     RECT  7.416 100.229 7.434 100.301 ;
     RECT  9.036 100.111 9.054 100.315 ;
     RECT  4.14 100.103 4.482 100.345 ;
     RECT  9.036 100.315 9.558 100.499 ;
     RECT  9.54 100.499 9.558 100.507 ;
     RECT  0.216 100.103 3.294 100.535 ;
     RECT  10.728 100.273 10.854 100.603 ;
     RECT  9.54 100.507 9.594 100.651 ;
     RECT  10.728 100.603 10.926 100.651 ;
     RECT  9.54 100.651 10.926 100.679 ;
     RECT  9.54 100.679 10.854 100.769 ;
     RECT  4.14 100.345 4.878 100.805 ;
     RECT  10.548 100.769 10.854 100.829 ;
     RECT  8.712 100.843 8.73 100.877 ;
     RECT  9.54 100.769 9.63 100.877 ;
     RECT  10.548 100.829 10.566 101.021 ;
     RECT  7.236 100.921 7.254 101.039 ;
     RECT  5.616 100.229 6.477 101.047 ;
     RECT  0.216 100.535 3.15 101.219 ;
     RECT  5.184 101.047 6.477 101.309 ;
     RECT  5.76 101.309 6.477 101.323 ;
     RECT  0.216 101.219 2.322 101.417 ;
     RECT  3.06 101.219 3.15 101.419 ;
     RECT  3.888 101.191 3.978 101.419 ;
     RECT  9.612 100.877 9.63 101.551 ;
     RECT  8.64 101.587 8.658 101.623 ;
     RECT  8.388 101.623 8.658 101.695 ;
     RECT  8.244 101.695 8.658 101.731 ;
     RECT  9.612 101.551 10.35 101.731 ;
     RECT  8.244 101.731 10.35 101.741 ;
     RECT  8.388 101.741 10.35 101.755 ;
     RECT  8.388 101.755 10.674 101.759 ;
     RECT  8.388 101.759 8.406 101.849 ;
     RECT  9.18 101.759 10.674 101.849 ;
     RECT  5.76 101.323 6.678 101.965 ;
     RECT  3.06 101.419 3.978 102.001 ;
     RECT  5.76 101.965 6.93 102.001 ;
     RECT  4.968 101.731 4.986 102.043 ;
     RECT  5.76 102.001 6.966 102.043 ;
     RECT  3.06 102.001 4.086 102.091 ;
     RECT  4.968 102.043 6.966 102.091 ;
     RECT  3.06 102.091 6.966 102.119 ;
     RECT  4.428 102.119 5.274 102.155 ;
     RECT  9.828 101.849 10.674 102.173 ;
     RECT  9.828 102.173 9.846 102.227 ;
     RECT  0.216 101.417 2.214 102.235 ;
     RECT  0.216 102.235 2.25 102.271 ;
     RECT  3.06 102.119 3.69 102.271 ;
     RECT  6.195 102.119 6.966 102.361 ;
     RECT  6.195 102.361 7.146 102.413 ;
     RECT  6.195 102.413 6.966 102.425 ;
     RECT  10.836 102.199 10.854 102.523 ;
     RECT  10.836 102.523 10.926 102.569 ;
     RECT  10.836 102.569 10.854 102.749 ;
     RECT  0.216 102.271 3.69 103.081 ;
     RECT  4.428 102.155 5.022 103.081 ;
     RECT  0.216 103.081 5.022 103.109 ;
     RECT  9.684 103.081 9.702 103.133 ;
     RECT  6.195 102.425 6.642 103.195 ;
     RECT  0.216 103.109 4.914 103.199 ;
     RECT  8.712 103.351 8.73 103.441 ;
     RECT  0.216 103.199 2.934 103.505 ;
     RECT  3.672 103.199 4.878 103.541 ;
     RECT  10.8 102.901 10.818 103.621 ;
     RECT  8.712 103.441 9.126 103.649 ;
     RECT  10.224 103.621 10.818 103.675 ;
     RECT  9 103.649 9.126 103.739 ;
     RECT  10.224 103.675 11.214 103.739 ;
     RECT  9.072 103.739 9.126 103.757 ;
     RECT  10.224 103.739 10.854 103.775 ;
     RECT  6.195 103.195 7.038 103.891 ;
     RECT  10.476 103.775 10.854 103.901 ;
     RECT  9.216 103.891 9.234 103.981 ;
     RECT  9.216 103.981 9.666 104.081 ;
     RECT  9.504 104.081 9.666 104.093 ;
     RECT  6.195 103.891 7.182 104.161 ;
     RECT  6.195 104.161 7.254 104.189 ;
     RECT  0.576 103.505 2.934 104.251 ;
     RECT  7.236 104.189 7.254 104.279 ;
     RECT  10.656 103.901 10.854 104.285 ;
     RECT  3.924 103.541 4.878 104.287 ;
     RECT  8.136 103.723 8.154 104.315 ;
     RECT  0.576 104.251 3.078 104.443 ;
     RECT  10.656 104.285 10.674 104.477 ;
     RECT  0.216 104.443 3.078 104.585 ;
     RECT  6.195 104.189 6.477 104.629 ;
     RECT  3.852 104.287 5.202 104.657 ;
     RECT  8.28 104.431 8.298 104.657 ;
     RECT  4.32 104.657 5.202 104.665 ;
     RECT  6.156 104.629 6.477 104.665 ;
     RECT  4.32 104.665 6.477 104.729 ;
     RECT  9.504 104.093 9.522 104.729 ;
     RECT  4.392 104.729 6.477 104.855 ;
     RECT  4.824 104.855 6.477 104.891 ;
     RECT  6.195 104.891 6.477 105.047 ;
     RECT  4.824 104.891 5.31 105.089 ;
     RECT  0.576 104.585 2.862 105.125 ;
     RECT  5.148 105.089 5.166 105.125 ;
     RECT  0.795 105.125 2.142 105.161 ;
     RECT  2.124 105.161 2.142 105.269 ;
     RECT  0.795 105.161 0.885 105.317 ;
     RECT  6.195 105.047 6.285 105.317 ;
    LAYER M4 ;
     RECT  0.156 0.384 0.245 104.664 ;
     RECT  0.245 0.528 0.788 104.664 ;
     RECT  0.788 0.528 0.892 105.312 ;
     RECT  0.892 0.576 1.084 105.042 ;
     RECT  1.084 31.104 1.109 31.944 ;
     RECT  1.084 55.248 1.145 56.088 ;
     RECT  1.084 0.576 1.181 10.92 ;
     RECT  1.109 31.488 1.181 31.944 ;
     RECT  1.084 57.84 1.181 60.6 ;
     RECT  1.084 12.384 1.235 14.616 ;
     RECT  1.181 57.84 1.235 60.408 ;
     RECT  1.084 77.04 1.235 83.4 ;
     RECT  1.084 84.48 1.235 92.808 ;
     RECT  1.235 12.384 1.253 14.424 ;
     RECT  1.084 15.984 1.253 23.88 ;
     RECT  1.084 37.2 1.253 44.472 ;
     RECT  1.084 64.128 1.253 66.84 ;
     RECT  1.253 64.128 1.289 65.016 ;
     RECT  1.084 68.352 1.289 72.504 ;
     RECT  1.253 66.048 1.361 66.84 ;
     RECT  1.235 88.368 1.397 92.808 ;
     RECT  1.084 32.928 1.469 34.824 ;
     RECT  1.084 45.504 1.505 49.656 ;
     RECT  1.397 88.368 1.523 90.6 ;
     RECT  1.084 51.264 1.577 53.64 ;
     RECT  1.235 84.48 1.619 86.376 ;
     RECT  1.289 69.792 1.649 72.504 ;
     RECT  1.505 47.904 1.667 49.656 ;
     RECT  1.577 51.264 1.667 53.4 ;
     RECT  1.084 97.68 1.667 102.36 ;
     RECT  1.361 66.528 1.685 66.84 ;
     RECT  1.253 37.536 1.715 44.472 ;
     RECT  1.667 47.904 1.715 48.744 ;
     RECT  1.289 68.352 1.715 68.376 ;
     RECT  1.235 78 1.715 83.4 ;
     RECT  1.715 38.016 1.721 44.472 ;
     RECT  1.235 58.128 1.721 60.408 ;
     RECT  1.715 78 1.721 78.024 ;
     RECT  1.084 94.032 1.721 96.552 ;
     RECT  1.181 4.8 1.757 10.92 ;
     RECT  1.084 63.12 1.757 63.144 ;
     RECT  1.649 70.08 1.757 72.504 ;
     RECT  1.667 101.424 1.757 102.36 ;
     RECT  1.469 32.928 1.763 33.72 ;
     RECT  1.721 38.016 1.793 40.344 ;
     RECT  1.685 66.528 1.793 66.552 ;
     RECT  1.084 62.016 1.829 62.04 ;
     RECT  1.289 64.848 1.829 65.016 ;
     RECT  1.084 103.728 1.829 104.952 ;
     RECT  1.181 0.576 1.865 3.528 ;
     RECT  1.763 32.928 1.901 32.952 ;
     RECT  1.667 51.792 1.901 53.4 ;
     RECT  1.721 60.384 1.901 60.408 ;
     RECT  1.253 16.032 1.907 23.88 ;
     RECT  1.084 26.112 1.973 26.136 ;
     RECT  1.757 101.52 1.973 102.36 ;
     RECT  1.145 55.248 2.009 55.272 ;
     RECT  1.715 79.008 2.009 83.208 ;
     RECT  1.084 27.456 2.077 29.688 ;
     RECT  1.181 31.536 2.077 31.944 ;
     RECT  2.077 31.536 2.099 32.472 ;
     RECT  1.757 10.8 2.101 10.92 ;
     RECT  1.253 12.384 2.101 14.232 ;
     RECT  1.715 48.24 2.117 48.744 ;
     RECT  1.721 41.568 2.153 44.472 ;
     RECT  2.117 48.72 2.153 48.744 ;
     RECT  1.667 97.68 2.153 99.192 ;
     RECT  2.149 62.688 2.195 62.712 ;
     RECT  1.907 19.872 2.221 23.88 ;
     RECT  1.084 25.056 2.221 25.08 ;
     RECT  1.084 35.904 2.221 35.928 ;
     RECT  1.505 45.504 2.225 46.248 ;
     RECT  1.757 70.8 2.225 72.504 ;
     RECT  2.009 80.928 2.243 83.208 ;
     RECT  1.907 16.032 2.245 18.744 ;
     RECT  1.619 84.48 2.261 85.512 ;
     RECT  1.901 53.04 2.291 53.4 ;
     RECT  2.225 70.8 2.291 71.256 ;
     RECT  1.973 101.52 2.291 101.544 ;
     RECT  2.101 10.8 2.293 14.232 ;
     RECT  2.245 15.648 2.293 18.744 ;
     RECT  2.077 26.736 2.293 29.688 ;
     RECT  1.523 88.368 2.293 90.072 ;
     RECT  1.397 91.584 2.293 92.808 ;
     RECT  1.829 64.848 2.297 64.872 ;
     RECT  1.084 74.112 2.297 74.952 ;
     RECT  1.865 1.152 2.329 3.528 ;
     RECT  1.757 4.8 2.329 9.768 ;
     RECT  2.221 35.904 2.333 35.976 ;
     RECT  2.153 42.144 2.333 44.472 ;
     RECT  2.297 74.112 2.333 74.712 ;
     RECT  2.261 84.48 2.333 85.08 ;
     RECT  2.293 91.584 2.333 92.952 ;
     RECT  2.221 19.872 2.339 25.08 ;
     RECT  2.293 76.656 2.339 76.68 ;
     RECT  1.721 58.128 2.365 59.304 ;
     RECT  2.339 23.328 2.369 25.08 ;
     RECT  2.365 57.264 2.435 59.304 ;
     RECT  2.009 79.008 2.435 79.848 ;
     RECT  2.333 92.928 2.437 92.952 ;
     RECT  1.721 94.032 2.437 96.408 ;
     RECT  2.369 23.328 2.441 24.552 ;
     RECT  1.793 38.256 2.441 40.344 ;
     RECT  2.291 71.232 2.441 71.256 ;
     RECT  2.333 74.688 2.441 74.712 ;
     RECT  2.293 102.624 2.441 102.648 ;
     RECT  1.829 103.776 2.441 104.952 ;
     RECT  2.333 43.344 2.473 44.472 ;
     RECT  2.153 98.016 2.477 99.192 ;
     RECT  2.441 103.776 2.477 104.28 ;
     RECT  2.293 87.792 2.509 90.072 ;
     RECT  2.333 91.584 2.509 91.944 ;
     RECT  2.473 43.344 2.531 45.336 ;
     RECT  2.437 92.928 2.531 96.408 ;
     RECT  2.531 43.344 2.549 44.616 ;
     RECT  2.509 55.68 2.579 55.704 ;
     RECT  2.441 23.328 2.585 23.4 ;
     RECT  2.477 98.016 2.585 98.088 ;
     RECT  2.293 26.736 2.657 29.736 ;
     RECT  2.441 39.168 2.657 40.344 ;
     RECT  2.333 42.144 2.657 42.168 ;
     RECT  2.531 92.928 2.657 95.736 ;
     RECT  2.617 49.728 2.675 49.752 ;
     RECT  2.509 76.992 2.693 77.016 ;
     RECT  2.293 86.64 2.725 86.664 ;
     RECT  2.435 58.128 2.761 59.304 ;
     RECT  2.339 21.12 2.765 22.344 ;
     RECT  2.585 23.328 2.765 23.352 ;
     RECT  2.765 21.12 2.801 21.384 ;
     RECT  2.657 27.792 2.801 29.736 ;
     RECT  2.333 35.952 2.801 35.976 ;
     RECT  2.725 46.8 2.801 46.824 ;
     RECT  2.761 58.128 2.801 59.832 ;
     RECT  2.725 86.592 2.801 86.664 ;
     RECT  2.509 87.792 2.801 91.944 ;
     RECT  2.329 1.152 2.819 9.768 ;
     RECT  2.819 1.152 2.833 5.208 ;
     RECT  2.801 29.472 2.833 29.736 ;
     RECT  2.617 73.488 2.833 73.512 ;
     RECT  2.801 89.136 2.837 91.944 ;
     RECT  2.293 10.8 2.867 18.744 ;
     RECT  2.833 29.472 2.867 30.264 ;
     RECT  2.549 44.592 2.867 44.616 ;
     RECT  2.243 80.928 2.867 83.16 ;
     RECT  2.837 89.136 2.867 91.848 ;
     RECT  2.867 14.88 2.869 18.744 ;
     RECT  2.339 19.872 2.869 20.04 ;
     RECT  1.901 51.792 2.869 51.816 ;
     RECT  2.291 53.04 2.869 53.064 ;
     RECT  2.801 59.76 2.869 59.832 ;
     RECT  2.435 79.008 2.869 79.752 ;
     RECT  2.869 14.88 2.873 20.04 ;
     RECT  2.801 27.792 2.873 28.488 ;
     RECT  2.867 82.128 2.873 83.16 ;
     RECT  2.585 98.016 2.873 98.04 ;
     RECT  2.873 27.888 2.909 28.392 ;
     RECT  2.657 93.456 2.909 95.736 ;
     RECT  2.833 0.672 2.915 5.208 ;
     RECT  2.867 29.664 2.915 30.264 ;
     RECT  2.099 31.824 2.915 32.472 ;
     RECT  2.873 83.136 2.915 83.16 ;
     RECT  2.441 24.528 2.945 24.552 ;
     RECT  2.909 93.456 2.945 94.824 ;
     RECT  2.867 80.928 2.963 80.952 ;
     RECT  2.867 10.8 2.965 13.848 ;
     RECT  2.869 36.912 2.965 36.936 ;
     RECT  2.869 41.088 2.981 41.112 ;
     RECT  2.917 47.712 2.981 47.736 ;
     RECT  2.869 51.792 2.981 53.064 ;
     RECT  2.869 78.768 2.981 79.752 ;
     RECT  2.869 87.408 2.981 87.432 ;
     RECT  1.469 34.8 3.013 34.824 ;
     RECT  2.965 36.912 3.017 37.848 ;
     RECT  2.869 63.888 3.017 63.912 ;
     RECT  2.801 21.12 3.053 21.144 ;
     RECT  2.945 94.8 3.053 94.824 ;
     RECT  2.819 6.24 3.061 9.768 ;
     RECT  2.965 10.752 3.061 13.848 ;
     RECT  2.873 14.88 3.089 17.784 ;
     RECT  2.909 27.888 3.089 28.2 ;
     RECT  2.867 90.048 3.089 91.848 ;
     RECT  2.477 104.256 3.089 104.28 ;
     RECT  3.049 78.576 3.107 78.6 ;
     RECT  2.477 99.168 3.109 99.192 ;
     RECT  3.013 34.8 3.121 34.872 ;
     RECT  2.549 43.344 3.125 43.512 ;
     RECT  2.869 59.76 3.125 59.88 ;
     RECT  3.061 6.24 3.161 13.848 ;
     RECT  3.089 14.88 3.161 16.008 ;
     RECT  2.873 18.864 3.161 20.04 ;
     RECT  3.089 90.048 3.161 91.368 ;
     RECT  3.109 99.168 3.197 99.72 ;
     RECT  3.161 6.24 3.203 12.216 ;
     RECT  3.121 34.608 3.203 34.872 ;
     RECT  2.981 79.728 3.269 79.752 ;
     RECT  3.203 6.24 3.305 12.024 ;
     RECT  3.013 48.912 3.305 48.936 ;
     RECT  3.017 36.912 3.341 37.608 ;
     RECT  2.833 72.672 3.349 73.512 ;
     RECT  2.941 66.432 3.373 66.456 ;
     RECT  3.301 62.64 3.395 62.664 ;
     RECT  2.981 52.368 3.397 53.064 ;
     RECT  2.801 58.128 3.397 58.392 ;
     RECT  3.373 67.44 3.397 67.464 ;
     RECT  2.333 84.576 3.397 85.08 ;
     RECT  2.915 31.92 3.413 32.472 ;
     RECT  3.349 71.76 3.413 73.512 ;
     RECT  3.305 7.872 3.443 10.872 ;
     RECT  3.161 20.016 3.443 20.04 ;
     RECT  3.373 25.488 3.443 25.512 ;
     RECT  3.203 34.848 3.443 34.872 ;
     RECT  3.373 66.096 3.443 66.456 ;
     RECT  3.397 67.44 3.443 68.424 ;
     RECT  3.413 71.76 3.443 72.696 ;
     RECT  3.161 90.432 3.443 91.368 ;
     RECT  3.397 52.368 3.445 53.544 ;
     RECT  3.443 7.872 3.449 10.344 ;
     RECT  3.443 90.72 3.449 90.744 ;
     RECT  3.445 52.368 3.491 53.64 ;
     RECT  3.449 7.872 3.521 8.712 ;
     RECT  3.449 10.32 3.521 10.344 ;
     RECT  3.443 71.76 3.539 71.88 ;
     RECT  3.491 52.704 3.557 53.64 ;
     RECT  3.541 70.656 3.625 70.68 ;
     RECT  3.161 15.456 3.665 16.008 ;
     RECT  3.413 31.92 3.665 31.992 ;
     RECT  3.397 57.84 3.665 58.392 ;
     RECT  3.589 74.592 3.697 74.616 ;
     RECT  3.637 45.888 3.701 45.912 ;
     RECT  3.625 70.656 3.733 70.776 ;
     RECT  3.539 71.76 3.733 71.784 ;
     RECT  3.397 79.776 3.737 79.8 ;
     RECT  3.125 59.76 3.769 59.784 ;
     RECT  3.665 15.456 3.773 15.48 ;
     RECT  3.481 64.368 3.773 64.392 ;
     RECT  3.733 70.656 3.779 71.784 ;
     RECT  2.915 1.104 3.827 5.208 ;
     RECT  3.089 27.888 3.827 27.912 ;
     RECT  3.769 56.4 3.827 56.424 ;
     RECT  3.769 59.712 3.827 59.784 ;
     RECT  3.397 83.808 3.841 85.08 ;
     RECT  3.827 1.104 3.881 2.472 ;
     RECT  3.443 68.256 3.881 68.424 ;
     RECT  3.779 70.656 3.881 70.776 ;
     RECT  3.881 1.104 3.913 2.136 ;
     RECT  2.945 93.456 3.913 93.48 ;
     RECT  3.305 6.24 3.917 6.552 ;
     RECT  3.841 54.096 3.923 54.12 ;
     RECT  3.877 61.056 3.923 61.08 ;
     RECT  3.841 83.808 3.923 85.32 ;
     RECT  3.913 0.96 3.971 2.136 ;
     RECT  3.521 7.872 3.971 7.992 ;
     RECT  2.915 29.664 3.971 29.688 ;
     RECT  3.769 30.72 3.971 30.744 ;
     RECT  3.665 31.968 3.971 31.992 ;
     RECT  3.881 68.256 3.971 68.28 ;
     RECT  3.881 70.752 3.971 70.776 ;
     RECT  2.873 82.128 3.971 82.152 ;
     RECT  3.923 83.808 3.971 84.936 ;
     RECT  2.657 39.168 3.973 40.008 ;
     RECT  3.913 41.616 3.973 41.64 ;
     RECT  3.913 50.256 3.973 50.28 ;
     RECT  3.925 60.96 3.989 60.984 ;
     RECT  3.697 74.592 3.989 75.24 ;
     RECT  3.197 99.168 3.989 99.192 ;
     RECT  3.685 101.424 3.989 101.448 ;
     RECT  3.341 37.584 4.019 37.608 ;
     RECT  3.973 38.64 4.019 41.64 ;
     RECT  3.161 13.824 4.021 13.848 ;
     RECT  4.019 38.64 4.025 41.4 ;
     RECT  3.973 49.536 4.061 50.28 ;
     RECT  3.769 46.512 4.067 46.536 ;
     RECT  4.025 39.168 4.097 41.4 ;
     RECT  3.973 63.312 4.097 63.336 ;
     RECT  4.021 48.384 4.201 48.408 ;
     RECT  3.305 12 4.205 12.024 ;
     RECT  4.201 47.808 4.205 48.408 ;
     RECT  2.657 26.736 4.211 26.76 ;
     RECT  3.665 58.368 4.211 58.392 ;
     RECT  3.913 92.64 4.211 93.48 ;
     RECT  4.093 65.856 4.213 65.88 ;
     RECT  3.971 1.056 4.259 2.136 ;
     RECT  3.827 3.504 4.259 5.208 ;
     RECT  4.205 47.808 4.259 47.832 ;
     RECT  4.165 56.976 4.277 57 ;
     RECT  4.213 65.808 4.277 65.88 ;
     RECT  4.061 49.968 4.307 50.28 ;
     RECT  4.021 13.824 4.345 14.232 ;
     RECT  4.309 21.024 4.355 21.048 ;
     RECT  4.309 38.064 4.355 38.088 ;
     RECT  3.989 74.688 4.355 75.24 ;
     RECT  4.259 1.152 4.385 2.136 ;
     RECT  4.345 89.664 4.403 89.688 ;
     RECT  3.161 18.864 4.417 18.888 ;
     RECT  4.355 75.216 4.417 75.24 ;
     RECT  3.779 71.76 4.451 71.784 ;
     RECT  4.259 3.984 4.453 5.208 ;
     RECT  4.417 75.216 4.457 75.528 ;
     RECT  3.805 87.696 4.489 87.96 ;
     RECT  4.357 62.736 4.493 63.24 ;
     RECT  4.417 18.864 4.499 19.176 ;
     RECT  4.453 32.16 4.499 32.184 ;
     RECT  4.489 87.264 4.501 87.96 ;
     RECT  4.417 94.512 4.501 94.536 ;
     RECT  4.273 98.496 4.501 99.096 ;
     RECT  4.345 100.272 4.501 100.296 ;
     RECT  3.661 22.896 4.525 22.92 ;
     RECT  4.453 3.984 4.547 5.448 ;
     RECT  4.097 41.376 4.547 41.4 ;
     RECT  4.493 63.216 4.547 63.24 ;
     RECT  3.971 83.808 4.547 83.832 ;
     RECT  4.501 87.264 4.547 88.776 ;
     RECT  4.501 93.744 4.547 94.536 ;
     RECT  4.501 97.68 4.547 99.096 ;
     RECT  4.501 100.272 4.547 101.208 ;
     RECT  4.345 13.824 4.549 14.808 ;
     RECT  3.089 17.28 4.549 17.784 ;
     RECT  4.525 22.656 4.549 22.92 ;
     RECT  3.733 78.24 4.561 78.264 ;
     RECT  4.307 50.256 4.565 50.28 ;
     RECT  3.445 51.264 4.565 51.288 ;
     RECT  4.501 90.72 4.565 90.744 ;
     RECT  4.549 22.656 4.595 24.12 ;
     RECT  4.549 17.28 4.597 18.312 ;
     RECT  4.501 42.72 4.601 42.744 ;
     RECT  3.913 103.872 4.601 103.896 ;
     RECT  4.597 17.04 4.643 18.312 ;
     RECT  4.561 77.808 4.643 78.264 ;
     RECT  4.561 86.016 4.643 86.04 ;
     RECT  3.553 44.304 4.673 44.328 ;
     RECT  4.549 13.728 4.691 14.808 ;
     RECT  4.453 20.448 4.709 20.472 ;
     RECT  4.645 34.656 4.709 34.68 ;
     RECT  4.547 88.752 4.709 88.776 ;
     RECT  4.691 13.728 4.739 14.568 ;
     RECT  4.643 17.28 4.739 18.312 ;
     RECT  4.547 87.264 4.739 87.72 ;
     RECT  4.645 15.84 4.745 15.864 ;
     RECT  4.595 23.28 4.745 24.12 ;
     RECT  3.971 7.968 4.777 7.992 ;
     RECT  4.417 25.104 4.777 25.128 ;
     RECT  4.547 4.56 4.817 4.92 ;
     RECT  4.777 7.968 4.817 8.856 ;
     RECT  4.745 23.52 4.817 24.12 ;
     RECT  4.201 80.928 4.835 80.952 ;
     RECT  4.739 17.328 4.853 18.312 ;
     RECT  4.789 82.656 4.885 82.68 ;
     RECT  4.097 39.168 4.889 40.008 ;
     RECT  4.837 67.776 4.889 67.8 ;
     RECT  4.885 82.656 4.925 83.64 ;
     RECT  4.885 36.48 4.931 36.984 ;
     RECT  4.925 83.616 4.931 83.64 ;
     RECT  4.417 69.36 4.993 69.384 ;
     RECT  4.211 92.64 5.029 92.664 ;
     RECT  4.981 10.8 5.033 10.824 ;
     RECT  4.547 97.68 5.033 97.704 ;
     RECT  3.661 102.576 5.033 102.6 ;
     RECT  3.971 84.912 5.065 84.936 ;
     RECT  4.643 78.24 5.077 78.264 ;
     RECT  4.777 25.104 5.123 25.704 ;
     RECT  4.889 39.168 5.123 39.192 ;
     RECT  4.705 46.464 5.123 46.488 ;
     RECT  4.597 51.6 5.123 51.624 ;
     RECT  5.029 92.352 5.123 92.664 ;
     RECT  4.547 93.744 5.123 94.488 ;
     RECT  4.525 27.84 5.125 27.864 ;
     RECT  4.777 54.336 5.125 54.36 ;
     RECT  4.345 60.672 5.125 60.888 ;
     RECT  4.993 69.36 5.125 70.296 ;
     RECT  4.547 101.184 5.125 101.208 ;
     RECT  3.917 6.528 5.137 6.552 ;
     RECT  5.077 10.704 5.141 10.728 ;
     RECT  5.123 25.68 5.141 25.704 ;
     RECT  5.077 43.824 5.141 43.848 ;
     RECT  4.885 66.096 5.141 66.12 ;
     RECT  5.077 78.24 5.141 79.08 ;
     RECT  5.125 54.336 5.177 54.792 ;
     RECT  4.739 13.728 5.209 14.088 ;
     RECT  5.077 57.504 5.219 57.528 ;
     RECT  5.125 27.84 5.221 27.96 ;
     RECT  3.557 52.704 5.221 52.728 ;
     RECT  5.125 59.856 5.389 60.888 ;
     RECT  5.221 52.704 5.461 53.16 ;
     RECT  5.389 59.616 5.461 60.888 ;
     RECT  4.547 99.072 5.497 99.096 ;
     RECT  4.457 75.504 5.533 75.528 ;
     RECT  5.125 56.448 5.641 56.472 ;
     RECT  5.533 74.112 5.641 74.136 ;
     RECT  5.533 75.12 5.641 75.528 ;
     RECT  5.641 56.448 5.701 56.712 ;
     RECT  5.123 92.64 5.701 92.664 ;
     RECT  5.209 13.008 5.749 14.088 ;
     RECT  5.641 94.656 5.749 95.16 ;
     RECT  4.561 96.336 5.749 96.36 ;
     RECT  5.125 42.144 5.797 42.168 ;
     RECT  5.749 12.528 5.893 14.088 ;
     RECT  5.137 6.192 5.929 6.552 ;
     RECT  4.817 8.016 5.929 8.856 ;
     RECT  5.701 83.76 5.929 83.784 ;
     RECT  5.125 68.4 6.001 70.296 ;
     RECT  5.413 46.8 6.037 46.824 ;
     RECT  5.461 59.616 6.037 60.984 ;
     RECT  5.641 74.112 6.037 76.248 ;
     RECT  5.317 79.44 6.037 79.464 ;
     RECT  5.497 99.072 6.145 99.624 ;
     RECT  5.125 101.184 6.145 102.072 ;
     RECT  4.385 1.152 6.188 1.704 ;
     RECT  4.817 4.56 6.188 4.872 ;
     RECT  5.929 6.192 6.188 8.856 ;
     RECT  5.425 9.936 6.188 10.584 ;
     RECT  5.893 12.48 6.188 14.088 ;
     RECT  5.821 15.36 6.188 15.384 ;
     RECT  4.853 17.328 6.188 17.496 ;
     RECT  4.817 23.52 6.188 23.544 ;
     RECT  5.221 27.312 6.188 27.96 ;
     RECT  5.221 29.616 6.188 29.64 ;
     RECT  5.125 31.536 6.188 31.896 ;
     RECT  5.749 34.128 6.188 34.152 ;
     RECT  5.749 37.056 6.188 37.08 ;
     RECT  5.101 40.32 6.188 40.344 ;
     RECT  5.797 42.144 6.188 42.792 ;
     RECT  5.353 45.552 6.188 45.576 ;
     RECT  6.037 46.8 6.188 47.064 ;
     RECT  5.701 48.48 6.188 48.504 ;
     RECT  6.145 50.544 6.188 50.568 ;
     RECT  5.461 52.704 6.188 53.976 ;
     RECT  5.701 55.92 6.188 56.712 ;
     RECT  5.497 58.608 6.188 58.632 ;
     RECT  6.037 59.616 6.188 61.656 ;
     RECT  5.317 63.744 6.188 63.768 ;
     RECT  6.001 68.4 6.188 70.68 ;
     RECT  5.125 71.808 6.188 71.832 ;
     RECT  6.037 72.912 6.188 72.936 ;
     RECT  6.037 74.112 6.188 76.392 ;
     RECT  5.141 78.24 6.188 78.264 ;
     RECT  6.037 79.44 6.188 80.376 ;
     RECT  5.929 83.712 6.188 83.784 ;
     RECT  5.065 84.912 6.188 85.656 ;
     RECT  4.739 87.696 6.188 87.72 ;
     RECT  5.749 88.944 6.188 88.968 ;
     RECT  5.701 92.64 6.188 93.528 ;
     RECT  5.749 94.656 6.188 96.6 ;
     RECT  5.749 97.824 6.188 97.848 ;
     RECT  6.145 99.072 6.188 102.072 ;
     RECT  6.188 0.528 6.292 105.312 ;
     RECT  6.292 0.798 6.484 105.042 ;
     RECT  6.484 0.96 6.611 1.176 ;
     RECT  6.484 16.8 6.611 17.736 ;
     RECT  6.484 19.248 6.611 19.272 ;
     RECT  6.484 23.136 6.611 23.88 ;
     RECT  6.484 25.152 6.611 26.808 ;
     RECT  6.484 38.496 6.611 41.112 ;
     RECT  6.484 58.368 6.611 58.68 ;
     RECT  6.484 66.144 6.611 67.848 ;
     RECT  6.484 99.264 6.611 100.296 ;
     RECT  6.484 101.328 6.611 103.224 ;
     RECT  6.484 31.392 6.617 31.416 ;
     RECT  6.484 34.752 6.653 34.824 ;
     RECT  6.484 93.456 6.653 95.688 ;
     RECT  6.484 50.544 6.659 53.4 ;
     RECT  6.484 21.12 6.689 21.672 ;
     RECT  6.484 92.256 6.689 92.28 ;
     RECT  6.484 70.656 6.755 71.352 ;
     RECT  6.755 70.752 6.761 71.352 ;
     RECT  6.484 76.32 6.851 77.4 ;
     RECT  6.484 83.76 6.851 85.128 ;
     RECT  6.653 93.456 6.851 94.68 ;
     RECT  6.689 21.36 6.869 21.672 ;
     RECT  6.659 51.024 6.869 53.4 ;
     RECT  6.484 10.848 6.905 10.872 ;
     RECT  6.869 51.36 6.905 53.4 ;
     RECT  6.484 73.776 6.905 74.568 ;
     RECT  6.611 25.152 6.941 25.944 ;
     RECT  6.611 102 6.941 103.224 ;
     RECT  6.611 23.136 6.947 23.352 ;
     RECT  6.484 60.672 6.947 63.816 ;
     RECT  6.611 38.496 6.977 40.728 ;
     RECT  6.905 51.36 6.977 53.016 ;
     RECT  6.947 63.264 6.977 63.288 ;
     RECT  6.484 9.504 7.013 9.528 ;
     RECT  6.484 12.48 7.013 13.08 ;
     RECT  6.484 14.256 7.013 14.28 ;
     RECT  6.947 23.136 7.049 23.16 ;
     RECT  6.484 81.456 7.049 82.392 ;
     RECT  6.941 102.384 7.049 103.224 ;
     RECT  6.611 99.264 7.085 99.72 ;
     RECT  6.484 78.528 7.091 79.464 ;
     RECT  6.977 39.984 7.139 40.728 ;
     RECT  6.484 45.552 7.187 45.576 ;
     RECT  6.484 47.04 7.187 48.456 ;
     RECT  7.049 81.456 7.187 81.48 ;
     RECT  6.484 7.776 7.193 8.04 ;
     RECT  6.869 21.36 7.193 21.384 ;
     RECT  6.611 66.144 7.193 67.464 ;
     RECT  6.947 60.672 7.229 61.896 ;
     RECT  6.761 70.752 7.229 70.776 ;
     RECT  6.653 34.752 7.235 34.776 ;
     RECT  6.905 73.776 7.301 73.8 ;
     RECT  6.851 76.32 7.301 76.824 ;
     RECT  7.091 78.528 7.331 79.272 ;
     RECT  6.977 38.496 7.379 38.52 ;
     RECT  7.139 39.984 7.379 40.344 ;
     RECT  6.484 28.944 7.409 28.968 ;
     RECT  7.187 47.616 7.409 48.456 ;
     RECT  6.653 95.664 7.409 95.688 ;
     RECT  6.484 15.36 7.427 15.384 ;
     RECT  6.941 25.152 7.427 25.176 ;
     RECT  6.851 93.456 7.427 94.296 ;
     RECT  7.049 102.384 7.427 102.408 ;
     RECT  6.484 42.432 7.445 43.32 ;
     RECT  6.977 52.32 7.475 53.016 ;
     RECT  7.085 99.264 7.475 99.288 ;
     RECT  7.409 48.384 7.517 48.456 ;
     RECT  6.484 55.392 7.517 55.416 ;
     RECT  6.484 57.168 7.517 57.192 ;
     RECT  7.427 93.984 7.523 94.296 ;
     RECT  6.851 83.76 7.553 83.976 ;
     RECT  6.851 85.104 7.573 85.128 ;
     RECT  6.484 89.184 7.573 89.208 ;
     RECT  7.517 48.432 7.589 48.456 ;
     RECT  7.475 52.32 7.625 52.344 ;
     RECT  7.573 56.64 7.625 56.664 ;
     RECT  7.229 60.672 7.657 61.032 ;
     RECT  6.484 64.992 7.661 65.016 ;
     RECT  7.585 87.12 7.667 87.144 ;
     RECT  7.573 85.104 7.765 85.416 ;
     RECT  7.765 85.104 7.873 85.56 ;
     RECT  6.611 16.8 7.955 17.688 ;
     RECT  7.553 83.856 7.957 83.976 ;
     RECT  7.873 85.104 7.957 86.088 ;
     RECT  7.477 92.304 7.957 92.952 ;
     RECT  7.729 30.24 8.003 30.264 ;
     RECT  6.611 58.368 8.003 58.392 ;
     RECT  7.657 60.432 8.003 61.032 ;
     RECT  7.957 83.856 8.003 86.088 ;
     RECT  7.573 88.896 8.005 89.208 ;
     RECT  7.957 91.44 8.005 92.952 ;
     RECT  7.837 54.096 8.017 54.12 ;
     RECT  7.013 12.48 8.021 12.504 ;
     RECT  8.005 88.896 8.051 90.024 ;
     RECT  8.003 83.952 8.057 84.36 ;
     RECT  8.051 89.424 8.057 90.024 ;
     RECT  8.005 91.2 8.057 92.952 ;
     RECT  7.193 8.016 8.089 8.04 ;
     RECT  8.017 54.096 8.093 55.032 ;
     RECT  7.909 2.736 8.149 2.76 ;
     RECT  7.523 93.984 8.165 94.008 ;
     RECT  8.125 23.328 8.195 23.352 ;
     RECT  6.484 5.136 8.197 5.736 ;
     RECT  8.003 60.96 8.197 61.032 ;
     RECT  8.197 60.96 8.243 62.76 ;
     RECT  8.149 2.736 8.273 3.432 ;
     RECT  8.197 5.04 8.273 5.736 ;
     RECT  7.331 78.528 8.273 78.6 ;
     RECT  8.089 8.016 8.305 8.568 ;
     RECT  8.305 7.584 8.341 8.568 ;
     RECT  7.379 40.32 8.341 40.344 ;
     RECT  8.273 5.712 8.387 5.736 ;
     RECT  8.305 35.328 8.387 35.352 ;
     RECT  7.873 9.792 8.413 9.96 ;
     RECT  8.413 9.792 8.417 10.584 ;
     RECT  8.341 40.32 8.437 41.016 ;
     RECT  8.437 39.6 8.449 41.016 ;
     RECT  7.693 14.064 8.483 14.088 ;
     RECT  8.197 34.224 8.483 34.248 ;
     RECT  6.611 1.152 8.485 1.176 ;
     RECT  8.449 39.408 8.485 41.016 ;
     RECT  8.437 12.528 8.489 13.08 ;
     RECT  8.243 62.736 8.489 62.76 ;
     RECT  8.273 2.736 8.531 2.76 ;
     RECT  8.341 36.432 8.531 37.224 ;
     RECT  8.485 38.736 8.531 41.016 ;
     RECT  8.093 55.008 8.531 55.032 ;
     RECT  8.341 65.28 8.531 65.304 ;
     RECT  7.193 66.624 8.531 67.464 ;
     RECT  8.485 68.928 8.531 69.336 ;
     RECT  8.125 79.728 8.531 79.752 ;
     RECT  8.149 24.816 8.533 24.84 ;
     RECT  8.437 32.976 8.533 33 ;
     RECT  8.125 80.928 8.533 80.952 ;
     RECT  8.233 101.712 8.533 101.736 ;
     RECT  8.413 46.128 8.579 46.152 ;
     RECT  8.533 100.848 8.579 101.736 ;
     RECT  7.801 27.312 8.593 27.336 ;
     RECT  8.489 12.528 8.597 12.552 ;
     RECT  8.533 47.856 8.597 47.88 ;
     RECT  7.981 75.648 8.629 75.672 ;
     RECT  7.301 76.8 8.629 76.824 ;
     RECT  8.593 27.312 8.665 27.912 ;
     RECT  8.629 75.648 8.665 76.824 ;
     RECT  8.197 31.296 8.675 31.32 ;
     RECT  8.273 78.576 8.677 78.6 ;
     RECT  8.665 26.64 8.723 27.912 ;
     RECT  8.449 74.064 8.723 74.088 ;
     RECT  8.677 78.576 8.723 78.696 ;
     RECT  8.521 21.36 8.737 21.384 ;
     RECT  8.533 80.928 8.809 81.528 ;
     RECT  8.057 89.424 8.813 89.448 ;
     RECT  8.531 40.32 8.819 41.016 ;
     RECT  8.737 42.144 8.819 42.168 ;
     RECT  7.955 16.8 8.845 17.064 ;
     RECT  8.737 20.448 8.915 21.384 ;
     RECT  8.341 7.344 8.921 8.568 ;
     RECT  8.531 36.432 8.957 36.456 ;
     RECT  8.197 59.808 8.957 59.832 ;
     RECT  8.243 60.96 9.013 60.984 ;
     RECT  8.921 8.016 9.061 8.568 ;
     RECT  8.629 29.808 9.061 29.832 ;
     RECT  8.665 75.12 9.061 76.824 ;
     RECT  8.533 32.976 9.065 33.048 ;
     RECT  8.125 103.728 9.097 103.752 ;
     RECT  8.417 10.56 9.107 10.584 ;
     RECT  8.723 27.888 9.107 27.912 ;
     RECT  9.061 74.784 9.107 76.824 ;
     RECT  8.809 80.928 9.107 81.624 ;
     RECT  8.737 72.288 9.133 72.312 ;
     RECT  8.917 87.12 9.133 87.144 ;
     RECT  8.521 88.32 9.133 88.344 ;
     RECT  9.061 29.472 9.137 29.832 ;
     RECT  8.773 70.656 9.155 70.68 ;
     RECT  9.107 80.928 9.155 81.24 ;
     RECT  8.377 90.576 9.169 90.6 ;
     RECT  8.057 92.016 9.169 92.952 ;
     RECT  8.449 98.064 9.169 98.088 ;
     RECT  8.485 0.576 9.173 1.704 ;
     RECT  8.531 38.736 9.205 38.808 ;
     RECT  9.169 90.576 9.205 92.952 ;
     RECT  9.205 89.616 9.251 92.952 ;
     RECT  9.169 98.064 9.251 99.048 ;
     RECT  8.723 78.672 9.281 78.696 ;
     RECT  8.057 83.952 9.347 83.976 ;
     RECT  9.205 85.248 9.347 85.272 ;
     RECT  9.133 87.12 9.347 88.344 ;
     RECT  8.197 50.208 9.353 50.232 ;
     RECT  8.845 16.512 9.389 17.064 ;
     RECT  9.313 4.224 9.445 4.248 ;
     RECT  9.251 99.024 9.457 99.048 ;
     RECT  8.533 43.824 9.461 43.848 ;
     RECT  9.061 8.016 9.493 9.24 ;
     RECT  9.097 103.488 9.493 103.752 ;
     RECT  9.445 4.224 9.497 4.872 ;
     RECT  8.533 24.816 9.497 25.512 ;
     RECT  9.155 81.216 9.497 81.24 ;
     RECT  8.579 100.848 9.529 100.872 ;
     RECT  8.531 69.312 9.569 69.336 ;
     RECT  9.457 99.024 9.587 99.096 ;
     RECT  9.529 100.32 9.587 100.872 ;
     RECT  9.205 38.592 9.601 38.808 ;
     RECT  8.819 40.32 9.601 40.344 ;
     RECT  8.485 56.352 9.601 56.376 ;
     RECT  8.531 66.624 9.601 66.648 ;
     RECT  9.133 72 9.601 72.312 ;
     RECT  9.601 66.048 9.605 66.648 ;
     RECT  9.565 10.944 9.637 10.968 ;
     RECT  8.915 20.544 9.637 21.384 ;
     RECT  9.601 33.408 9.637 33.432 ;
     RECT  8.533 64.08 9.637 64.104 ;
     RECT  9.107 76.608 9.637 76.824 ;
     RECT  8.197 58.128 9.673 58.152 ;
     RECT  9.637 96.768 9.673 97.752 ;
     RECT  9.493 103.488 9.673 104.664 ;
     RECT  9.589 30.192 9.677 30.216 ;
     RECT  9.589 46.464 9.685 46.488 ;
     RECT  9.685 18.144 9.817 18.168 ;
     RECT  9.673 37.056 9.817 37.272 ;
     RECT  9.601 38.592 9.817 40.344 ;
     RECT  9.781 42.816 9.925 42.84 ;
     RECT  9.601 56.352 9.997 56.856 ;
     RECT  9.601 71.808 9.997 72.312 ;
     RECT  9.529 68.16 10.033 68.184 ;
     RECT  9.565 73.344 10.033 73.368 ;
     RECT  9.107 74.784 10.033 74.904 ;
     RECT  9.997 71.616 10.105 72.312 ;
     RECT  10.033 73.344 10.105 74.904 ;
     RECT  9.997 56.064 10.141 56.856 ;
     RECT  9.013 60.288 10.177 60.984 ;
     RECT  10.177 5.568 10.213 5.592 ;
     RECT  9.637 20.544 10.213 22.104 ;
     RECT  9.925 52.608 10.213 52.632 ;
     RECT  10.141 55.296 10.213 56.856 ;
     RECT  9.605 66.048 10.213 66.456 ;
     RECT  9.173 0.576 10.249 1.176 ;
     RECT  9.493 8.016 10.249 9.432 ;
     RECT  10.213 14.592 10.249 14.616 ;
     RECT  9.601 16.128 10.249 16.152 ;
     RECT  10.213 19.968 10.249 22.104 ;
     RECT  9.637 25.536 10.249 25.752 ;
     RECT  10.213 27.456 10.249 27.48 ;
     RECT  9.817 32.064 10.249 32.088 ;
     RECT  9.637 33.408 10.249 34.2 ;
     RECT  9.925 42.24 10.249 42.84 ;
     RECT  9.997 44.544 10.249 44.568 ;
     RECT  9.685 46.464 10.249 46.536 ;
     RECT  10.177 60.288 10.249 61.464 ;
     RECT  10.033 67.968 10.249 68.184 ;
     RECT  10.249 19.968 10.321 22.872 ;
     RECT  10.249 24.192 10.321 24.216 ;
     RECT  9.781 79.296 10.321 79.32 ;
     RECT  9.601 100.992 10.321 101.4 ;
     RECT  9.817 18.144 10.357 18.84 ;
     RECT  10.321 19.968 10.357 24.216 ;
     RECT  10.249 32.064 10.357 34.2 ;
     RECT  9.817 37.056 10.357 40.344 ;
     RECT  10.249 41.856 10.357 42.84 ;
     RECT  10.249 46.464 10.357 47.448 ;
     RECT  10.165 51.504 10.357 51.528 ;
     RECT  10.213 52.608 10.357 53.016 ;
     RECT  9.637 63.552 10.357 64.344 ;
     RECT  10.213 65.856 10.357 66.456 ;
     RECT  10.357 46.464 10.429 47.64 ;
     RECT  10.249 49.344 10.429 49.368 ;
     RECT  10.357 51.456 10.429 53.592 ;
     RECT  10.249 0.576 10.465 1.368 ;
     RECT  10.249 2.496 10.465 2.52 ;
     RECT  10.249 25.536 10.465 27.48 ;
     RECT  10.213 28.992 10.465 29.4 ;
     RECT  10.357 31.104 10.465 34.2 ;
     RECT  10.357 35.328 10.465 35.352 ;
     RECT  10.249 44.544 10.465 45.336 ;
     RECT  10.213 69.888 10.465 70.488 ;
     RECT  10.105 71.616 10.465 74.904 ;
     RECT  10.249 60.096 10.537 61.464 ;
     RECT  10.321 100.992 10.537 101.592 ;
     RECT  9.673 103.104 10.537 104.664 ;
     RECT  10.465 31.104 10.573 35.352 ;
     RECT  10.321 78.336 10.573 79.32 ;
     RECT  10.321 80.832 10.573 80.856 ;
     RECT  10.357 86.4 10.573 86.424 ;
     RECT  9.347 87.744 10.573 88.344 ;
     RECT  9.205 94.8 10.573 94.824 ;
     RECT  9.673 96.192 10.573 97.752 ;
     RECT  10.465 0.576 10.645 2.52 ;
     RECT  10.213 5.568 10.645 6.36 ;
     RECT  10.249 7.68 10.645 9.432 ;
     RECT  10.249 14.592 10.645 16.152 ;
     RECT  10.465 25.536 10.645 29.4 ;
     RECT  10.573 31.104 10.645 35.928 ;
     RECT  10.357 37.056 10.645 42.84 ;
     RECT  10.465 44.352 10.645 45.336 ;
     RECT  10.429 46.464 10.645 49.368 ;
     RECT  10.429 51.072 10.645 53.592 ;
     RECT  10.213 55.296 10.645 57.048 ;
     RECT  9.673 58.128 10.645 58.776 ;
     RECT  10.249 67.968 10.645 68.568 ;
     RECT  10.573 82.368 10.645 82.392 ;
     RECT  9.637 83.52 10.645 83.544 ;
     RECT  10.573 84.864 10.645 84.888 ;
     RECT  9.251 92.736 10.645 92.76 ;
     RECT  10.573 94.8 10.645 97.752 ;
     RECT  9.587 99.072 10.645 99.096 ;
     RECT  10.537 59.904 10.681 61.464 ;
     RECT  10.465 69.888 10.717 74.904 ;
     RECT  9.637 76.608 10.717 77.016 ;
     RECT  9.251 90.24 10.717 90.264 ;
     RECT  10.537 100.992 10.717 104.664 ;
     RECT  10.645 14.208 10.753 16.152 ;
     RECT  10.357 18.144 10.753 24.216 ;
     RECT  10.645 44.352 10.753 49.368 ;
     RECT  10.645 50.88 10.753 53.592 ;
     RECT  10.717 100.416 10.753 104.664 ;
     RECT  9.497 4.224 10.789 4.248 ;
     RECT  10.645 5.568 10.789 9.624 ;
     RECT  9.637 10.944 10.789 11.352 ;
     RECT  10.753 13.632 10.789 24.216 ;
     RECT  10.645 25.536 10.789 35.928 ;
     RECT  10.645 37.056 10.789 43.224 ;
     RECT  10.753 44.352 10.789 53.592 ;
     RECT  10.645 55.296 10.789 58.776 ;
     RECT  10.645 67.776 10.789 68.568 ;
     RECT  10.717 69.888 10.789 77.016 ;
     RECT  10.573 86.4 10.789 88.344 ;
     RECT  10.717 89.856 10.789 90.264 ;
     RECT  10.645 92.736 10.789 93.144 ;
     RECT  10.645 0.576 10.825 2.712 ;
     RECT  10.789 3.84 10.825 4.248 ;
     RECT  10.789 5.568 10.825 11.352 ;
     RECT  10.789 13.632 10.825 43.224 ;
     RECT  10.789 44.352 10.825 58.776 ;
     RECT  10.681 59.904 10.825 62.04 ;
     RECT  10.357 63.552 10.825 66.456 ;
     RECT  10.789 67.776 10.825 77.016 ;
     RECT  10.573 78.336 10.825 80.856 ;
     RECT  10.645 82.368 10.825 84.888 ;
     RECT  10.789 86.4 10.825 90.264 ;
     RECT  10.681 91.392 10.825 91.416 ;
     RECT  10.789 92.736 10.825 93.336 ;
     RECT  10.645 94.464 10.825 99.096 ;
     RECT  10.753 100.224 10.825 104.664 ;
     RECT  10.825 0.384 11.724 104.664 ;
     RECT  11.724 8.016 11.765 8.04 ;
    LAYER M5 ;
     RECT  5.904 0.144 5.928 0.517 ;
     RECT  0.78 0.517 0.9 0.531 ;
     RECT  5.904 0.517 6.3 0.531 ;
     RECT  0.78 0.531 1.092 0.693 ;
     RECT  0.78 0.693 1.224 0.949 ;
     RECT  5.904 0.531 6.492 0.949 ;
     RECT  5.904 0.949 6.6 1.003 ;
     RECT  3.936 0.949 3.96 1.045 ;
     RECT  2.88 0.661 2.904 1.525 ;
     RECT  3.936 1.045 4.248 1.525 ;
     RECT  2.88 1.525 4.248 1.573 ;
     RECT  0.192 0.949 1.752 1.579 ;
     RECT  5.904 1.003 6.492 1.669 ;
     RECT  5.28 1.669 6.492 1.771 ;
     RECT  0.78 1.579 1.752 2.053 ;
     RECT  2.736 1.573 4.248 2.053 ;
     RECT  0.78 2.053 4.248 2.283 ;
     RECT  0.78 2.283 1.704 2.339 ;
     RECT  2.688 2.283 4.248 2.347 ;
     RECT  8.496 1.669 8.52 2.725 ;
     RECT  8.16 2.725 8.52 2.771 ;
     RECT  2.88 2.347 4.248 2.795 ;
     RECT  0.78 2.339 1.656 2.963 ;
     RECT  10.848 2.741 10.872 3.299 ;
     RECT  8.16 2.771 8.184 3.443 ;
     RECT  0.78 2.963 1.464 3.539 ;
     RECT  2.88 2.795 2.952 3.685 ;
     RECT  2.832 3.685 2.952 3.755 ;
     RECT  4.224 2.795 4.248 3.925 ;
     RECT  3.408 3.925 4.248 3.973 ;
     RECT  2.352 3.925 2.376 4.011 ;
     RECT  3.408 3.973 4.536 4.011 ;
     RECT  3.552 4.011 4.536 4.277 ;
     RECT  5.904 1.771 6.492 4.277 ;
     RECT  3.552 4.277 6.492 4.595 ;
     RECT  2.208 4.533 2.232 4.835 ;
     RECT  5.664 4.595 6.492 4.853 ;
     RECT  5.664 4.853 7.464 4.907 ;
     RECT  3.552 4.595 4.536 4.931 ;
     RECT  5.904 4.907 7.464 5.029 ;
     RECT  3.504 5.045 3.528 5.125 ;
     RECT  9.456 4.837 9.48 5.163 ;
     RECT  5.904 5.029 8.232 5.171 ;
     RECT  3.408 5.125 3.528 5.219 ;
     RECT  2.256 5.045 2.28 5.653 ;
     RECT  2.256 5.653 2.328 5.685 ;
     RECT  3.408 5.219 3.432 5.685 ;
     RECT  8.208 5.171 8.232 5.701 ;
     RECT  8.208 5.701 8.376 5.747 ;
     RECT  0.78 3.539 1.092 5.797 ;
     RECT  2.256 5.685 3.432 5.797 ;
     RECT  0.78 5.797 3.432 5.941 ;
     RECT  0.192 5.941 3.432 5.995 ;
     RECT  5.904 5.171 6.492 6.133 ;
     RECT  5.664 6.133 6.492 6.227 ;
     RECT  0.78 5.995 3.432 6.323 ;
     RECT  3.36 6.323 3.432 6.379 ;
     RECT  4.512 4.931 4.536 6.517 ;
     RECT  4.032 6.517 4.536 6.563 ;
     RECT  10.848 6.133 10.872 6.755 ;
     RECT  0.78 6.323 2.328 6.851 ;
     RECT  2.88 7.333 2.904 7.381 ;
     RECT  4.032 6.563 4.056 7.381 ;
     RECT  2.88 7.381 4.056 7.531 ;
     RECT  8.352 5.747 8.376 7.619 ;
     RECT  5.904 6.227 6.492 7.765 ;
     RECT  0.78 6.851 1.704 7.909 ;
     RECT  2.88 7.531 2.904 7.909 ;
     RECT  5.904 7.765 7.176 7.989 ;
     RECT  3.936 7.531 4.056 8.003 ;
     RECT  5.664 7.989 7.176 8.043 ;
     RECT  0.78 7.909 2.904 8.051 ;
     RECT  2.688 8.051 2.904 8.565 ;
     RECT  2.688 8.565 2.952 8.629 ;
     RECT  5.664 8.043 6.492 8.821 ;
     RECT  0.78 8.051 1.704 9.013 ;
     RECT  2.688 8.629 3.432 9.013 ;
     RECT  0.192 9.013 3.432 9.067 ;
     RECT  9.072 8.533 9.096 9.397 ;
     RECT  5.472 8.821 6.492 9.461 ;
     RECT  5.472 9.461 6.936 9.539 ;
     RECT  0.78 9.067 3.432 9.643 ;
     RECT  7.968 9.781 7.992 9.835 ;
     RECT  9.072 9.397 9.528 9.963 ;
     RECT  7.92 9.909 7.944 9.971 ;
     RECT  0.78 9.643 1.752 10.549 ;
     RECT  5.472 9.539 6.492 10.549 ;
     RECT  9.072 9.963 9.096 10.595 ;
     RECT  5.472 10.549 6.888 10.677 ;
     RECT  3.072 9.643 3.432 10.741 ;
     RECT  5.088 10.677 6.888 10.789 ;
     RECT  4.992 10.789 6.888 10.859 ;
     RECT  0.192 10.549 1.752 10.869 ;
     RECT  2.976 10.741 3.432 10.883 ;
     RECT  5.472 10.859 6.888 10.883 ;
     RECT  0.192 10.869 1.848 10.931 ;
     RECT  2.976 10.883 3.288 10.981 ;
     RECT  2.928 10.981 3.288 11.125 ;
     RECT  2.112 11.125 3.288 11.459 ;
     RECT  0.192 10.931 1.092 11.563 ;
     RECT  2.208 11.459 3.288 11.957 ;
     RECT  2.208 11.957 4.008 12.011 ;
     RECT  2.784 12.011 4.008 12.035 ;
     RECT  2.784 12.035 3.192 12.227 ;
     RECT  0.78 11.563 1.092 12.469 ;
     RECT  10.848 12.469 10.872 12.563 ;
     RECT  0.78 12.469 1.704 12.661 ;
     RECT  5.472 10.883 6.492 13.045 ;
     RECT  0.672 12.661 1.704 13.237 ;
     RECT  2.784 12.227 3.144 13.237 ;
     RECT  0.192 13.237 3.144 13.291 ;
     RECT  5.472 13.045 6.888 13.685 ;
     RECT  4.56 13.685 6.888 14.099 ;
     RECT  8.448 13.045 8.472 14.099 ;
     RECT  0.672 13.291 3.144 14.197 ;
     RECT  4.56 14.099 4.728 14.197 ;
     RECT  0.672 14.197 4.728 14.251 ;
     RECT  5.904 14.099 6.888 14.291 ;
     RECT  2.304 14.251 4.728 14.315 ;
     RECT  0.672 14.251 1.224 14.581 ;
     RECT  0.192 14.581 1.224 14.635 ;
     RECT  4.656 14.315 4.728 14.635 ;
     RECT  0.192 14.635 1.092 14.763 ;
     RECT  5.904 14.291 6.492 15.349 ;
     RECT  2.304 14.315 3.144 15.637 ;
     RECT  2.256 15.637 3.144 15.669 ;
     RECT  2.256 15.669 3.432 15.723 ;
     RECT  0.78 14.763 1.092 15.925 ;
     RECT  0.192 15.925 1.092 15.973 ;
     RECT  0.192 15.973 1.224 15.979 ;
     RECT  0.78 15.979 1.224 15.989 ;
     RECT  2.88 15.723 3.432 16.019 ;
     RECT  0.78 15.989 1.752 16.067 ;
     RECT  2.88 16.019 3 17.013 ;
     RECT  4.656 14.635 4.68 17.013 ;
     RECT  8.88 16.501 8.904 17.013 ;
     RECT  8.88 17.013 9.336 17.075 ;
     RECT  0.78 16.067 1.608 17.141 ;
     RECT  4.608 17.013 4.68 17.141 ;
     RECT  2.88 17.013 3.048 17.195 ;
     RECT  4.608 17.141 4.728 17.317 ;
     RECT  5.904 15.349 7.416 17.317 ;
     RECT  4.608 17.317 7.416 17.333 ;
     RECT  0.78 17.141 1.704 17.509 ;
     RECT  4.608 17.333 7.464 17.509 ;
     RECT  0.78 17.509 2.28 17.555 ;
     RECT  2.16 17.555 2.28 17.579 ;
     RECT  3.408 17.509 7.464 17.653 ;
     RECT  8.88 17.075 8.904 17.653 ;
     RECT  3.408 17.653 8.904 17.699 ;
     RECT  3.408 17.699 6.6 17.707 ;
     RECT  7.92 17.699 8.904 17.707 ;
     RECT  3.696 17.707 6.6 17.747 ;
     RECT  3.696 17.747 6.492 17.835 ;
     RECT  8.88 17.707 8.904 18.101 ;
     RECT  8.88 18.101 9.72 18.179 ;
     RECT  4.464 17.835 4.584 18.323 ;
     RECT  0.78 17.555 1.092 18.709 ;
     RECT  2.16 17.579 2.184 18.709 ;
     RECT  0.672 18.709 1.092 18.741 ;
     RECT  2.16 18.709 2.52 18.741 ;
     RECT  0.672 18.741 2.52 18.795 ;
     RECT  4.464 18.323 4.488 18.805 ;
     RECT  2.88 18.805 4.488 18.899 ;
     RECT  5.904 17.835 6.492 19.189 ;
     RECT  5.904 19.189 6.6 19.283 ;
     RECT  2.88 18.899 2.904 19.755 ;
     RECT  0.78 18.795 1.896 19.861 ;
     RECT  0.78 19.861 2.328 19.957 ;
     RECT  3.408 20.005 3.432 20.075 ;
     RECT  10.272 20.021 10.296 20.099 ;
     RECT  0.192 19.957 2.328 20.203 ;
     RECT  4.464 18.899 4.488 20.437 ;
     RECT  4.464 20.437 4.584 21.013 ;
     RECT  4.32 21.013 4.584 21.099 ;
     RECT  0.672 20.203 2.328 21.109 ;
     RECT  5.904 19.283 6.492 21.109 ;
     RECT  0.672 21.109 2.904 21.163 ;
     RECT  5.904 21.109 6.648 21.349 ;
     RECT  8.88 18.179 8.904 21.395 ;
     RECT  5.904 21.349 6.888 21.419 ;
     RECT  0.672 21.163 2.664 21.493 ;
     RECT  0.192 21.493 2.664 22.115 ;
     RECT  0.78 22.115 2.664 22.315 ;
     RECT  4.56 21.099 4.584 22.837 ;
     RECT  3.936 22.837 4.584 22.931 ;
     RECT  0.78 22.315 2.328 23.221 ;
     RECT  5.904 21.419 6.492 23.269 ;
     RECT  0.672 23.221 2.328 23.315 ;
     RECT  5.904 23.269 6.792 23.317 ;
     RECT  0.78 23.315 2.328 23.411 ;
     RECT  5.904 23.317 6.936 23.477 ;
     RECT  5.664 23.477 6.936 23.531 ;
     RECT  5.664 23.531 6.6 23.555 ;
     RECT  5.904 23.555 6.6 23.915 ;
     RECT  4.56 22.931 4.584 24.131 ;
     RECT  0.78 23.411 1.092 24.373 ;
     RECT  0.672 24.373 1.092 24.427 ;
     RECT  2.304 24.373 2.328 24.501 ;
     RECT  2.304 24.501 2.904 24.563 ;
     RECT  8.16 23.317 8.184 24.805 ;
     RECT  8.16 24.805 8.712 24.851 ;
     RECT  5.904 23.915 6.492 25.093 ;
     RECT  5.088 25.093 6.492 25.141 ;
     RECT  5.088 25.141 7.416 25.195 ;
     RECT  10.848 24.949 10.872 25.195 ;
     RECT  3.408 25.461 3.432 25.523 ;
     RECT  8.544 24.851 8.712 25.523 ;
     RECT  5.088 25.195 6.888 25.715 ;
     RECT  5.904 25.715 6.888 25.955 ;
     RECT  0.78 24.427 1.092 26.677 ;
     RECT  4.176 26.677 4.2 26.771 ;
     RECT  0.192 26.677 1.092 26.795 ;
     RECT  5.904 25.955 6.6 26.819 ;
     RECT  5.904 26.819 6.492 27.253 ;
     RECT  2.112 27.253 2.232 27.301 ;
     RECT  8.688 25.523 8.712 27.347 ;
     RECT  0.672 26.795 1.092 27.445 ;
     RECT  2.112 27.301 2.616 27.445 ;
     RECT  4.8 27.253 6.492 27.875 ;
     RECT  3.792 27.877 3.816 27.947 ;
     RECT  5.136 27.875 6.492 27.971 ;
     RECT  0.672 27.445 2.616 28.019 ;
     RECT  2.304 28.019 2.616 28.021 ;
     RECT  2.304 28.021 2.952 28.211 ;
     RECT  0.672 28.019 1.32 28.267 ;
     RECT  5.904 27.971 6.492 28.933 ;
     RECT  0.78 28.267 1.32 29.109 ;
     RECT  2.304 28.211 2.472 29.109 ;
     RECT  0.78 29.109 2.472 29.429 ;
     RECT  5.904 28.933 7.368 29.483 ;
     RECT  0.78 29.429 2.856 29.557 ;
     RECT  5.904 29.483 6.492 29.605 ;
     RECT  0.192 29.557 2.856 29.611 ;
     RECT  5.232 29.605 6.492 29.675 ;
     RECT  0.672 29.611 2.856 29.699 ;
     RECT  3.936 29.621 3.96 29.699 ;
     RECT  2.304 29.699 2.856 29.747 ;
     RECT  9.072 27.877 9.096 29.797 ;
     RECT  0.672 29.699 1.092 29.995 ;
     RECT  8.64 29.797 9.096 30.181 ;
     RECT  8.64 30.181 9.624 30.197 ;
     RECT  7.968 30.197 9.624 30.251 ;
     RECT  2.88 29.941 2.904 30.275 ;
     RECT  7.968 30.251 8.664 30.275 ;
     RECT  3.936 30.709 3.96 30.763 ;
     RECT  5.904 29.675 6.492 31.349 ;
     RECT  5.904 31.349 6.6 31.427 ;
     RECT  5.904 31.427 6.492 31.525 ;
     RECT  2.064 31.525 2.088 31.813 ;
     RECT  3.408 31.541 3.432 31.813 ;
     RECT  0.78 29.995 1.092 31.909 ;
     RECT  2.064 31.813 3.432 31.909 ;
     RECT  0.78 31.909 3.432 31.925 ;
     RECT  0.78 31.925 3.96 31.955 ;
     RECT  0.78 31.955 2.904 31.979 ;
     RECT  3.936 31.955 3.96 32.003 ;
     RECT  5.136 31.525 6.492 32.117 ;
     RECT  4.464 32.117 6.492 32.195 ;
     RECT  0.78 31.979 1.092 32.437 ;
     RECT  0.192 32.437 1.092 32.491 ;
     RECT  2.256 31.979 2.28 32.491 ;
     RECT  8.64 30.275 8.664 32.965 ;
     RECT  8.448 32.965 8.664 33.011 ;
     RECT  8.448 33.011 8.568 33.067 ;
     RECT  0.78 32.491 1.092 33.653 ;
     RECT  0.78 33.653 1.752 33.731 ;
     RECT  8.448 33.067 8.472 34.259 ;
     RECT  5.235 32.195 6.492 34.613 ;
     RECT  5.235 34.613 6.6 34.645 ;
     RECT  3.168 34.597 3.192 34.667 ;
     RECT  4.656 34.645 6.6 34.741 ;
     RECT  2.208 34.789 2.232 34.859 ;
     RECT  4.656 34.741 7.224 34.859 ;
     RECT  3.408 34.805 3.432 34.883 ;
     RECT  8.352 35.317 8.376 36.467 ;
     RECT  5.235 34.859 7.224 36.469 ;
     RECT  4.896 36.469 7.224 37.035 ;
     RECT  0.78 33.731 1.092 37.429 ;
     RECT  0.192 37.429 1.092 37.483 ;
     RECT  0.78 37.483 1.092 37.525 ;
     RECT  2.88 36.901 2.904 37.557 ;
     RECT  0.78 37.525 1.704 38.005 ;
     RECT  3.984 37.573 4.008 38.005 ;
     RECT  5.235 37.035 7.224 38.005 ;
     RECT  3.984 38.005 7.224 38.099 ;
     RECT  0.78 38.005 1.752 38.389 ;
     RECT  2.88 37.557 3 38.389 ;
     RECT  5.235 38.099 7.224 38.485 ;
     RECT  0.78 38.389 3 38.517 ;
     RECT  0.192 38.517 3 38.627 ;
     RECT  5.235 38.485 7.368 39.157 ;
     RECT  8.496 37.189 8.52 39.443 ;
     RECT  0.78 38.627 3 39.733 ;
     RECT  0.192 39.733 3 39.787 ;
     RECT  0.78 39.787 3 39.923 ;
     RECT  3.984 38.099 4.008 39.925 ;
     RECT  5.088 39.157 7.368 39.925 ;
     RECT  2.592 39.923 3 40.019 ;
     RECT  3.984 39.925 7.368 40.019 ;
     RECT  2.592 40.019 2.904 40.363 ;
     RECT  0.78 39.923 1.56 40.933 ;
     RECT  8.448 39.589 8.472 40.981 ;
     RECT  8.448 40.981 8.808 41.027 ;
     RECT  2.88 40.363 2.904 41.123 ;
     RECT  0.78 40.933 1.704 41.269 ;
     RECT  3.984 40.019 4.008 41.365 ;
     RECT  5.235 40.019 7.128 41.365 ;
     RECT  0.192 41.269 1.704 41.557 ;
     RECT  3.984 41.365 7.128 41.651 ;
     RECT  0.192 41.557 1.752 42.133 ;
     RECT  0.192 42.133 1.992 42.219 ;
     RECT  0.192 42.219 1.752 42.475 ;
     RECT  4.512 41.651 7.128 42.755 ;
     RECT  0.576 42.475 1.752 42.803 ;
     RECT  5.235 42.755 7.128 43.285 ;
     RECT  2.88 43.317 2.904 43.379 ;
     RECT  5.235 43.285 7.176 43.813 ;
     RECT  8.784 41.027 8.808 43.813 ;
     RECT  8.544 43.813 8.808 43.859 ;
     RECT  0.78 42.803 1.092 43.861 ;
     RECT  2.304 43.445 2.328 43.861 ;
     RECT  5.088 43.813 7.176 43.883 ;
     RECT  0.78 43.861 2.328 44.085 ;
     RECT  0.192 44.085 2.328 44.099 ;
     RECT  0.192 44.099 1.752 44.139 ;
     RECT  0.192 44.139 1.092 44.195 ;
     RECT  3.648 44.293 3.672 44.581 ;
     RECT  2.832 44.581 3.672 44.651 ;
     RECT  10.272 44.581 10.296 44.651 ;
     RECT  2.496 45.301 2.52 45.355 ;
     RECT  0.78 44.195 1.092 45.493 ;
     RECT  0.78 45.493 1.704 45.547 ;
     RECT  3.648 44.651 3.672 45.923 ;
     RECT  5.235 43.883 7.176 46.453 ;
     RECT  9.6 46.453 9.624 46.501 ;
     RECT  5.088 46.453 7.176 46.507 ;
     RECT  9.6 46.501 9.72 46.507 ;
     RECT  9.696 46.507 9.72 46.571 ;
     RECT  2.736 46.773 2.76 46.835 ;
     RECT  5.235 46.507 7.176 47.075 ;
     RECT  5.235 47.075 6.888 47.651 ;
     RECT  4.032 46.501 4.056 47.797 ;
     RECT  4.032 47.797 4.248 47.851 ;
     RECT  0.78 45.547 1.092 47.861 ;
     RECT  2.928 47.701 2.952 47.915 ;
     RECT  0.78 47.861 1.704 48.229 ;
     RECT  0.78 48.229 2.088 48.299 ;
     RECT  0.78 48.299 1.752 48.373 ;
     RECT  4.032 47.851 4.056 48.419 ;
     RECT  5.235 47.651 6.792 48.419 ;
     RECT  0.192 48.373 1.752 48.427 ;
     RECT  0.78 48.427 1.752 48.515 ;
     RECT  3.024 48.885 3.048 48.947 ;
     RECT  0.78 48.515 1.092 49.589 ;
     RECT  0.78 49.589 1.656 49.667 ;
     RECT  2.64 49.653 2.664 49.763 ;
     RECT  3.984 49.525 4.008 49.957 ;
     RECT  5.235 48.419 6.648 49.957 ;
     RECT  3.984 49.957 6.648 50.027 ;
     RECT  8.544 43.859 8.568 50.243 ;
     RECT  3.984 50.027 4.008 50.291 ;
     RECT  0.78 49.667 1.092 51.253 ;
     RECT  5.235 50.027 6.648 51.317 ;
     RECT  0.78 51.253 1.656 51.445 ;
     RECT  0.192 51.445 1.752 51.499 ;
     RECT  5.235 51.317 6.888 51.573 ;
     RECT  10.176 51.493 10.2 51.627 ;
     RECT  5.088 51.573 6.888 51.635 ;
     RECT  0.78 51.499 1.752 51.781 ;
     RECT  3.456 51.253 3.48 51.781 ;
     RECT  0.78 51.781 3.48 51.883 ;
     RECT  0.78 51.883 1.752 51.923 ;
     RECT  5.235 51.635 6.888 52.309 ;
     RECT  2.88 51.883 3.48 52.547 ;
     RECT  5.235 52.309 7.464 52.693 ;
     RECT  0.78 51.923 1.092 52.789 ;
     RECT  0.192 52.789 1.092 52.843 ;
     RECT  2.256 53.365 2.28 53.419 ;
     RECT  3.408 52.547 3.48 53.555 ;
     RECT  0.78 52.843 1.092 53.557 ;
     RECT  0.78 53.557 1.224 53.651 ;
     RECT  3.456 53.555 3.48 53.651 ;
     RECT  4.8 52.693 7.464 54.069 ;
     RECT  3.888 54.069 7.464 54.131 ;
     RECT  4.8 54.131 7.464 54.371 ;
     RECT  5.136 54.371 7.464 54.803 ;
     RECT  0.78 53.651 1.092 55.237 ;
     RECT  5.568 54.803 7.464 55.427 ;
     RECT  0.78 55.237 1.752 55.605 ;
     RECT  0.192 55.605 2.568 55.659 ;
     RECT  0.192 55.659 1.092 55.715 ;
     RECT  2.544 55.659 2.568 55.715 ;
     RECT  5.568 55.427 6.492 56.373 ;
     RECT  3.792 56.373 3.816 56.435 ;
     RECT  5.136 56.373 6.492 56.483 ;
     RECT  8.496 54.997 8.52 56.629 ;
     RECT  7.584 56.629 8.52 56.683 ;
     RECT  2.4 57.205 2.424 57.299 ;
     RECT  5.568 56.483 6.492 57.461 ;
     RECT  4.176 56.965 4.2 57.493 ;
     RECT  5.184 57.461 6.492 57.493 ;
     RECT  4.176 57.493 6.492 57.579 ;
     RECT  0.78 55.715 1.092 57.781 ;
     RECT  4.176 57.579 4.2 57.781 ;
     RECT  0.78 57.781 1.224 57.875 ;
     RECT  0.78 57.875 1.092 57.973 ;
     RECT  0.192 57.973 1.092 58.027 ;
     RECT  8.496 56.683 8.52 58.117 ;
     RECT  8.208 58.117 8.52 58.163 ;
     RECT  5.568 57.579 6.492 58.357 ;
     RECT  8.208 58.163 8.232 58.357 ;
     RECT  3.408 57.781 4.2 58.403 ;
     RECT  3.408 58.403 3.432 58.411 ;
     RECT  5.568 58.357 8.232 58.411 ;
     RECT  2.304 57.973 2.328 58.869 ;
     RECT  0.78 58.027 1.092 58.885 ;
     RECT  2.304 58.869 2.76 58.885 ;
     RECT  10.848 58.357 10.872 58.979 ;
     RECT  0.78 58.885 2.76 58.987 ;
     RECT  0.78 58.987 1.752 59.125 ;
     RECT  0.192 59.125 1.752 59.179 ;
     RECT  0.78 59.179 1.752 59.315 ;
     RECT  5.568 58.411 6.6 59.605 ;
     RECT  5.424 59.605 6.6 59.701 ;
     RECT  3.792 59.701 3.816 59.749 ;
     RECT  8.208 58.411 8.232 59.797 ;
     RECT  2.88 59.749 3.816 59.891 ;
     RECT  5.136 59.701 6.6 59.891 ;
     RECT  3.552 59.891 3.816 60.011 ;
     RECT  0.78 59.315 1.704 60.373 ;
     RECT  8.208 59.797 8.52 60.405 ;
     RECT  9.696 60.373 9.72 60.459 ;
     RECT  0.78 60.373 1.752 60.597 ;
     RECT  0.192 60.597 1.752 60.651 ;
     RECT  5.568 59.891 6.6 60.661 ;
     RECT  7.968 60.405 8.52 60.661 ;
     RECT  0.192 60.651 1.092 60.707 ;
     RECT  3.936 60.661 4.392 60.853 ;
     RECT  5.568 60.661 9.048 60.853 ;
     RECT  3.936 60.853 9.048 60.907 ;
     RECT  5.472 60.907 9.048 61.035 ;
     RECT  5.472 61.035 8.232 61.043 ;
     RECT  3.936 60.907 4.392 61.045 ;
     RECT  3.888 61.045 4.392 61.099 ;
     RECT  5.472 61.043 6.84 61.099 ;
     RECT  5.568 61.099 6.84 62.437 ;
     RECT  3.36 62.629 3.384 62.699 ;
     RECT  2.16 62.645 2.184 62.723 ;
     RECT  8.208 61.043 8.232 62.771 ;
     RECT  0.78 60.707 1.092 62.773 ;
     RECT  0.192 62.773 1.092 62.827 ;
     RECT  4.368 61.099 4.392 63.205 ;
     RECT  4.368 63.205 4.536 63.275 ;
     RECT  3.984 63.285 4.008 63.347 ;
     RECT  5.568 62.437 6.936 63.669 ;
     RECT  5.328 63.669 6.936 63.779 ;
     RECT  2.88 63.861 2.904 63.923 ;
     RECT  8.544 64.053 8.568 64.115 ;
     RECT  3.696 64.357 3.72 64.427 ;
     RECT  0.78 62.827 1.092 64.437 ;
     RECT  2.256 64.821 2.28 64.883 ;
     RECT  0.576 64.437 1.092 64.885 ;
     RECT  0.192 64.885 1.752 64.939 ;
     RECT  0.78 64.939 1.752 65.027 ;
     RECT  5.568 63.779 6.936 65.027 ;
     RECT  4.224 65.797 4.248 65.845 ;
     RECT  4.128 65.845 4.248 66.037 ;
     RECT  3.408 66.037 4.248 66.085 ;
     RECT  5.568 65.027 6.888 66.085 ;
     RECT  3.408 66.085 6.888 66.091 ;
     RECT  4.896 66.091 6.888 66.155 ;
     RECT  5.568 66.155 6.888 66.179 ;
     RECT  5.568 66.179 6.492 67.701 ;
     RECT  4.848 67.701 6.492 67.811 ;
     RECT  5.136 67.811 6.492 67.813 ;
     RECT  5.136 67.813 6.6 67.883 ;
     RECT  3.408 66.091 3.432 68.245 ;
     RECT  3.408 68.245 3.96 68.331 ;
     RECT  0.78 65.027 1.092 68.341 ;
     RECT  0.78 68.341 1.704 68.395 ;
     RECT  3.408 68.331 3.432 68.435 ;
     RECT  5.136 67.883 6.492 68.435 ;
     RECT  0.78 68.395 1.092 69.109 ;
     RECT  0.192 69.109 1.092 69.163 ;
     RECT  8.496 65.269 8.52 69.301 ;
     RECT  8.496 69.301 9.144 69.347 ;
     RECT  5.568 68.435 6.492 70.069 ;
     RECT  5.232 70.069 6.492 70.123 ;
     RECT  0.78 69.163 1.092 70.133 ;
     RECT  0.78 70.133 1.224 70.211 ;
     RECT  5.568 70.123 6.492 70.645 ;
     RECT  3.552 70.645 3.576 70.699 ;
     RECT  5.568 70.645 6.744 70.709 ;
     RECT  5.568 70.709 6.888 70.787 ;
     RECT  2.256 70.773 2.28 70.835 ;
     RECT  0.78 70.211 1.092 70.837 ;
     RECT  0.192 70.837 1.092 70.891 ;
     RECT  2.4 71.221 2.424 71.275 ;
     RECT  5.568 70.787 6.744 71.363 ;
     RECT  5.568 71.363 6.492 71.605 ;
     RECT  3.744 70.709 3.96 71.733 ;
     RECT  5.136 71.605 6.492 71.733 ;
     RECT  3.744 71.733 6.492 71.749 ;
     RECT  3.36 71.749 6.492 71.795 ;
     RECT  0.78 70.891 1.092 71.797 ;
     RECT  9.12 69.347 9.144 71.797 ;
     RECT  5.136 71.795 6.492 71.843 ;
     RECT  3.36 71.795 3.528 71.851 ;
     RECT  3.408 71.851 3.528 71.891 ;
     RECT  0.78 71.797 2.184 71.939 ;
     RECT  2.16 71.939 2.184 72.235 ;
     RECT  9.12 71.797 9.672 72.323 ;
     RECT  3.408 71.891 3.432 72.707 ;
     RECT  2.832 73.477 2.856 73.579 ;
     RECT  5.568 71.843 6.492 73.765 ;
     RECT  9.648 72.323 9.672 74.053 ;
     RECT  0.78 71.939 1.092 74.101 ;
     RECT  5.568 73.765 6.888 74.147 ;
     RECT  0.78 74.101 1.656 74.155 ;
     RECT  5.664 74.147 6.888 74.579 ;
     RECT  8.688 74.053 9.672 74.819 ;
     RECT  5.664 74.579 6.492 75.109 ;
     RECT  5.568 75.109 6.492 75.179 ;
     RECT  4.32 74.677 4.344 75.251 ;
     RECT  6.18 75.179 6.492 76.213 ;
     RECT  5.664 76.213 6.936 76.267 ;
     RECT  6.048 76.267 6.936 76.403 ;
     RECT  6.18 76.403 6.936 76.451 ;
     RECT  8.688 74.819 9.096 76.451 ;
     RECT  0.78 74.155 1.092 76.981 ;
     RECT  2.304 76.645 2.328 76.981 ;
     RECT  2.304 76.981 2.664 77.035 ;
     RECT  6.18 76.451 6.84 77.547 ;
     RECT  4.608 77.797 4.632 77.867 ;
     RECT  0.78 76.981 1.224 77.989 ;
     RECT  6.18 77.547 6.492 78.229 ;
     RECT  8.688 76.451 8.712 78.389 ;
     RECT  5.328 78.229 6.492 78.517 ;
     RECT  8.208 78.389 8.712 78.517 ;
     RECT  5.328 78.517 8.712 78.563 ;
     RECT  5.328 78.563 7.464 78.571 ;
     RECT  3.072 78.565 3.096 78.635 ;
     RECT  0.78 77.989 1.704 78.707 ;
     RECT  8.688 78.563 8.712 78.707 ;
     RECT  5.328 78.571 7.32 79.045 ;
     RECT  5.088 79.045 7.32 79.147 ;
     RECT  5.328 79.147 7.32 79.283 ;
     RECT  2.88 78.757 2.904 79.467 ;
     RECT  5.328 79.283 7.08 79.475 ;
     RECT  3.408 79.765 3.432 79.851 ;
     RECT  2.304 79.717 2.424 79.859 ;
     RECT  0.78 78.707 1.092 80.293 ;
     RECT  0.78 80.293 1.992 80.363 ;
     RECT  8.496 79.717 8.52 80.917 ;
     RECT  0.78 80.363 1.092 80.949 ;
     RECT  2.784 80.885 2.952 80.963 ;
     RECT  8.496 80.917 9.144 80.963 ;
     RECT  0.192 80.949 1.092 81.059 ;
     RECT  2.784 80.963 2.856 81.059 ;
     RECT  6.048 79.475 6.492 81.445 ;
     RECT  6.048 81.445 7.176 81.515 ;
     RECT  0.78 81.059 1.092 81.525 ;
     RECT  8.544 80.963 9.144 81.539 ;
     RECT  9.072 81.539 9.144 81.643 ;
     RECT  10.848 81.589 10.872 81.643 ;
     RECT  2.832 81.059 2.856 81.875 ;
     RECT  4.8 80.917 4.824 82.101 ;
     RECT  3.936 82.101 4.824 82.163 ;
     RECT  6.048 81.515 7.032 82.403 ;
     RECT  0.78 81.525 1.656 82.453 ;
     RECT  0.672 82.453 1.656 82.485 ;
     RECT  0.672 82.485 2.328 82.549 ;
     RECT  0.192 82.549 2.328 82.667 ;
     RECT  4.8 82.163 4.824 82.691 ;
     RECT  0.78 82.667 2.328 83.125 ;
     RECT  0.78 83.125 2.904 83.243 ;
     RECT  2.88 83.243 2.904 83.371 ;
     RECT  0.78 83.243 1.704 83.411 ;
     RECT  4.896 83.605 4.92 83.691 ;
     RECT  6.048 82.403 6.492 83.701 ;
     RECT  5.952 83.701 7.464 83.749 ;
     RECT  0.78 83.411 1.092 83.765 ;
     RECT  5.712 83.749 7.512 83.819 ;
     RECT  0.576 83.765 1.092 83.843 ;
     RECT  3.408 83.765 3.432 83.843 ;
     RECT  4.512 83.765 4.536 83.843 ;
     RECT  6.18 83.819 7.512 83.845 ;
     RECT  9.12 81.643 9.144 83.941 ;
     RECT  9.12 83.941 9.336 83.987 ;
     RECT  6.18 83.845 7.992 84.331 ;
     RECT  6.18 84.331 6.84 84.467 ;
     RECT  3.648 84.277 3.96 84.843 ;
     RECT  2.64 84.709 2.664 84.917 ;
     RECT  2.304 84.917 2.664 84.995 ;
     RECT  2.88 85.045 2.904 85.099 ;
     RECT  0.78 83.843 1.092 85.237 ;
     RECT  0.192 85.237 1.752 85.291 ;
     RECT  3.888 84.843 3.96 85.355 ;
     RECT  7.968 84.331 7.992 85.381 ;
     RECT  5.184 85.301 5.208 85.493 ;
     RECT  6.18 84.467 6.492 85.493 ;
     RECT  0.78 85.291 1.752 85.523 ;
     RECT  7.584 85.381 7.992 85.547 ;
     RECT  5.136 85.493 6.492 85.571 ;
     RECT  7.92 85.547 7.992 85.571 ;
     RECT  5.136 85.571 5.208 85.621 ;
     RECT  5.088 85.621 5.208 85.667 ;
     RECT  5.088 85.667 5.112 85.675 ;
     RECT  10.848 85.429 10.872 85.675 ;
     RECT  3.936 85.355 3.96 86.005 ;
     RECT  3.936 86.005 4.632 86.059 ;
     RECT  7.968 85.571 7.992 86.099 ;
     RECT  0.78 85.523 1.608 86.443 ;
     RECT  0.78 86.443 1.224 86.581 ;
     RECT  9.312 83.987 9.336 87.109 ;
     RECT  9.216 87.109 9.336 87.155 ;
     RECT  0.672 86.581 1.224 87.157 ;
     RECT  3.936 86.059 3.96 87.221 ;
     RECT  3.936 87.221 4.728 87.299 ;
     RECT  2.304 86.581 2.76 87.397 ;
     RECT  2.304 87.397 2.904 87.467 ;
     RECT  3.936 87.299 4.536 87.731 ;
     RECT  0.192 87.157 1.224 88.171 ;
     RECT  0.78 88.171 1.224 88.357 ;
     RECT  2.304 87.467 2.376 88.357 ;
     RECT  0.78 88.357 2.376 88.501 ;
     RECT  7.632 87.109 7.656 88.885 ;
     RECT  0.78 88.501 2.664 89.125 ;
     RECT  7.584 88.885 7.656 89.173 ;
     RECT  0.78 89.125 2.856 89.195 ;
     RECT  7.584 89.173 8.04 89.195 ;
     RECT  0.78 89.195 2.328 89.205 ;
     RECT  7.632 89.195 8.04 89.219 ;
     RECT  0.192 89.205 2.328 89.259 ;
     RECT  8.016 89.219 8.04 89.397 ;
     RECT  9.216 87.155 9.24 89.397 ;
     RECT  8.016 89.397 9.24 89.459 ;
     RECT  4.512 87.731 4.536 89.589 ;
     RECT  0.192 89.259 1.656 89.603 ;
     RECT  4.368 89.589 4.536 89.699 ;
     RECT  0.192 89.603 1.512 90.611 ;
     RECT  3.408 90.421 3.432 90.741 ;
     RECT  2.832 90.741 3.432 90.803 ;
     RECT  8.016 89.459 8.04 91.235 ;
     RECT  10.848 90.997 10.872 91.371 ;
     RECT  3.408 90.803 3.432 91.379 ;
     RECT  0.192 90.611 1.224 91.573 ;
     RECT  0.192 91.573 1.992 91.627 ;
     RECT  0.78 91.627 1.992 91.765 ;
     RECT  0.78 91.765 2.328 91.907 ;
     RECT  6.18 85.571 6.492 92.245 ;
     RECT  7.968 91.429 7.992 92.339 ;
     RECT  4.512 89.699 4.536 92.341 ;
     RECT  4.512 92.341 5.112 92.395 ;
     RECT  6.18 92.245 6.648 92.395 ;
     RECT  0.78 91.907 1.752 92.435 ;
     RECT  4.512 92.395 4.536 93.429 ;
     RECT  6.18 92.395 6.492 93.429 ;
     RECT  7.488 92.821 7.512 93.429 ;
     RECT  4.176 93.429 4.536 93.491 ;
     RECT  5.712 93.429 7.512 93.539 ;
     RECT  0.78 92.435 1.092 93.877 ;
     RECT  2.304 92.917 2.328 93.877 ;
     RECT  10.848 93.429 10.872 93.923 ;
     RECT  0.192 93.877 2.712 93.931 ;
     RECT  6.18 93.539 7.512 93.973 ;
     RECT  6.18 93.973 7.992 94.059 ;
     RECT  0.78 93.931 1.752 94.115 ;
     RECT  6.18 94.059 7.512 94.307 ;
     RECT  4.512 93.491 4.536 94.453 ;
     RECT  0.78 94.115 1.704 94.507 ;
     RECT  4.512 94.453 5.112 94.507 ;
     RECT  4.512 94.507 4.536 94.547 ;
     RECT  6.18 94.307 6.84 94.645 ;
     RECT  5.76 94.645 6.84 94.691 ;
     RECT  2.88 94.453 2.904 94.787 ;
     RECT  5.76 94.691 6.6 94.787 ;
     RECT  0.78 94.507 1.092 96.309 ;
     RECT  2.448 95.365 2.472 96.309 ;
     RECT  5.76 94.787 6.492 96.309 ;
     RECT  5.088 96.309 6.492 96.371 ;
     RECT  0.78 96.309 2.52 96.419 ;
     RECT  0.78 96.419 1.704 96.563 ;
     RECT  0.78 96.563 1.092 97.381 ;
     RECT  0.672 97.381 1.092 97.717 ;
     RECT  0.192 97.717 1.752 97.771 ;
     RECT  0.672 97.771 1.752 97.899 ;
     RECT  0.78 97.899 1.752 98.037 ;
     RECT  0.78 98.037 2.328 98.339 ;
     RECT  9.216 89.459 9.24 98.579 ;
     RECT  2.304 98.339 2.328 99.115 ;
     RECT  5.76 96.371 6.492 99.253 ;
     RECT  5.76 99.253 7.464 99.573 ;
     RECT  5.664 99.573 7.464 99.627 ;
     RECT  5.664 99.627 6.6 99.635 ;
     RECT  3.12 99.685 3.144 99.755 ;
     RECT  0.78 98.339 1.092 99.765 ;
     RECT  9.552 99.013 9.576 100.355 ;
     RECT  0.78 99.765 1.656 100.715 ;
     RECT  4.512 97.669 4.536 101.413 ;
     RECT  3.696 101.413 4.536 101.547 ;
     RECT  2.256 101.493 2.28 101.555 ;
     RECT  6.18 99.635 6.6 101.989 ;
     RECT  4.512 101.547 4.536 102.005 ;
     RECT  6.18 101.989 6.888 102.005 ;
     RECT  4.512 102.005 6.888 102.083 ;
     RECT  0.78 100.715 1.092 102.261 ;
     RECT  0.78 102.261 1.944 102.277 ;
     RECT  6.18 102.083 6.888 102.373 ;
     RECT  0.672 102.277 1.944 102.443 ;
     RECT  6.18 102.373 7.416 102.443 ;
     RECT  10.848 101.941 10.872 102.443 ;
     RECT  0.672 102.443 1.092 102.571 ;
     RECT  4.512 102.083 4.536 102.611 ;
     RECT  2.304 102.517 2.328 102.659 ;
     RECT  8.544 100.837 8.568 103.763 ;
     RECT  2.304 103.733 2.328 103.811 ;
     RECT  0.78 102.571 1.092 103.861 ;
     RECT  0.192 103.861 1.092 103.915 ;
     RECT  0.78 103.915 1.092 104.053 ;
     RECT  0.78 104.053 1.608 104.107 ;
     RECT  0.78 104.107 1.224 104.963 ;
     RECT  2.304 104.885 2.328 104.963 ;
     RECT  0.78 104.963 1.092 105.309 ;
     RECT  6.18 102.443 6.492 105.309 ;
     RECT  0.78 105.309 0.9 105.323 ;
     RECT  6.18 105.309 6.3 105.323 ;
    LAYER M6 ;
     RECT  0.053 14.72 0.181 16.032 ;
     RECT  0.053 28.544 0.181 28.576 ;
     RECT  0.053 26.752 0.227 26.784 ;
     RECT  0.181 10.56 0.235 11.552 ;
     RECT  0.181 32.448 0.235 33.696 ;
     RECT  0.181 37.44 0.235 39.776 ;
     RECT  0.181 41.28 0.235 42.784 ;
     RECT  0.181 52.8 0.235 53.6 ;
     RECT  0.181 62.784 0.235 62.816 ;
     RECT  0.181 69.12 0.235 71.84 ;
     RECT  0.181 79.744 0.235 80.992 ;
     RECT  0.181 103.872 0.235 104.928 ;
     RECT  0.181 87.168 0.309 91.616 ;
     RECT  0.181 64.448 0.611 64.928 ;
     RECT  0.053 82.624 0.611 83.808 ;
     RECT  0.181 13.12 0.661 13.28 ;
     RECT  0.181 14.72 0.661 16.608 ;
     RECT  0.181 19.968 0.661 22.048 ;
     RECT  0.181 28.544 0.661 29.6 ;
     RECT  0.611 82.624 0.661 83.36 ;
     RECT  0.309 87.168 0.661 92.384 ;
     RECT  0.181 97.728 0.661 97.76 ;
     RECT  0.235 41.344 0.693 42.784 ;
     RECT  0.181 44.096 0.693 44.128 ;
     RECT  0.661 97.408 0.693 97.888 ;
     RECT  0.661 27.264 0.747 29.984 ;
     RECT  0.693 97.408 0.875 98.656 ;
     RECT  0.181 0.96 1.189 1.568 ;
     RECT  0.181 9.024 1.189 9.056 ;
     RECT  0.235 10.56 1.189 11.168 ;
     RECT  0.181 57.984 1.189 59.168 ;
     RECT  0.235 53.568 1.235 53.6 ;
     RECT  0.235 70.144 1.235 70.176 ;
     RECT  0.661 12.48 1.333 16.608 ;
     RECT  0.661 18.752 1.333 24.416 ;
     RECT  1.189 0.704 1.381 2.336 ;
     RECT  1.381 0.704 1.397 2.72 ;
     RECT  1.189 9.024 1.461 11.168 ;
     RECT  0.181 93.888 1.477 93.92 ;
     RECT  0.661 86.592 1.523 92.384 ;
     RECT  1.461 8.768 1.525 11.168 ;
     RECT  1.333 12.48 1.525 24.416 ;
     RECT  0.235 38.208 1.525 39.776 ;
     RECT  0.693 41.344 1.525 44.128 ;
     RECT  0.235 71.808 1.525 71.84 ;
     RECT  1.477 93.888 1.525 94.048 ;
     RECT  1.525 8.768 1.573 24.416 ;
     RECT  0.181 85.248 1.573 85.28 ;
     RECT  1.523 86.592 1.573 89.568 ;
     RECT  0.235 104.896 1.573 104.928 ;
     RECT  1.461 7.296 1.621 7.328 ;
     RECT  1.573 8.64 1.621 24.416 ;
     RECT  0.181 48.384 1.621 48.416 ;
     RECT  0.181 51.456 1.621 51.488 ;
     RECT  0.661 82.496 1.621 83.36 ;
     RECT  0.875 97.728 1.621 98.656 ;
     RECT  1.621 48.384 1.653 49.632 ;
     RECT  1.621 51.264 1.653 51.488 ;
     RECT  1.525 70.784 1.653 71.84 ;
     RECT  1.189 76.992 1.653 77.024 ;
     RECT  0.235 79.744 1.653 79.776 ;
     RECT  1.621 81.536 1.653 83.36 ;
     RECT  1.573 85.248 1.653 89.568 ;
     RECT  1.525 93.888 1.653 94.752 ;
     RECT  0.181 5.952 1.669 5.984 ;
     RECT  1.525 38.208 1.669 44.128 ;
     RECT  1.653 48.256 1.669 49.632 ;
     RECT  1.189 57.792 1.669 59.168 ;
     RECT  0.181 60.608 1.669 60.64 ;
     RECT  1.653 51.264 1.707 52 ;
     RECT  1.621 74.112 1.707 74.144 ;
     RECT  1.653 76.992 1.707 83.36 ;
     RECT  1.653 84.928 1.707 89.568 ;
     RECT  1.621 97.728 1.707 100.704 ;
     RECT  1.707 76.992 1.715 80.992 ;
     RECT  1.669 45.504 1.717 45.536 ;
     RECT  1.669 47.872 1.717 49.632 ;
     RECT  0.235 33.664 1.763 33.696 ;
     RECT  1.707 51.456 1.763 52 ;
     RECT  1.669 57.792 1.763 60.64 ;
     RECT  0.611 64.896 1.763 64.928 ;
     RECT  1.707 84.928 1.763 89.248 ;
     RECT  1.707 97.728 1.763 99.104 ;
     RECT  1.669 31.936 1.845 31.968 ;
     RECT  0.661 102.528 1.909 102.56 ;
     RECT  1.523 91.584 1.973 92.384 ;
     RECT  1.653 93.888 1.973 96.352 ;
     RECT  1.909 102.272 1.973 102.56 ;
     RECT  1.573 104.064 1.973 104.928 ;
     RECT  1.669 37.568 2.003 44.128 ;
     RECT  0.747 27.328 2.037 29.984 ;
     RECT  1.845 31.936 2.053 32.48 ;
     RECT  1.621 7.296 2.101 24.416 ;
     RECT  2.149 62.656 2.165 62.688 ;
     RECT  1.653 70.784 2.195 72.224 ;
     RECT  1.397 0.704 2.197 3.488 ;
     RECT  1.669 5.824 2.197 5.984 ;
     RECT  1.707 82.496 2.229 83.36 ;
     RECT  1.763 84.928 2.229 85.088 ;
     RECT  2.197 0.704 2.245 5.984 ;
     RECT  2.101 7.296 2.245 24.544 ;
     RECT  1.707 100.672 2.245 100.704 ;
     RECT  1.973 102.272 2.245 104.928 ;
     RECT  2.037 27.264 2.283 29.984 ;
     RECT  1.763 86.4 2.283 89.248 ;
     RECT  2.053 31.552 2.291 32.48 ;
     RECT  2.245 0.704 2.339 24.544 ;
     RECT  2.003 37.568 2.339 40.992 ;
     RECT  2.229 82.496 2.339 85.088 ;
     RECT  2.283 86.592 2.339 89.248 ;
     RECT  1.973 91.584 2.339 96.352 ;
     RECT  1.763 98.048 2.339 99.104 ;
     RECT  2.245 100.672 2.339 104.928 ;
     RECT  2.339 0.704 2.347 22.88 ;
     RECT  1.763 57.792 2.389 60 ;
     RECT  2.339 93.888 2.483 96.352 ;
     RECT  2.003 43.328 2.485 44.128 ;
     RECT  1.717 45.504 2.485 49.632 ;
     RECT  2.485 43.328 2.539 49.632 ;
     RECT  1.763 51.84 2.549 52 ;
     RECT  2.245 53.376 2.549 53.408 ;
     RECT  2.339 39.232 2.579 40.992 ;
     RECT  2.549 51.84 2.603 53.536 ;
     RECT  0.181 55.616 2.603 55.648 ;
     RECT  2.389 57.216 2.603 60 ;
     RECT  2.283 27.328 2.627 29.984 ;
     RECT  2.539 46.528 2.629 49.632 ;
     RECT  2.483 96.32 2.667 96.352 ;
     RECT  2.347 0.704 2.675 22.304 ;
     RECT  1.715 76.992 2.675 77.024 ;
     RECT  2.339 86.72 2.675 89.184 ;
     RECT  2.483 93.888 2.723 94.752 ;
     RECT  2.629 46.528 2.731 49.696 ;
     RECT  2.731 46.528 2.771 48.928 ;
     RECT  2.603 57.792 2.771 60 ;
     RECT  2.675 86.72 2.771 87.456 ;
     RECT  2.549 73.536 2.867 73.568 ;
     RECT  2.675 0.704 2.915 14.304 ;
     RECT  2.675 15.68 2.915 21.152 ;
     RECT  2.339 24.512 2.915 24.544 ;
     RECT  2.579 39.872 2.915 40.992 ;
     RECT  2.539 43.328 2.915 44.64 ;
     RECT  2.603 51.968 2.915 53.536 ;
     RECT  2.339 83.328 2.915 85.088 ;
     RECT  2.771 87.424 2.915 87.456 ;
     RECT  2.723 94.464 2.915 94.752 ;
     RECT  2.627 27.904 2.963 29.984 ;
     RECT  2.339 37.568 3.011 37.6 ;
     RECT  2.771 47.872 3.059 48.928 ;
     RECT  1.715 78.656 3.061 80.992 ;
     RECT  2.339 100.672 3.061 101.536 ;
     RECT  2.915 17.024 3.115 20.064 ;
     RECT  3.061 78.592 3.115 80.992 ;
     RECT  3.061 99.712 3.115 101.536 ;
     RECT  2.915 0.96 3.155 14.304 ;
     RECT  3.115 99.712 3.155 99.744 ;
     RECT  2.197 34.816 3.157 34.848 ;
     RECT  2.165 62.656 3.381 64.864 ;
     RECT  1.669 68.352 3.381 68.384 ;
     RECT  3.155 0.96 3.395 6.368 ;
     RECT  3.381 62.656 3.435 68.384 ;
     RECT  3.395 0.96 3.443 6.304 ;
     RECT  3.155 7.872 3.443 14.304 ;
     RECT  2.915 15.68 3.443 15.712 ;
     RECT  2.771 57.792 3.443 58.4 ;
     RECT  3.435 63.232 3.443 68.384 ;
     RECT  3.115 79.808 3.443 79.84 ;
     RECT  2.915 53.376 3.491 53.536 ;
     RECT  3.443 7.872 3.499 7.968 ;
     RECT  3.443 9.664 3.499 14.304 ;
     RECT  2.195 70.784 3.509 71.84 ;
     RECT  3.443 0.96 3.539 5.088 ;
     RECT  3.509 70.656 3.563 71.84 ;
     RECT  2.915 83.776 3.637 85.088 ;
     RECT  3.539 0.96 3.691 4.896 ;
     RECT  3.443 63.232 3.691 66.464 ;
     RECT  3.691 63.232 3.731 64.416 ;
     RECT  2.771 59.712 3.877 60 ;
     RECT  3.877 54.08 3.893 54.112 ;
     RECT  2.963 29.44 3.925 29.984 ;
     RECT  2.291 31.552 3.925 31.968 ;
     RECT  3.893 54.08 3.947 54.752 ;
     RECT  3.877 59.712 3.957 61.088 ;
     RECT  3.563 70.656 3.957 71.776 ;
     RECT  3.115 101.44 3.957 101.536 ;
     RECT  3.115 17.536 4.011 20.064 ;
     RECT  3.925 22.848 4.011 22.88 ;
     RECT  3.957 70.08 4.011 71.776 ;
     RECT  3.957 101.44 4.011 102.048 ;
     RECT  3.499 10.816 4.019 14.304 ;
     RECT  3.731 63.232 4.019 63.328 ;
     RECT  3.397 25.472 4.165 25.504 ;
     RECT  2.963 27.904 4.165 27.936 ;
     RECT  2.771 46.528 4.213 46.56 ;
     RECT  3.059 47.872 4.213 48.48 ;
     RECT  4.213 46.528 4.267 48.48 ;
     RECT  4.213 37.888 4.277 37.92 ;
     RECT  4.011 20.032 4.309 20.064 ;
     RECT  3.957 21.376 4.309 21.408 ;
     RECT  2.915 40.128 4.331 40.16 ;
     RECT  4.261 49.984 4.331 50.016 ;
     RECT  2.675 89.152 4.357 89.184 ;
     RECT  2.821 90.752 4.357 91.36 ;
     RECT  4.309 20.032 4.395 21.408 ;
     RECT  3.925 29.44 4.453 31.968 ;
     RECT  4.453 29.44 4.523 32.16 ;
     RECT  4.011 17.536 4.595 18.272 ;
     RECT  4.595 17.536 4.597 18.144 ;
     RECT  3.637 83.776 4.597 85.536 ;
     RECT  4.597 17.024 4.651 18.144 ;
     RECT  3.157 34.624 4.691 34.848 ;
     RECT  4.019 12.16 4.693 14.304 ;
     RECT  4.597 83.776 4.693 86.048 ;
     RECT  4.651 17.152 4.779 18.144 ;
     RECT  4.019 10.816 4.789 10.848 ;
     RECT  3.691 65.856 4.837 66.464 ;
     RECT  3.443 68.288 4.837 68.32 ;
     RECT  4.693 12.16 4.843 14.624 ;
     RECT  4.213 36.48 4.853 36.512 ;
     RECT  4.277 37.888 4.853 38.112 ;
     RECT  4.693 83.776 4.885 87.264 ;
     RECT  4.853 36.48 4.907 38.112 ;
     RECT  4.837 65.856 4.907 68.32 ;
     RECT  4.885 83.648 4.971 87.264 ;
     RECT  4.357 89.152 4.971 91.36 ;
     RECT  4.789 9.792 5.027 10.848 ;
     RECT  4.837 39.936 5.077 39.968 ;
     RECT  2.915 44.608 5.077 44.64 ;
     RECT  4.267 46.528 5.077 46.816 ;
     RECT  4.277 51.328 5.077 51.36 ;
     RECT  3.781 56.384 5.077 56.416 ;
     RECT  3.443 58.368 5.077 58.4 ;
     RECT  4.597 77.824 5.077 77.856 ;
     RECT  4.971 90.752 5.077 91.36 ;
     RECT  4.165 93.44 5.077 93.472 ;
     RECT  5.077 39.168 5.163 39.968 ;
     RECT  3.691 4.288 5.171 4.32 ;
     RECT  4.165 25.472 5.171 27.936 ;
     RECT  4.523 31.936 5.171 31.968 ;
     RECT  5.109 42.112 5.171 42.144 ;
     RECT  3.947 54.72 5.171 54.752 ;
     RECT  5.171 25.472 5.267 27.296 ;
     RECT  4.523 29.44 5.267 29.664 ;
     RECT  3.691 0.96 5.315 2.784 ;
     RECT  4.019 63.232 5.317 63.264 ;
     RECT  5.077 43.84 5.365 44.64 ;
     RECT  5.077 46.464 5.365 46.816 ;
     RECT  5.077 56.384 5.413 58.4 ;
     RECT  3.957 59.712 5.413 61.664 ;
     RECT  5.365 43.84 5.419 46.816 ;
     RECT  5.419 46.464 5.459 46.816 ;
     RECT  5.413 56.384 5.483 61.664 ;
     RECT  5.483 56.384 5.493 58.656 ;
     RECT  5.461 53.952 5.547 53.984 ;
     RECT  5.493 55.872 5.547 58.656 ;
     RECT  4.011 70.08 5.621 70.112 ;
     RECT  4.011 71.616 5.621 71.776 ;
     RECT  3.499 7.872 5.653 7.904 ;
     RECT  4.789 23.872 5.653 23.904 ;
     RECT  5.557 75.136 5.653 75.168 ;
     RECT  5.621 70.08 5.699 71.776 ;
     RECT  4.267 48.448 5.747 48.48 ;
     RECT  5.547 55.872 5.747 56.672 ;
     RECT  5.699 70.72 5.747 71.776 ;
     RECT  5.077 90.752 5.747 94.496 ;
     RECT  4.691 34.624 5.749 34.656 ;
     RECT  4.907 36.48 5.803 37.088 ;
     RECT  5.653 74.816 5.813 76.256 ;
     RECT  5.749 34.176 5.843 34.656 ;
     RECT  5.749 42.752 5.843 42.784 ;
     RECT  4.843 12.48 5.989 14.624 ;
     RECT  4.907 67.84 5.989 68.32 ;
     RECT  5.317 63.232 6.005 63.712 ;
     RECT  5.653 4.864 6.037 6.176 ;
     RECT  5.653 7.872 6.037 8.032 ;
     RECT  4.907 65.856 6.059 66.464 ;
     RECT  5.989 67.84 6.059 68.896 ;
     RECT  5.813 72.896 6.059 76.384 ;
     RECT  5.483 60.672 6.083 61.664 ;
     RECT  6.059 72.896 6.083 74.528 ;
     RECT  5.027 9.792 6.133 10.72 ;
     RECT  6.037 4.864 6.187 8.032 ;
     RECT  4.779 17.344 6.517 18.144 ;
     RECT  4.395 20.032 6.517 20.064 ;
     RECT  4.395 21.376 6.517 21.408 ;
     RECT  4.971 89.152 6.517 89.184 ;
     RECT  5.989 12.48 6.571 15.392 ;
     RECT  5.803 36.48 6.571 36.512 ;
     RECT  5.315 0.96 6.611 0.992 ;
     RECT  6.187 7.872 6.611 8.032 ;
     RECT  6.517 17.344 6.611 21.408 ;
     RECT  5.653 23.488 6.611 23.904 ;
     RECT  5.267 25.472 6.611 26.72 ;
     RECT  6.325 31.36 6.611 31.392 ;
     RECT  5.843 34.624 6.611 34.656 ;
     RECT  5.749 41.088 6.611 41.12 ;
     RECT  6.059 67.84 6.611 67.872 ;
     RECT  6.611 20.032 6.659 21.408 ;
     RECT  5.747 90.752 6.659 92.384 ;
     RECT  6.611 23.488 6.757 23.52 ;
     RECT  6.133 9.472 6.803 10.72 ;
     RECT  6.059 76.224 6.805 76.384 ;
     RECT  5.077 77.824 6.805 79.136 ;
     RECT  6.659 90.752 6.827 91.36 ;
     RECT  5.747 94.016 6.827 94.496 ;
     RECT  5.077 96.32 6.827 96.352 ;
     RECT  6.757 23.296 6.891 23.52 ;
     RECT  6.803 9.472 6.899 10.592 ;
     RECT  6.571 12.48 6.899 14.112 ;
     RECT  6.659 21.376 6.899 21.408 ;
     RECT  6.611 25.472 6.899 25.888 ;
     RECT  5.077 51.328 6.899 51.616 ;
     RECT  5.653 52.992 6.899 53.024 ;
     RECT  6.005 63.232 6.899 64.096 ;
     RECT  6.059 65.856 6.899 65.888 ;
     RECT  5.747 70.72 6.899 70.752 ;
     RECT  6.083 73.792 6.899 74.528 ;
     RECT  4.011 102.016 6.899 102.048 ;
     RECT  6.899 9.472 6.947 9.952 ;
     RECT  6.891 23.488 6.947 23.52 ;
     RECT  5.163 39.168 6.947 39.2 ;
     RECT  6.805 76.224 6.947 79.136 ;
     RECT  3.925 82.112 6.997 82.144 ;
     RECT  6.947 77.504 7.029 79.136 ;
     RECT  6.997 82.112 7.083 82.336 ;
     RECT  6.611 8 7.187 8.032 ;
     RECT  5.267 29.44 7.379 29.472 ;
     RECT  6.899 25.472 7.381 25.504 ;
     RECT  6.827 94.016 7.381 94.048 ;
     RECT  7.029 77.504 7.403 79.456 ;
     RECT  6.187 4.864 7.475 6.176 ;
     RECT  7.403 78.4 7.475 78.56 ;
     RECT  4.971 83.712 7.475 85.664 ;
     RECT  5.653 99.584 7.475 99.616 ;
     RECT  7.475 84.288 7.523 85.664 ;
     RECT  5.747 56.64 7.619 56.672 ;
     RECT  6.517 89.152 7.619 89.44 ;
     RECT  6.611 17.344 7.925 18.144 ;
     RECT  6.083 60.672 7.957 61.024 ;
     RECT  6.947 9.792 8.003 9.952 ;
     RECT  7.381 93.44 8.003 94.048 ;
     RECT  7.475 78.4 8.243 78.432 ;
     RECT  7.381 25.152 8.579 25.504 ;
     RECT  6.325 33.024 8.579 33.056 ;
     RECT  6.899 64.064 8.579 64.096 ;
     RECT  7.141 81.472 8.579 81.504 ;
     RECT  7.619 89.408 8.579 89.44 ;
     RECT  7.957 60.416 9.059 61.024 ;
     RECT  7.925 17.024 9.347 18.144 ;
     RECT  7.475 5.12 9.491 6.176 ;
     RECT  8.003 9.92 9.539 9.952 ;
     RECT  7.957 30.208 9.635 30.24 ;
     RECT  5.459 46.464 9.635 46.56 ;
     RECT  9.347 18.112 9.731 18.144 ;
     RECT  9.635 46.528 9.731 46.56 ;
     RECT  9.059 60.416 9.731 60.448 ;
     RECT  6.899 51.584 10.211 51.616 ;
     RECT  6.659 20.032 10.307 20.064 ;
     RECT  5.419 44.608 10.307 44.64 ;
     RECT  5.315 2.752 10.883 2.784 ;
     RECT  9.491 6.144 10.883 6.176 ;
     RECT  6.899 12.48 10.883 12.512 ;
     RECT  8.579 25.152 10.883 25.184 ;
     RECT  5.547 58.368 10.883 58.656 ;
     RECT  9.061 81.6 10.883 81.632 ;
     RECT  7.523 85.504 10.883 85.664 ;
     RECT  6.827 91.328 10.883 91.36 ;
     RECT  8.003 93.44 10.883 93.472 ;
     RECT  7.381 102.4 10.883 102.432 ;
    LAYER M7 ;
     RECT  1.536 1.269 1.568 1.589 ;
     RECT  1.536 1.589 2.784 1.653 ;
     RECT  1.536 1.653 3.552 1.909 ;
     RECT  1.408 1.909 3.552 2.677 ;
     RECT  1.408 2.677 3.68 3.499 ;
     RECT  2.24 3.499 3.68 4.587 ;
     RECT  2.56 4.587 3.68 4.907 ;
     RECT  2.56 4.907 2.848 5.739 ;
     RECT  2.56 5.739 2.592 7.285 ;
     RECT  1.472 7.285 2.592 7.925 ;
     RECT  1.472 7.925 3.488 8.683 ;
     RECT  1.472 8.683 1.632 9.077 ;
     RECT  3.456 8.683 3.488 9.707 ;
     RECT  1.408 9.077 1.632 10.165 ;
     RECT  6.144 7.349 6.176 10.539 ;
     RECT  1.408 10.165 2.272 10.923 ;
     RECT  0.192 11.509 0.224 12.469 ;
     RECT  1.536 10.923 2.272 12.469 ;
     RECT  0.192 12.469 2.272 12.917 ;
     RECT  0.192 12.917 2.848 13.163 ;
     RECT  4.8 9.781 4.832 13.621 ;
     RECT  6.208 10.549 6.24 13.621 ;
     RECT  4.8 13.621 6.24 13.675 ;
     RECT  0.704 13.163 2.848 13.739 ;
     RECT  4.8 13.675 6.048 14.581 ;
     RECT  0.704 13.739 1.696 14.709 ;
     RECT  4.736 14.581 6.048 15.349 ;
     RECT  4.736 15.349 6.56 15.403 ;
     RECT  0.064 14.709 1.696 15.467 ;
     RECT  0.064 15.467 0.224 16.043 ;
     RECT  1.536 15.467 1.696 16.043 ;
     RECT  0.192 16.043 0.224 16.619 ;
     RECT  1.536 16.043 1.568 17.013 ;
     RECT  4.736 15.403 4.768 17.013 ;
     RECT  1.344 17.013 1.568 17.525 ;
     RECT  3.072 17.013 3.104 17.525 ;
     RECT  4.608 17.013 4.768 17.525 ;
     RECT  1.344 17.525 4.768 17.589 ;
     RECT  7.936 17.013 7.968 17.707 ;
     RECT  1.344 17.589 4.832 18.741 ;
     RECT  0.96 18.741 4.832 18.859 ;
     RECT  0.96 18.859 2.336 19.957 ;
     RECT  4.8 18.859 4.832 21.045 ;
     RECT  0.192 19.957 2.336 21.163 ;
     RECT  6.528 15.403 6.56 21.163 ;
     RECT  0.32 21.163 2.336 21.291 ;
     RECT  4.352 21.045 4.832 21.365 ;
     RECT  1.472 21.291 2.336 21.419 ;
     RECT  1.664 21.419 2.336 22.891 ;
     RECT  3.968 21.365 4.832 22.891 ;
     RECT  1.984 22.891 2.144 23.403 ;
     RECT  6.848 23.285 6.88 23.861 ;
     RECT  4.352 22.891 4.832 23.915 ;
     RECT  2.112 23.403 2.144 24.555 ;
     RECT  6.336 23.861 6.88 25.899 ;
     RECT  0.064 26.741 0.096 27.253 ;
     RECT  4.352 23.915 4.384 27.307 ;
     RECT  0.064 27.253 0.736 27.317 ;
     RECT  2.048 27.253 2.272 27.317 ;
     RECT  0.064 27.317 2.272 28.075 ;
     RECT  0.064 28.075 2.08 28.203 ;
     RECT  0.064 28.203 1.696 28.587 ;
     RECT  0.704 28.587 1.696 28.715 ;
     RECT  0.832 28.715 1.696 29.291 ;
     RECT  1.344 29.291 1.696 29.557 ;
     RECT  1.344 29.557 1.888 29.739 ;
     RECT  4.48 30.709 4.512 32.171 ;
     RECT  1.856 29.739 1.888 32.437 ;
     RECT  1.856 32.437 2.272 32.491 ;
     RECT  6.336 25.899 6.368 33.013 ;
     RECT  0.192 32.437 0.224 33.707 ;
     RECT  6.336 33.013 6.56 34.165 ;
     RECT  2.24 32.491 2.272 34.859 ;
     RECT  5.76 34.165 6.56 36.523 ;
     RECT  4.224 36.469 4.256 36.981 ;
     RECT  5.76 36.523 5.792 36.981 ;
     RECT  4.224 36.981 5.792 37.931 ;
     RECT  0.192 37.429 0.224 38.251 ;
     RECT  1.664 38.389 1.696 39.221 ;
     RECT  0.192 41.269 0.224 41.333 ;
     RECT  1.536 39.221 1.696 41.333 ;
     RECT  4.288 37.931 5.792 42.155 ;
     RECT  0.192 41.333 1.696 42.165 ;
     RECT  0.192 42.165 1.952 42.795 ;
     RECT  5.76 42.155 5.792 42.795 ;
     RECT  0.704 42.795 1.952 43.499 ;
     RECT  0.832 43.499 1.952 43.627 ;
     RECT  4.288 42.155 4.32 43.829 ;
     RECT  1.92 43.627 1.952 44.075 ;
     RECT  2.496 45.301 2.528 45.493 ;
     RECT  1.728 45.493 2.528 46.571 ;
     RECT  1.728 46.571 1.76 46.827 ;
     RECT  4.288 43.829 5.408 46.827 ;
     RECT  4.288 46.827 4.32 47.797 ;
     RECT  4.224 47.797 4.32 48.491 ;
     RECT  1.664 48.245 1.696 48.885 ;
     RECT  1.664 48.885 2.72 49.643 ;
     RECT  2.688 49.643 2.72 49.707 ;
     RECT  4.288 48.491 4.32 51.371 ;
     RECT  1.664 51.253 1.696 51.829 ;
     RECT  1.664 51.829 2.592 52.011 ;
     RECT  0.192 52.789 0.224 53.611 ;
     RECT  3.904 54.069 3.936 54.763 ;
     RECT  5.504 53.941 5.536 57.515 ;
     RECT  2.56 52.011 2.592 58.923 ;
     RECT  1.984 58.933 2.016 59.883 ;
     RECT  3.968 60.917 4 61.675 ;
     RECT  2.176 62.645 3.424 63.339 ;
     RECT  5.44 57.525 5.472 63.723 ;
     RECT  2.176 63.339 2.208 63.915 ;
     RECT  0.192 62.773 0.224 64.491 ;
     RECT  3.648 64.373 3.68 64.821 ;
     RECT  3.392 64.821 3.68 64.875 ;
     RECT  6.016 64.053 6.048 66.101 ;
     RECT  3.392 64.875 3.424 67.307 ;
     RECT  4.864 66.101 6.048 67.883 ;
     RECT  6.016 67.883 6.048 70.069 ;
     RECT  3.968 70.069 4 70.645 ;
     RECT  3.52 70.645 4 70.763 ;
     RECT  5.632 70.069 6.048 70.763 ;
     RECT  0.192 69.109 0.224 71.851 ;
     RECT  1.536 71.221 1.568 71.851 ;
     RECT  3.52 70.763 3.552 71.851 ;
     RECT  6.016 70.763 6.048 72.885 ;
     RECT  1.664 72.181 1.696 73.525 ;
     RECT  1.664 73.525 2.592 74.155 ;
     RECT  5.824 72.885 6.048 75.125 ;
     RECT  5.696 75.125 6.048 75.179 ;
     RECT  5.696 75.179 5.856 76.395 ;
     RECT  2.56 74.155 2.592 76.981 ;
     RECT  2.432 76.981 2.592 77.035 ;
     RECT  5.696 76.395 5.728 77.813 ;
     RECT  7.36 77.493 7.392 77.813 ;
     RECT  5.696 77.813 7.392 77.867 ;
     RECT  2.432 77.035 2.464 78.005 ;
     RECT  1.664 78.005 2.464 78.581 ;
     RECT  1.664 78.581 3.104 78.827 ;
     RECT  6.528 77.867 7.392 79.467 ;
     RECT  2.816 78.827 3.104 80.309 ;
     RECT  1.664 80.309 3.104 80.939 ;
     RECT  0.192 79.733 0.224 81.003 ;
     RECT  1.664 80.939 2.848 81.003 ;
     RECT  1.664 81.003 1.696 81.579 ;
     RECT  2.048 82.613 2.08 82.869 ;
     RECT  1.664 82.869 2.08 83.189 ;
     RECT  0.064 82.613 0.096 83.819 ;
     RECT  6.528 79.467 7.072 84.459 ;
     RECT  4.928 83.637 4.96 84.789 ;
     RECT  1.664 83.189 2.272 84.971 ;
     RECT  2.048 84.971 2.272 85.099 ;
     RECT  3.648 84.789 4.96 85.547 ;
     RECT  0.192 87.157 0.224 88.117 ;
     RECT  0.192 88.117 0.352 88.427 ;
     RECT  2.24 85.099 2.272 88.501 ;
     RECT  0.32 88.427 0.352 88.629 ;
     RECT  1.664 88.501 2.272 88.629 ;
     RECT  0.32 88.629 2.272 89.131 ;
     RECT  6.528 84.459 6.56 89.397 ;
     RECT  6.528 89.397 6.816 89.451 ;
     RECT  0.32 89.131 1.696 89.579 ;
     RECT  4.928 85.547 4.96 89.643 ;
     RECT  0.32 89.579 1.504 90.037 ;
     RECT  0.192 90.037 1.504 91.243 ;
     RECT  0.32 91.243 1.504 91.573 ;
     RECT  0.32 91.573 2.016 91.819 ;
     RECT  0.32 91.819 0.352 92.395 ;
     RECT  1.984 91.819 2.016 93.877 ;
     RECT  1.984 93.877 2.656 94.005 ;
     RECT  1.536 94.005 2.656 94.763 ;
     RECT  1.664 94.763 2.656 96.363 ;
     RECT  6.784 89.451 6.816 96.363 ;
     RECT  0.832 97.397 0.864 97.845 ;
     RECT  0.704 97.845 0.864 98.667 ;
     RECT  1.664 99.061 1.696 99.819 ;
     RECT  3.072 99.701 3.104 100.661 ;
     RECT  1.92 100.661 3.104 100.715 ;
     RECT  3.968 101.429 4 102.059 ;
     RECT  1.92 100.715 1.952 102.315 ;
     RECT  1.984 102.389 2.016 103.787 ;
     RECT  0.192 103.861 0.224 104.939 ;
     RECT  1.6 104.053 1.632 104.939 ;
  END
END ot_attn_bank_ew544
END LIBRARY
